# Placeholder macro written by tools/chip_assembly/macros.py
# kind: collective; the die assembly's one-shot collective engine block (0.9 x 0.4424 mm) at 1/4; records of 32 x CL_LANES + 3 + CL_TAGW = 547 bits (ot_chip_v41x_die CL_PW), 512-bit link flits
VERSION 5.7 ;
BUSBITCHARS "[]" ;
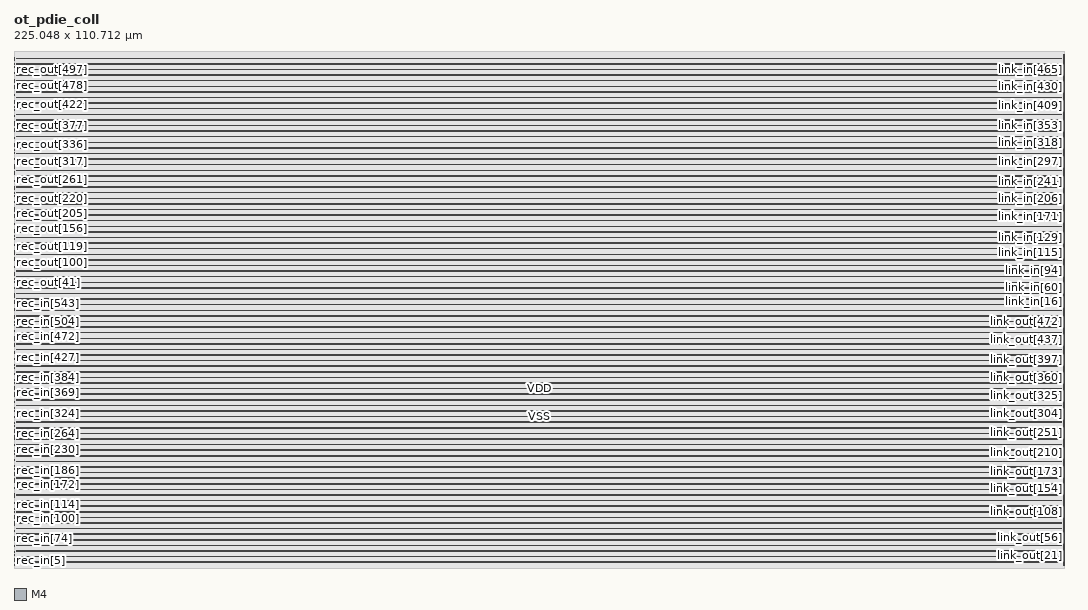
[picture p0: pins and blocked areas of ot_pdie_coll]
MACRO ot_pdie_coll
  FOREIGN ot_pdie_coll 0 0 ;
  SYMMETRY X Y ;
  SIZE 225.048 BY 110.712 ;
  CLASS BLOCK ;
  PIN clk
    DIRECTION INPUT ;
    USE SIGNAL ;
    SHAPE ABUTMENT ;
    PORT
      LAYER M4 ;
      RECT 0.000 0.528 0.192 0.552 ;
    END
  END clk
  PIN rec_in[0]
    DIRECTION INPUT ;
    USE SIGNAL ;
    SHAPE ABUTMENT ;
    PORT
      LAYER M4 ;
      RECT 0.000 0.624 0.192 0.648 ;
    END
  END rec_in[0]
  PIN rec_in[1]
    DIRECTION INPUT ;
    USE SIGNAL ;
    SHAPE ABUTMENT ;
    PORT
      LAYER M4 ;
      RECT 0.000 0.720 0.192 0.744 ;
    END
  END rec_in[1]
  PIN rec_in[2]
    DIRECTION INPUT ;
    USE SIGNAL ;
    SHAPE ABUTMENT ;
    PORT
      LAYER M4 ;
      RECT 0.000 0.816 0.192 0.840 ;
    END
  END rec_in[2]
  PIN rec_in[3]
    DIRECTION INPUT ;
    USE SIGNAL ;
    SHAPE ABUTMENT ;
    PORT
      LAYER M4 ;
      RECT 0.000 0.912 0.192 0.936 ;
    END
  END rec_in[3]
  PIN rec_in[4]
    DIRECTION INPUT ;
    USE SIGNAL ;
    SHAPE ABUTMENT ;
    PORT
      LAYER M4 ;
      RECT 0.000 1.008 0.192 1.032 ;
    END
  END rec_in[4]
  PIN rec_in[5]
    DIRECTION INPUT ;
    USE SIGNAL ;
    SHAPE ABUTMENT ;
    PORT
      LAYER M4 ;
      RECT 0.000 1.104 0.192 1.128 ;
    END
  END rec_in[5]
  PIN rec_in[6]
    DIRECTION INPUT ;
    USE SIGNAL ;
    SHAPE ABUTMENT ;
    PORT
      LAYER M4 ;
      RECT 0.000 1.200 0.192 1.224 ;
    END
  END rec_in[6]
  PIN rec_in[7]
    DIRECTION INPUT ;
    USE SIGNAL ;
    SHAPE ABUTMENT ;
    PORT
      LAYER M4 ;
      RECT 0.000 1.296 0.192 1.320 ;
    END
  END rec_in[7]
  PIN rec_in[8]
    DIRECTION INPUT ;
    USE SIGNAL ;
    SHAPE ABUTMENT ;
    PORT
      LAYER M4 ;
      RECT 0.000 1.392 0.192 1.416 ;
    END
  END rec_in[8]
  PIN rec_in[9]
    DIRECTION INPUT ;
    USE SIGNAL ;
    SHAPE ABUTMENT ;
    PORT
      LAYER M4 ;
      RECT 0.000 1.488 0.192 1.512 ;
    END
  END rec_in[9]
  PIN rec_in[10]
    DIRECTION INPUT ;
    USE SIGNAL ;
    SHAPE ABUTMENT ;
    PORT
      LAYER M4 ;
      RECT 0.000 1.584 0.192 1.608 ;
    END
  END rec_in[10]
  PIN rec_in[11]
    DIRECTION INPUT ;
    USE SIGNAL ;
    SHAPE ABUTMENT ;
    PORT
      LAYER M4 ;
      RECT 0.000 1.728 0.192 1.752 ;
    END
  END rec_in[11]
  PIN rec_in[12]
    DIRECTION INPUT ;
    USE SIGNAL ;
    SHAPE ABUTMENT ;
    PORT
      LAYER M4 ;
      RECT 0.000 1.824 0.192 1.848 ;
    END
  END rec_in[12]
  PIN rec_in[13]
    DIRECTION INPUT ;
    USE SIGNAL ;
    SHAPE ABUTMENT ;
    PORT
      LAYER M4 ;
      RECT 0.000 1.920 0.192 1.944 ;
    END
  END rec_in[13]
  PIN rec_in[14]
    DIRECTION INPUT ;
    USE SIGNAL ;
    SHAPE ABUTMENT ;
    PORT
      LAYER M4 ;
      RECT 0.000 2.016 0.192 2.040 ;
    END
  END rec_in[14]
  PIN rec_in[15]
    DIRECTION INPUT ;
    USE SIGNAL ;
    SHAPE ABUTMENT ;
    PORT
      LAYER M4 ;
      RECT 0.000 2.112 0.192 2.136 ;
    END
  END rec_in[15]
  PIN rec_in[16]
    DIRECTION INPUT ;
    USE SIGNAL ;
    SHAPE ABUTMENT ;
    PORT
      LAYER M4 ;
      RECT 0.000 2.208 0.192 2.232 ;
    END
  END rec_in[16]
  PIN rec_in[17]
    DIRECTION INPUT ;
    USE SIGNAL ;
    SHAPE ABUTMENT ;
    PORT
      LAYER M4 ;
      RECT 0.000 2.304 0.192 2.328 ;
    END
  END rec_in[17]
  PIN rec_in[18]
    DIRECTION INPUT ;
    USE SIGNAL ;
    SHAPE ABUTMENT ;
    PORT
      LAYER M4 ;
      RECT 0.000 2.400 0.192 2.424 ;
    END
  END rec_in[18]
  PIN rec_in[19]
    DIRECTION INPUT ;
    USE SIGNAL ;
    SHAPE ABUTMENT ;
    PORT
      LAYER M4 ;
      RECT 0.000 2.496 0.192 2.520 ;
    END
  END rec_in[19]
  PIN rec_in[20]
    DIRECTION INPUT ;
    USE SIGNAL ;
    SHAPE ABUTMENT ;
    PORT
      LAYER M4 ;
      RECT 0.000 2.592 0.192 2.616 ;
    END
  END rec_in[20]
  PIN rec_in[21]
    DIRECTION INPUT ;
    USE SIGNAL ;
    SHAPE ABUTMENT ;
    PORT
      LAYER M4 ;
      RECT 0.000 2.688 0.192 2.712 ;
    END
  END rec_in[21]
  PIN rec_in[22]
    DIRECTION INPUT ;
    USE SIGNAL ;
    SHAPE ABUTMENT ;
    PORT
      LAYER M4 ;
      RECT 0.000 2.784 0.192 2.808 ;
    END
  END rec_in[22]
  PIN rec_in[23]
    DIRECTION INPUT ;
    USE SIGNAL ;
    SHAPE ABUTMENT ;
    PORT
      LAYER M4 ;
      RECT 0.000 2.928 0.192 2.952 ;
    END
  END rec_in[23]
  PIN rec_in[24]
    DIRECTION INPUT ;
    USE SIGNAL ;
    SHAPE ABUTMENT ;
    PORT
      LAYER M4 ;
      RECT 0.000 3.024 0.192 3.048 ;
    END
  END rec_in[24]
  PIN rec_in[25]
    DIRECTION INPUT ;
    USE SIGNAL ;
    SHAPE ABUTMENT ;
    PORT
      LAYER M4 ;
      RECT 0.000 3.120 0.192 3.144 ;
    END
  END rec_in[25]
  PIN rec_in[26]
    DIRECTION INPUT ;
    USE SIGNAL ;
    SHAPE ABUTMENT ;
    PORT
      LAYER M4 ;
      RECT 0.000 3.216 0.192 3.240 ;
    END
  END rec_in[26]
  PIN rec_in[27]
    DIRECTION INPUT ;
    USE SIGNAL ;
    SHAPE ABUTMENT ;
    PORT
      LAYER M4 ;
      RECT 0.000 3.312 0.192 3.336 ;
    END
  END rec_in[27]
  PIN rec_in[28]
    DIRECTION INPUT ;
    USE SIGNAL ;
    SHAPE ABUTMENT ;
    PORT
      LAYER M4 ;
      RECT 0.000 3.408 0.192 3.432 ;
    END
  END rec_in[28]
  PIN rec_in[29]
    DIRECTION INPUT ;
    USE SIGNAL ;
    SHAPE ABUTMENT ;
    PORT
      LAYER M4 ;
      RECT 0.000 3.504 0.192 3.528 ;
    END
  END rec_in[29]
  PIN rec_in[30]
    DIRECTION INPUT ;
    USE SIGNAL ;
    SHAPE ABUTMENT ;
    PORT
      LAYER M4 ;
      RECT 0.000 3.600 0.192 3.624 ;
    END
  END rec_in[30]
  PIN rec_in[31]
    DIRECTION INPUT ;
    USE SIGNAL ;
    SHAPE ABUTMENT ;
    PORT
      LAYER M4 ;
      RECT 0.000 3.696 0.192 3.720 ;
    END
  END rec_in[31]
  PIN rec_in[32]
    DIRECTION INPUT ;
    USE SIGNAL ;
    SHAPE ABUTMENT ;
    PORT
      LAYER M4 ;
      RECT 0.000 3.792 0.192 3.816 ;
    END
  END rec_in[32]
  PIN rec_in[33]
    DIRECTION INPUT ;
    USE SIGNAL ;
    SHAPE ABUTMENT ;
    PORT
      LAYER M4 ;
      RECT 0.000 3.888 0.192 3.912 ;
    END
  END rec_in[33]
  PIN rec_in[34]
    DIRECTION INPUT ;
    USE SIGNAL ;
    SHAPE ABUTMENT ;
    PORT
      LAYER M4 ;
      RECT 0.000 4.032 0.192 4.056 ;
    END
  END rec_in[34]
  PIN rec_in[35]
    DIRECTION INPUT ;
    USE SIGNAL ;
    SHAPE ABUTMENT ;
    PORT
      LAYER M4 ;
      RECT 0.000 4.128 0.192 4.152 ;
    END
  END rec_in[35]
  PIN rec_in[36]
    DIRECTION INPUT ;
    USE SIGNAL ;
    SHAPE ABUTMENT ;
    PORT
      LAYER M4 ;
      RECT 0.000 4.224 0.192 4.248 ;
    END
  END rec_in[36]
  PIN rec_in[37]
    DIRECTION INPUT ;
    USE SIGNAL ;
    SHAPE ABUTMENT ;
    PORT
      LAYER M4 ;
      RECT 0.000 4.320 0.192 4.344 ;
    END
  END rec_in[37]
  PIN rec_in[38]
    DIRECTION INPUT ;
    USE SIGNAL ;
    SHAPE ABUTMENT ;
    PORT
      LAYER M4 ;
      RECT 0.000 4.416 0.192 4.440 ;
    END
  END rec_in[38]
  PIN rec_in[39]
    DIRECTION INPUT ;
    USE SIGNAL ;
    SHAPE ABUTMENT ;
    PORT
      LAYER M4 ;
      RECT 0.000 4.512 0.192 4.536 ;
    END
  END rec_in[39]
  PIN rec_in[40]
    DIRECTION INPUT ;
    USE SIGNAL ;
    SHAPE ABUTMENT ;
    PORT
      LAYER M4 ;
      RECT 0.000 4.608 0.192 4.632 ;
    END
  END rec_in[40]
  PIN rec_in[41]
    DIRECTION INPUT ;
    USE SIGNAL ;
    SHAPE ABUTMENT ;
    PORT
      LAYER M4 ;
      RECT 0.000 4.704 0.192 4.728 ;
    END
  END rec_in[41]
  PIN rec_in[42]
    DIRECTION INPUT ;
    USE SIGNAL ;
    SHAPE ABUTMENT ;
    PORT
      LAYER M4 ;
      RECT 0.000 4.800 0.192 4.824 ;
    END
  END rec_in[42]
  PIN rec_in[43]
    DIRECTION INPUT ;
    USE SIGNAL ;
    SHAPE ABUTMENT ;
    PORT
      LAYER M4 ;
      RECT 0.000 4.896 0.192 4.920 ;
    END
  END rec_in[43]
  PIN rec_in[44]
    DIRECTION INPUT ;
    USE SIGNAL ;
    SHAPE ABUTMENT ;
    PORT
      LAYER M4 ;
      RECT 0.000 4.992 0.192 5.016 ;
    END
  END rec_in[44]
  PIN rec_in[45]
    DIRECTION INPUT ;
    USE SIGNAL ;
    SHAPE ABUTMENT ;
    PORT
      LAYER M4 ;
      RECT 0.000 5.088 0.192 5.112 ;
    END
  END rec_in[45]
  PIN rec_in[46]
    DIRECTION INPUT ;
    USE SIGNAL ;
    SHAPE ABUTMENT ;
    PORT
      LAYER M4 ;
      RECT 0.000 5.232 0.192 5.256 ;
    END
  END rec_in[46]
  PIN rec_in[47]
    DIRECTION INPUT ;
    USE SIGNAL ;
    SHAPE ABUTMENT ;
    PORT
      LAYER M4 ;
      RECT 0.000 5.328 0.192 5.352 ;
    END
  END rec_in[47]
  PIN rec_in[48]
    DIRECTION INPUT ;
    USE SIGNAL ;
    SHAPE ABUTMENT ;
    PORT
      LAYER M4 ;
      RECT 0.000 5.424 0.192 5.448 ;
    END
  END rec_in[48]
  PIN rec_in[49]
    DIRECTION INPUT ;
    USE SIGNAL ;
    SHAPE ABUTMENT ;
    PORT
      LAYER M4 ;
      RECT 0.000 5.520 0.192 5.544 ;
    END
  END rec_in[49]
  PIN rec_in[50]
    DIRECTION INPUT ;
    USE SIGNAL ;
    SHAPE ABUTMENT ;
    PORT
      LAYER M4 ;
      RECT 0.000 5.616 0.192 5.640 ;
    END
  END rec_in[50]
  PIN rec_in[51]
    DIRECTION INPUT ;
    USE SIGNAL ;
    SHAPE ABUTMENT ;
    PORT
      LAYER M4 ;
      RECT 0.000 5.712 0.192 5.736 ;
    END
  END rec_in[51]
  PIN rec_in[52]
    DIRECTION INPUT ;
    USE SIGNAL ;
    SHAPE ABUTMENT ;
    PORT
      LAYER M4 ;
      RECT 0.000 5.808 0.192 5.832 ;
    END
  END rec_in[52]
  PIN rec_in[53]
    DIRECTION INPUT ;
    USE SIGNAL ;
    SHAPE ABUTMENT ;
    PORT
      LAYER M4 ;
      RECT 0.000 5.904 0.192 5.928 ;
    END
  END rec_in[53]
  PIN rec_in[54]
    DIRECTION INPUT ;
    USE SIGNAL ;
    SHAPE ABUTMENT ;
    PORT
      LAYER M4 ;
      RECT 0.000 6.000 0.192 6.024 ;
    END
  END rec_in[54]
  PIN rec_in[55]
    DIRECTION INPUT ;
    USE SIGNAL ;
    SHAPE ABUTMENT ;
    PORT
      LAYER M4 ;
      RECT 0.000 6.096 0.192 6.120 ;
    END
  END rec_in[55]
  PIN rec_in[56]
    DIRECTION INPUT ;
    USE SIGNAL ;
    SHAPE ABUTMENT ;
    PORT
      LAYER M4 ;
      RECT 0.000 6.192 0.192 6.216 ;
    END
  END rec_in[56]
  PIN rec_in[57]
    DIRECTION INPUT ;
    USE SIGNAL ;
    SHAPE ABUTMENT ;
    PORT
      LAYER M4 ;
      RECT 0.000 6.336 0.192 6.360 ;
    END
  END rec_in[57]
  PIN rec_in[58]
    DIRECTION INPUT ;
    USE SIGNAL ;
    SHAPE ABUTMENT ;
    PORT
      LAYER M4 ;
      RECT 0.000 6.432 0.192 6.456 ;
    END
  END rec_in[58]
  PIN rec_in[59]
    DIRECTION INPUT ;
    USE SIGNAL ;
    SHAPE ABUTMENT ;
    PORT
      LAYER M4 ;
      RECT 0.000 6.528 0.192 6.552 ;
    END
  END rec_in[59]
  PIN rec_in[60]
    DIRECTION INPUT ;
    USE SIGNAL ;
    SHAPE ABUTMENT ;
    PORT
      LAYER M4 ;
      RECT 0.000 6.624 0.192 6.648 ;
    END
  END rec_in[60]
  PIN rec_in[61]
    DIRECTION INPUT ;
    USE SIGNAL ;
    SHAPE ABUTMENT ;
    PORT
      LAYER M4 ;
      RECT 0.000 6.720 0.192 6.744 ;
    END
  END rec_in[61]
  PIN rec_in[62]
    DIRECTION INPUT ;
    USE SIGNAL ;
    SHAPE ABUTMENT ;
    PORT
      LAYER M4 ;
      RECT 0.000 6.816 0.192 6.840 ;
    END
  END rec_in[62]
  PIN rec_in[63]
    DIRECTION INPUT ;
    USE SIGNAL ;
    SHAPE ABUTMENT ;
    PORT
      LAYER M4 ;
      RECT 0.000 6.912 0.192 6.936 ;
    END
  END rec_in[63]
  PIN rec_in[64]
    DIRECTION INPUT ;
    USE SIGNAL ;
    SHAPE ABUTMENT ;
    PORT
      LAYER M4 ;
      RECT 0.000 7.008 0.192 7.032 ;
    END
  END rec_in[64]
  PIN rec_in[65]
    DIRECTION INPUT ;
    USE SIGNAL ;
    SHAPE ABUTMENT ;
    PORT
      LAYER M4 ;
      RECT 0.000 7.104 0.192 7.128 ;
    END
  END rec_in[65]
  PIN rec_in[66]
    DIRECTION INPUT ;
    USE SIGNAL ;
    SHAPE ABUTMENT ;
    PORT
      LAYER M4 ;
      RECT 0.000 7.200 0.192 7.224 ;
    END
  END rec_in[66]
  PIN rec_in[67]
    DIRECTION INPUT ;
    USE SIGNAL ;
    SHAPE ABUTMENT ;
    PORT
      LAYER M4 ;
      RECT 0.000 7.296 0.192 7.320 ;
    END
  END rec_in[67]
  PIN rec_in[68]
    DIRECTION INPUT ;
    USE SIGNAL ;
    SHAPE ABUTMENT ;
    PORT
      LAYER M4 ;
      RECT 0.000 7.392 0.192 7.416 ;
    END
  END rec_in[68]
  PIN rec_in[69]
    DIRECTION INPUT ;
    USE SIGNAL ;
    SHAPE ABUTMENT ;
    PORT
      LAYER M4 ;
      RECT 0.000 7.536 0.192 7.560 ;
    END
  END rec_in[69]
  PIN rec_in[70]
    DIRECTION INPUT ;
    USE SIGNAL ;
    SHAPE ABUTMENT ;
    PORT
      LAYER M4 ;
      RECT 0.000 7.632 0.192 7.656 ;
    END
  END rec_in[70]
  PIN rec_in[71]
    DIRECTION INPUT ;
    USE SIGNAL ;
    SHAPE ABUTMENT ;
    PORT
      LAYER M4 ;
      RECT 0.000 7.728 0.192 7.752 ;
    END
  END rec_in[71]
  PIN rec_in[72]
    DIRECTION INPUT ;
    USE SIGNAL ;
    SHAPE ABUTMENT ;
    PORT
      LAYER M4 ;
      RECT 0.000 7.824 0.192 7.848 ;
    END
  END rec_in[72]
  PIN rec_in[73]
    DIRECTION INPUT ;
    USE SIGNAL ;
    SHAPE ABUTMENT ;
    PORT
      LAYER M4 ;
      RECT 0.000 7.920 0.192 7.944 ;
    END
  END rec_in[73]
  PIN rec_in[74]
    DIRECTION INPUT ;
    USE SIGNAL ;
    SHAPE ABUTMENT ;
    PORT
      LAYER M4 ;
      RECT 0.000 8.016 0.192 8.040 ;
    END
  END rec_in[74]
  PIN rec_in[75]
    DIRECTION INPUT ;
    USE SIGNAL ;
    SHAPE ABUTMENT ;
    PORT
      LAYER M4 ;
      RECT 0.000 8.112 0.192 8.136 ;
    END
  END rec_in[75]
  PIN rec_in[76]
    DIRECTION INPUT ;
    USE SIGNAL ;
    SHAPE ABUTMENT ;
    PORT
      LAYER M4 ;
      RECT 0.000 8.208 0.192 8.232 ;
    END
  END rec_in[76]
  PIN rec_in[77]
    DIRECTION INPUT ;
    USE SIGNAL ;
    SHAPE ABUTMENT ;
    PORT
      LAYER M4 ;
      RECT 0.000 8.304 0.192 8.328 ;
    END
  END rec_in[77]
  PIN rec_in[78]
    DIRECTION INPUT ;
    USE SIGNAL ;
    SHAPE ABUTMENT ;
    PORT
      LAYER M4 ;
      RECT 0.000 8.400 0.192 8.424 ;
    END
  END rec_in[78]
  PIN rec_in[79]
    DIRECTION INPUT ;
    USE SIGNAL ;
    SHAPE ABUTMENT ;
    PORT
      LAYER M4 ;
      RECT 0.000 8.496 0.192 8.520 ;
    END
  END rec_in[79]
  PIN rec_in[80]
    DIRECTION INPUT ;
    USE SIGNAL ;
    SHAPE ABUTMENT ;
    PORT
      LAYER M4 ;
      RECT 0.000 8.640 0.192 8.664 ;
    END
  END rec_in[80]
  PIN rec_in[81]
    DIRECTION INPUT ;
    USE SIGNAL ;
    SHAPE ABUTMENT ;
    PORT
      LAYER M4 ;
      RECT 0.000 8.736 0.192 8.760 ;
    END
  END rec_in[81]
  PIN rec_in[82]
    DIRECTION INPUT ;
    USE SIGNAL ;
    SHAPE ABUTMENT ;
    PORT
      LAYER M4 ;
      RECT 0.000 8.832 0.192 8.856 ;
    END
  END rec_in[82]
  PIN rec_in[83]
    DIRECTION INPUT ;
    USE SIGNAL ;
    SHAPE ABUTMENT ;
    PORT
      LAYER M4 ;
      RECT 0.000 8.928 0.192 8.952 ;
    END
  END rec_in[83]
  PIN rec_in[84]
    DIRECTION INPUT ;
    USE SIGNAL ;
    SHAPE ABUTMENT ;
    PORT
      LAYER M4 ;
      RECT 0.000 9.024 0.192 9.048 ;
    END
  END rec_in[84]
  PIN rec_in[85]
    DIRECTION INPUT ;
    USE SIGNAL ;
    SHAPE ABUTMENT ;
    PORT
      LAYER M4 ;
      RECT 0.000 9.120 0.192 9.144 ;
    END
  END rec_in[85]
  PIN rec_in[86]
    DIRECTION INPUT ;
    USE SIGNAL ;
    SHAPE ABUTMENT ;
    PORT
      LAYER M4 ;
      RECT 0.000 9.216 0.192 9.240 ;
    END
  END rec_in[86]
  PIN rec_in[87]
    DIRECTION INPUT ;
    USE SIGNAL ;
    SHAPE ABUTMENT ;
    PORT
      LAYER M4 ;
      RECT 0.000 9.312 0.192 9.336 ;
    END
  END rec_in[87]
  PIN rec_in[88]
    DIRECTION INPUT ;
    USE SIGNAL ;
    SHAPE ABUTMENT ;
    PORT
      LAYER M4 ;
      RECT 0.000 9.408 0.192 9.432 ;
    END
  END rec_in[88]
  PIN rec_in[89]
    DIRECTION INPUT ;
    USE SIGNAL ;
    SHAPE ABUTMENT ;
    PORT
      LAYER M4 ;
      RECT 0.000 9.504 0.192 9.528 ;
    END
  END rec_in[89]
  PIN rec_in[90]
    DIRECTION INPUT ;
    USE SIGNAL ;
    SHAPE ABUTMENT ;
    PORT
      LAYER M4 ;
      RECT 0.000 9.600 0.192 9.624 ;
    END
  END rec_in[90]
  PIN rec_in[91]
    DIRECTION INPUT ;
    USE SIGNAL ;
    SHAPE ABUTMENT ;
    PORT
      LAYER M4 ;
      RECT 0.000 9.696 0.192 9.720 ;
    END
  END rec_in[91]
  PIN rec_in[92]
    DIRECTION INPUT ;
    USE SIGNAL ;
    SHAPE ABUTMENT ;
    PORT
      LAYER M4 ;
      RECT 0.000 9.840 0.192 9.864 ;
    END
  END rec_in[92]
  PIN rec_in[93]
    DIRECTION INPUT ;
    USE SIGNAL ;
    SHAPE ABUTMENT ;
    PORT
      LAYER M4 ;
      RECT 0.000 9.936 0.192 9.960 ;
    END
  END rec_in[93]
  PIN rec_in[94]
    DIRECTION INPUT ;
    USE SIGNAL ;
    SHAPE ABUTMENT ;
    PORT
      LAYER M4 ;
      RECT 0.000 10.032 0.192 10.056 ;
    END
  END rec_in[94]
  PIN rec_in[95]
    DIRECTION INPUT ;
    USE SIGNAL ;
    SHAPE ABUTMENT ;
    PORT
      LAYER M4 ;
      RECT 0.000 10.128 0.192 10.152 ;
    END
  END rec_in[95]
  PIN rec_in[96]
    DIRECTION INPUT ;
    USE SIGNAL ;
    SHAPE ABUTMENT ;
    PORT
      LAYER M4 ;
      RECT 0.000 10.224 0.192 10.248 ;
    END
  END rec_in[96]
  PIN rec_in[97]
    DIRECTION INPUT ;
    USE SIGNAL ;
    SHAPE ABUTMENT ;
    PORT
      LAYER M4 ;
      RECT 0.000 10.320 0.192 10.344 ;
    END
  END rec_in[97]
  PIN rec_in[98]
    DIRECTION INPUT ;
    USE SIGNAL ;
    SHAPE ABUTMENT ;
    PORT
      LAYER M4 ;
      RECT 0.000 10.416 0.192 10.440 ;
    END
  END rec_in[98]
  PIN rec_in[99]
    DIRECTION INPUT ;
    USE SIGNAL ;
    SHAPE ABUTMENT ;
    PORT
      LAYER M4 ;
      RECT 0.000 10.512 0.192 10.536 ;
    END
  END rec_in[99]
  PIN rec_in[100]
    DIRECTION INPUT ;
    USE SIGNAL ;
    SHAPE ABUTMENT ;
    PORT
      LAYER M4 ;
      RECT 0.000 10.608 0.192 10.632 ;
    END
  END rec_in[100]
  PIN rec_in[101]
    DIRECTION INPUT ;
    USE SIGNAL ;
    SHAPE ABUTMENT ;
    PORT
      LAYER M4 ;
      RECT 0.000 10.704 0.192 10.728 ;
    END
  END rec_in[101]
  PIN rec_in[102]
    DIRECTION INPUT ;
    USE SIGNAL ;
    SHAPE ABUTMENT ;
    PORT
      LAYER M4 ;
      RECT 0.000 10.800 0.192 10.824 ;
    END
  END rec_in[102]
  PIN rec_in[103]
    DIRECTION INPUT ;
    USE SIGNAL ;
    SHAPE ABUTMENT ;
    PORT
      LAYER M4 ;
      RECT 0.000 10.944 0.192 10.968 ;
    END
  END rec_in[103]
  PIN rec_in[104]
    DIRECTION INPUT ;
    USE SIGNAL ;
    SHAPE ABUTMENT ;
    PORT
      LAYER M4 ;
      RECT 0.000 11.040 0.192 11.064 ;
    END
  END rec_in[104]
  PIN rec_in[105]
    DIRECTION INPUT ;
    USE SIGNAL ;
    SHAPE ABUTMENT ;
    PORT
      LAYER M4 ;
      RECT 0.000 11.136 0.192 11.160 ;
    END
  END rec_in[105]
  PIN rec_in[106]
    DIRECTION INPUT ;
    USE SIGNAL ;
    SHAPE ABUTMENT ;
    PORT
      LAYER M4 ;
      RECT 0.000 11.232 0.192 11.256 ;
    END
  END rec_in[106]
  PIN rec_in[107]
    DIRECTION INPUT ;
    USE SIGNAL ;
    SHAPE ABUTMENT ;
    PORT
      LAYER M4 ;
      RECT 0.000 11.328 0.192 11.352 ;
    END
  END rec_in[107]
  PIN rec_in[108]
    DIRECTION INPUT ;
    USE SIGNAL ;
    SHAPE ABUTMENT ;
    PORT
      LAYER M4 ;
      RECT 0.000 11.424 0.192 11.448 ;
    END
  END rec_in[108]
  PIN rec_in[109]
    DIRECTION INPUT ;
    USE SIGNAL ;
    SHAPE ABUTMENT ;
    PORT
      LAYER M4 ;
      RECT 0.000 11.520 0.192 11.544 ;
    END
  END rec_in[109]
  PIN rec_in[110]
    DIRECTION INPUT ;
    USE SIGNAL ;
    SHAPE ABUTMENT ;
    PORT
      LAYER M4 ;
      RECT 0.000 11.616 0.192 11.640 ;
    END
  END rec_in[110]
  PIN rec_in[111]
    DIRECTION INPUT ;
    USE SIGNAL ;
    SHAPE ABUTMENT ;
    PORT
      LAYER M4 ;
      RECT 0.000 11.712 0.192 11.736 ;
    END
  END rec_in[111]
  PIN rec_in[112]
    DIRECTION INPUT ;
    USE SIGNAL ;
    SHAPE ABUTMENT ;
    PORT
      LAYER M4 ;
      RECT 0.000 11.808 0.192 11.832 ;
    END
  END rec_in[112]
  PIN rec_in[113]
    DIRECTION INPUT ;
    USE SIGNAL ;
    SHAPE ABUTMENT ;
    PORT
      LAYER M4 ;
      RECT 0.000 11.904 0.192 11.928 ;
    END
  END rec_in[113]
  PIN rec_in[114]
    DIRECTION INPUT ;
    USE SIGNAL ;
    SHAPE ABUTMENT ;
    PORT
      LAYER M4 ;
      RECT 0.000 12.000 0.192 12.024 ;
    END
  END rec_in[114]
  PIN rec_in[115]
    DIRECTION INPUT ;
    USE SIGNAL ;
    SHAPE ABUTMENT ;
    PORT
      LAYER M4 ;
      RECT 0.000 12.144 0.192 12.168 ;
    END
  END rec_in[115]
  PIN rec_in[116]
    DIRECTION INPUT ;
    USE SIGNAL ;
    SHAPE ABUTMENT ;
    PORT
      LAYER M4 ;
      RECT 0.000 12.240 0.192 12.264 ;
    END
  END rec_in[116]
  PIN rec_in[117]
    DIRECTION INPUT ;
    USE SIGNAL ;
    SHAPE ABUTMENT ;
    PORT
      LAYER M4 ;
      RECT 0.000 12.336 0.192 12.360 ;
    END
  END rec_in[117]
  PIN rec_in[118]
    DIRECTION INPUT ;
    USE SIGNAL ;
    SHAPE ABUTMENT ;
    PORT
      LAYER M4 ;
      RECT 0.000 12.432 0.192 12.456 ;
    END
  END rec_in[118]
  PIN rec_in[119]
    DIRECTION INPUT ;
    USE SIGNAL ;
    SHAPE ABUTMENT ;
    PORT
      LAYER M4 ;
      RECT 0.000 12.528 0.192 12.552 ;
    END
  END rec_in[119]
  PIN rec_in[120]
    DIRECTION INPUT ;
    USE SIGNAL ;
    SHAPE ABUTMENT ;
    PORT
      LAYER M4 ;
      RECT 0.000 12.624 0.192 12.648 ;
    END
  END rec_in[120]
  PIN rec_in[121]
    DIRECTION INPUT ;
    USE SIGNAL ;
    SHAPE ABUTMENT ;
    PORT
      LAYER M4 ;
      RECT 0.000 12.720 0.192 12.744 ;
    END
  END rec_in[121]
  PIN rec_in[122]
    DIRECTION INPUT ;
    USE SIGNAL ;
    SHAPE ABUTMENT ;
    PORT
      LAYER M4 ;
      RECT 0.000 12.816 0.192 12.840 ;
    END
  END rec_in[122]
  PIN rec_in[123]
    DIRECTION INPUT ;
    USE SIGNAL ;
    SHAPE ABUTMENT ;
    PORT
      LAYER M4 ;
      RECT 0.000 12.912 0.192 12.936 ;
    END
  END rec_in[123]
  PIN rec_in[124]
    DIRECTION INPUT ;
    USE SIGNAL ;
    SHAPE ABUTMENT ;
    PORT
      LAYER M4 ;
      RECT 0.000 13.008 0.192 13.032 ;
    END
  END rec_in[124]
  PIN rec_in[125]
    DIRECTION INPUT ;
    USE SIGNAL ;
    SHAPE ABUTMENT ;
    PORT
      LAYER M4 ;
      RECT 0.000 13.104 0.192 13.128 ;
    END
  END rec_in[125]
  PIN rec_in[126]
    DIRECTION INPUT ;
    USE SIGNAL ;
    SHAPE ABUTMENT ;
    PORT
      LAYER M4 ;
      RECT 0.000 13.248 0.192 13.272 ;
    END
  END rec_in[126]
  PIN rec_in[127]
    DIRECTION INPUT ;
    USE SIGNAL ;
    SHAPE ABUTMENT ;
    PORT
      LAYER M4 ;
      RECT 0.000 13.344 0.192 13.368 ;
    END
  END rec_in[127]
  PIN rec_in[128]
    DIRECTION INPUT ;
    USE SIGNAL ;
    SHAPE ABUTMENT ;
    PORT
      LAYER M4 ;
      RECT 0.000 13.440 0.192 13.464 ;
    END
  END rec_in[128]
  PIN rec_in[129]
    DIRECTION INPUT ;
    USE SIGNAL ;
    SHAPE ABUTMENT ;
    PORT
      LAYER M4 ;
      RECT 0.000 13.536 0.192 13.560 ;
    END
  END rec_in[129]
  PIN rec_in[130]
    DIRECTION INPUT ;
    USE SIGNAL ;
    SHAPE ABUTMENT ;
    PORT
      LAYER M4 ;
      RECT 0.000 13.632 0.192 13.656 ;
    END
  END rec_in[130]
  PIN rec_in[131]
    DIRECTION INPUT ;
    USE SIGNAL ;
    SHAPE ABUTMENT ;
    PORT
      LAYER M4 ;
      RECT 0.000 13.728 0.192 13.752 ;
    END
  END rec_in[131]
  PIN rec_in[132]
    DIRECTION INPUT ;
    USE SIGNAL ;
    SHAPE ABUTMENT ;
    PORT
      LAYER M4 ;
      RECT 0.000 13.824 0.192 13.848 ;
    END
  END rec_in[132]
  PIN rec_in[133]
    DIRECTION INPUT ;
    USE SIGNAL ;
    SHAPE ABUTMENT ;
    PORT
      LAYER M4 ;
      RECT 0.000 13.920 0.192 13.944 ;
    END
  END rec_in[133]
  PIN rec_in[134]
    DIRECTION INPUT ;
    USE SIGNAL ;
    SHAPE ABUTMENT ;
    PORT
      LAYER M4 ;
      RECT 0.000 14.016 0.192 14.040 ;
    END
  END rec_in[134]
  PIN rec_in[135]
    DIRECTION INPUT ;
    USE SIGNAL ;
    SHAPE ABUTMENT ;
    PORT
      LAYER M4 ;
      RECT 0.000 14.112 0.192 14.136 ;
    END
  END rec_in[135]
  PIN rec_in[136]
    DIRECTION INPUT ;
    USE SIGNAL ;
    SHAPE ABUTMENT ;
    PORT
      LAYER M4 ;
      RECT 0.000 14.208 0.192 14.232 ;
    END
  END rec_in[136]
  PIN rec_in[137]
    DIRECTION INPUT ;
    USE SIGNAL ;
    SHAPE ABUTMENT ;
    PORT
      LAYER M4 ;
      RECT 0.000 14.304 0.192 14.328 ;
    END
  END rec_in[137]
  PIN rec_in[138]
    DIRECTION INPUT ;
    USE SIGNAL ;
    SHAPE ABUTMENT ;
    PORT
      LAYER M4 ;
      RECT 0.000 14.448 0.192 14.472 ;
    END
  END rec_in[138]
  PIN rec_in[139]
    DIRECTION INPUT ;
    USE SIGNAL ;
    SHAPE ABUTMENT ;
    PORT
      LAYER M4 ;
      RECT 0.000 14.544 0.192 14.568 ;
    END
  END rec_in[139]
  PIN rec_in[140]
    DIRECTION INPUT ;
    USE SIGNAL ;
    SHAPE ABUTMENT ;
    PORT
      LAYER M4 ;
      RECT 0.000 14.640 0.192 14.664 ;
    END
  END rec_in[140]
  PIN rec_in[141]
    DIRECTION INPUT ;
    USE SIGNAL ;
    SHAPE ABUTMENT ;
    PORT
      LAYER M4 ;
      RECT 0.000 14.736 0.192 14.760 ;
    END
  END rec_in[141]
  PIN rec_in[142]
    DIRECTION INPUT ;
    USE SIGNAL ;
    SHAPE ABUTMENT ;
    PORT
      LAYER M4 ;
      RECT 0.000 14.832 0.192 14.856 ;
    END
  END rec_in[142]
  PIN rec_in[143]
    DIRECTION INPUT ;
    USE SIGNAL ;
    SHAPE ABUTMENT ;
    PORT
      LAYER M4 ;
      RECT 0.000 14.928 0.192 14.952 ;
    END
  END rec_in[143]
  PIN rec_in[144]
    DIRECTION INPUT ;
    USE SIGNAL ;
    SHAPE ABUTMENT ;
    PORT
      LAYER M4 ;
      RECT 0.000 15.024 0.192 15.048 ;
    END
  END rec_in[144]
  PIN rec_in[145]
    DIRECTION INPUT ;
    USE SIGNAL ;
    SHAPE ABUTMENT ;
    PORT
      LAYER M4 ;
      RECT 0.000 15.120 0.192 15.144 ;
    END
  END rec_in[145]
  PIN rec_in[146]
    DIRECTION INPUT ;
    USE SIGNAL ;
    SHAPE ABUTMENT ;
    PORT
      LAYER M4 ;
      RECT 0.000 15.216 0.192 15.240 ;
    END
  END rec_in[146]
  PIN rec_in[147]
    DIRECTION INPUT ;
    USE SIGNAL ;
    SHAPE ABUTMENT ;
    PORT
      LAYER M4 ;
      RECT 0.000 15.312 0.192 15.336 ;
    END
  END rec_in[147]
  PIN rec_in[148]
    DIRECTION INPUT ;
    USE SIGNAL ;
    SHAPE ABUTMENT ;
    PORT
      LAYER M4 ;
      RECT 0.000 15.408 0.192 15.432 ;
    END
  END rec_in[148]
  PIN rec_in[149]
    DIRECTION INPUT ;
    USE SIGNAL ;
    SHAPE ABUTMENT ;
    PORT
      LAYER M4 ;
      RECT 0.000 15.552 0.192 15.576 ;
    END
  END rec_in[149]
  PIN rec_in[150]
    DIRECTION INPUT ;
    USE SIGNAL ;
    SHAPE ABUTMENT ;
    PORT
      LAYER M4 ;
      RECT 0.000 15.648 0.192 15.672 ;
    END
  END rec_in[150]
  PIN rec_in[151]
    DIRECTION INPUT ;
    USE SIGNAL ;
    SHAPE ABUTMENT ;
    PORT
      LAYER M4 ;
      RECT 0.000 15.744 0.192 15.768 ;
    END
  END rec_in[151]
  PIN rec_in[152]
    DIRECTION INPUT ;
    USE SIGNAL ;
    SHAPE ABUTMENT ;
    PORT
      LAYER M4 ;
      RECT 0.000 15.840 0.192 15.864 ;
    END
  END rec_in[152]
  PIN rec_in[153]
    DIRECTION INPUT ;
    USE SIGNAL ;
    SHAPE ABUTMENT ;
    PORT
      LAYER M4 ;
      RECT 0.000 15.936 0.192 15.960 ;
    END
  END rec_in[153]
  PIN rec_in[154]
    DIRECTION INPUT ;
    USE SIGNAL ;
    SHAPE ABUTMENT ;
    PORT
      LAYER M4 ;
      RECT 0.000 16.032 0.192 16.056 ;
    END
  END rec_in[154]
  PIN rec_in[155]
    DIRECTION INPUT ;
    USE SIGNAL ;
    SHAPE ABUTMENT ;
    PORT
      LAYER M4 ;
      RECT 0.000 16.128 0.192 16.152 ;
    END
  END rec_in[155]
  PIN rec_in[156]
    DIRECTION INPUT ;
    USE SIGNAL ;
    SHAPE ABUTMENT ;
    PORT
      LAYER M4 ;
      RECT 0.000 16.224 0.192 16.248 ;
    END
  END rec_in[156]
  PIN rec_in[157]
    DIRECTION INPUT ;
    USE SIGNAL ;
    SHAPE ABUTMENT ;
    PORT
      LAYER M4 ;
      RECT 0.000 16.320 0.192 16.344 ;
    END
  END rec_in[157]
  PIN rec_in[158]
    DIRECTION INPUT ;
    USE SIGNAL ;
    SHAPE ABUTMENT ;
    PORT
      LAYER M4 ;
      RECT 0.000 16.416 0.192 16.440 ;
    END
  END rec_in[158]
  PIN rec_in[159]
    DIRECTION INPUT ;
    USE SIGNAL ;
    SHAPE ABUTMENT ;
    PORT
      LAYER M4 ;
      RECT 0.000 16.512 0.192 16.536 ;
    END
  END rec_in[159]
  PIN rec_in[160]
    DIRECTION INPUT ;
    USE SIGNAL ;
    SHAPE ABUTMENT ;
    PORT
      LAYER M4 ;
      RECT 0.000 16.608 0.192 16.632 ;
    END
  END rec_in[160]
  PIN rec_in[161]
    DIRECTION INPUT ;
    USE SIGNAL ;
    SHAPE ABUTMENT ;
    PORT
      LAYER M4 ;
      RECT 0.000 16.752 0.192 16.776 ;
    END
  END rec_in[161]
  PIN rec_in[162]
    DIRECTION INPUT ;
    USE SIGNAL ;
    SHAPE ABUTMENT ;
    PORT
      LAYER M4 ;
      RECT 0.000 16.848 0.192 16.872 ;
    END
  END rec_in[162]
  PIN rec_in[163]
    DIRECTION INPUT ;
    USE SIGNAL ;
    SHAPE ABUTMENT ;
    PORT
      LAYER M4 ;
      RECT 0.000 16.944 0.192 16.968 ;
    END
  END rec_in[163]
  PIN rec_in[164]
    DIRECTION INPUT ;
    USE SIGNAL ;
    SHAPE ABUTMENT ;
    PORT
      LAYER M4 ;
      RECT 0.000 17.040 0.192 17.064 ;
    END
  END rec_in[164]
  PIN rec_in[165]
    DIRECTION INPUT ;
    USE SIGNAL ;
    SHAPE ABUTMENT ;
    PORT
      LAYER M4 ;
      RECT 0.000 17.136 0.192 17.160 ;
    END
  END rec_in[165]
  PIN rec_in[166]
    DIRECTION INPUT ;
    USE SIGNAL ;
    SHAPE ABUTMENT ;
    PORT
      LAYER M4 ;
      RECT 0.000 17.232 0.192 17.256 ;
    END
  END rec_in[166]
  PIN rec_in[167]
    DIRECTION INPUT ;
    USE SIGNAL ;
    SHAPE ABUTMENT ;
    PORT
      LAYER M4 ;
      RECT 0.000 17.328 0.192 17.352 ;
    END
  END rec_in[167]
  PIN rec_in[168]
    DIRECTION INPUT ;
    USE SIGNAL ;
    SHAPE ABUTMENT ;
    PORT
      LAYER M4 ;
      RECT 0.000 17.424 0.192 17.448 ;
    END
  END rec_in[168]
  PIN rec_in[169]
    DIRECTION INPUT ;
    USE SIGNAL ;
    SHAPE ABUTMENT ;
    PORT
      LAYER M4 ;
      RECT 0.000 17.520 0.192 17.544 ;
    END
  END rec_in[169]
  PIN rec_in[170]
    DIRECTION INPUT ;
    USE SIGNAL ;
    SHAPE ABUTMENT ;
    PORT
      LAYER M4 ;
      RECT 0.000 17.616 0.192 17.640 ;
    END
  END rec_in[170]
  PIN rec_in[171]
    DIRECTION INPUT ;
    USE SIGNAL ;
    SHAPE ABUTMENT ;
    PORT
      LAYER M4 ;
      RECT 0.000 17.712 0.192 17.736 ;
    END
  END rec_in[171]
  PIN rec_in[172]
    DIRECTION INPUT ;
    USE SIGNAL ;
    SHAPE ABUTMENT ;
    PORT
      LAYER M4 ;
      RECT 0.000 17.856 0.192 17.880 ;
    END
  END rec_in[172]
  PIN rec_in[173]
    DIRECTION INPUT ;
    USE SIGNAL ;
    SHAPE ABUTMENT ;
    PORT
      LAYER M4 ;
      RECT 0.000 17.952 0.192 17.976 ;
    END
  END rec_in[173]
  PIN rec_in[174]
    DIRECTION INPUT ;
    USE SIGNAL ;
    SHAPE ABUTMENT ;
    PORT
      LAYER M4 ;
      RECT 0.000 18.048 0.192 18.072 ;
    END
  END rec_in[174]
  PIN rec_in[175]
    DIRECTION INPUT ;
    USE SIGNAL ;
    SHAPE ABUTMENT ;
    PORT
      LAYER M4 ;
      RECT 0.000 18.144 0.192 18.168 ;
    END
  END rec_in[175]
  PIN rec_in[176]
    DIRECTION INPUT ;
    USE SIGNAL ;
    SHAPE ABUTMENT ;
    PORT
      LAYER M4 ;
      RECT 0.000 18.240 0.192 18.264 ;
    END
  END rec_in[176]
  PIN rec_in[177]
    DIRECTION INPUT ;
    USE SIGNAL ;
    SHAPE ABUTMENT ;
    PORT
      LAYER M4 ;
      RECT 0.000 18.336 0.192 18.360 ;
    END
  END rec_in[177]
  PIN rec_in[178]
    DIRECTION INPUT ;
    USE SIGNAL ;
    SHAPE ABUTMENT ;
    PORT
      LAYER M4 ;
      RECT 0.000 18.432 0.192 18.456 ;
    END
  END rec_in[178]
  PIN rec_in[179]
    DIRECTION INPUT ;
    USE SIGNAL ;
    SHAPE ABUTMENT ;
    PORT
      LAYER M4 ;
      RECT 0.000 18.528 0.192 18.552 ;
    END
  END rec_in[179]
  PIN rec_in[180]
    DIRECTION INPUT ;
    USE SIGNAL ;
    SHAPE ABUTMENT ;
    PORT
      LAYER M4 ;
      RECT 0.000 18.624 0.192 18.648 ;
    END
  END rec_in[180]
  PIN rec_in[181]
    DIRECTION INPUT ;
    USE SIGNAL ;
    SHAPE ABUTMENT ;
    PORT
      LAYER M4 ;
      RECT 0.000 18.720 0.192 18.744 ;
    END
  END rec_in[181]
  PIN rec_in[182]
    DIRECTION INPUT ;
    USE SIGNAL ;
    SHAPE ABUTMENT ;
    PORT
      LAYER M4 ;
      RECT 0.000 18.816 0.192 18.840 ;
    END
  END rec_in[182]
  PIN rec_in[183]
    DIRECTION INPUT ;
    USE SIGNAL ;
    SHAPE ABUTMENT ;
    PORT
      LAYER M4 ;
      RECT 0.000 18.912 0.192 18.936 ;
    END
  END rec_in[183]
  PIN rec_in[184]
    DIRECTION INPUT ;
    USE SIGNAL ;
    SHAPE ABUTMENT ;
    PORT
      LAYER M4 ;
      RECT 0.000 19.056 0.192 19.080 ;
    END
  END rec_in[184]
  PIN rec_in[185]
    DIRECTION INPUT ;
    USE SIGNAL ;
    SHAPE ABUTMENT ;
    PORT
      LAYER M4 ;
      RECT 0.000 19.152 0.192 19.176 ;
    END
  END rec_in[185]
  PIN rec_in[186]
    DIRECTION INPUT ;
    USE SIGNAL ;
    SHAPE ABUTMENT ;
    PORT
      LAYER M4 ;
      RECT 0.000 19.248 0.192 19.272 ;
    END
  END rec_in[186]
  PIN rec_in[187]
    DIRECTION INPUT ;
    USE SIGNAL ;
    SHAPE ABUTMENT ;
    PORT
      LAYER M4 ;
      RECT 0.000 19.344 0.192 19.368 ;
    END
  END rec_in[187]
  PIN rec_in[188]
    DIRECTION INPUT ;
    USE SIGNAL ;
    SHAPE ABUTMENT ;
    PORT
      LAYER M4 ;
      RECT 0.000 19.440 0.192 19.464 ;
    END
  END rec_in[188]
  PIN rec_in[189]
    DIRECTION INPUT ;
    USE SIGNAL ;
    SHAPE ABUTMENT ;
    PORT
      LAYER M4 ;
      RECT 0.000 19.536 0.192 19.560 ;
    END
  END rec_in[189]
  PIN rec_in[190]
    DIRECTION INPUT ;
    USE SIGNAL ;
    SHAPE ABUTMENT ;
    PORT
      LAYER M4 ;
      RECT 0.000 19.632 0.192 19.656 ;
    END
  END rec_in[190]
  PIN rec_in[191]
    DIRECTION INPUT ;
    USE SIGNAL ;
    SHAPE ABUTMENT ;
    PORT
      LAYER M4 ;
      RECT 0.000 19.728 0.192 19.752 ;
    END
  END rec_in[191]
  PIN rec_in[192]
    DIRECTION INPUT ;
    USE SIGNAL ;
    SHAPE ABUTMENT ;
    PORT
      LAYER M4 ;
      RECT 0.000 19.824 0.192 19.848 ;
    END
  END rec_in[192]
  PIN rec_in[193]
    DIRECTION INPUT ;
    USE SIGNAL ;
    SHAPE ABUTMENT ;
    PORT
      LAYER M4 ;
      RECT 0.000 19.920 0.192 19.944 ;
    END
  END rec_in[193]
  PIN rec_in[194]
    DIRECTION INPUT ;
    USE SIGNAL ;
    SHAPE ABUTMENT ;
    PORT
      LAYER M4 ;
      RECT 0.000 20.016 0.192 20.040 ;
    END
  END rec_in[194]
  PIN rec_in[195]
    DIRECTION INPUT ;
    USE SIGNAL ;
    SHAPE ABUTMENT ;
    PORT
      LAYER M4 ;
      RECT 0.000 20.160 0.192 20.184 ;
    END
  END rec_in[195]
  PIN rec_in[196]
    DIRECTION INPUT ;
    USE SIGNAL ;
    SHAPE ABUTMENT ;
    PORT
      LAYER M4 ;
      RECT 0.000 20.256 0.192 20.280 ;
    END
  END rec_in[196]
  PIN rec_in[197]
    DIRECTION INPUT ;
    USE SIGNAL ;
    SHAPE ABUTMENT ;
    PORT
      LAYER M4 ;
      RECT 0.000 20.352 0.192 20.376 ;
    END
  END rec_in[197]
  PIN rec_in[198]
    DIRECTION INPUT ;
    USE SIGNAL ;
    SHAPE ABUTMENT ;
    PORT
      LAYER M4 ;
      RECT 0.000 20.448 0.192 20.472 ;
    END
  END rec_in[198]
  PIN rec_in[199]
    DIRECTION INPUT ;
    USE SIGNAL ;
    SHAPE ABUTMENT ;
    PORT
      LAYER M4 ;
      RECT 0.000 20.544 0.192 20.568 ;
    END
  END rec_in[199]
  PIN rec_in[200]
    DIRECTION INPUT ;
    USE SIGNAL ;
    SHAPE ABUTMENT ;
    PORT
      LAYER M4 ;
      RECT 0.000 20.640 0.192 20.664 ;
    END
  END rec_in[200]
  PIN rec_in[201]
    DIRECTION INPUT ;
    USE SIGNAL ;
    SHAPE ABUTMENT ;
    PORT
      LAYER M4 ;
      RECT 0.000 20.736 0.192 20.760 ;
    END
  END rec_in[201]
  PIN rec_in[202]
    DIRECTION INPUT ;
    USE SIGNAL ;
    SHAPE ABUTMENT ;
    PORT
      LAYER M4 ;
      RECT 0.000 20.832 0.192 20.856 ;
    END
  END rec_in[202]
  PIN rec_in[203]
    DIRECTION INPUT ;
    USE SIGNAL ;
    SHAPE ABUTMENT ;
    PORT
      LAYER M4 ;
      RECT 0.000 20.928 0.192 20.952 ;
    END
  END rec_in[203]
  PIN rec_in[204]
    DIRECTION INPUT ;
    USE SIGNAL ;
    SHAPE ABUTMENT ;
    PORT
      LAYER M4 ;
      RECT 0.000 21.024 0.192 21.048 ;
    END
  END rec_in[204]
  PIN rec_in[205]
    DIRECTION INPUT ;
    USE SIGNAL ;
    SHAPE ABUTMENT ;
    PORT
      LAYER M4 ;
      RECT 0.000 21.120 0.192 21.144 ;
    END
  END rec_in[205]
  PIN rec_in[206]
    DIRECTION INPUT ;
    USE SIGNAL ;
    SHAPE ABUTMENT ;
    PORT
      LAYER M4 ;
      RECT 0.000 21.216 0.192 21.240 ;
    END
  END rec_in[206]
  PIN rec_in[207]
    DIRECTION INPUT ;
    USE SIGNAL ;
    SHAPE ABUTMENT ;
    PORT
      LAYER M4 ;
      RECT 0.000 21.360 0.192 21.384 ;
    END
  END rec_in[207]
  PIN rec_in[208]
    DIRECTION INPUT ;
    USE SIGNAL ;
    SHAPE ABUTMENT ;
    PORT
      LAYER M4 ;
      RECT 0.000 21.456 0.192 21.480 ;
    END
  END rec_in[208]
  PIN rec_in[209]
    DIRECTION INPUT ;
    USE SIGNAL ;
    SHAPE ABUTMENT ;
    PORT
      LAYER M4 ;
      RECT 0.000 21.552 0.192 21.576 ;
    END
  END rec_in[209]
  PIN rec_in[210]
    DIRECTION INPUT ;
    USE SIGNAL ;
    SHAPE ABUTMENT ;
    PORT
      LAYER M4 ;
      RECT 0.000 21.648 0.192 21.672 ;
    END
  END rec_in[210]
  PIN rec_in[211]
    DIRECTION INPUT ;
    USE SIGNAL ;
    SHAPE ABUTMENT ;
    PORT
      LAYER M4 ;
      RECT 0.000 21.744 0.192 21.768 ;
    END
  END rec_in[211]
  PIN rec_in[212]
    DIRECTION INPUT ;
    USE SIGNAL ;
    SHAPE ABUTMENT ;
    PORT
      LAYER M4 ;
      RECT 0.000 21.840 0.192 21.864 ;
    END
  END rec_in[212]
  PIN rec_in[213]
    DIRECTION INPUT ;
    USE SIGNAL ;
    SHAPE ABUTMENT ;
    PORT
      LAYER M4 ;
      RECT 0.000 21.936 0.192 21.960 ;
    END
  END rec_in[213]
  PIN rec_in[214]
    DIRECTION INPUT ;
    USE SIGNAL ;
    SHAPE ABUTMENT ;
    PORT
      LAYER M4 ;
      RECT 0.000 22.032 0.192 22.056 ;
    END
  END rec_in[214]
  PIN rec_in[215]
    DIRECTION INPUT ;
    USE SIGNAL ;
    SHAPE ABUTMENT ;
    PORT
      LAYER M4 ;
      RECT 0.000 22.128 0.192 22.152 ;
    END
  END rec_in[215]
  PIN rec_in[216]
    DIRECTION INPUT ;
    USE SIGNAL ;
    SHAPE ABUTMENT ;
    PORT
      LAYER M4 ;
      RECT 0.000 22.224 0.192 22.248 ;
    END
  END rec_in[216]
  PIN rec_in[217]
    DIRECTION INPUT ;
    USE SIGNAL ;
    SHAPE ABUTMENT ;
    PORT
      LAYER M4 ;
      RECT 0.000 22.320 0.192 22.344 ;
    END
  END rec_in[217]
  PIN rec_in[218]
    DIRECTION INPUT ;
    USE SIGNAL ;
    SHAPE ABUTMENT ;
    PORT
      LAYER M4 ;
      RECT 0.000 22.464 0.192 22.488 ;
    END
  END rec_in[218]
  PIN rec_in[219]
    DIRECTION INPUT ;
    USE SIGNAL ;
    SHAPE ABUTMENT ;
    PORT
      LAYER M4 ;
      RECT 0.000 22.560 0.192 22.584 ;
    END
  END rec_in[219]
  PIN rec_in[220]
    DIRECTION INPUT ;
    USE SIGNAL ;
    SHAPE ABUTMENT ;
    PORT
      LAYER M4 ;
      RECT 0.000 22.656 0.192 22.680 ;
    END
  END rec_in[220]
  PIN rec_in[221]
    DIRECTION INPUT ;
    USE SIGNAL ;
    SHAPE ABUTMENT ;
    PORT
      LAYER M4 ;
      RECT 0.000 22.752 0.192 22.776 ;
    END
  END rec_in[221]
  PIN rec_in[222]
    DIRECTION INPUT ;
    USE SIGNAL ;
    SHAPE ABUTMENT ;
    PORT
      LAYER M4 ;
      RECT 0.000 22.848 0.192 22.872 ;
    END
  END rec_in[222]
  PIN rec_in[223]
    DIRECTION INPUT ;
    USE SIGNAL ;
    SHAPE ABUTMENT ;
    PORT
      LAYER M4 ;
      RECT 0.000 22.944 0.192 22.968 ;
    END
  END rec_in[223]
  PIN rec_in[224]
    DIRECTION INPUT ;
    USE SIGNAL ;
    SHAPE ABUTMENT ;
    PORT
      LAYER M4 ;
      RECT 0.000 23.040 0.192 23.064 ;
    END
  END rec_in[224]
  PIN rec_in[225]
    DIRECTION INPUT ;
    USE SIGNAL ;
    SHAPE ABUTMENT ;
    PORT
      LAYER M4 ;
      RECT 0.000 23.136 0.192 23.160 ;
    END
  END rec_in[225]
  PIN rec_in[226]
    DIRECTION INPUT ;
    USE SIGNAL ;
    SHAPE ABUTMENT ;
    PORT
      LAYER M4 ;
      RECT 0.000 23.232 0.192 23.256 ;
    END
  END rec_in[226]
  PIN rec_in[227]
    DIRECTION INPUT ;
    USE SIGNAL ;
    SHAPE ABUTMENT ;
    PORT
      LAYER M4 ;
      RECT 0.000 23.328 0.192 23.352 ;
    END
  END rec_in[227]
  PIN rec_in[228]
    DIRECTION INPUT ;
    USE SIGNAL ;
    SHAPE ABUTMENT ;
    PORT
      LAYER M4 ;
      RECT 0.000 23.424 0.192 23.448 ;
    END
  END rec_in[228]
  PIN rec_in[229]
    DIRECTION INPUT ;
    USE SIGNAL ;
    SHAPE ABUTMENT ;
    PORT
      LAYER M4 ;
      RECT 0.000 23.520 0.192 23.544 ;
    END
  END rec_in[229]
  PIN rec_in[230]
    DIRECTION INPUT ;
    USE SIGNAL ;
    SHAPE ABUTMENT ;
    PORT
      LAYER M4 ;
      RECT 0.000 23.664 0.192 23.688 ;
    END
  END rec_in[230]
  PIN rec_in[231]
    DIRECTION INPUT ;
    USE SIGNAL ;
    SHAPE ABUTMENT ;
    PORT
      LAYER M4 ;
      RECT 0.000 23.760 0.192 23.784 ;
    END
  END rec_in[231]
  PIN rec_in[232]
    DIRECTION INPUT ;
    USE SIGNAL ;
    SHAPE ABUTMENT ;
    PORT
      LAYER M4 ;
      RECT 0.000 23.856 0.192 23.880 ;
    END
  END rec_in[232]
  PIN rec_in[233]
    DIRECTION INPUT ;
    USE SIGNAL ;
    SHAPE ABUTMENT ;
    PORT
      LAYER M4 ;
      RECT 0.000 23.952 0.192 23.976 ;
    END
  END rec_in[233]
  PIN rec_in[234]
    DIRECTION INPUT ;
    USE SIGNAL ;
    SHAPE ABUTMENT ;
    PORT
      LAYER M4 ;
      RECT 0.000 24.048 0.192 24.072 ;
    END
  END rec_in[234]
  PIN rec_in[235]
    DIRECTION INPUT ;
    USE SIGNAL ;
    SHAPE ABUTMENT ;
    PORT
      LAYER M4 ;
      RECT 0.000 24.144 0.192 24.168 ;
    END
  END rec_in[235]
  PIN rec_in[236]
    DIRECTION INPUT ;
    USE SIGNAL ;
    SHAPE ABUTMENT ;
    PORT
      LAYER M4 ;
      RECT 0.000 24.240 0.192 24.264 ;
    END
  END rec_in[236]
  PIN rec_in[237]
    DIRECTION INPUT ;
    USE SIGNAL ;
    SHAPE ABUTMENT ;
    PORT
      LAYER M4 ;
      RECT 0.000 24.336 0.192 24.360 ;
    END
  END rec_in[237]
  PIN rec_in[238]
    DIRECTION INPUT ;
    USE SIGNAL ;
    SHAPE ABUTMENT ;
    PORT
      LAYER M4 ;
      RECT 0.000 24.432 0.192 24.456 ;
    END
  END rec_in[238]
  PIN rec_in[239]
    DIRECTION INPUT ;
    USE SIGNAL ;
    SHAPE ABUTMENT ;
    PORT
      LAYER M4 ;
      RECT 0.000 24.528 0.192 24.552 ;
    END
  END rec_in[239]
  PIN rec_in[240]
    DIRECTION INPUT ;
    USE SIGNAL ;
    SHAPE ABUTMENT ;
    PORT
      LAYER M4 ;
      RECT 0.000 24.624 0.192 24.648 ;
    END
  END rec_in[240]
  PIN rec_in[241]
    DIRECTION INPUT ;
    USE SIGNAL ;
    SHAPE ABUTMENT ;
    PORT
      LAYER M4 ;
      RECT 0.000 24.720 0.192 24.744 ;
    END
  END rec_in[241]
  PIN rec_in[242]
    DIRECTION INPUT ;
    USE SIGNAL ;
    SHAPE ABUTMENT ;
    PORT
      LAYER M4 ;
      RECT 0.000 24.864 0.192 24.888 ;
    END
  END rec_in[242]
  PIN rec_in[243]
    DIRECTION INPUT ;
    USE SIGNAL ;
    SHAPE ABUTMENT ;
    PORT
      LAYER M4 ;
      RECT 0.000 24.960 0.192 24.984 ;
    END
  END rec_in[243]
  PIN rec_in[244]
    DIRECTION INPUT ;
    USE SIGNAL ;
    SHAPE ABUTMENT ;
    PORT
      LAYER M4 ;
      RECT 0.000 25.056 0.192 25.080 ;
    END
  END rec_in[244]
  PIN rec_in[245]
    DIRECTION INPUT ;
    USE SIGNAL ;
    SHAPE ABUTMENT ;
    PORT
      LAYER M4 ;
      RECT 0.000 25.152 0.192 25.176 ;
    END
  END rec_in[245]
  PIN rec_in[246]
    DIRECTION INPUT ;
    USE SIGNAL ;
    SHAPE ABUTMENT ;
    PORT
      LAYER M4 ;
      RECT 0.000 25.248 0.192 25.272 ;
    END
  END rec_in[246]
  PIN rec_in[247]
    DIRECTION INPUT ;
    USE SIGNAL ;
    SHAPE ABUTMENT ;
    PORT
      LAYER M4 ;
      RECT 0.000 25.344 0.192 25.368 ;
    END
  END rec_in[247]
  PIN rec_in[248]
    DIRECTION INPUT ;
    USE SIGNAL ;
    SHAPE ABUTMENT ;
    PORT
      LAYER M4 ;
      RECT 0.000 25.440 0.192 25.464 ;
    END
  END rec_in[248]
  PIN rec_in[249]
    DIRECTION INPUT ;
    USE SIGNAL ;
    SHAPE ABUTMENT ;
    PORT
      LAYER M4 ;
      RECT 0.000 25.536 0.192 25.560 ;
    END
  END rec_in[249]
  PIN rec_in[250]
    DIRECTION INPUT ;
    USE SIGNAL ;
    SHAPE ABUTMENT ;
    PORT
      LAYER M4 ;
      RECT 0.000 25.632 0.192 25.656 ;
    END
  END rec_in[250]
  PIN rec_in[251]
    DIRECTION INPUT ;
    USE SIGNAL ;
    SHAPE ABUTMENT ;
    PORT
      LAYER M4 ;
      RECT 0.000 25.728 0.192 25.752 ;
    END
  END rec_in[251]
  PIN rec_in[252]
    DIRECTION INPUT ;
    USE SIGNAL ;
    SHAPE ABUTMENT ;
    PORT
      LAYER M4 ;
      RECT 0.000 25.824 0.192 25.848 ;
    END
  END rec_in[252]
  PIN rec_in[253]
    DIRECTION INPUT ;
    USE SIGNAL ;
    SHAPE ABUTMENT ;
    PORT
      LAYER M4 ;
      RECT 0.000 25.968 0.192 25.992 ;
    END
  END rec_in[253]
  PIN rec_in[254]
    DIRECTION INPUT ;
    USE SIGNAL ;
    SHAPE ABUTMENT ;
    PORT
      LAYER M4 ;
      RECT 0.000 26.064 0.192 26.088 ;
    END
  END rec_in[254]
  PIN rec_in[255]
    DIRECTION INPUT ;
    USE SIGNAL ;
    SHAPE ABUTMENT ;
    PORT
      LAYER M4 ;
      RECT 0.000 26.160 0.192 26.184 ;
    END
  END rec_in[255]
  PIN rec_in[256]
    DIRECTION INPUT ;
    USE SIGNAL ;
    SHAPE ABUTMENT ;
    PORT
      LAYER M4 ;
      RECT 0.000 26.256 0.192 26.280 ;
    END
  END rec_in[256]
  PIN rec_in[257]
    DIRECTION INPUT ;
    USE SIGNAL ;
    SHAPE ABUTMENT ;
    PORT
      LAYER M4 ;
      RECT 0.000 26.352 0.192 26.376 ;
    END
  END rec_in[257]
  PIN rec_in[258]
    DIRECTION INPUT ;
    USE SIGNAL ;
    SHAPE ABUTMENT ;
    PORT
      LAYER M4 ;
      RECT 0.000 26.448 0.192 26.472 ;
    END
  END rec_in[258]
  PIN rec_in[259]
    DIRECTION INPUT ;
    USE SIGNAL ;
    SHAPE ABUTMENT ;
    PORT
      LAYER M4 ;
      RECT 0.000 26.544 0.192 26.568 ;
    END
  END rec_in[259]
  PIN rec_in[260]
    DIRECTION INPUT ;
    USE SIGNAL ;
    SHAPE ABUTMENT ;
    PORT
      LAYER M4 ;
      RECT 0.000 26.640 0.192 26.664 ;
    END
  END rec_in[260]
  PIN rec_in[261]
    DIRECTION INPUT ;
    USE SIGNAL ;
    SHAPE ABUTMENT ;
    PORT
      LAYER M4 ;
      RECT 0.000 26.736 0.192 26.760 ;
    END
  END rec_in[261]
  PIN rec_in[262]
    DIRECTION INPUT ;
    USE SIGNAL ;
    SHAPE ABUTMENT ;
    PORT
      LAYER M4 ;
      RECT 0.000 26.832 0.192 26.856 ;
    END
  END rec_in[262]
  PIN rec_in[263]
    DIRECTION INPUT ;
    USE SIGNAL ;
    SHAPE ABUTMENT ;
    PORT
      LAYER M4 ;
      RECT 0.000 26.928 0.192 26.952 ;
    END
  END rec_in[263]
  PIN rec_in[264]
    DIRECTION INPUT ;
    USE SIGNAL ;
    SHAPE ABUTMENT ;
    PORT
      LAYER M4 ;
      RECT 0.000 27.024 0.192 27.048 ;
    END
  END rec_in[264]
  PIN rec_in[265]
    DIRECTION INPUT ;
    USE SIGNAL ;
    SHAPE ABUTMENT ;
    PORT
      LAYER M4 ;
      RECT 0.000 27.168 0.192 27.192 ;
    END
  END rec_in[265]
  PIN rec_in[266]
    DIRECTION INPUT ;
    USE SIGNAL ;
    SHAPE ABUTMENT ;
    PORT
      LAYER M4 ;
      RECT 0.000 27.264 0.192 27.288 ;
    END
  END rec_in[266]
  PIN rec_in[267]
    DIRECTION INPUT ;
    USE SIGNAL ;
    SHAPE ABUTMENT ;
    PORT
      LAYER M4 ;
      RECT 0.000 27.360 0.192 27.384 ;
    END
  END rec_in[267]
  PIN rec_in[268]
    DIRECTION INPUT ;
    USE SIGNAL ;
    SHAPE ABUTMENT ;
    PORT
      LAYER M4 ;
      RECT 0.000 27.456 0.192 27.480 ;
    END
  END rec_in[268]
  PIN rec_in[269]
    DIRECTION INPUT ;
    USE SIGNAL ;
    SHAPE ABUTMENT ;
    PORT
      LAYER M4 ;
      RECT 0.000 27.552 0.192 27.576 ;
    END
  END rec_in[269]
  PIN rec_in[270]
    DIRECTION INPUT ;
    USE SIGNAL ;
    SHAPE ABUTMENT ;
    PORT
      LAYER M4 ;
      RECT 0.000 27.648 0.192 27.672 ;
    END
  END rec_in[270]
  PIN rec_in[271]
    DIRECTION INPUT ;
    USE SIGNAL ;
    SHAPE ABUTMENT ;
    PORT
      LAYER M4 ;
      RECT 0.000 27.744 0.192 27.768 ;
    END
  END rec_in[271]
  PIN rec_in[272]
    DIRECTION INPUT ;
    USE SIGNAL ;
    SHAPE ABUTMENT ;
    PORT
      LAYER M4 ;
      RECT 0.000 27.840 0.192 27.864 ;
    END
  END rec_in[272]
  PIN rec_in[273]
    DIRECTION INPUT ;
    USE SIGNAL ;
    SHAPE ABUTMENT ;
    PORT
      LAYER M4 ;
      RECT 0.000 27.936 0.192 27.960 ;
    END
  END rec_in[273]
  PIN rec_in[274]
    DIRECTION INPUT ;
    USE SIGNAL ;
    SHAPE ABUTMENT ;
    PORT
      LAYER M4 ;
      RECT 0.000 28.032 0.192 28.056 ;
    END
  END rec_in[274]
  PIN rec_in[275]
    DIRECTION INPUT ;
    USE SIGNAL ;
    SHAPE ABUTMENT ;
    PORT
      LAYER M4 ;
      RECT 0.000 28.128 0.192 28.152 ;
    END
  END rec_in[275]
  PIN rec_in[276]
    DIRECTION INPUT ;
    USE SIGNAL ;
    SHAPE ABUTMENT ;
    PORT
      LAYER M4 ;
      RECT 0.000 28.272 0.192 28.296 ;
    END
  END rec_in[276]
  PIN rec_in[277]
    DIRECTION INPUT ;
    USE SIGNAL ;
    SHAPE ABUTMENT ;
    PORT
      LAYER M4 ;
      RECT 0.000 28.368 0.192 28.392 ;
    END
  END rec_in[277]
  PIN rec_in[278]
    DIRECTION INPUT ;
    USE SIGNAL ;
    SHAPE ABUTMENT ;
    PORT
      LAYER M4 ;
      RECT 0.000 28.464 0.192 28.488 ;
    END
  END rec_in[278]
  PIN rec_in[279]
    DIRECTION INPUT ;
    USE SIGNAL ;
    SHAPE ABUTMENT ;
    PORT
      LAYER M4 ;
      RECT 0.000 28.560 0.192 28.584 ;
    END
  END rec_in[279]
  PIN rec_in[280]
    DIRECTION INPUT ;
    USE SIGNAL ;
    SHAPE ABUTMENT ;
    PORT
      LAYER M4 ;
      RECT 0.000 28.656 0.192 28.680 ;
    END
  END rec_in[280]
  PIN rec_in[281]
    DIRECTION INPUT ;
    USE SIGNAL ;
    SHAPE ABUTMENT ;
    PORT
      LAYER M4 ;
      RECT 0.000 28.752 0.192 28.776 ;
    END
  END rec_in[281]
  PIN rec_in[282]
    DIRECTION INPUT ;
    USE SIGNAL ;
    SHAPE ABUTMENT ;
    PORT
      LAYER M4 ;
      RECT 0.000 28.848 0.192 28.872 ;
    END
  END rec_in[282]
  PIN rec_in[283]
    DIRECTION INPUT ;
    USE SIGNAL ;
    SHAPE ABUTMENT ;
    PORT
      LAYER M4 ;
      RECT 0.000 28.944 0.192 28.968 ;
    END
  END rec_in[283]
  PIN rec_in[284]
    DIRECTION INPUT ;
    USE SIGNAL ;
    SHAPE ABUTMENT ;
    PORT
      LAYER M4 ;
      RECT 0.000 29.040 0.192 29.064 ;
    END
  END rec_in[284]
  PIN rec_in[285]
    DIRECTION INPUT ;
    USE SIGNAL ;
    SHAPE ABUTMENT ;
    PORT
      LAYER M4 ;
      RECT 0.000 29.136 0.192 29.160 ;
    END
  END rec_in[285]
  PIN rec_in[286]
    DIRECTION INPUT ;
    USE SIGNAL ;
    SHAPE ABUTMENT ;
    PORT
      LAYER M4 ;
      RECT 0.000 29.232 0.192 29.256 ;
    END
  END rec_in[286]
  PIN rec_in[287]
    DIRECTION INPUT ;
    USE SIGNAL ;
    SHAPE ABUTMENT ;
    PORT
      LAYER M4 ;
      RECT 0.000 29.328 0.192 29.352 ;
    END
  END rec_in[287]
  PIN rec_in[288]
    DIRECTION INPUT ;
    USE SIGNAL ;
    SHAPE ABUTMENT ;
    PORT
      LAYER M4 ;
      RECT 0.000 29.472 0.192 29.496 ;
    END
  END rec_in[288]
  PIN rec_in[289]
    DIRECTION INPUT ;
    USE SIGNAL ;
    SHAPE ABUTMENT ;
    PORT
      LAYER M4 ;
      RECT 0.000 29.568 0.192 29.592 ;
    END
  END rec_in[289]
  PIN rec_in[290]
    DIRECTION INPUT ;
    USE SIGNAL ;
    SHAPE ABUTMENT ;
    PORT
      LAYER M4 ;
      RECT 0.000 29.664 0.192 29.688 ;
    END
  END rec_in[290]
  PIN rec_in[291]
    DIRECTION INPUT ;
    USE SIGNAL ;
    SHAPE ABUTMENT ;
    PORT
      LAYER M4 ;
      RECT 0.000 29.760 0.192 29.784 ;
    END
  END rec_in[291]
  PIN rec_in[292]
    DIRECTION INPUT ;
    USE SIGNAL ;
    SHAPE ABUTMENT ;
    PORT
      LAYER M4 ;
      RECT 0.000 29.856 0.192 29.880 ;
    END
  END rec_in[292]
  PIN rec_in[293]
    DIRECTION INPUT ;
    USE SIGNAL ;
    SHAPE ABUTMENT ;
    PORT
      LAYER M4 ;
      RECT 0.000 29.952 0.192 29.976 ;
    END
  END rec_in[293]
  PIN rec_in[294]
    DIRECTION INPUT ;
    USE SIGNAL ;
    SHAPE ABUTMENT ;
    PORT
      LAYER M4 ;
      RECT 0.000 30.048 0.192 30.072 ;
    END
  END rec_in[294]
  PIN rec_in[295]
    DIRECTION INPUT ;
    USE SIGNAL ;
    SHAPE ABUTMENT ;
    PORT
      LAYER M4 ;
      RECT 0.000 30.144 0.192 30.168 ;
    END
  END rec_in[295]
  PIN rec_in[296]
    DIRECTION INPUT ;
    USE SIGNAL ;
    SHAPE ABUTMENT ;
    PORT
      LAYER M4 ;
      RECT 0.000 30.240 0.192 30.264 ;
    END
  END rec_in[296]
  PIN rec_in[297]
    DIRECTION INPUT ;
    USE SIGNAL ;
    SHAPE ABUTMENT ;
    PORT
      LAYER M4 ;
      RECT 0.000 30.336 0.192 30.360 ;
    END
  END rec_in[297]
  PIN rec_in[298]
    DIRECTION INPUT ;
    USE SIGNAL ;
    SHAPE ABUTMENT ;
    PORT
      LAYER M4 ;
      RECT 0.000 30.432 0.192 30.456 ;
    END
  END rec_in[298]
  PIN rec_in[299]
    DIRECTION INPUT ;
    USE SIGNAL ;
    SHAPE ABUTMENT ;
    PORT
      LAYER M4 ;
      RECT 0.000 30.576 0.192 30.600 ;
    END
  END rec_in[299]
  PIN rec_in[300]
    DIRECTION INPUT ;
    USE SIGNAL ;
    SHAPE ABUTMENT ;
    PORT
      LAYER M4 ;
      RECT 0.000 30.672 0.192 30.696 ;
    END
  END rec_in[300]
  PIN rec_in[301]
    DIRECTION INPUT ;
    USE SIGNAL ;
    SHAPE ABUTMENT ;
    PORT
      LAYER M4 ;
      RECT 0.000 30.768 0.192 30.792 ;
    END
  END rec_in[301]
  PIN rec_in[302]
    DIRECTION INPUT ;
    USE SIGNAL ;
    SHAPE ABUTMENT ;
    PORT
      LAYER M4 ;
      RECT 0.000 30.864 0.192 30.888 ;
    END
  END rec_in[302]
  PIN rec_in[303]
    DIRECTION INPUT ;
    USE SIGNAL ;
    SHAPE ABUTMENT ;
    PORT
      LAYER M4 ;
      RECT 0.000 30.960 0.192 30.984 ;
    END
  END rec_in[303]
  PIN rec_in[304]
    DIRECTION INPUT ;
    USE SIGNAL ;
    SHAPE ABUTMENT ;
    PORT
      LAYER M4 ;
      RECT 0.000 31.056 0.192 31.080 ;
    END
  END rec_in[304]
  PIN rec_in[305]
    DIRECTION INPUT ;
    USE SIGNAL ;
    SHAPE ABUTMENT ;
    PORT
      LAYER M4 ;
      RECT 0.000 31.152 0.192 31.176 ;
    END
  END rec_in[305]
  PIN rec_in[306]
    DIRECTION INPUT ;
    USE SIGNAL ;
    SHAPE ABUTMENT ;
    PORT
      LAYER M4 ;
      RECT 0.000 31.248 0.192 31.272 ;
    END
  END rec_in[306]
  PIN rec_in[307]
    DIRECTION INPUT ;
    USE SIGNAL ;
    SHAPE ABUTMENT ;
    PORT
      LAYER M4 ;
      RECT 0.000 31.344 0.192 31.368 ;
    END
  END rec_in[307]
  PIN rec_in[308]
    DIRECTION INPUT ;
    USE SIGNAL ;
    SHAPE ABUTMENT ;
    PORT
      LAYER M4 ;
      RECT 0.000 31.440 0.192 31.464 ;
    END
  END rec_in[308]
  PIN rec_in[309]
    DIRECTION INPUT ;
    USE SIGNAL ;
    SHAPE ABUTMENT ;
    PORT
      LAYER M4 ;
      RECT 0.000 31.536 0.192 31.560 ;
    END
  END rec_in[309]
  PIN rec_in[310]
    DIRECTION INPUT ;
    USE SIGNAL ;
    SHAPE ABUTMENT ;
    PORT
      LAYER M4 ;
      RECT 0.000 31.632 0.192 31.656 ;
    END
  END rec_in[310]
  PIN rec_in[311]
    DIRECTION INPUT ;
    USE SIGNAL ;
    SHAPE ABUTMENT ;
    PORT
      LAYER M4 ;
      RECT 0.000 31.776 0.192 31.800 ;
    END
  END rec_in[311]
  PIN rec_in[312]
    DIRECTION INPUT ;
    USE SIGNAL ;
    SHAPE ABUTMENT ;
    PORT
      LAYER M4 ;
      RECT 0.000 31.872 0.192 31.896 ;
    END
  END rec_in[312]
  PIN rec_in[313]
    DIRECTION INPUT ;
    USE SIGNAL ;
    SHAPE ABUTMENT ;
    PORT
      LAYER M4 ;
      RECT 0.000 31.968 0.192 31.992 ;
    END
  END rec_in[313]
  PIN rec_in[314]
    DIRECTION INPUT ;
    USE SIGNAL ;
    SHAPE ABUTMENT ;
    PORT
      LAYER M4 ;
      RECT 0.000 32.064 0.192 32.088 ;
    END
  END rec_in[314]
  PIN rec_in[315]
    DIRECTION INPUT ;
    USE SIGNAL ;
    SHAPE ABUTMENT ;
    PORT
      LAYER M4 ;
      RECT 0.000 32.160 0.192 32.184 ;
    END
  END rec_in[315]
  PIN rec_in[316]
    DIRECTION INPUT ;
    USE SIGNAL ;
    SHAPE ABUTMENT ;
    PORT
      LAYER M4 ;
      RECT 0.000 32.256 0.192 32.280 ;
    END
  END rec_in[316]
  PIN rec_in[317]
    DIRECTION INPUT ;
    USE SIGNAL ;
    SHAPE ABUTMENT ;
    PORT
      LAYER M4 ;
      RECT 0.000 32.352 0.192 32.376 ;
    END
  END rec_in[317]
  PIN rec_in[318]
    DIRECTION INPUT ;
    USE SIGNAL ;
    SHAPE ABUTMENT ;
    PORT
      LAYER M4 ;
      RECT 0.000 32.448 0.192 32.472 ;
    END
  END rec_in[318]
  PIN rec_in[319]
    DIRECTION INPUT ;
    USE SIGNAL ;
    SHAPE ABUTMENT ;
    PORT
      LAYER M4 ;
      RECT 0.000 32.544 0.192 32.568 ;
    END
  END rec_in[319]
  PIN rec_in[320]
    DIRECTION INPUT ;
    USE SIGNAL ;
    SHAPE ABUTMENT ;
    PORT
      LAYER M4 ;
      RECT 0.000 32.640 0.192 32.664 ;
    END
  END rec_in[320]
  PIN rec_in[321]
    DIRECTION INPUT ;
    USE SIGNAL ;
    SHAPE ABUTMENT ;
    PORT
      LAYER M4 ;
      RECT 0.000 32.736 0.192 32.760 ;
    END
  END rec_in[321]
  PIN rec_in[322]
    DIRECTION INPUT ;
    USE SIGNAL ;
    SHAPE ABUTMENT ;
    PORT
      LAYER M4 ;
      RECT 0.000 32.880 0.192 32.904 ;
    END
  END rec_in[322]
  PIN rec_in[323]
    DIRECTION INPUT ;
    USE SIGNAL ;
    SHAPE ABUTMENT ;
    PORT
      LAYER M4 ;
      RECT 0.000 32.976 0.192 33.000 ;
    END
  END rec_in[323]
  PIN rec_in[324]
    DIRECTION INPUT ;
    USE SIGNAL ;
    SHAPE ABUTMENT ;
    PORT
      LAYER M4 ;
      RECT 0.000 33.072 0.192 33.096 ;
    END
  END rec_in[324]
  PIN rec_in[325]
    DIRECTION INPUT ;
    USE SIGNAL ;
    SHAPE ABUTMENT ;
    PORT
      LAYER M4 ;
      RECT 0.000 33.168 0.192 33.192 ;
    END
  END rec_in[325]
  PIN rec_in[326]
    DIRECTION INPUT ;
    USE SIGNAL ;
    SHAPE ABUTMENT ;
    PORT
      LAYER M4 ;
      RECT 0.000 33.264 0.192 33.288 ;
    END
  END rec_in[326]
  PIN rec_in[327]
    DIRECTION INPUT ;
    USE SIGNAL ;
    SHAPE ABUTMENT ;
    PORT
      LAYER M4 ;
      RECT 0.000 33.360 0.192 33.384 ;
    END
  END rec_in[327]
  PIN rec_in[328]
    DIRECTION INPUT ;
    USE SIGNAL ;
    SHAPE ABUTMENT ;
    PORT
      LAYER M4 ;
      RECT 0.000 33.456 0.192 33.480 ;
    END
  END rec_in[328]
  PIN rec_in[329]
    DIRECTION INPUT ;
    USE SIGNAL ;
    SHAPE ABUTMENT ;
    PORT
      LAYER M4 ;
      RECT 0.000 33.552 0.192 33.576 ;
    END
  END rec_in[329]
  PIN rec_in[330]
    DIRECTION INPUT ;
    USE SIGNAL ;
    SHAPE ABUTMENT ;
    PORT
      LAYER M4 ;
      RECT 0.000 33.648 0.192 33.672 ;
    END
  END rec_in[330]
  PIN rec_in[331]
    DIRECTION INPUT ;
    USE SIGNAL ;
    SHAPE ABUTMENT ;
    PORT
      LAYER M4 ;
      RECT 0.000 33.744 0.192 33.768 ;
    END
  END rec_in[331]
  PIN rec_in[332]
    DIRECTION INPUT ;
    USE SIGNAL ;
    SHAPE ABUTMENT ;
    PORT
      LAYER M4 ;
      RECT 0.000 33.840 0.192 33.864 ;
    END
  END rec_in[332]
  PIN rec_in[333]
    DIRECTION INPUT ;
    USE SIGNAL ;
    SHAPE ABUTMENT ;
    PORT
      LAYER M4 ;
      RECT 0.000 33.936 0.192 33.960 ;
    END
  END rec_in[333]
  PIN rec_in[334]
    DIRECTION INPUT ;
    USE SIGNAL ;
    SHAPE ABUTMENT ;
    PORT
      LAYER M4 ;
      RECT 0.000 34.080 0.192 34.104 ;
    END
  END rec_in[334]
  PIN rec_in[335]
    DIRECTION INPUT ;
    USE SIGNAL ;
    SHAPE ABUTMENT ;
    PORT
      LAYER M4 ;
      RECT 0.000 34.176 0.192 34.200 ;
    END
  END rec_in[335]
  PIN rec_in[336]
    DIRECTION INPUT ;
    USE SIGNAL ;
    SHAPE ABUTMENT ;
    PORT
      LAYER M4 ;
      RECT 0.000 34.272 0.192 34.296 ;
    END
  END rec_in[336]
  PIN rec_in[337]
    DIRECTION INPUT ;
    USE SIGNAL ;
    SHAPE ABUTMENT ;
    PORT
      LAYER M4 ;
      RECT 0.000 34.368 0.192 34.392 ;
    END
  END rec_in[337]
  PIN rec_in[338]
    DIRECTION INPUT ;
    USE SIGNAL ;
    SHAPE ABUTMENT ;
    PORT
      LAYER M4 ;
      RECT 0.000 34.464 0.192 34.488 ;
    END
  END rec_in[338]
  PIN rec_in[339]
    DIRECTION INPUT ;
    USE SIGNAL ;
    SHAPE ABUTMENT ;
    PORT
      LAYER M4 ;
      RECT 0.000 34.560 0.192 34.584 ;
    END
  END rec_in[339]
  PIN rec_in[340]
    DIRECTION INPUT ;
    USE SIGNAL ;
    SHAPE ABUTMENT ;
    PORT
      LAYER M4 ;
      RECT 0.000 34.656 0.192 34.680 ;
    END
  END rec_in[340]
  PIN rec_in[341]
    DIRECTION INPUT ;
    USE SIGNAL ;
    SHAPE ABUTMENT ;
    PORT
      LAYER M4 ;
      RECT 0.000 34.752 0.192 34.776 ;
    END
  END rec_in[341]
  PIN rec_in[342]
    DIRECTION INPUT ;
    USE SIGNAL ;
    SHAPE ABUTMENT ;
    PORT
      LAYER M4 ;
      RECT 0.000 34.848 0.192 34.872 ;
    END
  END rec_in[342]
  PIN rec_in[343]
    DIRECTION INPUT ;
    USE SIGNAL ;
    SHAPE ABUTMENT ;
    PORT
      LAYER M4 ;
      RECT 0.000 34.944 0.192 34.968 ;
    END
  END rec_in[343]
  PIN rec_in[344]
    DIRECTION INPUT ;
    USE SIGNAL ;
    SHAPE ABUTMENT ;
    PORT
      LAYER M4 ;
      RECT 0.000 35.040 0.192 35.064 ;
    END
  END rec_in[344]
  PIN rec_in[345]
    DIRECTION INPUT ;
    USE SIGNAL ;
    SHAPE ABUTMENT ;
    PORT
      LAYER M4 ;
      RECT 0.000 35.184 0.192 35.208 ;
    END
  END rec_in[345]
  PIN rec_in[346]
    DIRECTION INPUT ;
    USE SIGNAL ;
    SHAPE ABUTMENT ;
    PORT
      LAYER M4 ;
      RECT 0.000 35.280 0.192 35.304 ;
    END
  END rec_in[346]
  PIN rec_in[347]
    DIRECTION INPUT ;
    USE SIGNAL ;
    SHAPE ABUTMENT ;
    PORT
      LAYER M4 ;
      RECT 0.000 35.376 0.192 35.400 ;
    END
  END rec_in[347]
  PIN rec_in[348]
    DIRECTION INPUT ;
    USE SIGNAL ;
    SHAPE ABUTMENT ;
    PORT
      LAYER M4 ;
      RECT 0.000 35.472 0.192 35.496 ;
    END
  END rec_in[348]
  PIN rec_in[349]
    DIRECTION INPUT ;
    USE SIGNAL ;
    SHAPE ABUTMENT ;
    PORT
      LAYER M4 ;
      RECT 0.000 35.568 0.192 35.592 ;
    END
  END rec_in[349]
  PIN rec_in[350]
    DIRECTION INPUT ;
    USE SIGNAL ;
    SHAPE ABUTMENT ;
    PORT
      LAYER M4 ;
      RECT 0.000 35.664 0.192 35.688 ;
    END
  END rec_in[350]
  PIN rec_in[351]
    DIRECTION INPUT ;
    USE SIGNAL ;
    SHAPE ABUTMENT ;
    PORT
      LAYER M4 ;
      RECT 0.000 35.760 0.192 35.784 ;
    END
  END rec_in[351]
  PIN rec_in[352]
    DIRECTION INPUT ;
    USE SIGNAL ;
    SHAPE ABUTMENT ;
    PORT
      LAYER M4 ;
      RECT 0.000 35.856 0.192 35.880 ;
    END
  END rec_in[352]
  PIN rec_in[353]
    DIRECTION INPUT ;
    USE SIGNAL ;
    SHAPE ABUTMENT ;
    PORT
      LAYER M4 ;
      RECT 0.000 35.952 0.192 35.976 ;
    END
  END rec_in[353]
  PIN rec_in[354]
    DIRECTION INPUT ;
    USE SIGNAL ;
    SHAPE ABUTMENT ;
    PORT
      LAYER M4 ;
      RECT 0.000 36.048 0.192 36.072 ;
    END
  END rec_in[354]
  PIN rec_in[355]
    DIRECTION INPUT ;
    USE SIGNAL ;
    SHAPE ABUTMENT ;
    PORT
      LAYER M4 ;
      RECT 0.000 36.144 0.192 36.168 ;
    END
  END rec_in[355]
  PIN rec_in[356]
    DIRECTION INPUT ;
    USE SIGNAL ;
    SHAPE ABUTMENT ;
    PORT
      LAYER M4 ;
      RECT 0.000 36.240 0.192 36.264 ;
    END
  END rec_in[356]
  PIN rec_in[357]
    DIRECTION INPUT ;
    USE SIGNAL ;
    SHAPE ABUTMENT ;
    PORT
      LAYER M4 ;
      RECT 0.000 36.384 0.192 36.408 ;
    END
  END rec_in[357]
  PIN rec_in[358]
    DIRECTION INPUT ;
    USE SIGNAL ;
    SHAPE ABUTMENT ;
    PORT
      LAYER M4 ;
      RECT 0.000 36.480 0.192 36.504 ;
    END
  END rec_in[358]
  PIN rec_in[359]
    DIRECTION INPUT ;
    USE SIGNAL ;
    SHAPE ABUTMENT ;
    PORT
      LAYER M4 ;
      RECT 0.000 36.576 0.192 36.600 ;
    END
  END rec_in[359]
  PIN rec_in[360]
    DIRECTION INPUT ;
    USE SIGNAL ;
    SHAPE ABUTMENT ;
    PORT
      LAYER M4 ;
      RECT 0.000 36.672 0.192 36.696 ;
    END
  END rec_in[360]
  PIN rec_in[361]
    DIRECTION INPUT ;
    USE SIGNAL ;
    SHAPE ABUTMENT ;
    PORT
      LAYER M4 ;
      RECT 0.000 36.768 0.192 36.792 ;
    END
  END rec_in[361]
  PIN rec_in[362]
    DIRECTION INPUT ;
    USE SIGNAL ;
    SHAPE ABUTMENT ;
    PORT
      LAYER M4 ;
      RECT 0.000 36.864 0.192 36.888 ;
    END
  END rec_in[362]
  PIN rec_in[363]
    DIRECTION INPUT ;
    USE SIGNAL ;
    SHAPE ABUTMENT ;
    PORT
      LAYER M4 ;
      RECT 0.000 36.960 0.192 36.984 ;
    END
  END rec_in[363]
  PIN rec_in[364]
    DIRECTION INPUT ;
    USE SIGNAL ;
    SHAPE ABUTMENT ;
    PORT
      LAYER M4 ;
      RECT 0.000 37.056 0.192 37.080 ;
    END
  END rec_in[364]
  PIN rec_in[365]
    DIRECTION INPUT ;
    USE SIGNAL ;
    SHAPE ABUTMENT ;
    PORT
      LAYER M4 ;
      RECT 0.000 37.152 0.192 37.176 ;
    END
  END rec_in[365]
  PIN rec_in[366]
    DIRECTION INPUT ;
    USE SIGNAL ;
    SHAPE ABUTMENT ;
    PORT
      LAYER M4 ;
      RECT 0.000 37.248 0.192 37.272 ;
    END
  END rec_in[366]
  PIN rec_in[367]
    DIRECTION INPUT ;
    USE SIGNAL ;
    SHAPE ABUTMENT ;
    PORT
      LAYER M4 ;
      RECT 0.000 37.344 0.192 37.368 ;
    END
  END rec_in[367]
  PIN rec_in[368]
    DIRECTION INPUT ;
    USE SIGNAL ;
    SHAPE ABUTMENT ;
    PORT
      LAYER M4 ;
      RECT 0.000 37.488 0.192 37.512 ;
    END
  END rec_in[368]
  PIN rec_in[369]
    DIRECTION INPUT ;
    USE SIGNAL ;
    SHAPE ABUTMENT ;
    PORT
      LAYER M4 ;
      RECT 0.000 37.584 0.192 37.608 ;
    END
  END rec_in[369]
  PIN rec_in[370]
    DIRECTION INPUT ;
    USE SIGNAL ;
    SHAPE ABUTMENT ;
    PORT
      LAYER M4 ;
      RECT 0.000 37.680 0.192 37.704 ;
    END
  END rec_in[370]
  PIN rec_in[371]
    DIRECTION INPUT ;
    USE SIGNAL ;
    SHAPE ABUTMENT ;
    PORT
      LAYER M4 ;
      RECT 0.000 37.776 0.192 37.800 ;
    END
  END rec_in[371]
  PIN rec_in[372]
    DIRECTION INPUT ;
    USE SIGNAL ;
    SHAPE ABUTMENT ;
    PORT
      LAYER M4 ;
      RECT 0.000 37.872 0.192 37.896 ;
    END
  END rec_in[372]
  PIN rec_in[373]
    DIRECTION INPUT ;
    USE SIGNAL ;
    SHAPE ABUTMENT ;
    PORT
      LAYER M4 ;
      RECT 0.000 37.968 0.192 37.992 ;
    END
  END rec_in[373]
  PIN rec_in[374]
    DIRECTION INPUT ;
    USE SIGNAL ;
    SHAPE ABUTMENT ;
    PORT
      LAYER M4 ;
      RECT 0.000 38.064 0.192 38.088 ;
    END
  END rec_in[374]
  PIN rec_in[375]
    DIRECTION INPUT ;
    USE SIGNAL ;
    SHAPE ABUTMENT ;
    PORT
      LAYER M4 ;
      RECT 0.000 38.160 0.192 38.184 ;
    END
  END rec_in[375]
  PIN rec_in[376]
    DIRECTION INPUT ;
    USE SIGNAL ;
    SHAPE ABUTMENT ;
    PORT
      LAYER M4 ;
      RECT 0.000 38.256 0.192 38.280 ;
    END
  END rec_in[376]
  PIN rec_in[377]
    DIRECTION INPUT ;
    USE SIGNAL ;
    SHAPE ABUTMENT ;
    PORT
      LAYER M4 ;
      RECT 0.000 38.352 0.192 38.376 ;
    END
  END rec_in[377]
  PIN rec_in[378]
    DIRECTION INPUT ;
    USE SIGNAL ;
    SHAPE ABUTMENT ;
    PORT
      LAYER M4 ;
      RECT 0.000 38.448 0.192 38.472 ;
    END
  END rec_in[378]
  PIN rec_in[379]
    DIRECTION INPUT ;
    USE SIGNAL ;
    SHAPE ABUTMENT ;
    PORT
      LAYER M4 ;
      RECT 0.000 38.544 0.192 38.568 ;
    END
  END rec_in[379]
  PIN rec_in[380]
    DIRECTION INPUT ;
    USE SIGNAL ;
    SHAPE ABUTMENT ;
    PORT
      LAYER M4 ;
      RECT 0.000 38.688 0.192 38.712 ;
    END
  END rec_in[380]
  PIN rec_in[381]
    DIRECTION INPUT ;
    USE SIGNAL ;
    SHAPE ABUTMENT ;
    PORT
      LAYER M4 ;
      RECT 0.000 38.784 0.192 38.808 ;
    END
  END rec_in[381]
  PIN rec_in[382]
    DIRECTION INPUT ;
    USE SIGNAL ;
    SHAPE ABUTMENT ;
    PORT
      LAYER M4 ;
      RECT 0.000 38.880 0.192 38.904 ;
    END
  END rec_in[382]
  PIN rec_in[383]
    DIRECTION INPUT ;
    USE SIGNAL ;
    SHAPE ABUTMENT ;
    PORT
      LAYER M4 ;
      RECT 0.000 38.976 0.192 39.000 ;
    END
  END rec_in[383]
  PIN rec_in[384]
    DIRECTION INPUT ;
    USE SIGNAL ;
    SHAPE ABUTMENT ;
    PORT
      LAYER M4 ;
      RECT 0.000 39.072 0.192 39.096 ;
    END
  END rec_in[384]
  PIN rec_in[385]
    DIRECTION INPUT ;
    USE SIGNAL ;
    SHAPE ABUTMENT ;
    PORT
      LAYER M4 ;
      RECT 0.000 39.168 0.192 39.192 ;
    END
  END rec_in[385]
  PIN rec_in[386]
    DIRECTION INPUT ;
    USE SIGNAL ;
    SHAPE ABUTMENT ;
    PORT
      LAYER M4 ;
      RECT 0.000 39.264 0.192 39.288 ;
    END
  END rec_in[386]
  PIN rec_in[387]
    DIRECTION INPUT ;
    USE SIGNAL ;
    SHAPE ABUTMENT ;
    PORT
      LAYER M4 ;
      RECT 0.000 39.360 0.192 39.384 ;
    END
  END rec_in[387]
  PIN rec_in[388]
    DIRECTION INPUT ;
    USE SIGNAL ;
    SHAPE ABUTMENT ;
    PORT
      LAYER M4 ;
      RECT 0.000 39.456 0.192 39.480 ;
    END
  END rec_in[388]
  PIN rec_in[389]
    DIRECTION INPUT ;
    USE SIGNAL ;
    SHAPE ABUTMENT ;
    PORT
      LAYER M4 ;
      RECT 0.000 39.552 0.192 39.576 ;
    END
  END rec_in[389]
  PIN rec_in[390]
    DIRECTION INPUT ;
    USE SIGNAL ;
    SHAPE ABUTMENT ;
    PORT
      LAYER M4 ;
      RECT 0.000 39.648 0.192 39.672 ;
    END
  END rec_in[390]
  PIN rec_in[391]
    DIRECTION INPUT ;
    USE SIGNAL ;
    SHAPE ABUTMENT ;
    PORT
      LAYER M4 ;
      RECT 0.000 39.792 0.192 39.816 ;
    END
  END rec_in[391]
  PIN rec_in[392]
    DIRECTION INPUT ;
    USE SIGNAL ;
    SHAPE ABUTMENT ;
    PORT
      LAYER M4 ;
      RECT 0.000 39.888 0.192 39.912 ;
    END
  END rec_in[392]
  PIN rec_in[393]
    DIRECTION INPUT ;
    USE SIGNAL ;
    SHAPE ABUTMENT ;
    PORT
      LAYER M4 ;
      RECT 0.000 39.984 0.192 40.008 ;
    END
  END rec_in[393]
  PIN rec_in[394]
    DIRECTION INPUT ;
    USE SIGNAL ;
    SHAPE ABUTMENT ;
    PORT
      LAYER M4 ;
      RECT 0.000 40.080 0.192 40.104 ;
    END
  END rec_in[394]
  PIN rec_in[395]
    DIRECTION INPUT ;
    USE SIGNAL ;
    SHAPE ABUTMENT ;
    PORT
      LAYER M4 ;
      RECT 0.000 40.176 0.192 40.200 ;
    END
  END rec_in[395]
  PIN rec_in[396]
    DIRECTION INPUT ;
    USE SIGNAL ;
    SHAPE ABUTMENT ;
    PORT
      LAYER M4 ;
      RECT 0.000 40.272 0.192 40.296 ;
    END
  END rec_in[396]
  PIN rec_in[397]
    DIRECTION INPUT ;
    USE SIGNAL ;
    SHAPE ABUTMENT ;
    PORT
      LAYER M4 ;
      RECT 0.000 40.368 0.192 40.392 ;
    END
  END rec_in[397]
  PIN rec_in[398]
    DIRECTION INPUT ;
    USE SIGNAL ;
    SHAPE ABUTMENT ;
    PORT
      LAYER M4 ;
      RECT 0.000 40.464 0.192 40.488 ;
    END
  END rec_in[398]
  PIN rec_in[399]
    DIRECTION INPUT ;
    USE SIGNAL ;
    SHAPE ABUTMENT ;
    PORT
      LAYER M4 ;
      RECT 0.000 40.560 0.192 40.584 ;
    END
  END rec_in[399]
  PIN rec_in[400]
    DIRECTION INPUT ;
    USE SIGNAL ;
    SHAPE ABUTMENT ;
    PORT
      LAYER M4 ;
      RECT 0.000 40.656 0.192 40.680 ;
    END
  END rec_in[400]
  PIN rec_in[401]
    DIRECTION INPUT ;
    USE SIGNAL ;
    SHAPE ABUTMENT ;
    PORT
      LAYER M4 ;
      RECT 0.000 40.752 0.192 40.776 ;
    END
  END rec_in[401]
  PIN rec_in[402]
    DIRECTION INPUT ;
    USE SIGNAL ;
    SHAPE ABUTMENT ;
    PORT
      LAYER M4 ;
      RECT 0.000 40.848 0.192 40.872 ;
    END
  END rec_in[402]
  PIN rec_in[403]
    DIRECTION INPUT ;
    USE SIGNAL ;
    SHAPE ABUTMENT ;
    PORT
      LAYER M4 ;
      RECT 0.000 40.992 0.192 41.016 ;
    END
  END rec_in[403]
  PIN rec_in[404]
    DIRECTION INPUT ;
    USE SIGNAL ;
    SHAPE ABUTMENT ;
    PORT
      LAYER M4 ;
      RECT 0.000 41.088 0.192 41.112 ;
    END
  END rec_in[404]
  PIN rec_in[405]
    DIRECTION INPUT ;
    USE SIGNAL ;
    SHAPE ABUTMENT ;
    PORT
      LAYER M4 ;
      RECT 0.000 41.184 0.192 41.208 ;
    END
  END rec_in[405]
  PIN rec_in[406]
    DIRECTION INPUT ;
    USE SIGNAL ;
    SHAPE ABUTMENT ;
    PORT
      LAYER M4 ;
      RECT 0.000 41.280 0.192 41.304 ;
    END
  END rec_in[406]
  PIN rec_in[407]
    DIRECTION INPUT ;
    USE SIGNAL ;
    SHAPE ABUTMENT ;
    PORT
      LAYER M4 ;
      RECT 0.000 41.376 0.192 41.400 ;
    END
  END rec_in[407]
  PIN rec_in[408]
    DIRECTION INPUT ;
    USE SIGNAL ;
    SHAPE ABUTMENT ;
    PORT
      LAYER M4 ;
      RECT 0.000 41.472 0.192 41.496 ;
    END
  END rec_in[408]
  PIN rec_in[409]
    DIRECTION INPUT ;
    USE SIGNAL ;
    SHAPE ABUTMENT ;
    PORT
      LAYER M4 ;
      RECT 0.000 41.568 0.192 41.592 ;
    END
  END rec_in[409]
  PIN rec_in[410]
    DIRECTION INPUT ;
    USE SIGNAL ;
    SHAPE ABUTMENT ;
    PORT
      LAYER M4 ;
      RECT 0.000 41.664 0.192 41.688 ;
    END
  END rec_in[410]
  PIN rec_in[411]
    DIRECTION INPUT ;
    USE SIGNAL ;
    SHAPE ABUTMENT ;
    PORT
      LAYER M4 ;
      RECT 0.000 41.760 0.192 41.784 ;
    END
  END rec_in[411]
  PIN rec_in[412]
    DIRECTION INPUT ;
    USE SIGNAL ;
    SHAPE ABUTMENT ;
    PORT
      LAYER M4 ;
      RECT 0.000 41.856 0.192 41.880 ;
    END
  END rec_in[412]
  PIN rec_in[413]
    DIRECTION INPUT ;
    USE SIGNAL ;
    SHAPE ABUTMENT ;
    PORT
      LAYER M4 ;
      RECT 0.000 41.952 0.192 41.976 ;
    END
  END rec_in[413]
  PIN rec_in[414]
    DIRECTION INPUT ;
    USE SIGNAL ;
    SHAPE ABUTMENT ;
    PORT
      LAYER M4 ;
      RECT 0.000 42.096 0.192 42.120 ;
    END
  END rec_in[414]
  PIN rec_in[415]
    DIRECTION INPUT ;
    USE SIGNAL ;
    SHAPE ABUTMENT ;
    PORT
      LAYER M4 ;
      RECT 0.000 42.192 0.192 42.216 ;
    END
  END rec_in[415]
  PIN rec_in[416]
    DIRECTION INPUT ;
    USE SIGNAL ;
    SHAPE ABUTMENT ;
    PORT
      LAYER M4 ;
      RECT 0.000 42.288 0.192 42.312 ;
    END
  END rec_in[416]
  PIN rec_in[417]
    DIRECTION INPUT ;
    USE SIGNAL ;
    SHAPE ABUTMENT ;
    PORT
      LAYER M4 ;
      RECT 0.000 42.384 0.192 42.408 ;
    END
  END rec_in[417]
  PIN rec_in[418]
    DIRECTION INPUT ;
    USE SIGNAL ;
    SHAPE ABUTMENT ;
    PORT
      LAYER M4 ;
      RECT 0.000 42.480 0.192 42.504 ;
    END
  END rec_in[418]
  PIN rec_in[419]
    DIRECTION INPUT ;
    USE SIGNAL ;
    SHAPE ABUTMENT ;
    PORT
      LAYER M4 ;
      RECT 0.000 42.576 0.192 42.600 ;
    END
  END rec_in[419]
  PIN rec_in[420]
    DIRECTION INPUT ;
    USE SIGNAL ;
    SHAPE ABUTMENT ;
    PORT
      LAYER M4 ;
      RECT 0.000 42.672 0.192 42.696 ;
    END
  END rec_in[420]
  PIN rec_in[421]
    DIRECTION INPUT ;
    USE SIGNAL ;
    SHAPE ABUTMENT ;
    PORT
      LAYER M4 ;
      RECT 0.000 42.768 0.192 42.792 ;
    END
  END rec_in[421]
  PIN rec_in[422]
    DIRECTION INPUT ;
    USE SIGNAL ;
    SHAPE ABUTMENT ;
    PORT
      LAYER M4 ;
      RECT 0.000 42.864 0.192 42.888 ;
    END
  END rec_in[422]
  PIN rec_in[423]
    DIRECTION INPUT ;
    USE SIGNAL ;
    SHAPE ABUTMENT ;
    PORT
      LAYER M4 ;
      RECT 0.000 42.960 0.192 42.984 ;
    END
  END rec_in[423]
  PIN rec_in[424]
    DIRECTION INPUT ;
    USE SIGNAL ;
    SHAPE ABUTMENT ;
    PORT
      LAYER M4 ;
      RECT 0.000 43.056 0.192 43.080 ;
    END
  END rec_in[424]
  PIN rec_in[425]
    DIRECTION INPUT ;
    USE SIGNAL ;
    SHAPE ABUTMENT ;
    PORT
      LAYER M4 ;
      RECT 0.000 43.152 0.192 43.176 ;
    END
  END rec_in[425]
  PIN rec_in[426]
    DIRECTION INPUT ;
    USE SIGNAL ;
    SHAPE ABUTMENT ;
    PORT
      LAYER M4 ;
      RECT 0.000 43.296 0.192 43.320 ;
    END
  END rec_in[426]
  PIN rec_in[427]
    DIRECTION INPUT ;
    USE SIGNAL ;
    SHAPE ABUTMENT ;
    PORT
      LAYER M4 ;
      RECT 0.000 43.392 0.192 43.416 ;
    END
  END rec_in[427]
  PIN rec_in[428]
    DIRECTION INPUT ;
    USE SIGNAL ;
    SHAPE ABUTMENT ;
    PORT
      LAYER M4 ;
      RECT 0.000 43.488 0.192 43.512 ;
    END
  END rec_in[428]
  PIN rec_in[429]
    DIRECTION INPUT ;
    USE SIGNAL ;
    SHAPE ABUTMENT ;
    PORT
      LAYER M4 ;
      RECT 0.000 43.584 0.192 43.608 ;
    END
  END rec_in[429]
  PIN rec_in[430]
    DIRECTION INPUT ;
    USE SIGNAL ;
    SHAPE ABUTMENT ;
    PORT
      LAYER M4 ;
      RECT 0.000 43.680 0.192 43.704 ;
    END
  END rec_in[430]
  PIN rec_in[431]
    DIRECTION INPUT ;
    USE SIGNAL ;
    SHAPE ABUTMENT ;
    PORT
      LAYER M4 ;
      RECT 0.000 43.776 0.192 43.800 ;
    END
  END rec_in[431]
  PIN rec_in[432]
    DIRECTION INPUT ;
    USE SIGNAL ;
    SHAPE ABUTMENT ;
    PORT
      LAYER M4 ;
      RECT 0.000 43.872 0.192 43.896 ;
    END
  END rec_in[432]
  PIN rec_in[433]
    DIRECTION INPUT ;
    USE SIGNAL ;
    SHAPE ABUTMENT ;
    PORT
      LAYER M4 ;
      RECT 0.000 43.968 0.192 43.992 ;
    END
  END rec_in[433]
  PIN rec_in[434]
    DIRECTION INPUT ;
    USE SIGNAL ;
    SHAPE ABUTMENT ;
    PORT
      LAYER M4 ;
      RECT 0.000 44.064 0.192 44.088 ;
    END
  END rec_in[434]
  PIN rec_in[435]
    DIRECTION INPUT ;
    USE SIGNAL ;
    SHAPE ABUTMENT ;
    PORT
      LAYER M4 ;
      RECT 0.000 44.160 0.192 44.184 ;
    END
  END rec_in[435]
  PIN rec_in[436]
    DIRECTION INPUT ;
    USE SIGNAL ;
    SHAPE ABUTMENT ;
    PORT
      LAYER M4 ;
      RECT 0.000 44.256 0.192 44.280 ;
    END
  END rec_in[436]
  PIN rec_in[437]
    DIRECTION INPUT ;
    USE SIGNAL ;
    SHAPE ABUTMENT ;
    PORT
      LAYER M4 ;
      RECT 0.000 44.400 0.192 44.424 ;
    END
  END rec_in[437]
  PIN rec_in[438]
    DIRECTION INPUT ;
    USE SIGNAL ;
    SHAPE ABUTMENT ;
    PORT
      LAYER M4 ;
      RECT 0.000 44.496 0.192 44.520 ;
    END
  END rec_in[438]
  PIN rec_in[439]
    DIRECTION INPUT ;
    USE SIGNAL ;
    SHAPE ABUTMENT ;
    PORT
      LAYER M4 ;
      RECT 0.000 44.592 0.192 44.616 ;
    END
  END rec_in[439]
  PIN rec_in[440]
    DIRECTION INPUT ;
    USE SIGNAL ;
    SHAPE ABUTMENT ;
    PORT
      LAYER M4 ;
      RECT 0.000 44.688 0.192 44.712 ;
    END
  END rec_in[440]
  PIN rec_in[441]
    DIRECTION INPUT ;
    USE SIGNAL ;
    SHAPE ABUTMENT ;
    PORT
      LAYER M4 ;
      RECT 0.000 44.784 0.192 44.808 ;
    END
  END rec_in[441]
  PIN rec_in[442]
    DIRECTION INPUT ;
    USE SIGNAL ;
    SHAPE ABUTMENT ;
    PORT
      LAYER M4 ;
      RECT 0.000 44.880 0.192 44.904 ;
    END
  END rec_in[442]
  PIN rec_in[443]
    DIRECTION INPUT ;
    USE SIGNAL ;
    SHAPE ABUTMENT ;
    PORT
      LAYER M4 ;
      RECT 0.000 44.976 0.192 45.000 ;
    END
  END rec_in[443]
  PIN rec_in[444]
    DIRECTION INPUT ;
    USE SIGNAL ;
    SHAPE ABUTMENT ;
    PORT
      LAYER M4 ;
      RECT 0.000 45.072 0.192 45.096 ;
    END
  END rec_in[444]
  PIN rec_in[445]
    DIRECTION INPUT ;
    USE SIGNAL ;
    SHAPE ABUTMENT ;
    PORT
      LAYER M4 ;
      RECT 0.000 45.168 0.192 45.192 ;
    END
  END rec_in[445]
  PIN rec_in[446]
    DIRECTION INPUT ;
    USE SIGNAL ;
    SHAPE ABUTMENT ;
    PORT
      LAYER M4 ;
      RECT 0.000 45.264 0.192 45.288 ;
    END
  END rec_in[446]
  PIN rec_in[447]
    DIRECTION INPUT ;
    USE SIGNAL ;
    SHAPE ABUTMENT ;
    PORT
      LAYER M4 ;
      RECT 0.000 45.360 0.192 45.384 ;
    END
  END rec_in[447]
  PIN rec_in[448]
    DIRECTION INPUT ;
    USE SIGNAL ;
    SHAPE ABUTMENT ;
    PORT
      LAYER M4 ;
      RECT 0.000 45.456 0.192 45.480 ;
    END
  END rec_in[448]
  PIN rec_in[449]
    DIRECTION INPUT ;
    USE SIGNAL ;
    SHAPE ABUTMENT ;
    PORT
      LAYER M4 ;
      RECT 0.000 45.600 0.192 45.624 ;
    END
  END rec_in[449]
  PIN rec_in[450]
    DIRECTION INPUT ;
    USE SIGNAL ;
    SHAPE ABUTMENT ;
    PORT
      LAYER M4 ;
      RECT 0.000 45.696 0.192 45.720 ;
    END
  END rec_in[450]
  PIN rec_in[451]
    DIRECTION INPUT ;
    USE SIGNAL ;
    SHAPE ABUTMENT ;
    PORT
      LAYER M4 ;
      RECT 0.000 45.792 0.192 45.816 ;
    END
  END rec_in[451]
  PIN rec_in[452]
    DIRECTION INPUT ;
    USE SIGNAL ;
    SHAPE ABUTMENT ;
    PORT
      LAYER M4 ;
      RECT 0.000 45.888 0.192 45.912 ;
    END
  END rec_in[452]
  PIN rec_in[453]
    DIRECTION INPUT ;
    USE SIGNAL ;
    SHAPE ABUTMENT ;
    PORT
      LAYER M4 ;
      RECT 0.000 45.984 0.192 46.008 ;
    END
  END rec_in[453]
  PIN rec_in[454]
    DIRECTION INPUT ;
    USE SIGNAL ;
    SHAPE ABUTMENT ;
    PORT
      LAYER M4 ;
      RECT 0.000 46.080 0.192 46.104 ;
    END
  END rec_in[454]
  PIN rec_in[455]
    DIRECTION INPUT ;
    USE SIGNAL ;
    SHAPE ABUTMENT ;
    PORT
      LAYER M4 ;
      RECT 0.000 46.176 0.192 46.200 ;
    END
  END rec_in[455]
  PIN rec_in[456]
    DIRECTION INPUT ;
    USE SIGNAL ;
    SHAPE ABUTMENT ;
    PORT
      LAYER M4 ;
      RECT 0.000 46.272 0.192 46.296 ;
    END
  END rec_in[456]
  PIN rec_in[457]
    DIRECTION INPUT ;
    USE SIGNAL ;
    SHAPE ABUTMENT ;
    PORT
      LAYER M4 ;
      RECT 0.000 46.368 0.192 46.392 ;
    END
  END rec_in[457]
  PIN rec_in[458]
    DIRECTION INPUT ;
    USE SIGNAL ;
    SHAPE ABUTMENT ;
    PORT
      LAYER M4 ;
      RECT 0.000 46.464 0.192 46.488 ;
    END
  END rec_in[458]
  PIN rec_in[459]
    DIRECTION INPUT ;
    USE SIGNAL ;
    SHAPE ABUTMENT ;
    PORT
      LAYER M4 ;
      RECT 0.000 46.560 0.192 46.584 ;
    END
  END rec_in[459]
  PIN rec_in[460]
    DIRECTION INPUT ;
    USE SIGNAL ;
    SHAPE ABUTMENT ;
    PORT
      LAYER M4 ;
      RECT 0.000 46.656 0.192 46.680 ;
    END
  END rec_in[460]
  PIN rec_in[461]
    DIRECTION INPUT ;
    USE SIGNAL ;
    SHAPE ABUTMENT ;
    PORT
      LAYER M4 ;
      RECT 0.000 46.800 0.192 46.824 ;
    END
  END rec_in[461]
  PIN rec_in[462]
    DIRECTION INPUT ;
    USE SIGNAL ;
    SHAPE ABUTMENT ;
    PORT
      LAYER M4 ;
      RECT 0.000 46.896 0.192 46.920 ;
    END
  END rec_in[462]
  PIN rec_in[463]
    DIRECTION INPUT ;
    USE SIGNAL ;
    SHAPE ABUTMENT ;
    PORT
      LAYER M4 ;
      RECT 0.000 46.992 0.192 47.016 ;
    END
  END rec_in[463]
  PIN rec_in[464]
    DIRECTION INPUT ;
    USE SIGNAL ;
    SHAPE ABUTMENT ;
    PORT
      LAYER M4 ;
      RECT 0.000 47.088 0.192 47.112 ;
    END
  END rec_in[464]
  PIN rec_in[465]
    DIRECTION INPUT ;
    USE SIGNAL ;
    SHAPE ABUTMENT ;
    PORT
      LAYER M4 ;
      RECT 0.000 47.184 0.192 47.208 ;
    END
  END rec_in[465]
  PIN rec_in[466]
    DIRECTION INPUT ;
    USE SIGNAL ;
    SHAPE ABUTMENT ;
    PORT
      LAYER M4 ;
      RECT 0.000 47.280 0.192 47.304 ;
    END
  END rec_in[466]
  PIN rec_in[467]
    DIRECTION INPUT ;
    USE SIGNAL ;
    SHAPE ABUTMENT ;
    PORT
      LAYER M4 ;
      RECT 0.000 47.376 0.192 47.400 ;
    END
  END rec_in[467]
  PIN rec_in[468]
    DIRECTION INPUT ;
    USE SIGNAL ;
    SHAPE ABUTMENT ;
    PORT
      LAYER M4 ;
      RECT 0.000 47.472 0.192 47.496 ;
    END
  END rec_in[468]
  PIN rec_in[469]
    DIRECTION INPUT ;
    USE SIGNAL ;
    SHAPE ABUTMENT ;
    PORT
      LAYER M4 ;
      RECT 0.000 47.568 0.192 47.592 ;
    END
  END rec_in[469]
  PIN rec_in[470]
    DIRECTION INPUT ;
    USE SIGNAL ;
    SHAPE ABUTMENT ;
    PORT
      LAYER M4 ;
      RECT 0.000 47.664 0.192 47.688 ;
    END
  END rec_in[470]
  PIN rec_in[471]
    DIRECTION INPUT ;
    USE SIGNAL ;
    SHAPE ABUTMENT ;
    PORT
      LAYER M4 ;
      RECT 0.000 47.760 0.192 47.784 ;
    END
  END rec_in[471]
  PIN rec_in[472]
    DIRECTION INPUT ;
    USE SIGNAL ;
    SHAPE ABUTMENT ;
    PORT
      LAYER M4 ;
      RECT 0.000 47.904 0.192 47.928 ;
    END
  END rec_in[472]
  PIN rec_in[473]
    DIRECTION INPUT ;
    USE SIGNAL ;
    SHAPE ABUTMENT ;
    PORT
      LAYER M4 ;
      RECT 0.000 48.000 0.192 48.024 ;
    END
  END rec_in[473]
  PIN rec_in[474]
    DIRECTION INPUT ;
    USE SIGNAL ;
    SHAPE ABUTMENT ;
    PORT
      LAYER M4 ;
      RECT 0.000 48.096 0.192 48.120 ;
    END
  END rec_in[474]
  PIN rec_in[475]
    DIRECTION INPUT ;
    USE SIGNAL ;
    SHAPE ABUTMENT ;
    PORT
      LAYER M4 ;
      RECT 0.000 48.192 0.192 48.216 ;
    END
  END rec_in[475]
  PIN rec_in[476]
    DIRECTION INPUT ;
    USE SIGNAL ;
    SHAPE ABUTMENT ;
    PORT
      LAYER M4 ;
      RECT 0.000 48.288 0.192 48.312 ;
    END
  END rec_in[476]
  PIN rec_in[477]
    DIRECTION INPUT ;
    USE SIGNAL ;
    SHAPE ABUTMENT ;
    PORT
      LAYER M4 ;
      RECT 0.000 48.384 0.192 48.408 ;
    END
  END rec_in[477]
  PIN rec_in[478]
    DIRECTION INPUT ;
    USE SIGNAL ;
    SHAPE ABUTMENT ;
    PORT
      LAYER M4 ;
      RECT 0.000 48.480 0.192 48.504 ;
    END
  END rec_in[478]
  PIN rec_in[479]
    DIRECTION INPUT ;
    USE SIGNAL ;
    SHAPE ABUTMENT ;
    PORT
      LAYER M4 ;
      RECT 0.000 48.576 0.192 48.600 ;
    END
  END rec_in[479]
  PIN rec_in[480]
    DIRECTION INPUT ;
    USE SIGNAL ;
    SHAPE ABUTMENT ;
    PORT
      LAYER M4 ;
      RECT 0.000 48.672 0.192 48.696 ;
    END
  END rec_in[480]
  PIN rec_in[481]
    DIRECTION INPUT ;
    USE SIGNAL ;
    SHAPE ABUTMENT ;
    PORT
      LAYER M4 ;
      RECT 0.000 48.768 0.192 48.792 ;
    END
  END rec_in[481]
  PIN rec_in[482]
    DIRECTION INPUT ;
    USE SIGNAL ;
    SHAPE ABUTMENT ;
    PORT
      LAYER M4 ;
      RECT 0.000 48.864 0.192 48.888 ;
    END
  END rec_in[482]
  PIN rec_in[483]
    DIRECTION INPUT ;
    USE SIGNAL ;
    SHAPE ABUTMENT ;
    PORT
      LAYER M4 ;
      RECT 0.000 48.960 0.192 48.984 ;
    END
  END rec_in[483]
  PIN rec_in[484]
    DIRECTION INPUT ;
    USE SIGNAL ;
    SHAPE ABUTMENT ;
    PORT
      LAYER M4 ;
      RECT 0.000 49.104 0.192 49.128 ;
    END
  END rec_in[484]
  PIN rec_in[485]
    DIRECTION INPUT ;
    USE SIGNAL ;
    SHAPE ABUTMENT ;
    PORT
      LAYER M4 ;
      RECT 0.000 49.200 0.192 49.224 ;
    END
  END rec_in[485]
  PIN rec_in[486]
    DIRECTION INPUT ;
    USE SIGNAL ;
    SHAPE ABUTMENT ;
    PORT
      LAYER M4 ;
      RECT 0.000 49.296 0.192 49.320 ;
    END
  END rec_in[486]
  PIN rec_in[487]
    DIRECTION INPUT ;
    USE SIGNAL ;
    SHAPE ABUTMENT ;
    PORT
      LAYER M4 ;
      RECT 0.000 49.392 0.192 49.416 ;
    END
  END rec_in[487]
  PIN rec_in[488]
    DIRECTION INPUT ;
    USE SIGNAL ;
    SHAPE ABUTMENT ;
    PORT
      LAYER M4 ;
      RECT 0.000 49.488 0.192 49.512 ;
    END
  END rec_in[488]
  PIN rec_in[489]
    DIRECTION INPUT ;
    USE SIGNAL ;
    SHAPE ABUTMENT ;
    PORT
      LAYER M4 ;
      RECT 0.000 49.584 0.192 49.608 ;
    END
  END rec_in[489]
  PIN rec_in[490]
    DIRECTION INPUT ;
    USE SIGNAL ;
    SHAPE ABUTMENT ;
    PORT
      LAYER M4 ;
      RECT 0.000 49.680 0.192 49.704 ;
    END
  END rec_in[490]
  PIN rec_in[491]
    DIRECTION INPUT ;
    USE SIGNAL ;
    SHAPE ABUTMENT ;
    PORT
      LAYER M4 ;
      RECT 0.000 49.776 0.192 49.800 ;
    END
  END rec_in[491]
  PIN rec_in[492]
    DIRECTION INPUT ;
    USE SIGNAL ;
    SHAPE ABUTMENT ;
    PORT
      LAYER M4 ;
      RECT 0.000 49.872 0.192 49.896 ;
    END
  END rec_in[492]
  PIN rec_in[493]
    DIRECTION INPUT ;
    USE SIGNAL ;
    SHAPE ABUTMENT ;
    PORT
      LAYER M4 ;
      RECT 0.000 49.968 0.192 49.992 ;
    END
  END rec_in[493]
  PIN rec_in[494]
    DIRECTION INPUT ;
    USE SIGNAL ;
    SHAPE ABUTMENT ;
    PORT
      LAYER M4 ;
      RECT 0.000 50.064 0.192 50.088 ;
    END
  END rec_in[494]
  PIN rec_in[495]
    DIRECTION INPUT ;
    USE SIGNAL ;
    SHAPE ABUTMENT ;
    PORT
      LAYER M4 ;
      RECT 0.000 50.208 0.192 50.232 ;
    END
  END rec_in[495]
  PIN rec_in[496]
    DIRECTION INPUT ;
    USE SIGNAL ;
    SHAPE ABUTMENT ;
    PORT
      LAYER M4 ;
      RECT 0.000 50.304 0.192 50.328 ;
    END
  END rec_in[496]
  PIN rec_in[497]
    DIRECTION INPUT ;
    USE SIGNAL ;
    SHAPE ABUTMENT ;
    PORT
      LAYER M4 ;
      RECT 0.000 50.400 0.192 50.424 ;
    END
  END rec_in[497]
  PIN rec_in[498]
    DIRECTION INPUT ;
    USE SIGNAL ;
    SHAPE ABUTMENT ;
    PORT
      LAYER M4 ;
      RECT 0.000 50.496 0.192 50.520 ;
    END
  END rec_in[498]
  PIN rec_in[499]
    DIRECTION INPUT ;
    USE SIGNAL ;
    SHAPE ABUTMENT ;
    PORT
      LAYER M4 ;
      RECT 0.000 50.592 0.192 50.616 ;
    END
  END rec_in[499]
  PIN rec_in[500]
    DIRECTION INPUT ;
    USE SIGNAL ;
    SHAPE ABUTMENT ;
    PORT
      LAYER M4 ;
      RECT 0.000 50.688 0.192 50.712 ;
    END
  END rec_in[500]
  PIN rec_in[501]
    DIRECTION INPUT ;
    USE SIGNAL ;
    SHAPE ABUTMENT ;
    PORT
      LAYER M4 ;
      RECT 0.000 50.784 0.192 50.808 ;
    END
  END rec_in[501]
  PIN rec_in[502]
    DIRECTION INPUT ;
    USE SIGNAL ;
    SHAPE ABUTMENT ;
    PORT
      LAYER M4 ;
      RECT 0.000 50.880 0.192 50.904 ;
    END
  END rec_in[502]
  PIN rec_in[503]
    DIRECTION INPUT ;
    USE SIGNAL ;
    SHAPE ABUTMENT ;
    PORT
      LAYER M4 ;
      RECT 0.000 50.976 0.192 51.000 ;
    END
  END rec_in[503]
  PIN rec_in[504]
    DIRECTION INPUT ;
    USE SIGNAL ;
    SHAPE ABUTMENT ;
    PORT
      LAYER M4 ;
      RECT 0.000 51.072 0.192 51.096 ;
    END
  END rec_in[504]
  PIN rec_in[505]
    DIRECTION INPUT ;
    USE SIGNAL ;
    SHAPE ABUTMENT ;
    PORT
      LAYER M4 ;
      RECT 0.000 51.168 0.192 51.192 ;
    END
  END rec_in[505]
  PIN rec_in[506]
    DIRECTION INPUT ;
    USE SIGNAL ;
    SHAPE ABUTMENT ;
    PORT
      LAYER M4 ;
      RECT 0.000 51.264 0.192 51.288 ;
    END
  END rec_in[506]
  PIN rec_in[507]
    DIRECTION INPUT ;
    USE SIGNAL ;
    SHAPE ABUTMENT ;
    PORT
      LAYER M4 ;
      RECT 0.000 51.408 0.192 51.432 ;
    END
  END rec_in[507]
  PIN rec_in[508]
    DIRECTION INPUT ;
    USE SIGNAL ;
    SHAPE ABUTMENT ;
    PORT
      LAYER M4 ;
      RECT 0.000 51.504 0.192 51.528 ;
    END
  END rec_in[508]
  PIN rec_in[509]
    DIRECTION INPUT ;
    USE SIGNAL ;
    SHAPE ABUTMENT ;
    PORT
      LAYER M4 ;
      RECT 0.000 51.600 0.192 51.624 ;
    END
  END rec_in[509]
  PIN rec_in[510]
    DIRECTION INPUT ;
    USE SIGNAL ;
    SHAPE ABUTMENT ;
    PORT
      LAYER M4 ;
      RECT 0.000 51.696 0.192 51.720 ;
    END
  END rec_in[510]
  PIN rec_in[511]
    DIRECTION INPUT ;
    USE SIGNAL ;
    SHAPE ABUTMENT ;
    PORT
      LAYER M4 ;
      RECT 0.000 51.792 0.192 51.816 ;
    END
  END rec_in[511]
  PIN rec_in[512]
    DIRECTION INPUT ;
    USE SIGNAL ;
    SHAPE ABUTMENT ;
    PORT
      LAYER M4 ;
      RECT 0.000 51.888 0.192 51.912 ;
    END
  END rec_in[512]
  PIN rec_in[513]
    DIRECTION INPUT ;
    USE SIGNAL ;
    SHAPE ABUTMENT ;
    PORT
      LAYER M4 ;
      RECT 0.000 51.984 0.192 52.008 ;
    END
  END rec_in[513]
  PIN rec_in[514]
    DIRECTION INPUT ;
    USE SIGNAL ;
    SHAPE ABUTMENT ;
    PORT
      LAYER M4 ;
      RECT 0.000 52.080 0.192 52.104 ;
    END
  END rec_in[514]
  PIN rec_in[515]
    DIRECTION INPUT ;
    USE SIGNAL ;
    SHAPE ABUTMENT ;
    PORT
      LAYER M4 ;
      RECT 0.000 52.176 0.192 52.200 ;
    END
  END rec_in[515]
  PIN rec_in[516]
    DIRECTION INPUT ;
    USE SIGNAL ;
    SHAPE ABUTMENT ;
    PORT
      LAYER M4 ;
      RECT 0.000 52.272 0.192 52.296 ;
    END
  END rec_in[516]
  PIN rec_in[517]
    DIRECTION INPUT ;
    USE SIGNAL ;
    SHAPE ABUTMENT ;
    PORT
      LAYER M4 ;
      RECT 0.000 52.368 0.192 52.392 ;
    END
  END rec_in[517]
  PIN rec_in[518]
    DIRECTION INPUT ;
    USE SIGNAL ;
    SHAPE ABUTMENT ;
    PORT
      LAYER M4 ;
      RECT 0.000 52.512 0.192 52.536 ;
    END
  END rec_in[518]
  PIN rec_in[519]
    DIRECTION INPUT ;
    USE SIGNAL ;
    SHAPE ABUTMENT ;
    PORT
      LAYER M4 ;
      RECT 0.000 52.608 0.192 52.632 ;
    END
  END rec_in[519]
  PIN rec_in[520]
    DIRECTION INPUT ;
    USE SIGNAL ;
    SHAPE ABUTMENT ;
    PORT
      LAYER M4 ;
      RECT 0.000 52.704 0.192 52.728 ;
    END
  END rec_in[520]
  PIN rec_in[521]
    DIRECTION INPUT ;
    USE SIGNAL ;
    SHAPE ABUTMENT ;
    PORT
      LAYER M4 ;
      RECT 0.000 52.800 0.192 52.824 ;
    END
  END rec_in[521]
  PIN rec_in[522]
    DIRECTION INPUT ;
    USE SIGNAL ;
    SHAPE ABUTMENT ;
    PORT
      LAYER M4 ;
      RECT 0.000 52.896 0.192 52.920 ;
    END
  END rec_in[522]
  PIN rec_in[523]
    DIRECTION INPUT ;
    USE SIGNAL ;
    SHAPE ABUTMENT ;
    PORT
      LAYER M4 ;
      RECT 0.000 52.992 0.192 53.016 ;
    END
  END rec_in[523]
  PIN rec_in[524]
    DIRECTION INPUT ;
    USE SIGNAL ;
    SHAPE ABUTMENT ;
    PORT
      LAYER M4 ;
      RECT 0.000 53.088 0.192 53.112 ;
    END
  END rec_in[524]
  PIN rec_in[525]
    DIRECTION INPUT ;
    USE SIGNAL ;
    SHAPE ABUTMENT ;
    PORT
      LAYER M4 ;
      RECT 0.000 53.184 0.192 53.208 ;
    END
  END rec_in[525]
  PIN rec_in[526]
    DIRECTION INPUT ;
    USE SIGNAL ;
    SHAPE ABUTMENT ;
    PORT
      LAYER M4 ;
      RECT 0.000 53.280 0.192 53.304 ;
    END
  END rec_in[526]
  PIN rec_in[527]
    DIRECTION INPUT ;
    USE SIGNAL ;
    SHAPE ABUTMENT ;
    PORT
      LAYER M4 ;
      RECT 0.000 53.376 0.192 53.400 ;
    END
  END rec_in[527]
  PIN rec_in[528]
    DIRECTION INPUT ;
    USE SIGNAL ;
    SHAPE ABUTMENT ;
    PORT
      LAYER M4 ;
      RECT 0.000 53.472 0.192 53.496 ;
    END
  END rec_in[528]
  PIN rec_in[529]
    DIRECTION INPUT ;
    USE SIGNAL ;
    SHAPE ABUTMENT ;
    PORT
      LAYER M4 ;
      RECT 0.000 53.568 0.192 53.592 ;
    END
  END rec_in[529]
  PIN rec_in[530]
    DIRECTION INPUT ;
    USE SIGNAL ;
    SHAPE ABUTMENT ;
    PORT
      LAYER M4 ;
      RECT 0.000 53.712 0.192 53.736 ;
    END
  END rec_in[530]
  PIN rec_in[531]
    DIRECTION INPUT ;
    USE SIGNAL ;
    SHAPE ABUTMENT ;
    PORT
      LAYER M4 ;
      RECT 0.000 53.808 0.192 53.832 ;
    END
  END rec_in[531]
  PIN rec_in[532]
    DIRECTION INPUT ;
    USE SIGNAL ;
    SHAPE ABUTMENT ;
    PORT
      LAYER M4 ;
      RECT 0.000 53.904 0.192 53.928 ;
    END
  END rec_in[532]
  PIN rec_in[533]
    DIRECTION INPUT ;
    USE SIGNAL ;
    SHAPE ABUTMENT ;
    PORT
      LAYER M4 ;
      RECT 0.000 54.000 0.192 54.024 ;
    END
  END rec_in[533]
  PIN rec_in[534]
    DIRECTION INPUT ;
    USE SIGNAL ;
    SHAPE ABUTMENT ;
    PORT
      LAYER M4 ;
      RECT 0.000 54.096 0.192 54.120 ;
    END
  END rec_in[534]
  PIN rec_in[535]
    DIRECTION INPUT ;
    USE SIGNAL ;
    SHAPE ABUTMENT ;
    PORT
      LAYER M4 ;
      RECT 0.000 54.192 0.192 54.216 ;
    END
  END rec_in[535]
  PIN rec_in[536]
    DIRECTION INPUT ;
    USE SIGNAL ;
    SHAPE ABUTMENT ;
    PORT
      LAYER M4 ;
      RECT 0.000 54.288 0.192 54.312 ;
    END
  END rec_in[536]
  PIN rec_in[537]
    DIRECTION INPUT ;
    USE SIGNAL ;
    SHAPE ABUTMENT ;
    PORT
      LAYER M4 ;
      RECT 0.000 54.384 0.192 54.408 ;
    END
  END rec_in[537]
  PIN rec_in[538]
    DIRECTION INPUT ;
    USE SIGNAL ;
    SHAPE ABUTMENT ;
    PORT
      LAYER M4 ;
      RECT 0.000 54.480 0.192 54.504 ;
    END
  END rec_in[538]
  PIN rec_in[539]
    DIRECTION INPUT ;
    USE SIGNAL ;
    SHAPE ABUTMENT ;
    PORT
      LAYER M4 ;
      RECT 0.000 54.576 0.192 54.600 ;
    END
  END rec_in[539]
  PIN rec_in[540]
    DIRECTION INPUT ;
    USE SIGNAL ;
    SHAPE ABUTMENT ;
    PORT
      LAYER M4 ;
      RECT 0.000 54.672 0.192 54.696 ;
    END
  END rec_in[540]
  PIN rec_in[541]
    DIRECTION INPUT ;
    USE SIGNAL ;
    SHAPE ABUTMENT ;
    PORT
      LAYER M4 ;
      RECT 0.000 54.816 0.192 54.840 ;
    END
  END rec_in[541]
  PIN rec_in[542]
    DIRECTION INPUT ;
    USE SIGNAL ;
    SHAPE ABUTMENT ;
    PORT
      LAYER M4 ;
      RECT 0.000 54.912 0.192 54.936 ;
    END
  END rec_in[542]
  PIN rec_in[543]
    DIRECTION INPUT ;
    USE SIGNAL ;
    SHAPE ABUTMENT ;
    PORT
      LAYER M4 ;
      RECT 0.000 55.008 0.192 55.032 ;
    END
  END rec_in[543]
  PIN rec_in[544]
    DIRECTION INPUT ;
    USE SIGNAL ;
    SHAPE ABUTMENT ;
    PORT
      LAYER M4 ;
      RECT 0.000 55.104 0.192 55.128 ;
    END
  END rec_in[544]
  PIN rec_in[545]
    DIRECTION INPUT ;
    USE SIGNAL ;
    SHAPE ABUTMENT ;
    PORT
      LAYER M4 ;
      RECT 0.000 55.200 0.192 55.224 ;
    END
  END rec_in[545]
  PIN rec_in[546]
    DIRECTION INPUT ;
    USE SIGNAL ;
    SHAPE ABUTMENT ;
    PORT
      LAYER M4 ;
      RECT 0.000 55.296 0.192 55.320 ;
    END
  END rec_in[546]
  PIN rec_out[0]
    DIRECTION OUTPUT ;
    USE SIGNAL ;
    SHAPE ABUTMENT ;
    PORT
      LAYER M4 ;
      RECT 0.000 55.392 0.192 55.416 ;
    END
  END rec_out[0]
  PIN rec_out[1]
    DIRECTION OUTPUT ;
    USE SIGNAL ;
    SHAPE ABUTMENT ;
    PORT
      LAYER M4 ;
      RECT 0.000 55.488 0.192 55.512 ;
    END
  END rec_out[1]
  PIN rec_out[2]
    DIRECTION OUTPUT ;
    USE SIGNAL ;
    SHAPE ABUTMENT ;
    PORT
      LAYER M4 ;
      RECT 0.000 55.584 0.192 55.608 ;
    END
  END rec_out[2]
  PIN rec_out[3]
    DIRECTION OUTPUT ;
    USE SIGNAL ;
    SHAPE ABUTMENT ;
    PORT
      LAYER M4 ;
      RECT 0.000 55.680 0.192 55.704 ;
    END
  END rec_out[3]
  PIN rec_out[4]
    DIRECTION OUTPUT ;
    USE SIGNAL ;
    SHAPE ABUTMENT ;
    PORT
      LAYER M4 ;
      RECT 0.000 55.776 0.192 55.800 ;
    END
  END rec_out[4]
  PIN rec_out[5]
    DIRECTION OUTPUT ;
    USE SIGNAL ;
    SHAPE ABUTMENT ;
    PORT
      LAYER M4 ;
      RECT 0.000 55.872 0.192 55.896 ;
    END
  END rec_out[5]
  PIN rec_out[6]
    DIRECTION OUTPUT ;
    USE SIGNAL ;
    SHAPE ABUTMENT ;
    PORT
      LAYER M4 ;
      RECT 0.000 56.016 0.192 56.040 ;
    END
  END rec_out[6]
  PIN rec_out[7]
    DIRECTION OUTPUT ;
    USE SIGNAL ;
    SHAPE ABUTMENT ;
    PORT
      LAYER M4 ;
      RECT 0.000 56.112 0.192 56.136 ;
    END
  END rec_out[7]
  PIN rec_out[8]
    DIRECTION OUTPUT ;
    USE SIGNAL ;
    SHAPE ABUTMENT ;
    PORT
      LAYER M4 ;
      RECT 0.000 56.208 0.192 56.232 ;
    END
  END rec_out[8]
  PIN rec_out[9]
    DIRECTION OUTPUT ;
    USE SIGNAL ;
    SHAPE ABUTMENT ;
    PORT
      LAYER M4 ;
      RECT 0.000 56.304 0.192 56.328 ;
    END
  END rec_out[9]
  PIN rec_out[10]
    DIRECTION OUTPUT ;
    USE SIGNAL ;
    SHAPE ABUTMENT ;
    PORT
      LAYER M4 ;
      RECT 0.000 56.400 0.192 56.424 ;
    END
  END rec_out[10]
  PIN rec_out[11]
    DIRECTION OUTPUT ;
    USE SIGNAL ;
    SHAPE ABUTMENT ;
    PORT
      LAYER M4 ;
      RECT 0.000 56.496 0.192 56.520 ;
    END
  END rec_out[11]
  PIN rec_out[12]
    DIRECTION OUTPUT ;
    USE SIGNAL ;
    SHAPE ABUTMENT ;
    PORT
      LAYER M4 ;
      RECT 0.000 56.592 0.192 56.616 ;
    END
  END rec_out[12]
  PIN rec_out[13]
    DIRECTION OUTPUT ;
    USE SIGNAL ;
    SHAPE ABUTMENT ;
    PORT
      LAYER M4 ;
      RECT 0.000 56.688 0.192 56.712 ;
    END
  END rec_out[13]
  PIN rec_out[14]
    DIRECTION OUTPUT ;
    USE SIGNAL ;
    SHAPE ABUTMENT ;
    PORT
      LAYER M4 ;
      RECT 0.000 56.784 0.192 56.808 ;
    END
  END rec_out[14]
  PIN rec_out[15]
    DIRECTION OUTPUT ;
    USE SIGNAL ;
    SHAPE ABUTMENT ;
    PORT
      LAYER M4 ;
      RECT 0.000 56.880 0.192 56.904 ;
    END
  END rec_out[15]
  PIN rec_out[16]
    DIRECTION OUTPUT ;
    USE SIGNAL ;
    SHAPE ABUTMENT ;
    PORT
      LAYER M4 ;
      RECT 0.000 56.976 0.192 57.000 ;
    END
  END rec_out[16]
  PIN rec_out[17]
    DIRECTION OUTPUT ;
    USE SIGNAL ;
    SHAPE ABUTMENT ;
    PORT
      LAYER M4 ;
      RECT 0.000 57.120 0.192 57.144 ;
    END
  END rec_out[17]
  PIN rec_out[18]
    DIRECTION OUTPUT ;
    USE SIGNAL ;
    SHAPE ABUTMENT ;
    PORT
      LAYER M4 ;
      RECT 0.000 57.216 0.192 57.240 ;
    END
  END rec_out[18]
  PIN rec_out[19]
    DIRECTION OUTPUT ;
    USE SIGNAL ;
    SHAPE ABUTMENT ;
    PORT
      LAYER M4 ;
      RECT 0.000 57.312 0.192 57.336 ;
    END
  END rec_out[19]
  PIN rec_out[20]
    DIRECTION OUTPUT ;
    USE SIGNAL ;
    SHAPE ABUTMENT ;
    PORT
      LAYER M4 ;
      RECT 0.000 57.408 0.192 57.432 ;
    END
  END rec_out[20]
  PIN rec_out[21]
    DIRECTION OUTPUT ;
    USE SIGNAL ;
    SHAPE ABUTMENT ;
    PORT
      LAYER M4 ;
      RECT 0.000 57.504 0.192 57.528 ;
    END
  END rec_out[21]
  PIN rec_out[22]
    DIRECTION OUTPUT ;
    USE SIGNAL ;
    SHAPE ABUTMENT ;
    PORT
      LAYER M4 ;
      RECT 0.000 57.600 0.192 57.624 ;
    END
  END rec_out[22]
  PIN rec_out[23]
    DIRECTION OUTPUT ;
    USE SIGNAL ;
    SHAPE ABUTMENT ;
    PORT
      LAYER M4 ;
      RECT 0.000 57.696 0.192 57.720 ;
    END
  END rec_out[23]
  PIN rec_out[24]
    DIRECTION OUTPUT ;
    USE SIGNAL ;
    SHAPE ABUTMENT ;
    PORT
      LAYER M4 ;
      RECT 0.000 57.792 0.192 57.816 ;
    END
  END rec_out[24]
  PIN rec_out[25]
    DIRECTION OUTPUT ;
    USE SIGNAL ;
    SHAPE ABUTMENT ;
    PORT
      LAYER M4 ;
      RECT 0.000 57.888 0.192 57.912 ;
    END
  END rec_out[25]
  PIN rec_out[26]
    DIRECTION OUTPUT ;
    USE SIGNAL ;
    SHAPE ABUTMENT ;
    PORT
      LAYER M4 ;
      RECT 0.000 57.984 0.192 58.008 ;
    END
  END rec_out[26]
  PIN rec_out[27]
    DIRECTION OUTPUT ;
    USE SIGNAL ;
    SHAPE ABUTMENT ;
    PORT
      LAYER M4 ;
      RECT 0.000 58.080 0.192 58.104 ;
    END
  END rec_out[27]
  PIN rec_out[28]
    DIRECTION OUTPUT ;
    USE SIGNAL ;
    SHAPE ABUTMENT ;
    PORT
      LAYER M4 ;
      RECT 0.000 58.176 0.192 58.200 ;
    END
  END rec_out[28]
  PIN rec_out[29]
    DIRECTION OUTPUT ;
    USE SIGNAL ;
    SHAPE ABUTMENT ;
    PORT
      LAYER M4 ;
      RECT 0.000 58.320 0.192 58.344 ;
    END
  END rec_out[29]
  PIN rec_out[30]
    DIRECTION OUTPUT ;
    USE SIGNAL ;
    SHAPE ABUTMENT ;
    PORT
      LAYER M4 ;
      RECT 0.000 58.416 0.192 58.440 ;
    END
  END rec_out[30]
  PIN rec_out[31]
    DIRECTION OUTPUT ;
    USE SIGNAL ;
    SHAPE ABUTMENT ;
    PORT
      LAYER M4 ;
      RECT 0.000 58.512 0.192 58.536 ;
    END
  END rec_out[31]
  PIN rec_out[32]
    DIRECTION OUTPUT ;
    USE SIGNAL ;
    SHAPE ABUTMENT ;
    PORT
      LAYER M4 ;
      RECT 0.000 58.608 0.192 58.632 ;
    END
  END rec_out[32]
  PIN rec_out[33]
    DIRECTION OUTPUT ;
    USE SIGNAL ;
    SHAPE ABUTMENT ;
    PORT
      LAYER M4 ;
      RECT 0.000 58.704 0.192 58.728 ;
    END
  END rec_out[33]
  PIN rec_out[34]
    DIRECTION OUTPUT ;
    USE SIGNAL ;
    SHAPE ABUTMENT ;
    PORT
      LAYER M4 ;
      RECT 0.000 58.800 0.192 58.824 ;
    END
  END rec_out[34]
  PIN rec_out[35]
    DIRECTION OUTPUT ;
    USE SIGNAL ;
    SHAPE ABUTMENT ;
    PORT
      LAYER M4 ;
      RECT 0.000 58.896 0.192 58.920 ;
    END
  END rec_out[35]
  PIN rec_out[36]
    DIRECTION OUTPUT ;
    USE SIGNAL ;
    SHAPE ABUTMENT ;
    PORT
      LAYER M4 ;
      RECT 0.000 58.992 0.192 59.016 ;
    END
  END rec_out[36]
  PIN rec_out[37]
    DIRECTION OUTPUT ;
    USE SIGNAL ;
    SHAPE ABUTMENT ;
    PORT
      LAYER M4 ;
      RECT 0.000 59.088 0.192 59.112 ;
    END
  END rec_out[37]
  PIN rec_out[38]
    DIRECTION OUTPUT ;
    USE SIGNAL ;
    SHAPE ABUTMENT ;
    PORT
      LAYER M4 ;
      RECT 0.000 59.184 0.192 59.208 ;
    END
  END rec_out[38]
  PIN rec_out[39]
    DIRECTION OUTPUT ;
    USE SIGNAL ;
    SHAPE ABUTMENT ;
    PORT
      LAYER M4 ;
      RECT 0.000 59.280 0.192 59.304 ;
    END
  END rec_out[39]
  PIN rec_out[40]
    DIRECTION OUTPUT ;
    USE SIGNAL ;
    SHAPE ABUTMENT ;
    PORT
      LAYER M4 ;
      RECT 0.000 59.424 0.192 59.448 ;
    END
  END rec_out[40]
  PIN rec_out[41]
    DIRECTION OUTPUT ;
    USE SIGNAL ;
    SHAPE ABUTMENT ;
    PORT
      LAYER M4 ;
      RECT 0.000 59.520 0.192 59.544 ;
    END
  END rec_out[41]
  PIN rec_out[42]
    DIRECTION OUTPUT ;
    USE SIGNAL ;
    SHAPE ABUTMENT ;
    PORT
      LAYER M4 ;
      RECT 0.000 59.616 0.192 59.640 ;
    END
  END rec_out[42]
  PIN rec_out[43]
    DIRECTION OUTPUT ;
    USE SIGNAL ;
    SHAPE ABUTMENT ;
    PORT
      LAYER M4 ;
      RECT 0.000 59.712 0.192 59.736 ;
    END
  END rec_out[43]
  PIN rec_out[44]
    DIRECTION OUTPUT ;
    USE SIGNAL ;
    SHAPE ABUTMENT ;
    PORT
      LAYER M4 ;
      RECT 0.000 59.808 0.192 59.832 ;
    END
  END rec_out[44]
  PIN rec_out[45]
    DIRECTION OUTPUT ;
    USE SIGNAL ;
    SHAPE ABUTMENT ;
    PORT
      LAYER M4 ;
      RECT 0.000 59.904 0.192 59.928 ;
    END
  END rec_out[45]
  PIN rec_out[46]
    DIRECTION OUTPUT ;
    USE SIGNAL ;
    SHAPE ABUTMENT ;
    PORT
      LAYER M4 ;
      RECT 0.000 60.000 0.192 60.024 ;
    END
  END rec_out[46]
  PIN rec_out[47]
    DIRECTION OUTPUT ;
    USE SIGNAL ;
    SHAPE ABUTMENT ;
    PORT
      LAYER M4 ;
      RECT 0.000 60.096 0.192 60.120 ;
    END
  END rec_out[47]
  PIN rec_out[48]
    DIRECTION OUTPUT ;
    USE SIGNAL ;
    SHAPE ABUTMENT ;
    PORT
      LAYER M4 ;
      RECT 0.000 60.192 0.192 60.216 ;
    END
  END rec_out[48]
  PIN rec_out[49]
    DIRECTION OUTPUT ;
    USE SIGNAL ;
    SHAPE ABUTMENT ;
    PORT
      LAYER M4 ;
      RECT 0.000 60.288 0.192 60.312 ;
    END
  END rec_out[49]
  PIN rec_out[50]
    DIRECTION OUTPUT ;
    USE SIGNAL ;
    SHAPE ABUTMENT ;
    PORT
      LAYER M4 ;
      RECT 0.000 60.384 0.192 60.408 ;
    END
  END rec_out[50]
  PIN rec_out[51]
    DIRECTION OUTPUT ;
    USE SIGNAL ;
    SHAPE ABUTMENT ;
    PORT
      LAYER M4 ;
      RECT 0.000 60.480 0.192 60.504 ;
    END
  END rec_out[51]
  PIN rec_out[52]
    DIRECTION OUTPUT ;
    USE SIGNAL ;
    SHAPE ABUTMENT ;
    PORT
      LAYER M4 ;
      RECT 0.000 60.624 0.192 60.648 ;
    END
  END rec_out[52]
  PIN rec_out[53]
    DIRECTION OUTPUT ;
    USE SIGNAL ;
    SHAPE ABUTMENT ;
    PORT
      LAYER M4 ;
      RECT 0.000 60.720 0.192 60.744 ;
    END
  END rec_out[53]
  PIN rec_out[54]
    DIRECTION OUTPUT ;
    USE SIGNAL ;
    SHAPE ABUTMENT ;
    PORT
      LAYER M4 ;
      RECT 0.000 60.816 0.192 60.840 ;
    END
  END rec_out[54]
  PIN rec_out[55]
    DIRECTION OUTPUT ;
    USE SIGNAL ;
    SHAPE ABUTMENT ;
    PORT
      LAYER M4 ;
      RECT 0.000 60.912 0.192 60.936 ;
    END
  END rec_out[55]
  PIN rec_out[56]
    DIRECTION OUTPUT ;
    USE SIGNAL ;
    SHAPE ABUTMENT ;
    PORT
      LAYER M4 ;
      RECT 0.000 61.008 0.192 61.032 ;
    END
  END rec_out[56]
  PIN rec_out[57]
    DIRECTION OUTPUT ;
    USE SIGNAL ;
    SHAPE ABUTMENT ;
    PORT
      LAYER M4 ;
      RECT 0.000 61.104 0.192 61.128 ;
    END
  END rec_out[57]
  PIN rec_out[58]
    DIRECTION OUTPUT ;
    USE SIGNAL ;
    SHAPE ABUTMENT ;
    PORT
      LAYER M4 ;
      RECT 0.000 61.200 0.192 61.224 ;
    END
  END rec_out[58]
  PIN rec_out[59]
    DIRECTION OUTPUT ;
    USE SIGNAL ;
    SHAPE ABUTMENT ;
    PORT
      LAYER M4 ;
      RECT 0.000 61.296 0.192 61.320 ;
    END
  END rec_out[59]
  PIN rec_out[60]
    DIRECTION OUTPUT ;
    USE SIGNAL ;
    SHAPE ABUTMENT ;
    PORT
      LAYER M4 ;
      RECT 0.000 61.392 0.192 61.416 ;
    END
  END rec_out[60]
  PIN rec_out[61]
    DIRECTION OUTPUT ;
    USE SIGNAL ;
    SHAPE ABUTMENT ;
    PORT
      LAYER M4 ;
      RECT 0.000 61.488 0.192 61.512 ;
    END
  END rec_out[61]
  PIN rec_out[62]
    DIRECTION OUTPUT ;
    USE SIGNAL ;
    SHAPE ABUTMENT ;
    PORT
      LAYER M4 ;
      RECT 0.000 61.584 0.192 61.608 ;
    END
  END rec_out[62]
  PIN rec_out[63]
    DIRECTION OUTPUT ;
    USE SIGNAL ;
    SHAPE ABUTMENT ;
    PORT
      LAYER M4 ;
      RECT 0.000 61.728 0.192 61.752 ;
    END
  END rec_out[63]
  PIN rec_out[64]
    DIRECTION OUTPUT ;
    USE SIGNAL ;
    SHAPE ABUTMENT ;
    PORT
      LAYER M4 ;
      RECT 0.000 61.824 0.192 61.848 ;
    END
  END rec_out[64]
  PIN rec_out[65]
    DIRECTION OUTPUT ;
    USE SIGNAL ;
    SHAPE ABUTMENT ;
    PORT
      LAYER M4 ;
      RECT 0.000 61.920 0.192 61.944 ;
    END
  END rec_out[65]
  PIN rec_out[66]
    DIRECTION OUTPUT ;
    USE SIGNAL ;
    SHAPE ABUTMENT ;
    PORT
      LAYER M4 ;
      RECT 0.000 62.016 0.192 62.040 ;
    END
  END rec_out[66]
  PIN rec_out[67]
    DIRECTION OUTPUT ;
    USE SIGNAL ;
    SHAPE ABUTMENT ;
    PORT
      LAYER M4 ;
      RECT 0.000 62.112 0.192 62.136 ;
    END
  END rec_out[67]
  PIN rec_out[68]
    DIRECTION OUTPUT ;
    USE SIGNAL ;
    SHAPE ABUTMENT ;
    PORT
      LAYER M4 ;
      RECT 0.000 62.208 0.192 62.232 ;
    END
  END rec_out[68]
  PIN rec_out[69]
    DIRECTION OUTPUT ;
    USE SIGNAL ;
    SHAPE ABUTMENT ;
    PORT
      LAYER M4 ;
      RECT 0.000 62.304 0.192 62.328 ;
    END
  END rec_out[69]
  PIN rec_out[70]
    DIRECTION OUTPUT ;
    USE SIGNAL ;
    SHAPE ABUTMENT ;
    PORT
      LAYER M4 ;
      RECT 0.000 62.400 0.192 62.424 ;
    END
  END rec_out[70]
  PIN rec_out[71]
    DIRECTION OUTPUT ;
    USE SIGNAL ;
    SHAPE ABUTMENT ;
    PORT
      LAYER M4 ;
      RECT 0.000 62.496 0.192 62.520 ;
    END
  END rec_out[71]
  PIN rec_out[72]
    DIRECTION OUTPUT ;
    USE SIGNAL ;
    SHAPE ABUTMENT ;
    PORT
      LAYER M4 ;
      RECT 0.000 62.592 0.192 62.616 ;
    END
  END rec_out[72]
  PIN rec_out[73]
    DIRECTION OUTPUT ;
    USE SIGNAL ;
    SHAPE ABUTMENT ;
    PORT
      LAYER M4 ;
      RECT 0.000 62.688 0.192 62.712 ;
    END
  END rec_out[73]
  PIN rec_out[74]
    DIRECTION OUTPUT ;
    USE SIGNAL ;
    SHAPE ABUTMENT ;
    PORT
      LAYER M4 ;
      RECT 0.000 62.784 0.192 62.808 ;
    END
  END rec_out[74]
  PIN rec_out[75]
    DIRECTION OUTPUT ;
    USE SIGNAL ;
    SHAPE ABUTMENT ;
    PORT
      LAYER M4 ;
      RECT 0.000 62.928 0.192 62.952 ;
    END
  END rec_out[75]
  PIN rec_out[76]
    DIRECTION OUTPUT ;
    USE SIGNAL ;
    SHAPE ABUTMENT ;
    PORT
      LAYER M4 ;
      RECT 0.000 63.024 0.192 63.048 ;
    END
  END rec_out[76]
  PIN rec_out[77]
    DIRECTION OUTPUT ;
    USE SIGNAL ;
    SHAPE ABUTMENT ;
    PORT
      LAYER M4 ;
      RECT 0.000 63.120 0.192 63.144 ;
    END
  END rec_out[77]
  PIN rec_out[78]
    DIRECTION OUTPUT ;
    USE SIGNAL ;
    SHAPE ABUTMENT ;
    PORT
      LAYER M4 ;
      RECT 0.000 63.216 0.192 63.240 ;
    END
  END rec_out[78]
  PIN rec_out[79]
    DIRECTION OUTPUT ;
    USE SIGNAL ;
    SHAPE ABUTMENT ;
    PORT
      LAYER M4 ;
      RECT 0.000 63.312 0.192 63.336 ;
    END
  END rec_out[79]
  PIN rec_out[80]
    DIRECTION OUTPUT ;
    USE SIGNAL ;
    SHAPE ABUTMENT ;
    PORT
      LAYER M4 ;
      RECT 0.000 63.408 0.192 63.432 ;
    END
  END rec_out[80]
  PIN rec_out[81]
    DIRECTION OUTPUT ;
    USE SIGNAL ;
    SHAPE ABUTMENT ;
    PORT
      LAYER M4 ;
      RECT 0.000 63.504 0.192 63.528 ;
    END
  END rec_out[81]
  PIN rec_out[82]
    DIRECTION OUTPUT ;
    USE SIGNAL ;
    SHAPE ABUTMENT ;
    PORT
      LAYER M4 ;
      RECT 0.000 63.600 0.192 63.624 ;
    END
  END rec_out[82]
  PIN rec_out[83]
    DIRECTION OUTPUT ;
    USE SIGNAL ;
    SHAPE ABUTMENT ;
    PORT
      LAYER M4 ;
      RECT 0.000 63.696 0.192 63.720 ;
    END
  END rec_out[83]
  PIN rec_out[84]
    DIRECTION OUTPUT ;
    USE SIGNAL ;
    SHAPE ABUTMENT ;
    PORT
      LAYER M4 ;
      RECT 0.000 63.792 0.192 63.816 ;
    END
  END rec_out[84]
  PIN rec_out[85]
    DIRECTION OUTPUT ;
    USE SIGNAL ;
    SHAPE ABUTMENT ;
    PORT
      LAYER M4 ;
      RECT 0.000 63.888 0.192 63.912 ;
    END
  END rec_out[85]
  PIN rec_out[86]
    DIRECTION OUTPUT ;
    USE SIGNAL ;
    SHAPE ABUTMENT ;
    PORT
      LAYER M4 ;
      RECT 0.000 64.032 0.192 64.056 ;
    END
  END rec_out[86]
  PIN rec_out[87]
    DIRECTION OUTPUT ;
    USE SIGNAL ;
    SHAPE ABUTMENT ;
    PORT
      LAYER M4 ;
      RECT 0.000 64.128 0.192 64.152 ;
    END
  END rec_out[87]
  PIN rec_out[88]
    DIRECTION OUTPUT ;
    USE SIGNAL ;
    SHAPE ABUTMENT ;
    PORT
      LAYER M4 ;
      RECT 0.000 64.224 0.192 64.248 ;
    END
  END rec_out[88]
  PIN rec_out[89]
    DIRECTION OUTPUT ;
    USE SIGNAL ;
    SHAPE ABUTMENT ;
    PORT
      LAYER M4 ;
      RECT 0.000 64.320 0.192 64.344 ;
    END
  END rec_out[89]
  PIN rec_out[90]
    DIRECTION OUTPUT ;
    USE SIGNAL ;
    SHAPE ABUTMENT ;
    PORT
      LAYER M4 ;
      RECT 0.000 64.416 0.192 64.440 ;
    END
  END rec_out[90]
  PIN rec_out[91]
    DIRECTION OUTPUT ;
    USE SIGNAL ;
    SHAPE ABUTMENT ;
    PORT
      LAYER M4 ;
      RECT 0.000 64.512 0.192 64.536 ;
    END
  END rec_out[91]
  PIN rec_out[92]
    DIRECTION OUTPUT ;
    USE SIGNAL ;
    SHAPE ABUTMENT ;
    PORT
      LAYER M4 ;
      RECT 0.000 64.608 0.192 64.632 ;
    END
  END rec_out[92]
  PIN rec_out[93]
    DIRECTION OUTPUT ;
    USE SIGNAL ;
    SHAPE ABUTMENT ;
    PORT
      LAYER M4 ;
      RECT 0.000 64.704 0.192 64.728 ;
    END
  END rec_out[93]
  PIN rec_out[94]
    DIRECTION OUTPUT ;
    USE SIGNAL ;
    SHAPE ABUTMENT ;
    PORT
      LAYER M4 ;
      RECT 0.000 64.800 0.192 64.824 ;
    END
  END rec_out[94]
  PIN rec_out[95]
    DIRECTION OUTPUT ;
    USE SIGNAL ;
    SHAPE ABUTMENT ;
    PORT
      LAYER M4 ;
      RECT 0.000 64.896 0.192 64.920 ;
    END
  END rec_out[95]
  PIN rec_out[96]
    DIRECTION OUTPUT ;
    USE SIGNAL ;
    SHAPE ABUTMENT ;
    PORT
      LAYER M4 ;
      RECT 0.000 64.992 0.192 65.016 ;
    END
  END rec_out[96]
  PIN rec_out[97]
    DIRECTION OUTPUT ;
    USE SIGNAL ;
    SHAPE ABUTMENT ;
    PORT
      LAYER M4 ;
      RECT 0.000 65.088 0.192 65.112 ;
    END
  END rec_out[97]
  PIN rec_out[98]
    DIRECTION OUTPUT ;
    USE SIGNAL ;
    SHAPE ABUTMENT ;
    PORT
      LAYER M4 ;
      RECT 0.000 65.232 0.192 65.256 ;
    END
  END rec_out[98]
  PIN rec_out[99]
    DIRECTION OUTPUT ;
    USE SIGNAL ;
    SHAPE ABUTMENT ;
    PORT
      LAYER M4 ;
      RECT 0.000 65.328 0.192 65.352 ;
    END
  END rec_out[99]
  PIN rec_out[100]
    DIRECTION OUTPUT ;
    USE SIGNAL ;
    SHAPE ABUTMENT ;
    PORT
      LAYER M4 ;
      RECT 0.000 65.424 0.192 65.448 ;
    END
  END rec_out[100]
  PIN rec_out[101]
    DIRECTION OUTPUT ;
    USE SIGNAL ;
    SHAPE ABUTMENT ;
    PORT
      LAYER M4 ;
      RECT 0.000 65.520 0.192 65.544 ;
    END
  END rec_out[101]
  PIN rec_out[102]
    DIRECTION OUTPUT ;
    USE SIGNAL ;
    SHAPE ABUTMENT ;
    PORT
      LAYER M4 ;
      RECT 0.000 65.616 0.192 65.640 ;
    END
  END rec_out[102]
  PIN rec_out[103]
    DIRECTION OUTPUT ;
    USE SIGNAL ;
    SHAPE ABUTMENT ;
    PORT
      LAYER M4 ;
      RECT 0.000 65.712 0.192 65.736 ;
    END
  END rec_out[103]
  PIN rec_out[104]
    DIRECTION OUTPUT ;
    USE SIGNAL ;
    SHAPE ABUTMENT ;
    PORT
      LAYER M4 ;
      RECT 0.000 65.808 0.192 65.832 ;
    END
  END rec_out[104]
  PIN rec_out[105]
    DIRECTION OUTPUT ;
    USE SIGNAL ;
    SHAPE ABUTMENT ;
    PORT
      LAYER M4 ;
      RECT 0.000 65.904 0.192 65.928 ;
    END
  END rec_out[105]
  PIN rec_out[106]
    DIRECTION OUTPUT ;
    USE SIGNAL ;
    SHAPE ABUTMENT ;
    PORT
      LAYER M4 ;
      RECT 0.000 66.000 0.192 66.024 ;
    END
  END rec_out[106]
  PIN rec_out[107]
    DIRECTION OUTPUT ;
    USE SIGNAL ;
    SHAPE ABUTMENT ;
    PORT
      LAYER M4 ;
      RECT 0.000 66.096 0.192 66.120 ;
    END
  END rec_out[107]
  PIN rec_out[108]
    DIRECTION OUTPUT ;
    USE SIGNAL ;
    SHAPE ABUTMENT ;
    PORT
      LAYER M4 ;
      RECT 0.000 66.192 0.192 66.216 ;
    END
  END rec_out[108]
  PIN rec_out[109]
    DIRECTION OUTPUT ;
    USE SIGNAL ;
    SHAPE ABUTMENT ;
    PORT
      LAYER M4 ;
      RECT 0.000 66.336 0.192 66.360 ;
    END
  END rec_out[109]
  PIN rec_out[110]
    DIRECTION OUTPUT ;
    USE SIGNAL ;
    SHAPE ABUTMENT ;
    PORT
      LAYER M4 ;
      RECT 0.000 66.432 0.192 66.456 ;
    END
  END rec_out[110]
  PIN rec_out[111]
    DIRECTION OUTPUT ;
    USE SIGNAL ;
    SHAPE ABUTMENT ;
    PORT
      LAYER M4 ;
      RECT 0.000 66.528 0.192 66.552 ;
    END
  END rec_out[111]
  PIN rec_out[112]
    DIRECTION OUTPUT ;
    USE SIGNAL ;
    SHAPE ABUTMENT ;
    PORT
      LAYER M4 ;
      RECT 0.000 66.624 0.192 66.648 ;
    END
  END rec_out[112]
  PIN rec_out[113]
    DIRECTION OUTPUT ;
    USE SIGNAL ;
    SHAPE ABUTMENT ;
    PORT
      LAYER M4 ;
      RECT 0.000 66.720 0.192 66.744 ;
    END
  END rec_out[113]
  PIN rec_out[114]
    DIRECTION OUTPUT ;
    USE SIGNAL ;
    SHAPE ABUTMENT ;
    PORT
      LAYER M4 ;
      RECT 0.000 66.816 0.192 66.840 ;
    END
  END rec_out[114]
  PIN rec_out[115]
    DIRECTION OUTPUT ;
    USE SIGNAL ;
    SHAPE ABUTMENT ;
    PORT
      LAYER M4 ;
      RECT 0.000 66.912 0.192 66.936 ;
    END
  END rec_out[115]
  PIN rec_out[116]
    DIRECTION OUTPUT ;
    USE SIGNAL ;
    SHAPE ABUTMENT ;
    PORT
      LAYER M4 ;
      RECT 0.000 67.008 0.192 67.032 ;
    END
  END rec_out[116]
  PIN rec_out[117]
    DIRECTION OUTPUT ;
    USE SIGNAL ;
    SHAPE ABUTMENT ;
    PORT
      LAYER M4 ;
      RECT 0.000 67.104 0.192 67.128 ;
    END
  END rec_out[117]
  PIN rec_out[118]
    DIRECTION OUTPUT ;
    USE SIGNAL ;
    SHAPE ABUTMENT ;
    PORT
      LAYER M4 ;
      RECT 0.000 67.200 0.192 67.224 ;
    END
  END rec_out[118]
  PIN rec_out[119]
    DIRECTION OUTPUT ;
    USE SIGNAL ;
    SHAPE ABUTMENT ;
    PORT
      LAYER M4 ;
      RECT 0.000 67.296 0.192 67.320 ;
    END
  END rec_out[119]
  PIN rec_out[120]
    DIRECTION OUTPUT ;
    USE SIGNAL ;
    SHAPE ABUTMENT ;
    PORT
      LAYER M4 ;
      RECT 0.000 67.392 0.192 67.416 ;
    END
  END rec_out[120]
  PIN rec_out[121]
    DIRECTION OUTPUT ;
    USE SIGNAL ;
    SHAPE ABUTMENT ;
    PORT
      LAYER M4 ;
      RECT 0.000 67.536 0.192 67.560 ;
    END
  END rec_out[121]
  PIN rec_out[122]
    DIRECTION OUTPUT ;
    USE SIGNAL ;
    SHAPE ABUTMENT ;
    PORT
      LAYER M4 ;
      RECT 0.000 67.632 0.192 67.656 ;
    END
  END rec_out[122]
  PIN rec_out[123]
    DIRECTION OUTPUT ;
    USE SIGNAL ;
    SHAPE ABUTMENT ;
    PORT
      LAYER M4 ;
      RECT 0.000 67.728 0.192 67.752 ;
    END
  END rec_out[123]
  PIN rec_out[124]
    DIRECTION OUTPUT ;
    USE SIGNAL ;
    SHAPE ABUTMENT ;
    PORT
      LAYER M4 ;
      RECT 0.000 67.824 0.192 67.848 ;
    END
  END rec_out[124]
  PIN rec_out[125]
    DIRECTION OUTPUT ;
    USE SIGNAL ;
    SHAPE ABUTMENT ;
    PORT
      LAYER M4 ;
      RECT 0.000 67.920 0.192 67.944 ;
    END
  END rec_out[125]
  PIN rec_out[126]
    DIRECTION OUTPUT ;
    USE SIGNAL ;
    SHAPE ABUTMENT ;
    PORT
      LAYER M4 ;
      RECT 0.000 68.016 0.192 68.040 ;
    END
  END rec_out[126]
  PIN rec_out[127]
    DIRECTION OUTPUT ;
    USE SIGNAL ;
    SHAPE ABUTMENT ;
    PORT
      LAYER M4 ;
      RECT 0.000 68.112 0.192 68.136 ;
    END
  END rec_out[127]
  PIN rec_out[128]
    DIRECTION OUTPUT ;
    USE SIGNAL ;
    SHAPE ABUTMENT ;
    PORT
      LAYER M4 ;
      RECT 0.000 68.208 0.192 68.232 ;
    END
  END rec_out[128]
  PIN rec_out[129]
    DIRECTION OUTPUT ;
    USE SIGNAL ;
    SHAPE ABUTMENT ;
    PORT
      LAYER M4 ;
      RECT 0.000 68.304 0.192 68.328 ;
    END
  END rec_out[129]
  PIN rec_out[130]
    DIRECTION OUTPUT ;
    USE SIGNAL ;
    SHAPE ABUTMENT ;
    PORT
      LAYER M4 ;
      RECT 0.000 68.400 0.192 68.424 ;
    END
  END rec_out[130]
  PIN rec_out[131]
    DIRECTION OUTPUT ;
    USE SIGNAL ;
    SHAPE ABUTMENT ;
    PORT
      LAYER M4 ;
      RECT 0.000 68.496 0.192 68.520 ;
    END
  END rec_out[131]
  PIN rec_out[132]
    DIRECTION OUTPUT ;
    USE SIGNAL ;
    SHAPE ABUTMENT ;
    PORT
      LAYER M4 ;
      RECT 0.000 68.592 0.192 68.616 ;
    END
  END rec_out[132]
  PIN rec_out[133]
    DIRECTION OUTPUT ;
    USE SIGNAL ;
    SHAPE ABUTMENT ;
    PORT
      LAYER M4 ;
      RECT 0.000 68.736 0.192 68.760 ;
    END
  END rec_out[133]
  PIN rec_out[134]
    DIRECTION OUTPUT ;
    USE SIGNAL ;
    SHAPE ABUTMENT ;
    PORT
      LAYER M4 ;
      RECT 0.000 68.832 0.192 68.856 ;
    END
  END rec_out[134]
  PIN rec_out[135]
    DIRECTION OUTPUT ;
    USE SIGNAL ;
    SHAPE ABUTMENT ;
    PORT
      LAYER M4 ;
      RECT 0.000 68.928 0.192 68.952 ;
    END
  END rec_out[135]
  PIN rec_out[136]
    DIRECTION OUTPUT ;
    USE SIGNAL ;
    SHAPE ABUTMENT ;
    PORT
      LAYER M4 ;
      RECT 0.000 69.024 0.192 69.048 ;
    END
  END rec_out[136]
  PIN rec_out[137]
    DIRECTION OUTPUT ;
    USE SIGNAL ;
    SHAPE ABUTMENT ;
    PORT
      LAYER M4 ;
      RECT 0.000 69.120 0.192 69.144 ;
    END
  END rec_out[137]
  PIN rec_out[138]
    DIRECTION OUTPUT ;
    USE SIGNAL ;
    SHAPE ABUTMENT ;
    PORT
      LAYER M4 ;
      RECT 0.000 69.216 0.192 69.240 ;
    END
  END rec_out[138]
  PIN rec_out[139]
    DIRECTION OUTPUT ;
    USE SIGNAL ;
    SHAPE ABUTMENT ;
    PORT
      LAYER M4 ;
      RECT 0.000 69.312 0.192 69.336 ;
    END
  END rec_out[139]
  PIN rec_out[140]
    DIRECTION OUTPUT ;
    USE SIGNAL ;
    SHAPE ABUTMENT ;
    PORT
      LAYER M4 ;
      RECT 0.000 69.408 0.192 69.432 ;
    END
  END rec_out[140]
  PIN rec_out[141]
    DIRECTION OUTPUT ;
    USE SIGNAL ;
    SHAPE ABUTMENT ;
    PORT
      LAYER M4 ;
      RECT 0.000 69.504 0.192 69.528 ;
    END
  END rec_out[141]
  PIN rec_out[142]
    DIRECTION OUTPUT ;
    USE SIGNAL ;
    SHAPE ABUTMENT ;
    PORT
      LAYER M4 ;
      RECT 0.000 69.600 0.192 69.624 ;
    END
  END rec_out[142]
  PIN rec_out[143]
    DIRECTION OUTPUT ;
    USE SIGNAL ;
    SHAPE ABUTMENT ;
    PORT
      LAYER M4 ;
      RECT 0.000 69.696 0.192 69.720 ;
    END
  END rec_out[143]
  PIN rec_out[144]
    DIRECTION OUTPUT ;
    USE SIGNAL ;
    SHAPE ABUTMENT ;
    PORT
      LAYER M4 ;
      RECT 0.000 69.840 0.192 69.864 ;
    END
  END rec_out[144]
  PIN rec_out[145]
    DIRECTION OUTPUT ;
    USE SIGNAL ;
    SHAPE ABUTMENT ;
    PORT
      LAYER M4 ;
      RECT 0.000 69.936 0.192 69.960 ;
    END
  END rec_out[145]
  PIN rec_out[146]
    DIRECTION OUTPUT ;
    USE SIGNAL ;
    SHAPE ABUTMENT ;
    PORT
      LAYER M4 ;
      RECT 0.000 70.032 0.192 70.056 ;
    END
  END rec_out[146]
  PIN rec_out[147]
    DIRECTION OUTPUT ;
    USE SIGNAL ;
    SHAPE ABUTMENT ;
    PORT
      LAYER M4 ;
      RECT 0.000 70.128 0.192 70.152 ;
    END
  END rec_out[147]
  PIN rec_out[148]
    DIRECTION OUTPUT ;
    USE SIGNAL ;
    SHAPE ABUTMENT ;
    PORT
      LAYER M4 ;
      RECT 0.000 70.224 0.192 70.248 ;
    END
  END rec_out[148]
  PIN rec_out[149]
    DIRECTION OUTPUT ;
    USE SIGNAL ;
    SHAPE ABUTMENT ;
    PORT
      LAYER M4 ;
      RECT 0.000 70.320 0.192 70.344 ;
    END
  END rec_out[149]
  PIN rec_out[150]
    DIRECTION OUTPUT ;
    USE SIGNAL ;
    SHAPE ABUTMENT ;
    PORT
      LAYER M4 ;
      RECT 0.000 70.416 0.192 70.440 ;
    END
  END rec_out[150]
  PIN rec_out[151]
    DIRECTION OUTPUT ;
    USE SIGNAL ;
    SHAPE ABUTMENT ;
    PORT
      LAYER M4 ;
      RECT 0.000 70.512 0.192 70.536 ;
    END
  END rec_out[151]
  PIN rec_out[152]
    DIRECTION OUTPUT ;
    USE SIGNAL ;
    SHAPE ABUTMENT ;
    PORT
      LAYER M4 ;
      RECT 0.000 70.608 0.192 70.632 ;
    END
  END rec_out[152]
  PIN rec_out[153]
    DIRECTION OUTPUT ;
    USE SIGNAL ;
    SHAPE ABUTMENT ;
    PORT
      LAYER M4 ;
      RECT 0.000 70.704 0.192 70.728 ;
    END
  END rec_out[153]
  PIN rec_out[154]
    DIRECTION OUTPUT ;
    USE SIGNAL ;
    SHAPE ABUTMENT ;
    PORT
      LAYER M4 ;
      RECT 0.000 70.800 0.192 70.824 ;
    END
  END rec_out[154]
  PIN rec_out[155]
    DIRECTION OUTPUT ;
    USE SIGNAL ;
    SHAPE ABUTMENT ;
    PORT
      LAYER M4 ;
      RECT 0.000 70.896 0.192 70.920 ;
    END
  END rec_out[155]
  PIN rec_out[156]
    DIRECTION OUTPUT ;
    USE SIGNAL ;
    SHAPE ABUTMENT ;
    PORT
      LAYER M4 ;
      RECT 0.000 71.040 0.192 71.064 ;
    END
  END rec_out[156]
  PIN rec_out[157]
    DIRECTION OUTPUT ;
    USE SIGNAL ;
    SHAPE ABUTMENT ;
    PORT
      LAYER M4 ;
      RECT 0.000 71.136 0.192 71.160 ;
    END
  END rec_out[157]
  PIN rec_out[158]
    DIRECTION OUTPUT ;
    USE SIGNAL ;
    SHAPE ABUTMENT ;
    PORT
      LAYER M4 ;
      RECT 0.000 71.232 0.192 71.256 ;
    END
  END rec_out[158]
  PIN rec_out[159]
    DIRECTION OUTPUT ;
    USE SIGNAL ;
    SHAPE ABUTMENT ;
    PORT
      LAYER M4 ;
      RECT 0.000 71.328 0.192 71.352 ;
    END
  END rec_out[159]
  PIN rec_out[160]
    DIRECTION OUTPUT ;
    USE SIGNAL ;
    SHAPE ABUTMENT ;
    PORT
      LAYER M4 ;
      RECT 0.000 71.424 0.192 71.448 ;
    END
  END rec_out[160]
  PIN rec_out[161]
    DIRECTION OUTPUT ;
    USE SIGNAL ;
    SHAPE ABUTMENT ;
    PORT
      LAYER M4 ;
      RECT 0.000 71.520 0.192 71.544 ;
    END
  END rec_out[161]
  PIN rec_out[162]
    DIRECTION OUTPUT ;
    USE SIGNAL ;
    SHAPE ABUTMENT ;
    PORT
      LAYER M4 ;
      RECT 0.000 71.616 0.192 71.640 ;
    END
  END rec_out[162]
  PIN rec_out[163]
    DIRECTION OUTPUT ;
    USE SIGNAL ;
    SHAPE ABUTMENT ;
    PORT
      LAYER M4 ;
      RECT 0.000 71.712 0.192 71.736 ;
    END
  END rec_out[163]
  PIN rec_out[164]
    DIRECTION OUTPUT ;
    USE SIGNAL ;
    SHAPE ABUTMENT ;
    PORT
      LAYER M4 ;
      RECT 0.000 71.808 0.192 71.832 ;
    END
  END rec_out[164]
  PIN rec_out[165]
    DIRECTION OUTPUT ;
    USE SIGNAL ;
    SHAPE ABUTMENT ;
    PORT
      LAYER M4 ;
      RECT 0.000 71.904 0.192 71.928 ;
    END
  END rec_out[165]
  PIN rec_out[166]
    DIRECTION OUTPUT ;
    USE SIGNAL ;
    SHAPE ABUTMENT ;
    PORT
      LAYER M4 ;
      RECT 0.000 72.000 0.192 72.024 ;
    END
  END rec_out[166]
  PIN rec_out[167]
    DIRECTION OUTPUT ;
    USE SIGNAL ;
    SHAPE ABUTMENT ;
    PORT
      LAYER M4 ;
      RECT 0.000 72.144 0.192 72.168 ;
    END
  END rec_out[167]
  PIN rec_out[168]
    DIRECTION OUTPUT ;
    USE SIGNAL ;
    SHAPE ABUTMENT ;
    PORT
      LAYER M4 ;
      RECT 0.000 72.240 0.192 72.264 ;
    END
  END rec_out[168]
  PIN rec_out[169]
    DIRECTION OUTPUT ;
    USE SIGNAL ;
    SHAPE ABUTMENT ;
    PORT
      LAYER M4 ;
      RECT 0.000 72.336 0.192 72.360 ;
    END
  END rec_out[169]
  PIN rec_out[170]
    DIRECTION OUTPUT ;
    USE SIGNAL ;
    SHAPE ABUTMENT ;
    PORT
      LAYER M4 ;
      RECT 0.000 72.432 0.192 72.456 ;
    END
  END rec_out[170]
  PIN rec_out[171]
    DIRECTION OUTPUT ;
    USE SIGNAL ;
    SHAPE ABUTMENT ;
    PORT
      LAYER M4 ;
      RECT 0.000 72.528 0.192 72.552 ;
    END
  END rec_out[171]
  PIN rec_out[172]
    DIRECTION OUTPUT ;
    USE SIGNAL ;
    SHAPE ABUTMENT ;
    PORT
      LAYER M4 ;
      RECT 0.000 72.624 0.192 72.648 ;
    END
  END rec_out[172]
  PIN rec_out[173]
    DIRECTION OUTPUT ;
    USE SIGNAL ;
    SHAPE ABUTMENT ;
    PORT
      LAYER M4 ;
      RECT 0.000 72.720 0.192 72.744 ;
    END
  END rec_out[173]
  PIN rec_out[174]
    DIRECTION OUTPUT ;
    USE SIGNAL ;
    SHAPE ABUTMENT ;
    PORT
      LAYER M4 ;
      RECT 0.000 72.816 0.192 72.840 ;
    END
  END rec_out[174]
  PIN rec_out[175]
    DIRECTION OUTPUT ;
    USE SIGNAL ;
    SHAPE ABUTMENT ;
    PORT
      LAYER M4 ;
      RECT 0.000 72.912 0.192 72.936 ;
    END
  END rec_out[175]
  PIN rec_out[176]
    DIRECTION OUTPUT ;
    USE SIGNAL ;
    SHAPE ABUTMENT ;
    PORT
      LAYER M4 ;
      RECT 0.000 73.008 0.192 73.032 ;
    END
  END rec_out[176]
  PIN rec_out[177]
    DIRECTION OUTPUT ;
    USE SIGNAL ;
    SHAPE ABUTMENT ;
    PORT
      LAYER M4 ;
      RECT 0.000 73.104 0.192 73.128 ;
    END
  END rec_out[177]
  PIN rec_out[178]
    DIRECTION OUTPUT ;
    USE SIGNAL ;
    SHAPE ABUTMENT ;
    PORT
      LAYER M4 ;
      RECT 0.000 73.200 0.192 73.224 ;
    END
  END rec_out[178]
  PIN rec_out[179]
    DIRECTION OUTPUT ;
    USE SIGNAL ;
    SHAPE ABUTMENT ;
    PORT
      LAYER M4 ;
      RECT 0.000 73.344 0.192 73.368 ;
    END
  END rec_out[179]
  PIN rec_out[180]
    DIRECTION OUTPUT ;
    USE SIGNAL ;
    SHAPE ABUTMENT ;
    PORT
      LAYER M4 ;
      RECT 0.000 73.440 0.192 73.464 ;
    END
  END rec_out[180]
  PIN rec_out[181]
    DIRECTION OUTPUT ;
    USE SIGNAL ;
    SHAPE ABUTMENT ;
    PORT
      LAYER M4 ;
      RECT 0.000 73.536 0.192 73.560 ;
    END
  END rec_out[181]
  PIN rec_out[182]
    DIRECTION OUTPUT ;
    USE SIGNAL ;
    SHAPE ABUTMENT ;
    PORT
      LAYER M4 ;
      RECT 0.000 73.632 0.192 73.656 ;
    END
  END rec_out[182]
  PIN rec_out[183]
    DIRECTION OUTPUT ;
    USE SIGNAL ;
    SHAPE ABUTMENT ;
    PORT
      LAYER M4 ;
      RECT 0.000 73.728 0.192 73.752 ;
    END
  END rec_out[183]
  PIN rec_out[184]
    DIRECTION OUTPUT ;
    USE SIGNAL ;
    SHAPE ABUTMENT ;
    PORT
      LAYER M4 ;
      RECT 0.000 73.824 0.192 73.848 ;
    END
  END rec_out[184]
  PIN rec_out[185]
    DIRECTION OUTPUT ;
    USE SIGNAL ;
    SHAPE ABUTMENT ;
    PORT
      LAYER M4 ;
      RECT 0.000 73.920 0.192 73.944 ;
    END
  END rec_out[185]
  PIN rec_out[186]
    DIRECTION OUTPUT ;
    USE SIGNAL ;
    SHAPE ABUTMENT ;
    PORT
      LAYER M4 ;
      RECT 0.000 74.016 0.192 74.040 ;
    END
  END rec_out[186]
  PIN rec_out[187]
    DIRECTION OUTPUT ;
    USE SIGNAL ;
    SHAPE ABUTMENT ;
    PORT
      LAYER M4 ;
      RECT 0.000 74.112 0.192 74.136 ;
    END
  END rec_out[187]
  PIN rec_out[188]
    DIRECTION OUTPUT ;
    USE SIGNAL ;
    SHAPE ABUTMENT ;
    PORT
      LAYER M4 ;
      RECT 0.000 74.208 0.192 74.232 ;
    END
  END rec_out[188]
  PIN rec_out[189]
    DIRECTION OUTPUT ;
    USE SIGNAL ;
    SHAPE ABUTMENT ;
    PORT
      LAYER M4 ;
      RECT 0.000 74.304 0.192 74.328 ;
    END
  END rec_out[189]
  PIN rec_out[190]
    DIRECTION OUTPUT ;
    USE SIGNAL ;
    SHAPE ABUTMENT ;
    PORT
      LAYER M4 ;
      RECT 0.000 74.448 0.192 74.472 ;
    END
  END rec_out[190]
  PIN rec_out[191]
    DIRECTION OUTPUT ;
    USE SIGNAL ;
    SHAPE ABUTMENT ;
    PORT
      LAYER M4 ;
      RECT 0.000 74.544 0.192 74.568 ;
    END
  END rec_out[191]
  PIN rec_out[192]
    DIRECTION OUTPUT ;
    USE SIGNAL ;
    SHAPE ABUTMENT ;
    PORT
      LAYER M4 ;
      RECT 0.000 74.640 0.192 74.664 ;
    END
  END rec_out[192]
  PIN rec_out[193]
    DIRECTION OUTPUT ;
    USE SIGNAL ;
    SHAPE ABUTMENT ;
    PORT
      LAYER M4 ;
      RECT 0.000 74.736 0.192 74.760 ;
    END
  END rec_out[193]
  PIN rec_out[194]
    DIRECTION OUTPUT ;
    USE SIGNAL ;
    SHAPE ABUTMENT ;
    PORT
      LAYER M4 ;
      RECT 0.000 74.832 0.192 74.856 ;
    END
  END rec_out[194]
  PIN rec_out[195]
    DIRECTION OUTPUT ;
    USE SIGNAL ;
    SHAPE ABUTMENT ;
    PORT
      LAYER M4 ;
      RECT 0.000 74.928 0.192 74.952 ;
    END
  END rec_out[195]
  PIN rec_out[196]
    DIRECTION OUTPUT ;
    USE SIGNAL ;
    SHAPE ABUTMENT ;
    PORT
      LAYER M4 ;
      RECT 0.000 75.024 0.192 75.048 ;
    END
  END rec_out[196]
  PIN rec_out[197]
    DIRECTION OUTPUT ;
    USE SIGNAL ;
    SHAPE ABUTMENT ;
    PORT
      LAYER M4 ;
      RECT 0.000 75.120 0.192 75.144 ;
    END
  END rec_out[197]
  PIN rec_out[198]
    DIRECTION OUTPUT ;
    USE SIGNAL ;
    SHAPE ABUTMENT ;
    PORT
      LAYER M4 ;
      RECT 0.000 75.216 0.192 75.240 ;
    END
  END rec_out[198]
  PIN rec_out[199]
    DIRECTION OUTPUT ;
    USE SIGNAL ;
    SHAPE ABUTMENT ;
    PORT
      LAYER M4 ;
      RECT 0.000 75.312 0.192 75.336 ;
    END
  END rec_out[199]
  PIN rec_out[200]
    DIRECTION OUTPUT ;
    USE SIGNAL ;
    SHAPE ABUTMENT ;
    PORT
      LAYER M4 ;
      RECT 0.000 75.408 0.192 75.432 ;
    END
  END rec_out[200]
  PIN rec_out[201]
    DIRECTION OUTPUT ;
    USE SIGNAL ;
    SHAPE ABUTMENT ;
    PORT
      LAYER M4 ;
      RECT 0.000 75.504 0.192 75.528 ;
    END
  END rec_out[201]
  PIN rec_out[202]
    DIRECTION OUTPUT ;
    USE SIGNAL ;
    SHAPE ABUTMENT ;
    PORT
      LAYER M4 ;
      RECT 0.000 75.648 0.192 75.672 ;
    END
  END rec_out[202]
  PIN rec_out[203]
    DIRECTION OUTPUT ;
    USE SIGNAL ;
    SHAPE ABUTMENT ;
    PORT
      LAYER M4 ;
      RECT 0.000 75.744 0.192 75.768 ;
    END
  END rec_out[203]
  PIN rec_out[204]
    DIRECTION OUTPUT ;
    USE SIGNAL ;
    SHAPE ABUTMENT ;
    PORT
      LAYER M4 ;
      RECT 0.000 75.840 0.192 75.864 ;
    END
  END rec_out[204]
  PIN rec_out[205]
    DIRECTION OUTPUT ;
    USE SIGNAL ;
    SHAPE ABUTMENT ;
    PORT
      LAYER M4 ;
      RECT 0.000 75.936 0.192 75.960 ;
    END
  END rec_out[205]
  PIN rec_out[206]
    DIRECTION OUTPUT ;
    USE SIGNAL ;
    SHAPE ABUTMENT ;
    PORT
      LAYER M4 ;
      RECT 0.000 76.032 0.192 76.056 ;
    END
  END rec_out[206]
  PIN rec_out[207]
    DIRECTION OUTPUT ;
    USE SIGNAL ;
    SHAPE ABUTMENT ;
    PORT
      LAYER M4 ;
      RECT 0.000 76.128 0.192 76.152 ;
    END
  END rec_out[207]
  PIN rec_out[208]
    DIRECTION OUTPUT ;
    USE SIGNAL ;
    SHAPE ABUTMENT ;
    PORT
      LAYER M4 ;
      RECT 0.000 76.224 0.192 76.248 ;
    END
  END rec_out[208]
  PIN rec_out[209]
    DIRECTION OUTPUT ;
    USE SIGNAL ;
    SHAPE ABUTMENT ;
    PORT
      LAYER M4 ;
      RECT 0.000 76.320 0.192 76.344 ;
    END
  END rec_out[209]
  PIN rec_out[210]
    DIRECTION OUTPUT ;
    USE SIGNAL ;
    SHAPE ABUTMENT ;
    PORT
      LAYER M4 ;
      RECT 0.000 76.416 0.192 76.440 ;
    END
  END rec_out[210]
  PIN rec_out[211]
    DIRECTION OUTPUT ;
    USE SIGNAL ;
    SHAPE ABUTMENT ;
    PORT
      LAYER M4 ;
      RECT 0.000 76.512 0.192 76.536 ;
    END
  END rec_out[211]
  PIN rec_out[212]
    DIRECTION OUTPUT ;
    USE SIGNAL ;
    SHAPE ABUTMENT ;
    PORT
      LAYER M4 ;
      RECT 0.000 76.608 0.192 76.632 ;
    END
  END rec_out[212]
  PIN rec_out[213]
    DIRECTION OUTPUT ;
    USE SIGNAL ;
    SHAPE ABUTMENT ;
    PORT
      LAYER M4 ;
      RECT 0.000 76.752 0.192 76.776 ;
    END
  END rec_out[213]
  PIN rec_out[214]
    DIRECTION OUTPUT ;
    USE SIGNAL ;
    SHAPE ABUTMENT ;
    PORT
      LAYER M4 ;
      RECT 0.000 76.848 0.192 76.872 ;
    END
  END rec_out[214]
  PIN rec_out[215]
    DIRECTION OUTPUT ;
    USE SIGNAL ;
    SHAPE ABUTMENT ;
    PORT
      LAYER M4 ;
      RECT 0.000 76.944 0.192 76.968 ;
    END
  END rec_out[215]
  PIN rec_out[216]
    DIRECTION OUTPUT ;
    USE SIGNAL ;
    SHAPE ABUTMENT ;
    PORT
      LAYER M4 ;
      RECT 0.000 77.040 0.192 77.064 ;
    END
  END rec_out[216]
  PIN rec_out[217]
    DIRECTION OUTPUT ;
    USE SIGNAL ;
    SHAPE ABUTMENT ;
    PORT
      LAYER M4 ;
      RECT 0.000 77.136 0.192 77.160 ;
    END
  END rec_out[217]
  PIN rec_out[218]
    DIRECTION OUTPUT ;
    USE SIGNAL ;
    SHAPE ABUTMENT ;
    PORT
      LAYER M4 ;
      RECT 0.000 77.232 0.192 77.256 ;
    END
  END rec_out[218]
  PIN rec_out[219]
    DIRECTION OUTPUT ;
    USE SIGNAL ;
    SHAPE ABUTMENT ;
    PORT
      LAYER M4 ;
      RECT 0.000 77.328 0.192 77.352 ;
    END
  END rec_out[219]
  PIN rec_out[220]
    DIRECTION OUTPUT ;
    USE SIGNAL ;
    SHAPE ABUTMENT ;
    PORT
      LAYER M4 ;
      RECT 0.000 77.424 0.192 77.448 ;
    END
  END rec_out[220]
  PIN rec_out[221]
    DIRECTION OUTPUT ;
    USE SIGNAL ;
    SHAPE ABUTMENT ;
    PORT
      LAYER M4 ;
      RECT 0.000 77.520 0.192 77.544 ;
    END
  END rec_out[221]
  PIN rec_out[222]
    DIRECTION OUTPUT ;
    USE SIGNAL ;
    SHAPE ABUTMENT ;
    PORT
      LAYER M4 ;
      RECT 0.000 77.616 0.192 77.640 ;
    END
  END rec_out[222]
  PIN rec_out[223]
    DIRECTION OUTPUT ;
    USE SIGNAL ;
    SHAPE ABUTMENT ;
    PORT
      LAYER M4 ;
      RECT 0.000 77.712 0.192 77.736 ;
    END
  END rec_out[223]
  PIN rec_out[224]
    DIRECTION OUTPUT ;
    USE SIGNAL ;
    SHAPE ABUTMENT ;
    PORT
      LAYER M4 ;
      RECT 0.000 77.808 0.192 77.832 ;
    END
  END rec_out[224]
  PIN rec_out[225]
    DIRECTION OUTPUT ;
    USE SIGNAL ;
    SHAPE ABUTMENT ;
    PORT
      LAYER M4 ;
      RECT 0.000 77.952 0.192 77.976 ;
    END
  END rec_out[225]
  PIN rec_out[226]
    DIRECTION OUTPUT ;
    USE SIGNAL ;
    SHAPE ABUTMENT ;
    PORT
      LAYER M4 ;
      RECT 0.000 78.048 0.192 78.072 ;
    END
  END rec_out[226]
  PIN rec_out[227]
    DIRECTION OUTPUT ;
    USE SIGNAL ;
    SHAPE ABUTMENT ;
    PORT
      LAYER M4 ;
      RECT 0.000 78.144 0.192 78.168 ;
    END
  END rec_out[227]
  PIN rec_out[228]
    DIRECTION OUTPUT ;
    USE SIGNAL ;
    SHAPE ABUTMENT ;
    PORT
      LAYER M4 ;
      RECT 0.000 78.240 0.192 78.264 ;
    END
  END rec_out[228]
  PIN rec_out[229]
    DIRECTION OUTPUT ;
    USE SIGNAL ;
    SHAPE ABUTMENT ;
    PORT
      LAYER M4 ;
      RECT 0.000 78.336 0.192 78.360 ;
    END
  END rec_out[229]
  PIN rec_out[230]
    DIRECTION OUTPUT ;
    USE SIGNAL ;
    SHAPE ABUTMENT ;
    PORT
      LAYER M4 ;
      RECT 0.000 78.432 0.192 78.456 ;
    END
  END rec_out[230]
  PIN rec_out[231]
    DIRECTION OUTPUT ;
    USE SIGNAL ;
    SHAPE ABUTMENT ;
    PORT
      LAYER M4 ;
      RECT 0.000 78.528 0.192 78.552 ;
    END
  END rec_out[231]
  PIN rec_out[232]
    DIRECTION OUTPUT ;
    USE SIGNAL ;
    SHAPE ABUTMENT ;
    PORT
      LAYER M4 ;
      RECT 0.000 78.624 0.192 78.648 ;
    END
  END rec_out[232]
  PIN rec_out[233]
    DIRECTION OUTPUT ;
    USE SIGNAL ;
    SHAPE ABUTMENT ;
    PORT
      LAYER M4 ;
      RECT 0.000 78.720 0.192 78.744 ;
    END
  END rec_out[233]
  PIN rec_out[234]
    DIRECTION OUTPUT ;
    USE SIGNAL ;
    SHAPE ABUTMENT ;
    PORT
      LAYER M4 ;
      RECT 0.000 78.816 0.192 78.840 ;
    END
  END rec_out[234]
  PIN rec_out[235]
    DIRECTION OUTPUT ;
    USE SIGNAL ;
    SHAPE ABUTMENT ;
    PORT
      LAYER M4 ;
      RECT 0.000 78.912 0.192 78.936 ;
    END
  END rec_out[235]
  PIN rec_out[236]
    DIRECTION OUTPUT ;
    USE SIGNAL ;
    SHAPE ABUTMENT ;
    PORT
      LAYER M4 ;
      RECT 0.000 79.056 0.192 79.080 ;
    END
  END rec_out[236]
  PIN rec_out[237]
    DIRECTION OUTPUT ;
    USE SIGNAL ;
    SHAPE ABUTMENT ;
    PORT
      LAYER M4 ;
      RECT 0.000 79.152 0.192 79.176 ;
    END
  END rec_out[237]
  PIN rec_out[238]
    DIRECTION OUTPUT ;
    USE SIGNAL ;
    SHAPE ABUTMENT ;
    PORT
      LAYER M4 ;
      RECT 0.000 79.248 0.192 79.272 ;
    END
  END rec_out[238]
  PIN rec_out[239]
    DIRECTION OUTPUT ;
    USE SIGNAL ;
    SHAPE ABUTMENT ;
    PORT
      LAYER M4 ;
      RECT 0.000 79.344 0.192 79.368 ;
    END
  END rec_out[239]
  PIN rec_out[240]
    DIRECTION OUTPUT ;
    USE SIGNAL ;
    SHAPE ABUTMENT ;
    PORT
      LAYER M4 ;
      RECT 0.000 79.440 0.192 79.464 ;
    END
  END rec_out[240]
  PIN rec_out[241]
    DIRECTION OUTPUT ;
    USE SIGNAL ;
    SHAPE ABUTMENT ;
    PORT
      LAYER M4 ;
      RECT 0.000 79.536 0.192 79.560 ;
    END
  END rec_out[241]
  PIN rec_out[242]
    DIRECTION OUTPUT ;
    USE SIGNAL ;
    SHAPE ABUTMENT ;
    PORT
      LAYER M4 ;
      RECT 0.000 79.632 0.192 79.656 ;
    END
  END rec_out[242]
  PIN rec_out[243]
    DIRECTION OUTPUT ;
    USE SIGNAL ;
    SHAPE ABUTMENT ;
    PORT
      LAYER M4 ;
      RECT 0.000 79.728 0.192 79.752 ;
    END
  END rec_out[243]
  PIN rec_out[244]
    DIRECTION OUTPUT ;
    USE SIGNAL ;
    SHAPE ABUTMENT ;
    PORT
      LAYER M4 ;
      RECT 0.000 79.824 0.192 79.848 ;
    END
  END rec_out[244]
  PIN rec_out[245]
    DIRECTION OUTPUT ;
    USE SIGNAL ;
    SHAPE ABUTMENT ;
    PORT
      LAYER M4 ;
      RECT 0.000 79.920 0.192 79.944 ;
    END
  END rec_out[245]
  PIN rec_out[246]
    DIRECTION OUTPUT ;
    USE SIGNAL ;
    SHAPE ABUTMENT ;
    PORT
      LAYER M4 ;
      RECT 0.000 80.016 0.192 80.040 ;
    END
  END rec_out[246]
  PIN rec_out[247]
    DIRECTION OUTPUT ;
    USE SIGNAL ;
    SHAPE ABUTMENT ;
    PORT
      LAYER M4 ;
      RECT 0.000 80.112 0.192 80.136 ;
    END
  END rec_out[247]
  PIN rec_out[248]
    DIRECTION OUTPUT ;
    USE SIGNAL ;
    SHAPE ABUTMENT ;
    PORT
      LAYER M4 ;
      RECT 0.000 80.256 0.192 80.280 ;
    END
  END rec_out[248]
  PIN rec_out[249]
    DIRECTION OUTPUT ;
    USE SIGNAL ;
    SHAPE ABUTMENT ;
    PORT
      LAYER M4 ;
      RECT 0.000 80.352 0.192 80.376 ;
    END
  END rec_out[249]
  PIN rec_out[250]
    DIRECTION OUTPUT ;
    USE SIGNAL ;
    SHAPE ABUTMENT ;
    PORT
      LAYER M4 ;
      RECT 0.000 80.448 0.192 80.472 ;
    END
  END rec_out[250]
  PIN rec_out[251]
    DIRECTION OUTPUT ;
    USE SIGNAL ;
    SHAPE ABUTMENT ;
    PORT
      LAYER M4 ;
      RECT 0.000 80.544 0.192 80.568 ;
    END
  END rec_out[251]
  PIN rec_out[252]
    DIRECTION OUTPUT ;
    USE SIGNAL ;
    SHAPE ABUTMENT ;
    PORT
      LAYER M4 ;
      RECT 0.000 80.640 0.192 80.664 ;
    END
  END rec_out[252]
  PIN rec_out[253]
    DIRECTION OUTPUT ;
    USE SIGNAL ;
    SHAPE ABUTMENT ;
    PORT
      LAYER M4 ;
      RECT 0.000 80.736 0.192 80.760 ;
    END
  END rec_out[253]
  PIN rec_out[254]
    DIRECTION OUTPUT ;
    USE SIGNAL ;
    SHAPE ABUTMENT ;
    PORT
      LAYER M4 ;
      RECT 0.000 80.832 0.192 80.856 ;
    END
  END rec_out[254]
  PIN rec_out[255]
    DIRECTION OUTPUT ;
    USE SIGNAL ;
    SHAPE ABUTMENT ;
    PORT
      LAYER M4 ;
      RECT 0.000 80.928 0.192 80.952 ;
    END
  END rec_out[255]
  PIN rec_out[256]
    DIRECTION OUTPUT ;
    USE SIGNAL ;
    SHAPE ABUTMENT ;
    PORT
      LAYER M4 ;
      RECT 0.000 81.024 0.192 81.048 ;
    END
  END rec_out[256]
  PIN rec_out[257]
    DIRECTION OUTPUT ;
    USE SIGNAL ;
    SHAPE ABUTMENT ;
    PORT
      LAYER M4 ;
      RECT 0.000 81.120 0.192 81.144 ;
    END
  END rec_out[257]
  PIN rec_out[258]
    DIRECTION OUTPUT ;
    USE SIGNAL ;
    SHAPE ABUTMENT ;
    PORT
      LAYER M4 ;
      RECT 0.000 81.216 0.192 81.240 ;
    END
  END rec_out[258]
  PIN rec_out[259]
    DIRECTION OUTPUT ;
    USE SIGNAL ;
    SHAPE ABUTMENT ;
    PORT
      LAYER M4 ;
      RECT 0.000 81.360 0.192 81.384 ;
    END
  END rec_out[259]
  PIN rec_out[260]
    DIRECTION OUTPUT ;
    USE SIGNAL ;
    SHAPE ABUTMENT ;
    PORT
      LAYER M4 ;
      RECT 0.000 81.456 0.192 81.480 ;
    END
  END rec_out[260]
  PIN rec_out[261]
    DIRECTION OUTPUT ;
    USE SIGNAL ;
    SHAPE ABUTMENT ;
    PORT
      LAYER M4 ;
      RECT 0.000 81.552 0.192 81.576 ;
    END
  END rec_out[261]
  PIN rec_out[262]
    DIRECTION OUTPUT ;
    USE SIGNAL ;
    SHAPE ABUTMENT ;
    PORT
      LAYER M4 ;
      RECT 0.000 81.648 0.192 81.672 ;
    END
  END rec_out[262]
  PIN rec_out[263]
    DIRECTION OUTPUT ;
    USE SIGNAL ;
    SHAPE ABUTMENT ;
    PORT
      LAYER M4 ;
      RECT 0.000 81.744 0.192 81.768 ;
    END
  END rec_out[263]
  PIN rec_out[264]
    DIRECTION OUTPUT ;
    USE SIGNAL ;
    SHAPE ABUTMENT ;
    PORT
      LAYER M4 ;
      RECT 0.000 81.840 0.192 81.864 ;
    END
  END rec_out[264]
  PIN rec_out[265]
    DIRECTION OUTPUT ;
    USE SIGNAL ;
    SHAPE ABUTMENT ;
    PORT
      LAYER M4 ;
      RECT 0.000 81.936 0.192 81.960 ;
    END
  END rec_out[265]
  PIN rec_out[266]
    DIRECTION OUTPUT ;
    USE SIGNAL ;
    SHAPE ABUTMENT ;
    PORT
      LAYER M4 ;
      RECT 0.000 82.032 0.192 82.056 ;
    END
  END rec_out[266]
  PIN rec_out[267]
    DIRECTION OUTPUT ;
    USE SIGNAL ;
    SHAPE ABUTMENT ;
    PORT
      LAYER M4 ;
      RECT 0.000 82.128 0.192 82.152 ;
    END
  END rec_out[267]
  PIN rec_out[268]
    DIRECTION OUTPUT ;
    USE SIGNAL ;
    SHAPE ABUTMENT ;
    PORT
      LAYER M4 ;
      RECT 0.000 82.224 0.192 82.248 ;
    END
  END rec_out[268]
  PIN rec_out[269]
    DIRECTION OUTPUT ;
    USE SIGNAL ;
    SHAPE ABUTMENT ;
    PORT
      LAYER M4 ;
      RECT 0.000 82.320 0.192 82.344 ;
    END
  END rec_out[269]
  PIN rec_out[270]
    DIRECTION OUTPUT ;
    USE SIGNAL ;
    SHAPE ABUTMENT ;
    PORT
      LAYER M4 ;
      RECT 0.000 82.416 0.192 82.440 ;
    END
  END rec_out[270]
  PIN rec_out[271]
    DIRECTION OUTPUT ;
    USE SIGNAL ;
    SHAPE ABUTMENT ;
    PORT
      LAYER M4 ;
      RECT 0.000 82.560 0.192 82.584 ;
    END
  END rec_out[271]
  PIN rec_out[272]
    DIRECTION OUTPUT ;
    USE SIGNAL ;
    SHAPE ABUTMENT ;
    PORT
      LAYER M4 ;
      RECT 0.000 82.656 0.192 82.680 ;
    END
  END rec_out[272]
  PIN rec_out[273]
    DIRECTION OUTPUT ;
    USE SIGNAL ;
    SHAPE ABUTMENT ;
    PORT
      LAYER M4 ;
      RECT 0.000 82.752 0.192 82.776 ;
    END
  END rec_out[273]
  PIN rec_out[274]
    DIRECTION OUTPUT ;
    USE SIGNAL ;
    SHAPE ABUTMENT ;
    PORT
      LAYER M4 ;
      RECT 0.000 82.848 0.192 82.872 ;
    END
  END rec_out[274]
  PIN rec_out[275]
    DIRECTION OUTPUT ;
    USE SIGNAL ;
    SHAPE ABUTMENT ;
    PORT
      LAYER M4 ;
      RECT 0.000 82.944 0.192 82.968 ;
    END
  END rec_out[275]
  PIN rec_out[276]
    DIRECTION OUTPUT ;
    USE SIGNAL ;
    SHAPE ABUTMENT ;
    PORT
      LAYER M4 ;
      RECT 0.000 83.040 0.192 83.064 ;
    END
  END rec_out[276]
  PIN rec_out[277]
    DIRECTION OUTPUT ;
    USE SIGNAL ;
    SHAPE ABUTMENT ;
    PORT
      LAYER M4 ;
      RECT 0.000 83.136 0.192 83.160 ;
    END
  END rec_out[277]
  PIN rec_out[278]
    DIRECTION OUTPUT ;
    USE SIGNAL ;
    SHAPE ABUTMENT ;
    PORT
      LAYER M4 ;
      RECT 0.000 83.232 0.192 83.256 ;
    END
  END rec_out[278]
  PIN rec_out[279]
    DIRECTION OUTPUT ;
    USE SIGNAL ;
    SHAPE ABUTMENT ;
    PORT
      LAYER M4 ;
      RECT 0.000 83.328 0.192 83.352 ;
    END
  END rec_out[279]
  PIN rec_out[280]
    DIRECTION OUTPUT ;
    USE SIGNAL ;
    SHAPE ABUTMENT ;
    PORT
      LAYER M4 ;
      RECT 0.000 83.424 0.192 83.448 ;
    END
  END rec_out[280]
  PIN rec_out[281]
    DIRECTION OUTPUT ;
    USE SIGNAL ;
    SHAPE ABUTMENT ;
    PORT
      LAYER M4 ;
      RECT 0.000 83.520 0.192 83.544 ;
    END
  END rec_out[281]
  PIN rec_out[282]
    DIRECTION OUTPUT ;
    USE SIGNAL ;
    SHAPE ABUTMENT ;
    PORT
      LAYER M4 ;
      RECT 0.000 83.664 0.192 83.688 ;
    END
  END rec_out[282]
  PIN rec_out[283]
    DIRECTION OUTPUT ;
    USE SIGNAL ;
    SHAPE ABUTMENT ;
    PORT
      LAYER M4 ;
      RECT 0.000 83.760 0.192 83.784 ;
    END
  END rec_out[283]
  PIN rec_out[284]
    DIRECTION OUTPUT ;
    USE SIGNAL ;
    SHAPE ABUTMENT ;
    PORT
      LAYER M4 ;
      RECT 0.000 83.856 0.192 83.880 ;
    END
  END rec_out[284]
  PIN rec_out[285]
    DIRECTION OUTPUT ;
    USE SIGNAL ;
    SHAPE ABUTMENT ;
    PORT
      LAYER M4 ;
      RECT 0.000 83.952 0.192 83.976 ;
    END
  END rec_out[285]
  PIN rec_out[286]
    DIRECTION OUTPUT ;
    USE SIGNAL ;
    SHAPE ABUTMENT ;
    PORT
      LAYER M4 ;
      RECT 0.000 84.048 0.192 84.072 ;
    END
  END rec_out[286]
  PIN rec_out[287]
    DIRECTION OUTPUT ;
    USE SIGNAL ;
    SHAPE ABUTMENT ;
    PORT
      LAYER M4 ;
      RECT 0.000 84.144 0.192 84.168 ;
    END
  END rec_out[287]
  PIN rec_out[288]
    DIRECTION OUTPUT ;
    USE SIGNAL ;
    SHAPE ABUTMENT ;
    PORT
      LAYER M4 ;
      RECT 0.000 84.240 0.192 84.264 ;
    END
  END rec_out[288]
  PIN rec_out[289]
    DIRECTION OUTPUT ;
    USE SIGNAL ;
    SHAPE ABUTMENT ;
    PORT
      LAYER M4 ;
      RECT 0.000 84.336 0.192 84.360 ;
    END
  END rec_out[289]
  PIN rec_out[290]
    DIRECTION OUTPUT ;
    USE SIGNAL ;
    SHAPE ABUTMENT ;
    PORT
      LAYER M4 ;
      RECT 0.000 84.432 0.192 84.456 ;
    END
  END rec_out[290]
  PIN rec_out[291]
    DIRECTION OUTPUT ;
    USE SIGNAL ;
    SHAPE ABUTMENT ;
    PORT
      LAYER M4 ;
      RECT 0.000 84.528 0.192 84.552 ;
    END
  END rec_out[291]
  PIN rec_out[292]
    DIRECTION OUTPUT ;
    USE SIGNAL ;
    SHAPE ABUTMENT ;
    PORT
      LAYER M4 ;
      RECT 0.000 84.624 0.192 84.648 ;
    END
  END rec_out[292]
  PIN rec_out[293]
    DIRECTION OUTPUT ;
    USE SIGNAL ;
    SHAPE ABUTMENT ;
    PORT
      LAYER M4 ;
      RECT 0.000 84.720 0.192 84.744 ;
    END
  END rec_out[293]
  PIN rec_out[294]
    DIRECTION OUTPUT ;
    USE SIGNAL ;
    SHAPE ABUTMENT ;
    PORT
      LAYER M4 ;
      RECT 0.000 84.864 0.192 84.888 ;
    END
  END rec_out[294]
  PIN rec_out[295]
    DIRECTION OUTPUT ;
    USE SIGNAL ;
    SHAPE ABUTMENT ;
    PORT
      LAYER M4 ;
      RECT 0.000 84.960 0.192 84.984 ;
    END
  END rec_out[295]
  PIN rec_out[296]
    DIRECTION OUTPUT ;
    USE SIGNAL ;
    SHAPE ABUTMENT ;
    PORT
      LAYER M4 ;
      RECT 0.000 85.056 0.192 85.080 ;
    END
  END rec_out[296]
  PIN rec_out[297]
    DIRECTION OUTPUT ;
    USE SIGNAL ;
    SHAPE ABUTMENT ;
    PORT
      LAYER M4 ;
      RECT 0.000 85.152 0.192 85.176 ;
    END
  END rec_out[297]
  PIN rec_out[298]
    DIRECTION OUTPUT ;
    USE SIGNAL ;
    SHAPE ABUTMENT ;
    PORT
      LAYER M4 ;
      RECT 0.000 85.248 0.192 85.272 ;
    END
  END rec_out[298]
  PIN rec_out[299]
    DIRECTION OUTPUT ;
    USE SIGNAL ;
    SHAPE ABUTMENT ;
    PORT
      LAYER M4 ;
      RECT 0.000 85.344 0.192 85.368 ;
    END
  END rec_out[299]
  PIN rec_out[300]
    DIRECTION OUTPUT ;
    USE SIGNAL ;
    SHAPE ABUTMENT ;
    PORT
      LAYER M4 ;
      RECT 0.000 85.440 0.192 85.464 ;
    END
  END rec_out[300]
  PIN rec_out[301]
    DIRECTION OUTPUT ;
    USE SIGNAL ;
    SHAPE ABUTMENT ;
    PORT
      LAYER M4 ;
      RECT 0.000 85.536 0.192 85.560 ;
    END
  END rec_out[301]
  PIN rec_out[302]
    DIRECTION OUTPUT ;
    USE SIGNAL ;
    SHAPE ABUTMENT ;
    PORT
      LAYER M4 ;
      RECT 0.000 85.632 0.192 85.656 ;
    END
  END rec_out[302]
  PIN rec_out[303]
    DIRECTION OUTPUT ;
    USE SIGNAL ;
    SHAPE ABUTMENT ;
    PORT
      LAYER M4 ;
      RECT 0.000 85.728 0.192 85.752 ;
    END
  END rec_out[303]
  PIN rec_out[304]
    DIRECTION OUTPUT ;
    USE SIGNAL ;
    SHAPE ABUTMENT ;
    PORT
      LAYER M4 ;
      RECT 0.000 85.824 0.192 85.848 ;
    END
  END rec_out[304]
  PIN rec_out[305]
    DIRECTION OUTPUT ;
    USE SIGNAL ;
    SHAPE ABUTMENT ;
    PORT
      LAYER M4 ;
      RECT 0.000 85.968 0.192 85.992 ;
    END
  END rec_out[305]
  PIN rec_out[306]
    DIRECTION OUTPUT ;
    USE SIGNAL ;
    SHAPE ABUTMENT ;
    PORT
      LAYER M4 ;
      RECT 0.000 86.064 0.192 86.088 ;
    END
  END rec_out[306]
  PIN rec_out[307]
    DIRECTION OUTPUT ;
    USE SIGNAL ;
    SHAPE ABUTMENT ;
    PORT
      LAYER M4 ;
      RECT 0.000 86.160 0.192 86.184 ;
    END
  END rec_out[307]
  PIN rec_out[308]
    DIRECTION OUTPUT ;
    USE SIGNAL ;
    SHAPE ABUTMENT ;
    PORT
      LAYER M4 ;
      RECT 0.000 86.256 0.192 86.280 ;
    END
  END rec_out[308]
  PIN rec_out[309]
    DIRECTION OUTPUT ;
    USE SIGNAL ;
    SHAPE ABUTMENT ;
    PORT
      LAYER M4 ;
      RECT 0.000 86.352 0.192 86.376 ;
    END
  END rec_out[309]
  PIN rec_out[310]
    DIRECTION OUTPUT ;
    USE SIGNAL ;
    SHAPE ABUTMENT ;
    PORT
      LAYER M4 ;
      RECT 0.000 86.448 0.192 86.472 ;
    END
  END rec_out[310]
  PIN rec_out[311]
    DIRECTION OUTPUT ;
    USE SIGNAL ;
    SHAPE ABUTMENT ;
    PORT
      LAYER M4 ;
      RECT 0.000 86.544 0.192 86.568 ;
    END
  END rec_out[311]
  PIN rec_out[312]
    DIRECTION OUTPUT ;
    USE SIGNAL ;
    SHAPE ABUTMENT ;
    PORT
      LAYER M4 ;
      RECT 0.000 86.640 0.192 86.664 ;
    END
  END rec_out[312]
  PIN rec_out[313]
    DIRECTION OUTPUT ;
    USE SIGNAL ;
    SHAPE ABUTMENT ;
    PORT
      LAYER M4 ;
      RECT 0.000 86.736 0.192 86.760 ;
    END
  END rec_out[313]
  PIN rec_out[314]
    DIRECTION OUTPUT ;
    USE SIGNAL ;
    SHAPE ABUTMENT ;
    PORT
      LAYER M4 ;
      RECT 0.000 86.832 0.192 86.856 ;
    END
  END rec_out[314]
  PIN rec_out[315]
    DIRECTION OUTPUT ;
    USE SIGNAL ;
    SHAPE ABUTMENT ;
    PORT
      LAYER M4 ;
      RECT 0.000 86.928 0.192 86.952 ;
    END
  END rec_out[315]
  PIN rec_out[316]
    DIRECTION OUTPUT ;
    USE SIGNAL ;
    SHAPE ABUTMENT ;
    PORT
      LAYER M4 ;
      RECT 0.000 87.024 0.192 87.048 ;
    END
  END rec_out[316]
  PIN rec_out[317]
    DIRECTION OUTPUT ;
    USE SIGNAL ;
    SHAPE ABUTMENT ;
    PORT
      LAYER M4 ;
      RECT 0.000 87.168 0.192 87.192 ;
    END
  END rec_out[317]
  PIN rec_out[318]
    DIRECTION OUTPUT ;
    USE SIGNAL ;
    SHAPE ABUTMENT ;
    PORT
      LAYER M4 ;
      RECT 0.000 87.264 0.192 87.288 ;
    END
  END rec_out[318]
  PIN rec_out[319]
    DIRECTION OUTPUT ;
    USE SIGNAL ;
    SHAPE ABUTMENT ;
    PORT
      LAYER M4 ;
      RECT 0.000 87.360 0.192 87.384 ;
    END
  END rec_out[319]
  PIN rec_out[320]
    DIRECTION OUTPUT ;
    USE SIGNAL ;
    SHAPE ABUTMENT ;
    PORT
      LAYER M4 ;
      RECT 0.000 87.456 0.192 87.480 ;
    END
  END rec_out[320]
  PIN rec_out[321]
    DIRECTION OUTPUT ;
    USE SIGNAL ;
    SHAPE ABUTMENT ;
    PORT
      LAYER M4 ;
      RECT 0.000 87.552 0.192 87.576 ;
    END
  END rec_out[321]
  PIN rec_out[322]
    DIRECTION OUTPUT ;
    USE SIGNAL ;
    SHAPE ABUTMENT ;
    PORT
      LAYER M4 ;
      RECT 0.000 87.648 0.192 87.672 ;
    END
  END rec_out[322]
  PIN rec_out[323]
    DIRECTION OUTPUT ;
    USE SIGNAL ;
    SHAPE ABUTMENT ;
    PORT
      LAYER M4 ;
      RECT 0.000 87.744 0.192 87.768 ;
    END
  END rec_out[323]
  PIN rec_out[324]
    DIRECTION OUTPUT ;
    USE SIGNAL ;
    SHAPE ABUTMENT ;
    PORT
      LAYER M4 ;
      RECT 0.000 87.840 0.192 87.864 ;
    END
  END rec_out[324]
  PIN rec_out[325]
    DIRECTION OUTPUT ;
    USE SIGNAL ;
    SHAPE ABUTMENT ;
    PORT
      LAYER M4 ;
      RECT 0.000 87.936 0.192 87.960 ;
    END
  END rec_out[325]
  PIN rec_out[326]
    DIRECTION OUTPUT ;
    USE SIGNAL ;
    SHAPE ABUTMENT ;
    PORT
      LAYER M4 ;
      RECT 0.000 88.032 0.192 88.056 ;
    END
  END rec_out[326]
  PIN rec_out[327]
    DIRECTION OUTPUT ;
    USE SIGNAL ;
    SHAPE ABUTMENT ;
    PORT
      LAYER M4 ;
      RECT 0.000 88.128 0.192 88.152 ;
    END
  END rec_out[327]
  PIN rec_out[328]
    DIRECTION OUTPUT ;
    USE SIGNAL ;
    SHAPE ABUTMENT ;
    PORT
      LAYER M4 ;
      RECT 0.000 88.272 0.192 88.296 ;
    END
  END rec_out[328]
  PIN rec_out[329]
    DIRECTION OUTPUT ;
    USE SIGNAL ;
    SHAPE ABUTMENT ;
    PORT
      LAYER M4 ;
      RECT 0.000 88.368 0.192 88.392 ;
    END
  END rec_out[329]
  PIN rec_out[330]
    DIRECTION OUTPUT ;
    USE SIGNAL ;
    SHAPE ABUTMENT ;
    PORT
      LAYER M4 ;
      RECT 0.000 88.464 0.192 88.488 ;
    END
  END rec_out[330]
  PIN rec_out[331]
    DIRECTION OUTPUT ;
    USE SIGNAL ;
    SHAPE ABUTMENT ;
    PORT
      LAYER M4 ;
      RECT 0.000 88.560 0.192 88.584 ;
    END
  END rec_out[331]
  PIN rec_out[332]
    DIRECTION OUTPUT ;
    USE SIGNAL ;
    SHAPE ABUTMENT ;
    PORT
      LAYER M4 ;
      RECT 0.000 88.656 0.192 88.680 ;
    END
  END rec_out[332]
  PIN rec_out[333]
    DIRECTION OUTPUT ;
    USE SIGNAL ;
    SHAPE ABUTMENT ;
    PORT
      LAYER M4 ;
      RECT 0.000 88.752 0.192 88.776 ;
    END
  END rec_out[333]
  PIN rec_out[334]
    DIRECTION OUTPUT ;
    USE SIGNAL ;
    SHAPE ABUTMENT ;
    PORT
      LAYER M4 ;
      RECT 0.000 88.848 0.192 88.872 ;
    END
  END rec_out[334]
  PIN rec_out[335]
    DIRECTION OUTPUT ;
    USE SIGNAL ;
    SHAPE ABUTMENT ;
    PORT
      LAYER M4 ;
      RECT 0.000 88.944 0.192 88.968 ;
    END
  END rec_out[335]
  PIN rec_out[336]
    DIRECTION OUTPUT ;
    USE SIGNAL ;
    SHAPE ABUTMENT ;
    PORT
      LAYER M4 ;
      RECT 0.000 89.040 0.192 89.064 ;
    END
  END rec_out[336]
  PIN rec_out[337]
    DIRECTION OUTPUT ;
    USE SIGNAL ;
    SHAPE ABUTMENT ;
    PORT
      LAYER M4 ;
      RECT 0.000 89.136 0.192 89.160 ;
    END
  END rec_out[337]
  PIN rec_out[338]
    DIRECTION OUTPUT ;
    USE SIGNAL ;
    SHAPE ABUTMENT ;
    PORT
      LAYER M4 ;
      RECT 0.000 89.232 0.192 89.256 ;
    END
  END rec_out[338]
  PIN rec_out[339]
    DIRECTION OUTPUT ;
    USE SIGNAL ;
    SHAPE ABUTMENT ;
    PORT
      LAYER M4 ;
      RECT 0.000 89.328 0.192 89.352 ;
    END
  END rec_out[339]
  PIN rec_out[340]
    DIRECTION OUTPUT ;
    USE SIGNAL ;
    SHAPE ABUTMENT ;
    PORT
      LAYER M4 ;
      RECT 0.000 89.472 0.192 89.496 ;
    END
  END rec_out[340]
  PIN rec_out[341]
    DIRECTION OUTPUT ;
    USE SIGNAL ;
    SHAPE ABUTMENT ;
    PORT
      LAYER M4 ;
      RECT 0.000 89.568 0.192 89.592 ;
    END
  END rec_out[341]
  PIN rec_out[342]
    DIRECTION OUTPUT ;
    USE SIGNAL ;
    SHAPE ABUTMENT ;
    PORT
      LAYER M4 ;
      RECT 0.000 89.664 0.192 89.688 ;
    END
  END rec_out[342]
  PIN rec_out[343]
    DIRECTION OUTPUT ;
    USE SIGNAL ;
    SHAPE ABUTMENT ;
    PORT
      LAYER M4 ;
      RECT 0.000 89.760 0.192 89.784 ;
    END
  END rec_out[343]
  PIN rec_out[344]
    DIRECTION OUTPUT ;
    USE SIGNAL ;
    SHAPE ABUTMENT ;
    PORT
      LAYER M4 ;
      RECT 0.000 89.856 0.192 89.880 ;
    END
  END rec_out[344]
  PIN rec_out[345]
    DIRECTION OUTPUT ;
    USE SIGNAL ;
    SHAPE ABUTMENT ;
    PORT
      LAYER M4 ;
      RECT 0.000 89.952 0.192 89.976 ;
    END
  END rec_out[345]
  PIN rec_out[346]
    DIRECTION OUTPUT ;
    USE SIGNAL ;
    SHAPE ABUTMENT ;
    PORT
      LAYER M4 ;
      RECT 0.000 90.048 0.192 90.072 ;
    END
  END rec_out[346]
  PIN rec_out[347]
    DIRECTION OUTPUT ;
    USE SIGNAL ;
    SHAPE ABUTMENT ;
    PORT
      LAYER M4 ;
      RECT 0.000 90.144 0.192 90.168 ;
    END
  END rec_out[347]
  PIN rec_out[348]
    DIRECTION OUTPUT ;
    USE SIGNAL ;
    SHAPE ABUTMENT ;
    PORT
      LAYER M4 ;
      RECT 0.000 90.240 0.192 90.264 ;
    END
  END rec_out[348]
  PIN rec_out[349]
    DIRECTION OUTPUT ;
    USE SIGNAL ;
    SHAPE ABUTMENT ;
    PORT
      LAYER M4 ;
      RECT 0.000 90.336 0.192 90.360 ;
    END
  END rec_out[349]
  PIN rec_out[350]
    DIRECTION OUTPUT ;
    USE SIGNAL ;
    SHAPE ABUTMENT ;
    PORT
      LAYER M4 ;
      RECT 0.000 90.432 0.192 90.456 ;
    END
  END rec_out[350]
  PIN rec_out[351]
    DIRECTION OUTPUT ;
    USE SIGNAL ;
    SHAPE ABUTMENT ;
    PORT
      LAYER M4 ;
      RECT 0.000 90.528 0.192 90.552 ;
    END
  END rec_out[351]
  PIN rec_out[352]
    DIRECTION OUTPUT ;
    USE SIGNAL ;
    SHAPE ABUTMENT ;
    PORT
      LAYER M4 ;
      RECT 0.000 90.672 0.192 90.696 ;
    END
  END rec_out[352]
  PIN rec_out[353]
    DIRECTION OUTPUT ;
    USE SIGNAL ;
    SHAPE ABUTMENT ;
    PORT
      LAYER M4 ;
      RECT 0.000 90.768 0.192 90.792 ;
    END
  END rec_out[353]
  PIN rec_out[354]
    DIRECTION OUTPUT ;
    USE SIGNAL ;
    SHAPE ABUTMENT ;
    PORT
      LAYER M4 ;
      RECT 0.000 90.864 0.192 90.888 ;
    END
  END rec_out[354]
  PIN rec_out[355]
    DIRECTION OUTPUT ;
    USE SIGNAL ;
    SHAPE ABUTMENT ;
    PORT
      LAYER M4 ;
      RECT 0.000 90.960 0.192 90.984 ;
    END
  END rec_out[355]
  PIN rec_out[356]
    DIRECTION OUTPUT ;
    USE SIGNAL ;
    SHAPE ABUTMENT ;
    PORT
      LAYER M4 ;
      RECT 0.000 91.056 0.192 91.080 ;
    END
  END rec_out[356]
  PIN rec_out[357]
    DIRECTION OUTPUT ;
    USE SIGNAL ;
    SHAPE ABUTMENT ;
    PORT
      LAYER M4 ;
      RECT 0.000 91.152 0.192 91.176 ;
    END
  END rec_out[357]
  PIN rec_out[358]
    DIRECTION OUTPUT ;
    USE SIGNAL ;
    SHAPE ABUTMENT ;
    PORT
      LAYER M4 ;
      RECT 0.000 91.248 0.192 91.272 ;
    END
  END rec_out[358]
  PIN rec_out[359]
    DIRECTION OUTPUT ;
    USE SIGNAL ;
    SHAPE ABUTMENT ;
    PORT
      LAYER M4 ;
      RECT 0.000 91.344 0.192 91.368 ;
    END
  END rec_out[359]
  PIN rec_out[360]
    DIRECTION OUTPUT ;
    USE SIGNAL ;
    SHAPE ABUTMENT ;
    PORT
      LAYER M4 ;
      RECT 0.000 91.440 0.192 91.464 ;
    END
  END rec_out[360]
  PIN rec_out[361]
    DIRECTION OUTPUT ;
    USE SIGNAL ;
    SHAPE ABUTMENT ;
    PORT
      LAYER M4 ;
      RECT 0.000 91.536 0.192 91.560 ;
    END
  END rec_out[361]
  PIN rec_out[362]
    DIRECTION OUTPUT ;
    USE SIGNAL ;
    SHAPE ABUTMENT ;
    PORT
      LAYER M4 ;
      RECT 0.000 91.632 0.192 91.656 ;
    END
  END rec_out[362]
  PIN rec_out[363]
    DIRECTION OUTPUT ;
    USE SIGNAL ;
    SHAPE ABUTMENT ;
    PORT
      LAYER M4 ;
      RECT 0.000 91.776 0.192 91.800 ;
    END
  END rec_out[363]
  PIN rec_out[364]
    DIRECTION OUTPUT ;
    USE SIGNAL ;
    SHAPE ABUTMENT ;
    PORT
      LAYER M4 ;
      RECT 0.000 91.872 0.192 91.896 ;
    END
  END rec_out[364]
  PIN rec_out[365]
    DIRECTION OUTPUT ;
    USE SIGNAL ;
    SHAPE ABUTMENT ;
    PORT
      LAYER M4 ;
      RECT 0.000 91.968 0.192 91.992 ;
    END
  END rec_out[365]
  PIN rec_out[366]
    DIRECTION OUTPUT ;
    USE SIGNAL ;
    SHAPE ABUTMENT ;
    PORT
      LAYER M4 ;
      RECT 0.000 92.064 0.192 92.088 ;
    END
  END rec_out[366]
  PIN rec_out[367]
    DIRECTION OUTPUT ;
    USE SIGNAL ;
    SHAPE ABUTMENT ;
    PORT
      LAYER M4 ;
      RECT 0.000 92.160 0.192 92.184 ;
    END
  END rec_out[367]
  PIN rec_out[368]
    DIRECTION OUTPUT ;
    USE SIGNAL ;
    SHAPE ABUTMENT ;
    PORT
      LAYER M4 ;
      RECT 0.000 92.256 0.192 92.280 ;
    END
  END rec_out[368]
  PIN rec_out[369]
    DIRECTION OUTPUT ;
    USE SIGNAL ;
    SHAPE ABUTMENT ;
    PORT
      LAYER M4 ;
      RECT 0.000 92.352 0.192 92.376 ;
    END
  END rec_out[369]
  PIN rec_out[370]
    DIRECTION OUTPUT ;
    USE SIGNAL ;
    SHAPE ABUTMENT ;
    PORT
      LAYER M4 ;
      RECT 0.000 92.448 0.192 92.472 ;
    END
  END rec_out[370]
  PIN rec_out[371]
    DIRECTION OUTPUT ;
    USE SIGNAL ;
    SHAPE ABUTMENT ;
    PORT
      LAYER M4 ;
      RECT 0.000 92.544 0.192 92.568 ;
    END
  END rec_out[371]
  PIN rec_out[372]
    DIRECTION OUTPUT ;
    USE SIGNAL ;
    SHAPE ABUTMENT ;
    PORT
      LAYER M4 ;
      RECT 0.000 92.640 0.192 92.664 ;
    END
  END rec_out[372]
  PIN rec_out[373]
    DIRECTION OUTPUT ;
    USE SIGNAL ;
    SHAPE ABUTMENT ;
    PORT
      LAYER M4 ;
      RECT 0.000 92.736 0.192 92.760 ;
    END
  END rec_out[373]
  PIN rec_out[374]
    DIRECTION OUTPUT ;
    USE SIGNAL ;
    SHAPE ABUTMENT ;
    PORT
      LAYER M4 ;
      RECT 0.000 92.832 0.192 92.856 ;
    END
  END rec_out[374]
  PIN rec_out[375]
    DIRECTION OUTPUT ;
    USE SIGNAL ;
    SHAPE ABUTMENT ;
    PORT
      LAYER M4 ;
      RECT 0.000 92.976 0.192 93.000 ;
    END
  END rec_out[375]
  PIN rec_out[376]
    DIRECTION OUTPUT ;
    USE SIGNAL ;
    SHAPE ABUTMENT ;
    PORT
      LAYER M4 ;
      RECT 0.000 93.072 0.192 93.096 ;
    END
  END rec_out[376]
  PIN rec_out[377]
    DIRECTION OUTPUT ;
    USE SIGNAL ;
    SHAPE ABUTMENT ;
    PORT
      LAYER M4 ;
      RECT 0.000 93.168 0.192 93.192 ;
    END
  END rec_out[377]
  PIN rec_out[378]
    DIRECTION OUTPUT ;
    USE SIGNAL ;
    SHAPE ABUTMENT ;
    PORT
      LAYER M4 ;
      RECT 0.000 93.264 0.192 93.288 ;
    END
  END rec_out[378]
  PIN rec_out[379]
    DIRECTION OUTPUT ;
    USE SIGNAL ;
    SHAPE ABUTMENT ;
    PORT
      LAYER M4 ;
      RECT 0.000 93.360 0.192 93.384 ;
    END
  END rec_out[379]
  PIN rec_out[380]
    DIRECTION OUTPUT ;
    USE SIGNAL ;
    SHAPE ABUTMENT ;
    PORT
      LAYER M4 ;
      RECT 0.000 93.456 0.192 93.480 ;
    END
  END rec_out[380]
  PIN rec_out[381]
    DIRECTION OUTPUT ;
    USE SIGNAL ;
    SHAPE ABUTMENT ;
    PORT
      LAYER M4 ;
      RECT 0.000 93.552 0.192 93.576 ;
    END
  END rec_out[381]
  PIN rec_out[382]
    DIRECTION OUTPUT ;
    USE SIGNAL ;
    SHAPE ABUTMENT ;
    PORT
      LAYER M4 ;
      RECT 0.000 93.648 0.192 93.672 ;
    END
  END rec_out[382]
  PIN rec_out[383]
    DIRECTION OUTPUT ;
    USE SIGNAL ;
    SHAPE ABUTMENT ;
    PORT
      LAYER M4 ;
      RECT 0.000 93.744 0.192 93.768 ;
    END
  END rec_out[383]
  PIN rec_out[384]
    DIRECTION OUTPUT ;
    USE SIGNAL ;
    SHAPE ABUTMENT ;
    PORT
      LAYER M4 ;
      RECT 0.000 93.840 0.192 93.864 ;
    END
  END rec_out[384]
  PIN rec_out[385]
    DIRECTION OUTPUT ;
    USE SIGNAL ;
    SHAPE ABUTMENT ;
    PORT
      LAYER M4 ;
      RECT 0.000 93.936 0.192 93.960 ;
    END
  END rec_out[385]
  PIN rec_out[386]
    DIRECTION OUTPUT ;
    USE SIGNAL ;
    SHAPE ABUTMENT ;
    PORT
      LAYER M4 ;
      RECT 0.000 94.080 0.192 94.104 ;
    END
  END rec_out[386]
  PIN rec_out[387]
    DIRECTION OUTPUT ;
    USE SIGNAL ;
    SHAPE ABUTMENT ;
    PORT
      LAYER M4 ;
      RECT 0.000 94.176 0.192 94.200 ;
    END
  END rec_out[387]
  PIN rec_out[388]
    DIRECTION OUTPUT ;
    USE SIGNAL ;
    SHAPE ABUTMENT ;
    PORT
      LAYER M4 ;
      RECT 0.000 94.272 0.192 94.296 ;
    END
  END rec_out[388]
  PIN rec_out[389]
    DIRECTION OUTPUT ;
    USE SIGNAL ;
    SHAPE ABUTMENT ;
    PORT
      LAYER M4 ;
      RECT 0.000 94.368 0.192 94.392 ;
    END
  END rec_out[389]
  PIN rec_out[390]
    DIRECTION OUTPUT ;
    USE SIGNAL ;
    SHAPE ABUTMENT ;
    PORT
      LAYER M4 ;
      RECT 0.000 94.464 0.192 94.488 ;
    END
  END rec_out[390]
  PIN rec_out[391]
    DIRECTION OUTPUT ;
    USE SIGNAL ;
    SHAPE ABUTMENT ;
    PORT
      LAYER M4 ;
      RECT 0.000 94.560 0.192 94.584 ;
    END
  END rec_out[391]
  PIN rec_out[392]
    DIRECTION OUTPUT ;
    USE SIGNAL ;
    SHAPE ABUTMENT ;
    PORT
      LAYER M4 ;
      RECT 0.000 94.656 0.192 94.680 ;
    END
  END rec_out[392]
  PIN rec_out[393]
    DIRECTION OUTPUT ;
    USE SIGNAL ;
    SHAPE ABUTMENT ;
    PORT
      LAYER M4 ;
      RECT 0.000 94.752 0.192 94.776 ;
    END
  END rec_out[393]
  PIN rec_out[394]
    DIRECTION OUTPUT ;
    USE SIGNAL ;
    SHAPE ABUTMENT ;
    PORT
      LAYER M4 ;
      RECT 0.000 94.848 0.192 94.872 ;
    END
  END rec_out[394]
  PIN rec_out[395]
    DIRECTION OUTPUT ;
    USE SIGNAL ;
    SHAPE ABUTMENT ;
    PORT
      LAYER M4 ;
      RECT 0.000 94.944 0.192 94.968 ;
    END
  END rec_out[395]
  PIN rec_out[396]
    DIRECTION OUTPUT ;
    USE SIGNAL ;
    SHAPE ABUTMENT ;
    PORT
      LAYER M4 ;
      RECT 0.000 95.040 0.192 95.064 ;
    END
  END rec_out[396]
  PIN rec_out[397]
    DIRECTION OUTPUT ;
    USE SIGNAL ;
    SHAPE ABUTMENT ;
    PORT
      LAYER M4 ;
      RECT 0.000 95.136 0.192 95.160 ;
    END
  END rec_out[397]
  PIN rec_out[398]
    DIRECTION OUTPUT ;
    USE SIGNAL ;
    SHAPE ABUTMENT ;
    PORT
      LAYER M4 ;
      RECT 0.000 95.280 0.192 95.304 ;
    END
  END rec_out[398]
  PIN rec_out[399]
    DIRECTION OUTPUT ;
    USE SIGNAL ;
    SHAPE ABUTMENT ;
    PORT
      LAYER M4 ;
      RECT 0.000 95.376 0.192 95.400 ;
    END
  END rec_out[399]
  PIN rec_out[400]
    DIRECTION OUTPUT ;
    USE SIGNAL ;
    SHAPE ABUTMENT ;
    PORT
      LAYER M4 ;
      RECT 0.000 95.472 0.192 95.496 ;
    END
  END rec_out[400]
  PIN rec_out[401]
    DIRECTION OUTPUT ;
    USE SIGNAL ;
    SHAPE ABUTMENT ;
    PORT
      LAYER M4 ;
      RECT 0.000 95.568 0.192 95.592 ;
    END
  END rec_out[401]
  PIN rec_out[402]
    DIRECTION OUTPUT ;
    USE SIGNAL ;
    SHAPE ABUTMENT ;
    PORT
      LAYER M4 ;
      RECT 0.000 95.664 0.192 95.688 ;
    END
  END rec_out[402]
  PIN rec_out[403]
    DIRECTION OUTPUT ;
    USE SIGNAL ;
    SHAPE ABUTMENT ;
    PORT
      LAYER M4 ;
      RECT 0.000 95.760 0.192 95.784 ;
    END
  END rec_out[403]
  PIN rec_out[404]
    DIRECTION OUTPUT ;
    USE SIGNAL ;
    SHAPE ABUTMENT ;
    PORT
      LAYER M4 ;
      RECT 0.000 95.856 0.192 95.880 ;
    END
  END rec_out[404]
  PIN rec_out[405]
    DIRECTION OUTPUT ;
    USE SIGNAL ;
    SHAPE ABUTMENT ;
    PORT
      LAYER M4 ;
      RECT 0.000 95.952 0.192 95.976 ;
    END
  END rec_out[405]
  PIN rec_out[406]
    DIRECTION OUTPUT ;
    USE SIGNAL ;
    SHAPE ABUTMENT ;
    PORT
      LAYER M4 ;
      RECT 0.000 96.048 0.192 96.072 ;
    END
  END rec_out[406]
  PIN rec_out[407]
    DIRECTION OUTPUT ;
    USE SIGNAL ;
    SHAPE ABUTMENT ;
    PORT
      LAYER M4 ;
      RECT 0.000 96.144 0.192 96.168 ;
    END
  END rec_out[407]
  PIN rec_out[408]
    DIRECTION OUTPUT ;
    USE SIGNAL ;
    SHAPE ABUTMENT ;
    PORT
      LAYER M4 ;
      RECT 0.000 96.240 0.192 96.264 ;
    END
  END rec_out[408]
  PIN rec_out[409]
    DIRECTION OUTPUT ;
    USE SIGNAL ;
    SHAPE ABUTMENT ;
    PORT
      LAYER M4 ;
      RECT 0.000 96.384 0.192 96.408 ;
    END
  END rec_out[409]
  PIN rec_out[410]
    DIRECTION OUTPUT ;
    USE SIGNAL ;
    SHAPE ABUTMENT ;
    PORT
      LAYER M4 ;
      RECT 0.000 96.480 0.192 96.504 ;
    END
  END rec_out[410]
  PIN rec_out[411]
    DIRECTION OUTPUT ;
    USE SIGNAL ;
    SHAPE ABUTMENT ;
    PORT
      LAYER M4 ;
      RECT 0.000 96.576 0.192 96.600 ;
    END
  END rec_out[411]
  PIN rec_out[412]
    DIRECTION OUTPUT ;
    USE SIGNAL ;
    SHAPE ABUTMENT ;
    PORT
      LAYER M4 ;
      RECT 0.000 96.672 0.192 96.696 ;
    END
  END rec_out[412]
  PIN rec_out[413]
    DIRECTION OUTPUT ;
    USE SIGNAL ;
    SHAPE ABUTMENT ;
    PORT
      LAYER M4 ;
      RECT 0.000 96.768 0.192 96.792 ;
    END
  END rec_out[413]
  PIN rec_out[414]
    DIRECTION OUTPUT ;
    USE SIGNAL ;
    SHAPE ABUTMENT ;
    PORT
      LAYER M4 ;
      RECT 0.000 96.864 0.192 96.888 ;
    END
  END rec_out[414]
  PIN rec_out[415]
    DIRECTION OUTPUT ;
    USE SIGNAL ;
    SHAPE ABUTMENT ;
    PORT
      LAYER M4 ;
      RECT 0.000 96.960 0.192 96.984 ;
    END
  END rec_out[415]
  PIN rec_out[416]
    DIRECTION OUTPUT ;
    USE SIGNAL ;
    SHAPE ABUTMENT ;
    PORT
      LAYER M4 ;
      RECT 0.000 97.056 0.192 97.080 ;
    END
  END rec_out[416]
  PIN rec_out[417]
    DIRECTION OUTPUT ;
    USE SIGNAL ;
    SHAPE ABUTMENT ;
    PORT
      LAYER M4 ;
      RECT 0.000 97.152 0.192 97.176 ;
    END
  END rec_out[417]
  PIN rec_out[418]
    DIRECTION OUTPUT ;
    USE SIGNAL ;
    SHAPE ABUTMENT ;
    PORT
      LAYER M4 ;
      RECT 0.000 97.248 0.192 97.272 ;
    END
  END rec_out[418]
  PIN rec_out[419]
    DIRECTION OUTPUT ;
    USE SIGNAL ;
    SHAPE ABUTMENT ;
    PORT
      LAYER M4 ;
      RECT 0.000 97.344 0.192 97.368 ;
    END
  END rec_out[419]
  PIN rec_out[420]
    DIRECTION OUTPUT ;
    USE SIGNAL ;
    SHAPE ABUTMENT ;
    PORT
      LAYER M4 ;
      RECT 0.000 97.440 0.192 97.464 ;
    END
  END rec_out[420]
  PIN rec_out[421]
    DIRECTION OUTPUT ;
    USE SIGNAL ;
    SHAPE ABUTMENT ;
    PORT
      LAYER M4 ;
      RECT 0.000 97.584 0.192 97.608 ;
    END
  END rec_out[421]
  PIN rec_out[422]
    DIRECTION OUTPUT ;
    USE SIGNAL ;
    SHAPE ABUTMENT ;
    PORT
      LAYER M4 ;
      RECT 0.000 97.680 0.192 97.704 ;
    END
  END rec_out[422]
  PIN rec_out[423]
    DIRECTION OUTPUT ;
    USE SIGNAL ;
    SHAPE ABUTMENT ;
    PORT
      LAYER M4 ;
      RECT 0.000 97.776 0.192 97.800 ;
    END
  END rec_out[423]
  PIN rec_out[424]
    DIRECTION OUTPUT ;
    USE SIGNAL ;
    SHAPE ABUTMENT ;
    PORT
      LAYER M4 ;
      RECT 0.000 97.872 0.192 97.896 ;
    END
  END rec_out[424]
  PIN rec_out[425]
    DIRECTION OUTPUT ;
    USE SIGNAL ;
    SHAPE ABUTMENT ;
    PORT
      LAYER M4 ;
      RECT 0.000 97.968 0.192 97.992 ;
    END
  END rec_out[425]
  PIN rec_out[426]
    DIRECTION OUTPUT ;
    USE SIGNAL ;
    SHAPE ABUTMENT ;
    PORT
      LAYER M4 ;
      RECT 0.000 98.064 0.192 98.088 ;
    END
  END rec_out[426]
  PIN rec_out[427]
    DIRECTION OUTPUT ;
    USE SIGNAL ;
    SHAPE ABUTMENT ;
    PORT
      LAYER M4 ;
      RECT 0.000 98.160 0.192 98.184 ;
    END
  END rec_out[427]
  PIN rec_out[428]
    DIRECTION OUTPUT ;
    USE SIGNAL ;
    SHAPE ABUTMENT ;
    PORT
      LAYER M4 ;
      RECT 0.000 98.256 0.192 98.280 ;
    END
  END rec_out[428]
  PIN rec_out[429]
    DIRECTION OUTPUT ;
    USE SIGNAL ;
    SHAPE ABUTMENT ;
    PORT
      LAYER M4 ;
      RECT 0.000 98.352 0.192 98.376 ;
    END
  END rec_out[429]
  PIN rec_out[430]
    DIRECTION OUTPUT ;
    USE SIGNAL ;
    SHAPE ABUTMENT ;
    PORT
      LAYER M4 ;
      RECT 0.000 98.448 0.192 98.472 ;
    END
  END rec_out[430]
  PIN rec_out[431]
    DIRECTION OUTPUT ;
    USE SIGNAL ;
    SHAPE ABUTMENT ;
    PORT
      LAYER M4 ;
      RECT 0.000 98.544 0.192 98.568 ;
    END
  END rec_out[431]
  PIN rec_out[432]
    DIRECTION OUTPUT ;
    USE SIGNAL ;
    SHAPE ABUTMENT ;
    PORT
      LAYER M4 ;
      RECT 0.000 98.688 0.192 98.712 ;
    END
  END rec_out[432]
  PIN rec_out[433]
    DIRECTION OUTPUT ;
    USE SIGNAL ;
    SHAPE ABUTMENT ;
    PORT
      LAYER M4 ;
      RECT 0.000 98.784 0.192 98.808 ;
    END
  END rec_out[433]
  PIN rec_out[434]
    DIRECTION OUTPUT ;
    USE SIGNAL ;
    SHAPE ABUTMENT ;
    PORT
      LAYER M4 ;
      RECT 0.000 98.880 0.192 98.904 ;
    END
  END rec_out[434]
  PIN rec_out[435]
    DIRECTION OUTPUT ;
    USE SIGNAL ;
    SHAPE ABUTMENT ;
    PORT
      LAYER M4 ;
      RECT 0.000 98.976 0.192 99.000 ;
    END
  END rec_out[435]
  PIN rec_out[436]
    DIRECTION OUTPUT ;
    USE SIGNAL ;
    SHAPE ABUTMENT ;
    PORT
      LAYER M4 ;
      RECT 0.000 99.072 0.192 99.096 ;
    END
  END rec_out[436]
  PIN rec_out[437]
    DIRECTION OUTPUT ;
    USE SIGNAL ;
    SHAPE ABUTMENT ;
    PORT
      LAYER M4 ;
      RECT 0.000 99.168 0.192 99.192 ;
    END
  END rec_out[437]
  PIN rec_out[438]
    DIRECTION OUTPUT ;
    USE SIGNAL ;
    SHAPE ABUTMENT ;
    PORT
      LAYER M4 ;
      RECT 0.000 99.264 0.192 99.288 ;
    END
  END rec_out[438]
  PIN rec_out[439]
    DIRECTION OUTPUT ;
    USE SIGNAL ;
    SHAPE ABUTMENT ;
    PORT
      LAYER M4 ;
      RECT 0.000 99.360 0.192 99.384 ;
    END
  END rec_out[439]
  PIN rec_out[440]
    DIRECTION OUTPUT ;
    USE SIGNAL ;
    SHAPE ABUTMENT ;
    PORT
      LAYER M4 ;
      RECT 0.000 99.456 0.192 99.480 ;
    END
  END rec_out[440]
  PIN rec_out[441]
    DIRECTION OUTPUT ;
    USE SIGNAL ;
    SHAPE ABUTMENT ;
    PORT
      LAYER M4 ;
      RECT 0.000 99.552 0.192 99.576 ;
    END
  END rec_out[441]
  PIN rec_out[442]
    DIRECTION OUTPUT ;
    USE SIGNAL ;
    SHAPE ABUTMENT ;
    PORT
      LAYER M4 ;
      RECT 0.000 99.648 0.192 99.672 ;
    END
  END rec_out[442]
  PIN rec_out[443]
    DIRECTION OUTPUT ;
    USE SIGNAL ;
    SHAPE ABUTMENT ;
    PORT
      LAYER M4 ;
      RECT 0.000 99.744 0.192 99.768 ;
    END
  END rec_out[443]
  PIN rec_out[444]
    DIRECTION OUTPUT ;
    USE SIGNAL ;
    SHAPE ABUTMENT ;
    PORT
      LAYER M4 ;
      RECT 0.000 99.888 0.192 99.912 ;
    END
  END rec_out[444]
  PIN rec_out[445]
    DIRECTION OUTPUT ;
    USE SIGNAL ;
    SHAPE ABUTMENT ;
    PORT
      LAYER M4 ;
      RECT 0.000 99.984 0.192 100.008 ;
    END
  END rec_out[445]
  PIN rec_out[446]
    DIRECTION OUTPUT ;
    USE SIGNAL ;
    SHAPE ABUTMENT ;
    PORT
      LAYER M4 ;
      RECT 0.000 100.080 0.192 100.104 ;
    END
  END rec_out[446]
  PIN rec_out[447]
    DIRECTION OUTPUT ;
    USE SIGNAL ;
    SHAPE ABUTMENT ;
    PORT
      LAYER M4 ;
      RECT 0.000 100.176 0.192 100.200 ;
    END
  END rec_out[447]
  PIN rec_out[448]
    DIRECTION OUTPUT ;
    USE SIGNAL ;
    SHAPE ABUTMENT ;
    PORT
      LAYER M4 ;
      RECT 0.000 100.272 0.192 100.296 ;
    END
  END rec_out[448]
  PIN rec_out[449]
    DIRECTION OUTPUT ;
    USE SIGNAL ;
    SHAPE ABUTMENT ;
    PORT
      LAYER M4 ;
      RECT 0.000 100.368 0.192 100.392 ;
    END
  END rec_out[449]
  PIN rec_out[450]
    DIRECTION OUTPUT ;
    USE SIGNAL ;
    SHAPE ABUTMENT ;
    PORT
      LAYER M4 ;
      RECT 0.000 100.464 0.192 100.488 ;
    END
  END rec_out[450]
  PIN rec_out[451]
    DIRECTION OUTPUT ;
    USE SIGNAL ;
    SHAPE ABUTMENT ;
    PORT
      LAYER M4 ;
      RECT 0.000 100.560 0.192 100.584 ;
    END
  END rec_out[451]
  PIN rec_out[452]
    DIRECTION OUTPUT ;
    USE SIGNAL ;
    SHAPE ABUTMENT ;
    PORT
      LAYER M4 ;
      RECT 0.000 100.656 0.192 100.680 ;
    END
  END rec_out[452]
  PIN rec_out[453]
    DIRECTION OUTPUT ;
    USE SIGNAL ;
    SHAPE ABUTMENT ;
    PORT
      LAYER M4 ;
      RECT 0.000 100.752 0.192 100.776 ;
    END
  END rec_out[453]
  PIN rec_out[454]
    DIRECTION OUTPUT ;
    USE SIGNAL ;
    SHAPE ABUTMENT ;
    PORT
      LAYER M4 ;
      RECT 0.000 100.848 0.192 100.872 ;
    END
  END rec_out[454]
  PIN rec_out[455]
    DIRECTION OUTPUT ;
    USE SIGNAL ;
    SHAPE ABUTMENT ;
    PORT
      LAYER M4 ;
      RECT 0.000 100.992 0.192 101.016 ;
    END
  END rec_out[455]
  PIN rec_out[456]
    DIRECTION OUTPUT ;
    USE SIGNAL ;
    SHAPE ABUTMENT ;
    PORT
      LAYER M4 ;
      RECT 0.000 101.088 0.192 101.112 ;
    END
  END rec_out[456]
  PIN rec_out[457]
    DIRECTION OUTPUT ;
    USE SIGNAL ;
    SHAPE ABUTMENT ;
    PORT
      LAYER M4 ;
      RECT 0.000 101.184 0.192 101.208 ;
    END
  END rec_out[457]
  PIN rec_out[458]
    DIRECTION OUTPUT ;
    USE SIGNAL ;
    SHAPE ABUTMENT ;
    PORT
      LAYER M4 ;
      RECT 0.000 101.280 0.192 101.304 ;
    END
  END rec_out[458]
  PIN rec_out[459]
    DIRECTION OUTPUT ;
    USE SIGNAL ;
    SHAPE ABUTMENT ;
    PORT
      LAYER M4 ;
      RECT 0.000 101.376 0.192 101.400 ;
    END
  END rec_out[459]
  PIN rec_out[460]
    DIRECTION OUTPUT ;
    USE SIGNAL ;
    SHAPE ABUTMENT ;
    PORT
      LAYER M4 ;
      RECT 0.000 101.472 0.192 101.496 ;
    END
  END rec_out[460]
  PIN rec_out[461]
    DIRECTION OUTPUT ;
    USE SIGNAL ;
    SHAPE ABUTMENT ;
    PORT
      LAYER M4 ;
      RECT 0.000 101.568 0.192 101.592 ;
    END
  END rec_out[461]
  PIN rec_out[462]
    DIRECTION OUTPUT ;
    USE SIGNAL ;
    SHAPE ABUTMENT ;
    PORT
      LAYER M4 ;
      RECT 0.000 101.664 0.192 101.688 ;
    END
  END rec_out[462]
  PIN rec_out[463]
    DIRECTION OUTPUT ;
    USE SIGNAL ;
    SHAPE ABUTMENT ;
    PORT
      LAYER M4 ;
      RECT 0.000 101.760 0.192 101.784 ;
    END
  END rec_out[463]
  PIN rec_out[464]
    DIRECTION OUTPUT ;
    USE SIGNAL ;
    SHAPE ABUTMENT ;
    PORT
      LAYER M4 ;
      RECT 0.000 101.856 0.192 101.880 ;
    END
  END rec_out[464]
  PIN rec_out[465]
    DIRECTION OUTPUT ;
    USE SIGNAL ;
    SHAPE ABUTMENT ;
    PORT
      LAYER M4 ;
      RECT 0.000 101.952 0.192 101.976 ;
    END
  END rec_out[465]
  PIN rec_out[466]
    DIRECTION OUTPUT ;
    USE SIGNAL ;
    SHAPE ABUTMENT ;
    PORT
      LAYER M4 ;
      RECT 0.000 102.048 0.192 102.072 ;
    END
  END rec_out[466]
  PIN rec_out[467]
    DIRECTION OUTPUT ;
    USE SIGNAL ;
    SHAPE ABUTMENT ;
    PORT
      LAYER M4 ;
      RECT 0.000 102.192 0.192 102.216 ;
    END
  END rec_out[467]
  PIN rec_out[468]
    DIRECTION OUTPUT ;
    USE SIGNAL ;
    SHAPE ABUTMENT ;
    PORT
      LAYER M4 ;
      RECT 0.000 102.288 0.192 102.312 ;
    END
  END rec_out[468]
  PIN rec_out[469]
    DIRECTION OUTPUT ;
    USE SIGNAL ;
    SHAPE ABUTMENT ;
    PORT
      LAYER M4 ;
      RECT 0.000 102.384 0.192 102.408 ;
    END
  END rec_out[469]
  PIN rec_out[470]
    DIRECTION OUTPUT ;
    USE SIGNAL ;
    SHAPE ABUTMENT ;
    PORT
      LAYER M4 ;
      RECT 0.000 102.480 0.192 102.504 ;
    END
  END rec_out[470]
  PIN rec_out[471]
    DIRECTION OUTPUT ;
    USE SIGNAL ;
    SHAPE ABUTMENT ;
    PORT
      LAYER M4 ;
      RECT 0.000 102.576 0.192 102.600 ;
    END
  END rec_out[471]
  PIN rec_out[472]
    DIRECTION OUTPUT ;
    USE SIGNAL ;
    SHAPE ABUTMENT ;
    PORT
      LAYER M4 ;
      RECT 0.000 102.672 0.192 102.696 ;
    END
  END rec_out[472]
  PIN rec_out[473]
    DIRECTION OUTPUT ;
    USE SIGNAL ;
    SHAPE ABUTMENT ;
    PORT
      LAYER M4 ;
      RECT 0.000 102.768 0.192 102.792 ;
    END
  END rec_out[473]
  PIN rec_out[474]
    DIRECTION OUTPUT ;
    USE SIGNAL ;
    SHAPE ABUTMENT ;
    PORT
      LAYER M4 ;
      RECT 0.000 102.864 0.192 102.888 ;
    END
  END rec_out[474]
  PIN rec_out[475]
    DIRECTION OUTPUT ;
    USE SIGNAL ;
    SHAPE ABUTMENT ;
    PORT
      LAYER M4 ;
      RECT 0.000 102.960 0.192 102.984 ;
    END
  END rec_out[475]
  PIN rec_out[476]
    DIRECTION OUTPUT ;
    USE SIGNAL ;
    SHAPE ABUTMENT ;
    PORT
      LAYER M4 ;
      RECT 0.000 103.056 0.192 103.080 ;
    END
  END rec_out[476]
  PIN rec_out[477]
    DIRECTION OUTPUT ;
    USE SIGNAL ;
    SHAPE ABUTMENT ;
    PORT
      LAYER M4 ;
      RECT 0.000 103.152 0.192 103.176 ;
    END
  END rec_out[477]
  PIN rec_out[478]
    DIRECTION OUTPUT ;
    USE SIGNAL ;
    SHAPE ABUTMENT ;
    PORT
      LAYER M4 ;
      RECT 0.000 103.296 0.192 103.320 ;
    END
  END rec_out[478]
  PIN rec_out[479]
    DIRECTION OUTPUT ;
    USE SIGNAL ;
    SHAPE ABUTMENT ;
    PORT
      LAYER M4 ;
      RECT 0.000 103.392 0.192 103.416 ;
    END
  END rec_out[479]
  PIN rec_out[480]
    DIRECTION OUTPUT ;
    USE SIGNAL ;
    SHAPE ABUTMENT ;
    PORT
      LAYER M4 ;
      RECT 0.000 103.488 0.192 103.512 ;
    END
  END rec_out[480]
  PIN rec_out[481]
    DIRECTION OUTPUT ;
    USE SIGNAL ;
    SHAPE ABUTMENT ;
    PORT
      LAYER M4 ;
      RECT 0.000 103.584 0.192 103.608 ;
    END
  END rec_out[481]
  PIN rec_out[482]
    DIRECTION OUTPUT ;
    USE SIGNAL ;
    SHAPE ABUTMENT ;
    PORT
      LAYER M4 ;
      RECT 0.000 103.680 0.192 103.704 ;
    END
  END rec_out[482]
  PIN rec_out[483]
    DIRECTION OUTPUT ;
    USE SIGNAL ;
    SHAPE ABUTMENT ;
    PORT
      LAYER M4 ;
      RECT 0.000 103.776 0.192 103.800 ;
    END
  END rec_out[483]
  PIN rec_out[484]
    DIRECTION OUTPUT ;
    USE SIGNAL ;
    SHAPE ABUTMENT ;
    PORT
      LAYER M4 ;
      RECT 0.000 103.872 0.192 103.896 ;
    END
  END rec_out[484]
  PIN rec_out[485]
    DIRECTION OUTPUT ;
    USE SIGNAL ;
    SHAPE ABUTMENT ;
    PORT
      LAYER M4 ;
      RECT 0.000 103.968 0.192 103.992 ;
    END
  END rec_out[485]
  PIN rec_out[486]
    DIRECTION OUTPUT ;
    USE SIGNAL ;
    SHAPE ABUTMENT ;
    PORT
      LAYER M4 ;
      RECT 0.000 104.064 0.192 104.088 ;
    END
  END rec_out[486]
  PIN rec_out[487]
    DIRECTION OUTPUT ;
    USE SIGNAL ;
    SHAPE ABUTMENT ;
    PORT
      LAYER M4 ;
      RECT 0.000 104.160 0.192 104.184 ;
    END
  END rec_out[487]
  PIN rec_out[488]
    DIRECTION OUTPUT ;
    USE SIGNAL ;
    SHAPE ABUTMENT ;
    PORT
      LAYER M4 ;
      RECT 0.000 104.256 0.192 104.280 ;
    END
  END rec_out[488]
  PIN rec_out[489]
    DIRECTION OUTPUT ;
    USE SIGNAL ;
    SHAPE ABUTMENT ;
    PORT
      LAYER M4 ;
      RECT 0.000 104.352 0.192 104.376 ;
    END
  END rec_out[489]
  PIN rec_out[490]
    DIRECTION OUTPUT ;
    USE SIGNAL ;
    SHAPE ABUTMENT ;
    PORT
      LAYER M4 ;
      RECT 0.000 104.496 0.192 104.520 ;
    END
  END rec_out[490]
  PIN rec_out[491]
    DIRECTION OUTPUT ;
    USE SIGNAL ;
    SHAPE ABUTMENT ;
    PORT
      LAYER M4 ;
      RECT 0.000 104.592 0.192 104.616 ;
    END
  END rec_out[491]
  PIN rec_out[492]
    DIRECTION OUTPUT ;
    USE SIGNAL ;
    SHAPE ABUTMENT ;
    PORT
      LAYER M4 ;
      RECT 0.000 104.688 0.192 104.712 ;
    END
  END rec_out[492]
  PIN rec_out[493]
    DIRECTION OUTPUT ;
    USE SIGNAL ;
    SHAPE ABUTMENT ;
    PORT
      LAYER M4 ;
      RECT 0.000 104.784 0.192 104.808 ;
    END
  END rec_out[493]
  PIN rec_out[494]
    DIRECTION OUTPUT ;
    USE SIGNAL ;
    SHAPE ABUTMENT ;
    PORT
      LAYER M4 ;
      RECT 0.000 104.880 0.192 104.904 ;
    END
  END rec_out[494]
  PIN rec_out[495]
    DIRECTION OUTPUT ;
    USE SIGNAL ;
    SHAPE ABUTMENT ;
    PORT
      LAYER M4 ;
      RECT 0.000 104.976 0.192 105.000 ;
    END
  END rec_out[495]
  PIN rec_out[496]
    DIRECTION OUTPUT ;
    USE SIGNAL ;
    SHAPE ABUTMENT ;
    PORT
      LAYER M4 ;
      RECT 0.000 105.072 0.192 105.096 ;
    END
  END rec_out[496]
  PIN rec_out[497]
    DIRECTION OUTPUT ;
    USE SIGNAL ;
    SHAPE ABUTMENT ;
    PORT
      LAYER M4 ;
      RECT 0.000 105.168 0.192 105.192 ;
    END
  END rec_out[497]
  PIN rec_out[498]
    DIRECTION OUTPUT ;
    USE SIGNAL ;
    SHAPE ABUTMENT ;
    PORT
      LAYER M4 ;
      RECT 0.000 105.264 0.192 105.288 ;
    END
  END rec_out[498]
  PIN rec_out[499]
    DIRECTION OUTPUT ;
    USE SIGNAL ;
    SHAPE ABUTMENT ;
    PORT
      LAYER M4 ;
      RECT 0.000 105.360 0.192 105.384 ;
    END
  END rec_out[499]
  PIN rec_out[500]
    DIRECTION OUTPUT ;
    USE SIGNAL ;
    SHAPE ABUTMENT ;
    PORT
      LAYER M4 ;
      RECT 0.000 105.456 0.192 105.480 ;
    END
  END rec_out[500]
  PIN rec_out[501]
    DIRECTION OUTPUT ;
    USE SIGNAL ;
    SHAPE ABUTMENT ;
    PORT
      LAYER M4 ;
      RECT 0.000 105.600 0.192 105.624 ;
    END
  END rec_out[501]
  PIN rec_out[502]
    DIRECTION OUTPUT ;
    USE SIGNAL ;
    SHAPE ABUTMENT ;
    PORT
      LAYER M4 ;
      RECT 0.000 105.696 0.192 105.720 ;
    END
  END rec_out[502]
  PIN rec_out[503]
    DIRECTION OUTPUT ;
    USE SIGNAL ;
    SHAPE ABUTMENT ;
    PORT
      LAYER M4 ;
      RECT 0.000 105.792 0.192 105.816 ;
    END
  END rec_out[503]
  PIN rec_out[504]
    DIRECTION OUTPUT ;
    USE SIGNAL ;
    SHAPE ABUTMENT ;
    PORT
      LAYER M4 ;
      RECT 0.000 105.888 0.192 105.912 ;
    END
  END rec_out[504]
  PIN rec_out[505]
    DIRECTION OUTPUT ;
    USE SIGNAL ;
    SHAPE ABUTMENT ;
    PORT
      LAYER M4 ;
      RECT 0.000 105.984 0.192 106.008 ;
    END
  END rec_out[505]
  PIN rec_out[506]
    DIRECTION OUTPUT ;
    USE SIGNAL ;
    SHAPE ABUTMENT ;
    PORT
      LAYER M4 ;
      RECT 0.000 106.080 0.192 106.104 ;
    END
  END rec_out[506]
  PIN rec_out[507]
    DIRECTION OUTPUT ;
    USE SIGNAL ;
    SHAPE ABUTMENT ;
    PORT
      LAYER M4 ;
      RECT 0.000 106.176 0.192 106.200 ;
    END
  END rec_out[507]
  PIN rec_out[508]
    DIRECTION OUTPUT ;
    USE SIGNAL ;
    SHAPE ABUTMENT ;
    PORT
      LAYER M4 ;
      RECT 0.000 106.272 0.192 106.296 ;
    END
  END rec_out[508]
  PIN rec_out[509]
    DIRECTION OUTPUT ;
    USE SIGNAL ;
    SHAPE ABUTMENT ;
    PORT
      LAYER M4 ;
      RECT 0.000 106.368 0.192 106.392 ;
    END
  END rec_out[509]
  PIN rec_out[510]
    DIRECTION OUTPUT ;
    USE SIGNAL ;
    SHAPE ABUTMENT ;
    PORT
      LAYER M4 ;
      RECT 0.000 106.464 0.192 106.488 ;
    END
  END rec_out[510]
  PIN rec_out[511]
    DIRECTION OUTPUT ;
    USE SIGNAL ;
    SHAPE ABUTMENT ;
    PORT
      LAYER M4 ;
      RECT 0.000 106.560 0.192 106.584 ;
    END
  END rec_out[511]
  PIN rec_out[512]
    DIRECTION OUTPUT ;
    USE SIGNAL ;
    SHAPE ABUTMENT ;
    PORT
      LAYER M4 ;
      RECT 0.000 106.656 0.192 106.680 ;
    END
  END rec_out[512]
  PIN rec_out[513]
    DIRECTION OUTPUT ;
    USE SIGNAL ;
    SHAPE ABUTMENT ;
    PORT
      LAYER M4 ;
      RECT 0.000 106.800 0.192 106.824 ;
    END
  END rec_out[513]
  PIN rec_out[514]
    DIRECTION OUTPUT ;
    USE SIGNAL ;
    SHAPE ABUTMENT ;
    PORT
      LAYER M4 ;
      RECT 0.000 106.896 0.192 106.920 ;
    END
  END rec_out[514]
  PIN rec_out[515]
    DIRECTION OUTPUT ;
    USE SIGNAL ;
    SHAPE ABUTMENT ;
    PORT
      LAYER M4 ;
      RECT 0.000 106.992 0.192 107.016 ;
    END
  END rec_out[515]
  PIN rec_out[516]
    DIRECTION OUTPUT ;
    USE SIGNAL ;
    SHAPE ABUTMENT ;
    PORT
      LAYER M4 ;
      RECT 0.000 107.088 0.192 107.112 ;
    END
  END rec_out[516]
  PIN rec_out[517]
    DIRECTION OUTPUT ;
    USE SIGNAL ;
    SHAPE ABUTMENT ;
    PORT
      LAYER M4 ;
      RECT 0.000 107.184 0.192 107.208 ;
    END
  END rec_out[517]
  PIN rec_out[518]
    DIRECTION OUTPUT ;
    USE SIGNAL ;
    SHAPE ABUTMENT ;
    PORT
      LAYER M4 ;
      RECT 0.000 107.280 0.192 107.304 ;
    END
  END rec_out[518]
  PIN rec_out[519]
    DIRECTION OUTPUT ;
    USE SIGNAL ;
    SHAPE ABUTMENT ;
    PORT
      LAYER M4 ;
      RECT 0.000 107.376 0.192 107.400 ;
    END
  END rec_out[519]
  PIN rec_out[520]
    DIRECTION OUTPUT ;
    USE SIGNAL ;
    SHAPE ABUTMENT ;
    PORT
      LAYER M4 ;
      RECT 0.000 107.472 0.192 107.496 ;
    END
  END rec_out[520]
  PIN rec_out[521]
    DIRECTION OUTPUT ;
    USE SIGNAL ;
    SHAPE ABUTMENT ;
    PORT
      LAYER M4 ;
      RECT 0.000 107.568 0.192 107.592 ;
    END
  END rec_out[521]
  PIN rec_out[522]
    DIRECTION OUTPUT ;
    USE SIGNAL ;
    SHAPE ABUTMENT ;
    PORT
      LAYER M4 ;
      RECT 0.000 107.664 0.192 107.688 ;
    END
  END rec_out[522]
  PIN rec_out[523]
    DIRECTION OUTPUT ;
    USE SIGNAL ;
    SHAPE ABUTMENT ;
    PORT
      LAYER M4 ;
      RECT 0.000 107.760 0.192 107.784 ;
    END
  END rec_out[523]
  PIN rec_out[524]
    DIRECTION OUTPUT ;
    USE SIGNAL ;
    SHAPE ABUTMENT ;
    PORT
      LAYER M4 ;
      RECT 0.000 107.904 0.192 107.928 ;
    END
  END rec_out[524]
  PIN rec_out[525]
    DIRECTION OUTPUT ;
    USE SIGNAL ;
    SHAPE ABUTMENT ;
    PORT
      LAYER M4 ;
      RECT 0.000 108.000 0.192 108.024 ;
    END
  END rec_out[525]
  PIN rec_out[526]
    DIRECTION OUTPUT ;
    USE SIGNAL ;
    SHAPE ABUTMENT ;
    PORT
      LAYER M4 ;
      RECT 0.000 108.096 0.192 108.120 ;
    END
  END rec_out[526]
  PIN rec_out[527]
    DIRECTION OUTPUT ;
    USE SIGNAL ;
    SHAPE ABUTMENT ;
    PORT
      LAYER M4 ;
      RECT 0.000 108.192 0.192 108.216 ;
    END
  END rec_out[527]
  PIN rec_out[528]
    DIRECTION OUTPUT ;
    USE SIGNAL ;
    SHAPE ABUTMENT ;
    PORT
      LAYER M4 ;
      RECT 0.000 108.288 0.192 108.312 ;
    END
  END rec_out[528]
  PIN rec_out[529]
    DIRECTION OUTPUT ;
    USE SIGNAL ;
    SHAPE ABUTMENT ;
    PORT
      LAYER M4 ;
      RECT 0.000 108.384 0.192 108.408 ;
    END
  END rec_out[529]
  PIN rec_out[530]
    DIRECTION OUTPUT ;
    USE SIGNAL ;
    SHAPE ABUTMENT ;
    PORT
      LAYER M4 ;
      RECT 0.000 108.480 0.192 108.504 ;
    END
  END rec_out[530]
  PIN rec_out[531]
    DIRECTION OUTPUT ;
    USE SIGNAL ;
    SHAPE ABUTMENT ;
    PORT
      LAYER M4 ;
      RECT 0.000 108.576 0.192 108.600 ;
    END
  END rec_out[531]
  PIN rec_out[532]
    DIRECTION OUTPUT ;
    USE SIGNAL ;
    SHAPE ABUTMENT ;
    PORT
      LAYER M4 ;
      RECT 0.000 108.672 0.192 108.696 ;
    END
  END rec_out[532]
  PIN rec_out[533]
    DIRECTION OUTPUT ;
    USE SIGNAL ;
    SHAPE ABUTMENT ;
    PORT
      LAYER M4 ;
      RECT 0.000 108.768 0.192 108.792 ;
    END
  END rec_out[533]
  PIN rec_out[534]
    DIRECTION OUTPUT ;
    USE SIGNAL ;
    SHAPE ABUTMENT ;
    PORT
      LAYER M4 ;
      RECT 0.000 108.864 0.192 108.888 ;
    END
  END rec_out[534]
  PIN rec_out[535]
    DIRECTION OUTPUT ;
    USE SIGNAL ;
    SHAPE ABUTMENT ;
    PORT
      LAYER M4 ;
      RECT 0.000 108.960 0.192 108.984 ;
    END
  END rec_out[535]
  PIN rec_out[536]
    DIRECTION OUTPUT ;
    USE SIGNAL ;
    SHAPE ABUTMENT ;
    PORT
      LAYER M4 ;
      RECT 0.000 109.104 0.192 109.128 ;
    END
  END rec_out[536]
  PIN rec_out[537]
    DIRECTION OUTPUT ;
    USE SIGNAL ;
    SHAPE ABUTMENT ;
    PORT
      LAYER M4 ;
      RECT 0.000 109.200 0.192 109.224 ;
    END
  END rec_out[537]
  PIN rec_out[538]
    DIRECTION OUTPUT ;
    USE SIGNAL ;
    SHAPE ABUTMENT ;
    PORT
      LAYER M4 ;
      RECT 0.000 109.296 0.192 109.320 ;
    END
  END rec_out[538]
  PIN rec_out[539]
    DIRECTION OUTPUT ;
    USE SIGNAL ;
    SHAPE ABUTMENT ;
    PORT
      LAYER M4 ;
      RECT 0.000 109.392 0.192 109.416 ;
    END
  END rec_out[539]
  PIN rec_out[540]
    DIRECTION OUTPUT ;
    USE SIGNAL ;
    SHAPE ABUTMENT ;
    PORT
      LAYER M4 ;
      RECT 0.000 109.488 0.192 109.512 ;
    END
  END rec_out[540]
  PIN rec_out[541]
    DIRECTION OUTPUT ;
    USE SIGNAL ;
    SHAPE ABUTMENT ;
    PORT
      LAYER M4 ;
      RECT 0.000 109.584 0.192 109.608 ;
    END
  END rec_out[541]
  PIN rec_out[542]
    DIRECTION OUTPUT ;
    USE SIGNAL ;
    SHAPE ABUTMENT ;
    PORT
      LAYER M4 ;
      RECT 0.000 109.680 0.192 109.704 ;
    END
  END rec_out[542]
  PIN rec_out[543]
    DIRECTION OUTPUT ;
    USE SIGNAL ;
    SHAPE ABUTMENT ;
    PORT
      LAYER M4 ;
      RECT 0.000 109.776 0.192 109.800 ;
    END
  END rec_out[543]
  PIN rec_out[544]
    DIRECTION OUTPUT ;
    USE SIGNAL ;
    SHAPE ABUTMENT ;
    PORT
      LAYER M4 ;
      RECT 0.000 109.872 0.192 109.896 ;
    END
  END rec_out[544]
  PIN rec_out[545]
    DIRECTION OUTPUT ;
    USE SIGNAL ;
    SHAPE ABUTMENT ;
    PORT
      LAYER M4 ;
      RECT 0.000 109.968 0.192 109.992 ;
    END
  END rec_out[545]
  PIN rec_out[546]
    DIRECTION OUTPUT ;
    USE SIGNAL ;
    SHAPE ABUTMENT ;
    PORT
      LAYER M4 ;
      RECT 0.000 110.064 0.192 110.088 ;
    END
  END rec_out[546]
  PIN link_out[0]
    DIRECTION OUTPUT ;
    USE SIGNAL ;
    SHAPE ABUTMENT ;
    PORT
      LAYER M4 ;
      RECT 224.856 0.528 225.048 0.552 ;
    END
  END link_out[0]
  PIN link_out[1]
    DIRECTION OUTPUT ;
    USE SIGNAL ;
    SHAPE ABUTMENT ;
    PORT
      LAYER M4 ;
      RECT 224.856 0.624 225.048 0.648 ;
    END
  END link_out[1]
  PIN link_out[2]
    DIRECTION OUTPUT ;
    USE SIGNAL ;
    SHAPE ABUTMENT ;
    PORT
      LAYER M4 ;
      RECT 224.856 0.720 225.048 0.744 ;
    END
  END link_out[2]
  PIN link_out[3]
    DIRECTION OUTPUT ;
    USE SIGNAL ;
    SHAPE ABUTMENT ;
    PORT
      LAYER M4 ;
      RECT 224.856 0.816 225.048 0.840 ;
    END
  END link_out[3]
  PIN link_out[4]
    DIRECTION OUTPUT ;
    USE SIGNAL ;
    SHAPE ABUTMENT ;
    PORT
      LAYER M4 ;
      RECT 224.856 0.912 225.048 0.936 ;
    END
  END link_out[4]
  PIN link_out[5]
    DIRECTION OUTPUT ;
    USE SIGNAL ;
    SHAPE ABUTMENT ;
    PORT
      LAYER M4 ;
      RECT 224.856 1.056 225.048 1.080 ;
    END
  END link_out[5]
  PIN link_out[6]
    DIRECTION OUTPUT ;
    USE SIGNAL ;
    SHAPE ABUTMENT ;
    PORT
      LAYER M4 ;
      RECT 224.856 1.152 225.048 1.176 ;
    END
  END link_out[6]
  PIN link_out[7]
    DIRECTION OUTPUT ;
    USE SIGNAL ;
    SHAPE ABUTMENT ;
    PORT
      LAYER M4 ;
      RECT 224.856 1.248 225.048 1.272 ;
    END
  END link_out[7]
  PIN link_out[8]
    DIRECTION OUTPUT ;
    USE SIGNAL ;
    SHAPE ABUTMENT ;
    PORT
      LAYER M4 ;
      RECT 224.856 1.344 225.048 1.368 ;
    END
  END link_out[8]
  PIN link_out[9]
    DIRECTION OUTPUT ;
    USE SIGNAL ;
    SHAPE ABUTMENT ;
    PORT
      LAYER M4 ;
      RECT 224.856 1.488 225.048 1.512 ;
    END
  END link_out[9]
  PIN link_out[10]
    DIRECTION OUTPUT ;
    USE SIGNAL ;
    SHAPE ABUTMENT ;
    PORT
      LAYER M4 ;
      RECT 224.856 1.584 225.048 1.608 ;
    END
  END link_out[10]
  PIN link_out[11]
    DIRECTION OUTPUT ;
    USE SIGNAL ;
    SHAPE ABUTMENT ;
    PORT
      LAYER M4 ;
      RECT 224.856 1.680 225.048 1.704 ;
    END
  END link_out[11]
  PIN link_out[12]
    DIRECTION OUTPUT ;
    USE SIGNAL ;
    SHAPE ABUTMENT ;
    PORT
      LAYER M4 ;
      RECT 224.856 1.776 225.048 1.800 ;
    END
  END link_out[12]
  PIN link_out[13]
    DIRECTION OUTPUT ;
    USE SIGNAL ;
    SHAPE ABUTMENT ;
    PORT
      LAYER M4 ;
      RECT 224.856 1.920 225.048 1.944 ;
    END
  END link_out[13]
  PIN link_out[14]
    DIRECTION OUTPUT ;
    USE SIGNAL ;
    SHAPE ABUTMENT ;
    PORT
      LAYER M4 ;
      RECT 224.856 2.016 225.048 2.040 ;
    END
  END link_out[14]
  PIN link_out[15]
    DIRECTION OUTPUT ;
    USE SIGNAL ;
    SHAPE ABUTMENT ;
    PORT
      LAYER M4 ;
      RECT 224.856 2.112 225.048 2.136 ;
    END
  END link_out[15]
  PIN link_out[16]
    DIRECTION OUTPUT ;
    USE SIGNAL ;
    SHAPE ABUTMENT ;
    PORT
      LAYER M4 ;
      RECT 224.856 2.208 225.048 2.232 ;
    END
  END link_out[16]
  PIN link_out[17]
    DIRECTION OUTPUT ;
    USE SIGNAL ;
    SHAPE ABUTMENT ;
    PORT
      LAYER M4 ;
      RECT 224.856 2.304 225.048 2.328 ;
    END
  END link_out[17]
  PIN link_out[18]
    DIRECTION OUTPUT ;
    USE SIGNAL ;
    SHAPE ABUTMENT ;
    PORT
      LAYER M4 ;
      RECT 224.856 2.448 225.048 2.472 ;
    END
  END link_out[18]
  PIN link_out[19]
    DIRECTION OUTPUT ;
    USE SIGNAL ;
    SHAPE ABUTMENT ;
    PORT
      LAYER M4 ;
      RECT 224.856 2.544 225.048 2.568 ;
    END
  END link_out[19]
  PIN link_out[20]
    DIRECTION OUTPUT ;
    USE SIGNAL ;
    SHAPE ABUTMENT ;
    PORT
      LAYER M4 ;
      RECT 224.856 2.640 225.048 2.664 ;
    END
  END link_out[20]
  PIN link_out[21]
    DIRECTION OUTPUT ;
    USE SIGNAL ;
    SHAPE ABUTMENT ;
    PORT
      LAYER M4 ;
      RECT 224.856 2.736 225.048 2.760 ;
    END
  END link_out[21]
  PIN link_out[22]
    DIRECTION OUTPUT ;
    USE SIGNAL ;
    SHAPE ABUTMENT ;
    PORT
      LAYER M4 ;
      RECT 224.856 2.880 225.048 2.904 ;
    END
  END link_out[22]
  PIN link_out[23]
    DIRECTION OUTPUT ;
    USE SIGNAL ;
    SHAPE ABUTMENT ;
    PORT
      LAYER M4 ;
      RECT 224.856 2.976 225.048 3.000 ;
    END
  END link_out[23]
  PIN link_out[24]
    DIRECTION OUTPUT ;
    USE SIGNAL ;
    SHAPE ABUTMENT ;
    PORT
      LAYER M4 ;
      RECT 224.856 3.072 225.048 3.096 ;
    END
  END link_out[24]
  PIN link_out[25]
    DIRECTION OUTPUT ;
    USE SIGNAL ;
    SHAPE ABUTMENT ;
    PORT
      LAYER M4 ;
      RECT 224.856 3.168 225.048 3.192 ;
    END
  END link_out[25]
  PIN link_out[26]
    DIRECTION OUTPUT ;
    USE SIGNAL ;
    SHAPE ABUTMENT ;
    PORT
      LAYER M4 ;
      RECT 224.856 3.312 225.048 3.336 ;
    END
  END link_out[26]
  PIN link_out[27]
    DIRECTION OUTPUT ;
    USE SIGNAL ;
    SHAPE ABUTMENT ;
    PORT
      LAYER M4 ;
      RECT 224.856 3.408 225.048 3.432 ;
    END
  END link_out[27]
  PIN link_out[28]
    DIRECTION OUTPUT ;
    USE SIGNAL ;
    SHAPE ABUTMENT ;
    PORT
      LAYER M4 ;
      RECT 224.856 3.504 225.048 3.528 ;
    END
  END link_out[28]
  PIN link_out[29]
    DIRECTION OUTPUT ;
    USE SIGNAL ;
    SHAPE ABUTMENT ;
    PORT
      LAYER M4 ;
      RECT 224.856 3.600 225.048 3.624 ;
    END
  END link_out[29]
  PIN link_out[30]
    DIRECTION OUTPUT ;
    USE SIGNAL ;
    SHAPE ABUTMENT ;
    PORT
      LAYER M4 ;
      RECT 224.856 3.696 225.048 3.720 ;
    END
  END link_out[30]
  PIN link_out[31]
    DIRECTION OUTPUT ;
    USE SIGNAL ;
    SHAPE ABUTMENT ;
    PORT
      LAYER M4 ;
      RECT 224.856 3.840 225.048 3.864 ;
    END
  END link_out[31]
  PIN link_out[32]
    DIRECTION OUTPUT ;
    USE SIGNAL ;
    SHAPE ABUTMENT ;
    PORT
      LAYER M4 ;
      RECT 224.856 3.936 225.048 3.960 ;
    END
  END link_out[32]
  PIN link_out[33]
    DIRECTION OUTPUT ;
    USE SIGNAL ;
    SHAPE ABUTMENT ;
    PORT
      LAYER M4 ;
      RECT 224.856 4.032 225.048 4.056 ;
    END
  END link_out[33]
  PIN link_out[34]
    DIRECTION OUTPUT ;
    USE SIGNAL ;
    SHAPE ABUTMENT ;
    PORT
      LAYER M4 ;
      RECT 224.856 4.128 225.048 4.152 ;
    END
  END link_out[34]
  PIN link_out[35]
    DIRECTION OUTPUT ;
    USE SIGNAL ;
    SHAPE ABUTMENT ;
    PORT
      LAYER M4 ;
      RECT 224.856 4.272 225.048 4.296 ;
    END
  END link_out[35]
  PIN link_out[36]
    DIRECTION OUTPUT ;
    USE SIGNAL ;
    SHAPE ABUTMENT ;
    PORT
      LAYER M4 ;
      RECT 224.856 4.368 225.048 4.392 ;
    END
  END link_out[36]
  PIN link_out[37]
    DIRECTION OUTPUT ;
    USE SIGNAL ;
    SHAPE ABUTMENT ;
    PORT
      LAYER M4 ;
      RECT 224.856 4.464 225.048 4.488 ;
    END
  END link_out[37]
  PIN link_out[38]
    DIRECTION OUTPUT ;
    USE SIGNAL ;
    SHAPE ABUTMENT ;
    PORT
      LAYER M4 ;
      RECT 224.856 4.560 225.048 4.584 ;
    END
  END link_out[38]
  PIN link_out[39]
    DIRECTION OUTPUT ;
    USE SIGNAL ;
    SHAPE ABUTMENT ;
    PORT
      LAYER M4 ;
      RECT 224.856 4.704 225.048 4.728 ;
    END
  END link_out[39]
  PIN link_out[40]
    DIRECTION OUTPUT ;
    USE SIGNAL ;
    SHAPE ABUTMENT ;
    PORT
      LAYER M4 ;
      RECT 224.856 4.800 225.048 4.824 ;
    END
  END link_out[40]
  PIN link_out[41]
    DIRECTION OUTPUT ;
    USE SIGNAL ;
    SHAPE ABUTMENT ;
    PORT
      LAYER M4 ;
      RECT 224.856 4.896 225.048 4.920 ;
    END
  END link_out[41]
  PIN link_out[42]
    DIRECTION OUTPUT ;
    USE SIGNAL ;
    SHAPE ABUTMENT ;
    PORT
      LAYER M4 ;
      RECT 224.856 4.992 225.048 5.016 ;
    END
  END link_out[42]
  PIN link_out[43]
    DIRECTION OUTPUT ;
    USE SIGNAL ;
    SHAPE ABUTMENT ;
    PORT
      LAYER M4 ;
      RECT 224.856 5.088 225.048 5.112 ;
    END
  END link_out[43]
  PIN link_out[44]
    DIRECTION OUTPUT ;
    USE SIGNAL ;
    SHAPE ABUTMENT ;
    PORT
      LAYER M4 ;
      RECT 224.856 5.232 225.048 5.256 ;
    END
  END link_out[44]
  PIN link_out[45]
    DIRECTION OUTPUT ;
    USE SIGNAL ;
    SHAPE ABUTMENT ;
    PORT
      LAYER M4 ;
      RECT 224.856 5.328 225.048 5.352 ;
    END
  END link_out[45]
  PIN link_out[46]
    DIRECTION OUTPUT ;
    USE SIGNAL ;
    SHAPE ABUTMENT ;
    PORT
      LAYER M4 ;
      RECT 224.856 5.424 225.048 5.448 ;
    END
  END link_out[46]
  PIN link_out[47]
    DIRECTION OUTPUT ;
    USE SIGNAL ;
    SHAPE ABUTMENT ;
    PORT
      LAYER M4 ;
      RECT 224.856 5.520 225.048 5.544 ;
    END
  END link_out[47]
  PIN link_out[48]
    DIRECTION OUTPUT ;
    USE SIGNAL ;
    SHAPE ABUTMENT ;
    PORT
      LAYER M4 ;
      RECT 224.856 5.664 225.048 5.688 ;
    END
  END link_out[48]
  PIN link_out[49]
    DIRECTION OUTPUT ;
    USE SIGNAL ;
    SHAPE ABUTMENT ;
    PORT
      LAYER M4 ;
      RECT 224.856 5.760 225.048 5.784 ;
    END
  END link_out[49]
  PIN link_out[50]
    DIRECTION OUTPUT ;
    USE SIGNAL ;
    SHAPE ABUTMENT ;
    PORT
      LAYER M4 ;
      RECT 224.856 5.856 225.048 5.880 ;
    END
  END link_out[50]
  PIN link_out[51]
    DIRECTION OUTPUT ;
    USE SIGNAL ;
    SHAPE ABUTMENT ;
    PORT
      LAYER M4 ;
      RECT 224.856 5.952 225.048 5.976 ;
    END
  END link_out[51]
  PIN link_out[52]
    DIRECTION OUTPUT ;
    USE SIGNAL ;
    SHAPE ABUTMENT ;
    PORT
      LAYER M4 ;
      RECT 224.856 6.096 225.048 6.120 ;
    END
  END link_out[52]
  PIN link_out[53]
    DIRECTION OUTPUT ;
    USE SIGNAL ;
    SHAPE ABUTMENT ;
    PORT
      LAYER M4 ;
      RECT 224.856 6.192 225.048 6.216 ;
    END
  END link_out[53]
  PIN link_out[54]
    DIRECTION OUTPUT ;
    USE SIGNAL ;
    SHAPE ABUTMENT ;
    PORT
      LAYER M4 ;
      RECT 224.856 6.288 225.048 6.312 ;
    END
  END link_out[54]
  PIN link_out[55]
    DIRECTION OUTPUT ;
    USE SIGNAL ;
    SHAPE ABUTMENT ;
    PORT
      LAYER M4 ;
      RECT 224.856 6.384 225.048 6.408 ;
    END
  END link_out[55]
  PIN link_out[56]
    DIRECTION OUTPUT ;
    USE SIGNAL ;
    SHAPE ABUTMENT ;
    PORT
      LAYER M4 ;
      RECT 224.856 6.480 225.048 6.504 ;
    END
  END link_out[56]
  PIN link_out[57]
    DIRECTION OUTPUT ;
    USE SIGNAL ;
    SHAPE ABUTMENT ;
    PORT
      LAYER M4 ;
      RECT 224.856 6.624 225.048 6.648 ;
    END
  END link_out[57]
  PIN link_out[58]
    DIRECTION OUTPUT ;
    USE SIGNAL ;
    SHAPE ABUTMENT ;
    PORT
      LAYER M4 ;
      RECT 224.856 6.720 225.048 6.744 ;
    END
  END link_out[58]
  PIN link_out[59]
    DIRECTION OUTPUT ;
    USE SIGNAL ;
    SHAPE ABUTMENT ;
    PORT
      LAYER M4 ;
      RECT 224.856 6.816 225.048 6.840 ;
    END
  END link_out[59]
  PIN link_out[60]
    DIRECTION OUTPUT ;
    USE SIGNAL ;
    SHAPE ABUTMENT ;
    PORT
      LAYER M4 ;
      RECT 224.856 6.912 225.048 6.936 ;
    END
  END link_out[60]
  PIN link_out[61]
    DIRECTION OUTPUT ;
    USE SIGNAL ;
    SHAPE ABUTMENT ;
    PORT
      LAYER M4 ;
      RECT 224.856 7.056 225.048 7.080 ;
    END
  END link_out[61]
  PIN link_out[62]
    DIRECTION OUTPUT ;
    USE SIGNAL ;
    SHAPE ABUTMENT ;
    PORT
      LAYER M4 ;
      RECT 224.856 7.152 225.048 7.176 ;
    END
  END link_out[62]
  PIN link_out[63]
    DIRECTION OUTPUT ;
    USE SIGNAL ;
    SHAPE ABUTMENT ;
    PORT
      LAYER M4 ;
      RECT 224.856 7.248 225.048 7.272 ;
    END
  END link_out[63]
  PIN link_out[64]
    DIRECTION OUTPUT ;
    USE SIGNAL ;
    SHAPE ABUTMENT ;
    PORT
      LAYER M4 ;
      RECT 224.856 7.344 225.048 7.368 ;
    END
  END link_out[64]
  PIN link_out[65]
    DIRECTION OUTPUT ;
    USE SIGNAL ;
    SHAPE ABUTMENT ;
    PORT
      LAYER M4 ;
      RECT 224.856 7.488 225.048 7.512 ;
    END
  END link_out[65]
  PIN link_out[66]
    DIRECTION OUTPUT ;
    USE SIGNAL ;
    SHAPE ABUTMENT ;
    PORT
      LAYER M4 ;
      RECT 224.856 7.584 225.048 7.608 ;
    END
  END link_out[66]
  PIN link_out[67]
    DIRECTION OUTPUT ;
    USE SIGNAL ;
    SHAPE ABUTMENT ;
    PORT
      LAYER M4 ;
      RECT 224.856 7.680 225.048 7.704 ;
    END
  END link_out[67]
  PIN link_out[68]
    DIRECTION OUTPUT ;
    USE SIGNAL ;
    SHAPE ABUTMENT ;
    PORT
      LAYER M4 ;
      RECT 224.856 7.776 225.048 7.800 ;
    END
  END link_out[68]
  PIN link_out[69]
    DIRECTION OUTPUT ;
    USE SIGNAL ;
    SHAPE ABUTMENT ;
    PORT
      LAYER M4 ;
      RECT 224.856 7.872 225.048 7.896 ;
    END
  END link_out[69]
  PIN link_out[70]
    DIRECTION OUTPUT ;
    USE SIGNAL ;
    SHAPE ABUTMENT ;
    PORT
      LAYER M4 ;
      RECT 224.856 8.016 225.048 8.040 ;
    END
  END link_out[70]
  PIN link_out[71]
    DIRECTION OUTPUT ;
    USE SIGNAL ;
    SHAPE ABUTMENT ;
    PORT
      LAYER M4 ;
      RECT 224.856 8.112 225.048 8.136 ;
    END
  END link_out[71]
  PIN link_out[72]
    DIRECTION OUTPUT ;
    USE SIGNAL ;
    SHAPE ABUTMENT ;
    PORT
      LAYER M4 ;
      RECT 224.856 8.208 225.048 8.232 ;
    END
  END link_out[72]
  PIN link_out[73]
    DIRECTION OUTPUT ;
    USE SIGNAL ;
    SHAPE ABUTMENT ;
    PORT
      LAYER M4 ;
      RECT 224.856 8.304 225.048 8.328 ;
    END
  END link_out[73]
  PIN link_out[74]
    DIRECTION OUTPUT ;
    USE SIGNAL ;
    SHAPE ABUTMENT ;
    PORT
      LAYER M4 ;
      RECT 224.856 8.448 225.048 8.472 ;
    END
  END link_out[74]
  PIN link_out[75]
    DIRECTION OUTPUT ;
    USE SIGNAL ;
    SHAPE ABUTMENT ;
    PORT
      LAYER M4 ;
      RECT 224.856 8.544 225.048 8.568 ;
    END
  END link_out[75]
  PIN link_out[76]
    DIRECTION OUTPUT ;
    USE SIGNAL ;
    SHAPE ABUTMENT ;
    PORT
      LAYER M4 ;
      RECT 224.856 8.640 225.048 8.664 ;
    END
  END link_out[76]
  PIN link_out[77]
    DIRECTION OUTPUT ;
    USE SIGNAL ;
    SHAPE ABUTMENT ;
    PORT
      LAYER M4 ;
      RECT 224.856 8.736 225.048 8.760 ;
    END
  END link_out[77]
  PIN link_out[78]
    DIRECTION OUTPUT ;
    USE SIGNAL ;
    SHAPE ABUTMENT ;
    PORT
      LAYER M4 ;
      RECT 224.856 8.880 225.048 8.904 ;
    END
  END link_out[78]
  PIN link_out[79]
    DIRECTION OUTPUT ;
    USE SIGNAL ;
    SHAPE ABUTMENT ;
    PORT
      LAYER M4 ;
      RECT 224.856 8.976 225.048 9.000 ;
    END
  END link_out[79]
  PIN link_out[80]
    DIRECTION OUTPUT ;
    USE SIGNAL ;
    SHAPE ABUTMENT ;
    PORT
      LAYER M4 ;
      RECT 224.856 9.072 225.048 9.096 ;
    END
  END link_out[80]
  PIN link_out[81]
    DIRECTION OUTPUT ;
    USE SIGNAL ;
    SHAPE ABUTMENT ;
    PORT
      LAYER M4 ;
      RECT 224.856 9.168 225.048 9.192 ;
    END
  END link_out[81]
  PIN link_out[82]
    DIRECTION OUTPUT ;
    USE SIGNAL ;
    SHAPE ABUTMENT ;
    PORT
      LAYER M4 ;
      RECT 224.856 9.264 225.048 9.288 ;
    END
  END link_out[82]
  PIN link_out[83]
    DIRECTION OUTPUT ;
    USE SIGNAL ;
    SHAPE ABUTMENT ;
    PORT
      LAYER M4 ;
      RECT 224.856 9.408 225.048 9.432 ;
    END
  END link_out[83]
  PIN link_out[84]
    DIRECTION OUTPUT ;
    USE SIGNAL ;
    SHAPE ABUTMENT ;
    PORT
      LAYER M4 ;
      RECT 224.856 9.504 225.048 9.528 ;
    END
  END link_out[84]
  PIN link_out[85]
    DIRECTION OUTPUT ;
    USE SIGNAL ;
    SHAPE ABUTMENT ;
    PORT
      LAYER M4 ;
      RECT 224.856 9.600 225.048 9.624 ;
    END
  END link_out[85]
  PIN link_out[86]
    DIRECTION OUTPUT ;
    USE SIGNAL ;
    SHAPE ABUTMENT ;
    PORT
      LAYER M4 ;
      RECT 224.856 9.696 225.048 9.720 ;
    END
  END link_out[86]
  PIN link_out[87]
    DIRECTION OUTPUT ;
    USE SIGNAL ;
    SHAPE ABUTMENT ;
    PORT
      LAYER M4 ;
      RECT 224.856 9.840 225.048 9.864 ;
    END
  END link_out[87]
  PIN link_out[88]
    DIRECTION OUTPUT ;
    USE SIGNAL ;
    SHAPE ABUTMENT ;
    PORT
      LAYER M4 ;
      RECT 224.856 9.936 225.048 9.960 ;
    END
  END link_out[88]
  PIN link_out[89]
    DIRECTION OUTPUT ;
    USE SIGNAL ;
    SHAPE ABUTMENT ;
    PORT
      LAYER M4 ;
      RECT 224.856 10.032 225.048 10.056 ;
    END
  END link_out[89]
  PIN link_out[90]
    DIRECTION OUTPUT ;
    USE SIGNAL ;
    SHAPE ABUTMENT ;
    PORT
      LAYER M4 ;
      RECT 224.856 10.128 225.048 10.152 ;
    END
  END link_out[90]
  PIN link_out[91]
    DIRECTION OUTPUT ;
    USE SIGNAL ;
    SHAPE ABUTMENT ;
    PORT
      LAYER M4 ;
      RECT 224.856 10.272 225.048 10.296 ;
    END
  END link_out[91]
  PIN link_out[92]
    DIRECTION OUTPUT ;
    USE SIGNAL ;
    SHAPE ABUTMENT ;
    PORT
      LAYER M4 ;
      RECT 224.856 10.368 225.048 10.392 ;
    END
  END link_out[92]
  PIN link_out[93]
    DIRECTION OUTPUT ;
    USE SIGNAL ;
    SHAPE ABUTMENT ;
    PORT
      LAYER M4 ;
      RECT 224.856 10.464 225.048 10.488 ;
    END
  END link_out[93]
  PIN link_out[94]
    DIRECTION OUTPUT ;
    USE SIGNAL ;
    SHAPE ABUTMENT ;
    PORT
      LAYER M4 ;
      RECT 224.856 10.560 225.048 10.584 ;
    END
  END link_out[94]
  PIN link_out[95]
    DIRECTION OUTPUT ;
    USE SIGNAL ;
    SHAPE ABUTMENT ;
    PORT
      LAYER M4 ;
      RECT 224.856 10.656 225.048 10.680 ;
    END
  END link_out[95]
  PIN link_out[96]
    DIRECTION OUTPUT ;
    USE SIGNAL ;
    SHAPE ABUTMENT ;
    PORT
      LAYER M4 ;
      RECT 224.856 10.800 225.048 10.824 ;
    END
  END link_out[96]
  PIN link_out[97]
    DIRECTION OUTPUT ;
    USE SIGNAL ;
    SHAPE ABUTMENT ;
    PORT
      LAYER M4 ;
      RECT 224.856 10.896 225.048 10.920 ;
    END
  END link_out[97]
  PIN link_out[98]
    DIRECTION OUTPUT ;
    USE SIGNAL ;
    SHAPE ABUTMENT ;
    PORT
      LAYER M4 ;
      RECT 224.856 10.992 225.048 11.016 ;
    END
  END link_out[98]
  PIN link_out[99]
    DIRECTION OUTPUT ;
    USE SIGNAL ;
    SHAPE ABUTMENT ;
    PORT
      LAYER M4 ;
      RECT 224.856 11.088 225.048 11.112 ;
    END
  END link_out[99]
  PIN link_out[100]
    DIRECTION OUTPUT ;
    USE SIGNAL ;
    SHAPE ABUTMENT ;
    PORT
      LAYER M4 ;
      RECT 224.856 11.232 225.048 11.256 ;
    END
  END link_out[100]
  PIN link_out[101]
    DIRECTION OUTPUT ;
    USE SIGNAL ;
    SHAPE ABUTMENT ;
    PORT
      LAYER M4 ;
      RECT 224.856 11.328 225.048 11.352 ;
    END
  END link_out[101]
  PIN link_out[102]
    DIRECTION OUTPUT ;
    USE SIGNAL ;
    SHAPE ABUTMENT ;
    PORT
      LAYER M4 ;
      RECT 224.856 11.424 225.048 11.448 ;
    END
  END link_out[102]
  PIN link_out[103]
    DIRECTION OUTPUT ;
    USE SIGNAL ;
    SHAPE ABUTMENT ;
    PORT
      LAYER M4 ;
      RECT 224.856 11.520 225.048 11.544 ;
    END
  END link_out[103]
  PIN link_out[104]
    DIRECTION OUTPUT ;
    USE SIGNAL ;
    SHAPE ABUTMENT ;
    PORT
      LAYER M4 ;
      RECT 224.856 11.664 225.048 11.688 ;
    END
  END link_out[104]
  PIN link_out[105]
    DIRECTION OUTPUT ;
    USE SIGNAL ;
    SHAPE ABUTMENT ;
    PORT
      LAYER M4 ;
      RECT 224.856 11.760 225.048 11.784 ;
    END
  END link_out[105]
  PIN link_out[106]
    DIRECTION OUTPUT ;
    USE SIGNAL ;
    SHAPE ABUTMENT ;
    PORT
      LAYER M4 ;
      RECT 224.856 11.856 225.048 11.880 ;
    END
  END link_out[106]
  PIN link_out[107]
    DIRECTION OUTPUT ;
    USE SIGNAL ;
    SHAPE ABUTMENT ;
    PORT
      LAYER M4 ;
      RECT 224.856 11.952 225.048 11.976 ;
    END
  END link_out[107]
  PIN link_out[108]
    DIRECTION OUTPUT ;
    USE SIGNAL ;
    SHAPE ABUTMENT ;
    PORT
      LAYER M4 ;
      RECT 224.856 12.048 225.048 12.072 ;
    END
  END link_out[108]
  PIN link_out[109]
    DIRECTION OUTPUT ;
    USE SIGNAL ;
    SHAPE ABUTMENT ;
    PORT
      LAYER M4 ;
      RECT 224.856 12.192 225.048 12.216 ;
    END
  END link_out[109]
  PIN link_out[110]
    DIRECTION OUTPUT ;
    USE SIGNAL ;
    SHAPE ABUTMENT ;
    PORT
      LAYER M4 ;
      RECT 224.856 12.288 225.048 12.312 ;
    END
  END link_out[110]
  PIN link_out[111]
    DIRECTION OUTPUT ;
    USE SIGNAL ;
    SHAPE ABUTMENT ;
    PORT
      LAYER M4 ;
      RECT 224.856 12.384 225.048 12.408 ;
    END
  END link_out[111]
  PIN link_out[112]
    DIRECTION OUTPUT ;
    USE SIGNAL ;
    SHAPE ABUTMENT ;
    PORT
      LAYER M4 ;
      RECT 224.856 12.480 225.048 12.504 ;
    END
  END link_out[112]
  PIN link_out[113]
    DIRECTION OUTPUT ;
    USE SIGNAL ;
    SHAPE ABUTMENT ;
    PORT
      LAYER M4 ;
      RECT 224.856 12.624 225.048 12.648 ;
    END
  END link_out[113]
  PIN link_out[114]
    DIRECTION OUTPUT ;
    USE SIGNAL ;
    SHAPE ABUTMENT ;
    PORT
      LAYER M4 ;
      RECT 224.856 12.720 225.048 12.744 ;
    END
  END link_out[114]
  PIN link_out[115]
    DIRECTION OUTPUT ;
    USE SIGNAL ;
    SHAPE ABUTMENT ;
    PORT
      LAYER M4 ;
      RECT 224.856 12.816 225.048 12.840 ;
    END
  END link_out[115]
  PIN link_out[116]
    DIRECTION OUTPUT ;
    USE SIGNAL ;
    SHAPE ABUTMENT ;
    PORT
      LAYER M4 ;
      RECT 224.856 12.912 225.048 12.936 ;
    END
  END link_out[116]
  PIN link_out[117]
    DIRECTION OUTPUT ;
    USE SIGNAL ;
    SHAPE ABUTMENT ;
    PORT
      LAYER M4 ;
      RECT 224.856 13.056 225.048 13.080 ;
    END
  END link_out[117]
  PIN link_out[118]
    DIRECTION OUTPUT ;
    USE SIGNAL ;
    SHAPE ABUTMENT ;
    PORT
      LAYER M4 ;
      RECT 224.856 13.152 225.048 13.176 ;
    END
  END link_out[118]
  PIN link_out[119]
    DIRECTION OUTPUT ;
    USE SIGNAL ;
    SHAPE ABUTMENT ;
    PORT
      LAYER M4 ;
      RECT 224.856 13.248 225.048 13.272 ;
    END
  END link_out[119]
  PIN link_out[120]
    DIRECTION OUTPUT ;
    USE SIGNAL ;
    SHAPE ABUTMENT ;
    PORT
      LAYER M4 ;
      RECT 224.856 13.344 225.048 13.368 ;
    END
  END link_out[120]
  PIN link_out[121]
    DIRECTION OUTPUT ;
    USE SIGNAL ;
    SHAPE ABUTMENT ;
    PORT
      LAYER M4 ;
      RECT 224.856 13.488 225.048 13.512 ;
    END
  END link_out[121]
  PIN link_out[122]
    DIRECTION OUTPUT ;
    USE SIGNAL ;
    SHAPE ABUTMENT ;
    PORT
      LAYER M4 ;
      RECT 224.856 13.584 225.048 13.608 ;
    END
  END link_out[122]
  PIN link_out[123]
    DIRECTION OUTPUT ;
    USE SIGNAL ;
    SHAPE ABUTMENT ;
    PORT
      LAYER M4 ;
      RECT 224.856 13.680 225.048 13.704 ;
    END
  END link_out[123]
  PIN link_out[124]
    DIRECTION OUTPUT ;
    USE SIGNAL ;
    SHAPE ABUTMENT ;
    PORT
      LAYER M4 ;
      RECT 224.856 13.776 225.048 13.800 ;
    END
  END link_out[124]
  PIN link_out[125]
    DIRECTION OUTPUT ;
    USE SIGNAL ;
    SHAPE ABUTMENT ;
    PORT
      LAYER M4 ;
      RECT 224.856 13.872 225.048 13.896 ;
    END
  END link_out[125]
  PIN link_out[126]
    DIRECTION OUTPUT ;
    USE SIGNAL ;
    SHAPE ABUTMENT ;
    PORT
      LAYER M4 ;
      RECT 224.856 14.016 225.048 14.040 ;
    END
  END link_out[126]
  PIN link_out[127]
    DIRECTION OUTPUT ;
    USE SIGNAL ;
    SHAPE ABUTMENT ;
    PORT
      LAYER M4 ;
      RECT 224.856 14.112 225.048 14.136 ;
    END
  END link_out[127]
  PIN link_out[128]
    DIRECTION OUTPUT ;
    USE SIGNAL ;
    SHAPE ABUTMENT ;
    PORT
      LAYER M4 ;
      RECT 224.856 14.208 225.048 14.232 ;
    END
  END link_out[128]
  PIN link_out[129]
    DIRECTION OUTPUT ;
    USE SIGNAL ;
    SHAPE ABUTMENT ;
    PORT
      LAYER M4 ;
      RECT 224.856 14.304 225.048 14.328 ;
    END
  END link_out[129]
  PIN link_out[130]
    DIRECTION OUTPUT ;
    USE SIGNAL ;
    SHAPE ABUTMENT ;
    PORT
      LAYER M4 ;
      RECT 224.856 14.448 225.048 14.472 ;
    END
  END link_out[130]
  PIN link_out[131]
    DIRECTION OUTPUT ;
    USE SIGNAL ;
    SHAPE ABUTMENT ;
    PORT
      LAYER M4 ;
      RECT 224.856 14.544 225.048 14.568 ;
    END
  END link_out[131]
  PIN link_out[132]
    DIRECTION OUTPUT ;
    USE SIGNAL ;
    SHAPE ABUTMENT ;
    PORT
      LAYER M4 ;
      RECT 224.856 14.640 225.048 14.664 ;
    END
  END link_out[132]
  PIN link_out[133]
    DIRECTION OUTPUT ;
    USE SIGNAL ;
    SHAPE ABUTMENT ;
    PORT
      LAYER M4 ;
      RECT 224.856 14.736 225.048 14.760 ;
    END
  END link_out[133]
  PIN link_out[134]
    DIRECTION OUTPUT ;
    USE SIGNAL ;
    SHAPE ABUTMENT ;
    PORT
      LAYER M4 ;
      RECT 224.856 14.880 225.048 14.904 ;
    END
  END link_out[134]
  PIN link_out[135]
    DIRECTION OUTPUT ;
    USE SIGNAL ;
    SHAPE ABUTMENT ;
    PORT
      LAYER M4 ;
      RECT 224.856 14.976 225.048 15.000 ;
    END
  END link_out[135]
  PIN link_out[136]
    DIRECTION OUTPUT ;
    USE SIGNAL ;
    SHAPE ABUTMENT ;
    PORT
      LAYER M4 ;
      RECT 224.856 15.072 225.048 15.096 ;
    END
  END link_out[136]
  PIN link_out[137]
    DIRECTION OUTPUT ;
    USE SIGNAL ;
    SHAPE ABUTMENT ;
    PORT
      LAYER M4 ;
      RECT 224.856 15.168 225.048 15.192 ;
    END
  END link_out[137]
  PIN link_out[138]
    DIRECTION OUTPUT ;
    USE SIGNAL ;
    SHAPE ABUTMENT ;
    PORT
      LAYER M4 ;
      RECT 224.856 15.264 225.048 15.288 ;
    END
  END link_out[138]
  PIN link_out[139]
    DIRECTION OUTPUT ;
    USE SIGNAL ;
    SHAPE ABUTMENT ;
    PORT
      LAYER M4 ;
      RECT 224.856 15.408 225.048 15.432 ;
    END
  END link_out[139]
  PIN link_out[140]
    DIRECTION OUTPUT ;
    USE SIGNAL ;
    SHAPE ABUTMENT ;
    PORT
      LAYER M4 ;
      RECT 224.856 15.504 225.048 15.528 ;
    END
  END link_out[140]
  PIN link_out[141]
    DIRECTION OUTPUT ;
    USE SIGNAL ;
    SHAPE ABUTMENT ;
    PORT
      LAYER M4 ;
      RECT 224.856 15.600 225.048 15.624 ;
    END
  END link_out[141]
  PIN link_out[142]
    DIRECTION OUTPUT ;
    USE SIGNAL ;
    SHAPE ABUTMENT ;
    PORT
      LAYER M4 ;
      RECT 224.856 15.696 225.048 15.720 ;
    END
  END link_out[142]
  PIN link_out[143]
    DIRECTION OUTPUT ;
    USE SIGNAL ;
    SHAPE ABUTMENT ;
    PORT
      LAYER M4 ;
      RECT 224.856 15.840 225.048 15.864 ;
    END
  END link_out[143]
  PIN link_out[144]
    DIRECTION OUTPUT ;
    USE SIGNAL ;
    SHAPE ABUTMENT ;
    PORT
      LAYER M4 ;
      RECT 224.856 15.936 225.048 15.960 ;
    END
  END link_out[144]
  PIN link_out[145]
    DIRECTION OUTPUT ;
    USE SIGNAL ;
    SHAPE ABUTMENT ;
    PORT
      LAYER M4 ;
      RECT 224.856 16.032 225.048 16.056 ;
    END
  END link_out[145]
  PIN link_out[146]
    DIRECTION OUTPUT ;
    USE SIGNAL ;
    SHAPE ABUTMENT ;
    PORT
      LAYER M4 ;
      RECT 224.856 16.128 225.048 16.152 ;
    END
  END link_out[146]
  PIN link_out[147]
    DIRECTION OUTPUT ;
    USE SIGNAL ;
    SHAPE ABUTMENT ;
    PORT
      LAYER M4 ;
      RECT 224.856 16.272 225.048 16.296 ;
    END
  END link_out[147]
  PIN link_out[148]
    DIRECTION OUTPUT ;
    USE SIGNAL ;
    SHAPE ABUTMENT ;
    PORT
      LAYER M4 ;
      RECT 224.856 16.368 225.048 16.392 ;
    END
  END link_out[148]
  PIN link_out[149]
    DIRECTION OUTPUT ;
    USE SIGNAL ;
    SHAPE ABUTMENT ;
    PORT
      LAYER M4 ;
      RECT 224.856 16.464 225.048 16.488 ;
    END
  END link_out[149]
  PIN link_out[150]
    DIRECTION OUTPUT ;
    USE SIGNAL ;
    SHAPE ABUTMENT ;
    PORT
      LAYER M4 ;
      RECT 224.856 16.560 225.048 16.584 ;
    END
  END link_out[150]
  PIN link_out[151]
    DIRECTION OUTPUT ;
    USE SIGNAL ;
    SHAPE ABUTMENT ;
    PORT
      LAYER M4 ;
      RECT 224.856 16.656 225.048 16.680 ;
    END
  END link_out[151]
  PIN link_out[152]
    DIRECTION OUTPUT ;
    USE SIGNAL ;
    SHAPE ABUTMENT ;
    PORT
      LAYER M4 ;
      RECT 224.856 16.800 225.048 16.824 ;
    END
  END link_out[152]
  PIN link_out[153]
    DIRECTION OUTPUT ;
    USE SIGNAL ;
    SHAPE ABUTMENT ;
    PORT
      LAYER M4 ;
      RECT 224.856 16.896 225.048 16.920 ;
    END
  END link_out[153]
  PIN link_out[154]
    DIRECTION OUTPUT ;
    USE SIGNAL ;
    SHAPE ABUTMENT ;
    PORT
      LAYER M4 ;
      RECT 224.856 16.992 225.048 17.016 ;
    END
  END link_out[154]
  PIN link_out[155]
    DIRECTION OUTPUT ;
    USE SIGNAL ;
    SHAPE ABUTMENT ;
    PORT
      LAYER M4 ;
      RECT 224.856 17.088 225.048 17.112 ;
    END
  END link_out[155]
  PIN link_out[156]
    DIRECTION OUTPUT ;
    USE SIGNAL ;
    SHAPE ABUTMENT ;
    PORT
      LAYER M4 ;
      RECT 224.856 17.232 225.048 17.256 ;
    END
  END link_out[156]
  PIN link_out[157]
    DIRECTION OUTPUT ;
    USE SIGNAL ;
    SHAPE ABUTMENT ;
    PORT
      LAYER M4 ;
      RECT 224.856 17.328 225.048 17.352 ;
    END
  END link_out[157]
  PIN link_out[158]
    DIRECTION OUTPUT ;
    USE SIGNAL ;
    SHAPE ABUTMENT ;
    PORT
      LAYER M4 ;
      RECT 224.856 17.424 225.048 17.448 ;
    END
  END link_out[158]
  PIN link_out[159]
    DIRECTION OUTPUT ;
    USE SIGNAL ;
    SHAPE ABUTMENT ;
    PORT
      LAYER M4 ;
      RECT 224.856 17.520 225.048 17.544 ;
    END
  END link_out[159]
  PIN link_out[160]
    DIRECTION OUTPUT ;
    USE SIGNAL ;
    SHAPE ABUTMENT ;
    PORT
      LAYER M4 ;
      RECT 224.856 17.664 225.048 17.688 ;
    END
  END link_out[160]
  PIN link_out[161]
    DIRECTION OUTPUT ;
    USE SIGNAL ;
    SHAPE ABUTMENT ;
    PORT
      LAYER M4 ;
      RECT 224.856 17.760 225.048 17.784 ;
    END
  END link_out[161]
  PIN link_out[162]
    DIRECTION OUTPUT ;
    USE SIGNAL ;
    SHAPE ABUTMENT ;
    PORT
      LAYER M4 ;
      RECT 224.856 17.856 225.048 17.880 ;
    END
  END link_out[162]
  PIN link_out[163]
    DIRECTION OUTPUT ;
    USE SIGNAL ;
    SHAPE ABUTMENT ;
    PORT
      LAYER M4 ;
      RECT 224.856 17.952 225.048 17.976 ;
    END
  END link_out[163]
  PIN link_out[164]
    DIRECTION OUTPUT ;
    USE SIGNAL ;
    SHAPE ABUTMENT ;
    PORT
      LAYER M4 ;
      RECT 224.856 18.048 225.048 18.072 ;
    END
  END link_out[164]
  PIN link_out[165]
    DIRECTION OUTPUT ;
    USE SIGNAL ;
    SHAPE ABUTMENT ;
    PORT
      LAYER M4 ;
      RECT 224.856 18.192 225.048 18.216 ;
    END
  END link_out[165]
  PIN link_out[166]
    DIRECTION OUTPUT ;
    USE SIGNAL ;
    SHAPE ABUTMENT ;
    PORT
      LAYER M4 ;
      RECT 224.856 18.288 225.048 18.312 ;
    END
  END link_out[166]
  PIN link_out[167]
    DIRECTION OUTPUT ;
    USE SIGNAL ;
    SHAPE ABUTMENT ;
    PORT
      LAYER M4 ;
      RECT 224.856 18.384 225.048 18.408 ;
    END
  END link_out[167]
  PIN link_out[168]
    DIRECTION OUTPUT ;
    USE SIGNAL ;
    SHAPE ABUTMENT ;
    PORT
      LAYER M4 ;
      RECT 224.856 18.480 225.048 18.504 ;
    END
  END link_out[168]
  PIN link_out[169]
    DIRECTION OUTPUT ;
    USE SIGNAL ;
    SHAPE ABUTMENT ;
    PORT
      LAYER M4 ;
      RECT 224.856 18.624 225.048 18.648 ;
    END
  END link_out[169]
  PIN link_out[170]
    DIRECTION OUTPUT ;
    USE SIGNAL ;
    SHAPE ABUTMENT ;
    PORT
      LAYER M4 ;
      RECT 224.856 18.720 225.048 18.744 ;
    END
  END link_out[170]
  PIN link_out[171]
    DIRECTION OUTPUT ;
    USE SIGNAL ;
    SHAPE ABUTMENT ;
    PORT
      LAYER M4 ;
      RECT 224.856 18.816 225.048 18.840 ;
    END
  END link_out[171]
  PIN link_out[172]
    DIRECTION OUTPUT ;
    USE SIGNAL ;
    SHAPE ABUTMENT ;
    PORT
      LAYER M4 ;
      RECT 224.856 18.912 225.048 18.936 ;
    END
  END link_out[172]
  PIN link_out[173]
    DIRECTION OUTPUT ;
    USE SIGNAL ;
    SHAPE ABUTMENT ;
    PORT
      LAYER M4 ;
      RECT 224.856 19.056 225.048 19.080 ;
    END
  END link_out[173]
  PIN link_out[174]
    DIRECTION OUTPUT ;
    USE SIGNAL ;
    SHAPE ABUTMENT ;
    PORT
      LAYER M4 ;
      RECT 224.856 19.152 225.048 19.176 ;
    END
  END link_out[174]
  PIN link_out[175]
    DIRECTION OUTPUT ;
    USE SIGNAL ;
    SHAPE ABUTMENT ;
    PORT
      LAYER M4 ;
      RECT 224.856 19.248 225.048 19.272 ;
    END
  END link_out[175]
  PIN link_out[176]
    DIRECTION OUTPUT ;
    USE SIGNAL ;
    SHAPE ABUTMENT ;
    PORT
      LAYER M4 ;
      RECT 224.856 19.344 225.048 19.368 ;
    END
  END link_out[176]
  PIN link_out[177]
    DIRECTION OUTPUT ;
    USE SIGNAL ;
    SHAPE ABUTMENT ;
    PORT
      LAYER M4 ;
      RECT 224.856 19.440 225.048 19.464 ;
    END
  END link_out[177]
  PIN link_out[178]
    DIRECTION OUTPUT ;
    USE SIGNAL ;
    SHAPE ABUTMENT ;
    PORT
      LAYER M4 ;
      RECT 224.856 19.584 225.048 19.608 ;
    END
  END link_out[178]
  PIN link_out[179]
    DIRECTION OUTPUT ;
    USE SIGNAL ;
    SHAPE ABUTMENT ;
    PORT
      LAYER M4 ;
      RECT 224.856 19.680 225.048 19.704 ;
    END
  END link_out[179]
  PIN link_out[180]
    DIRECTION OUTPUT ;
    USE SIGNAL ;
    SHAPE ABUTMENT ;
    PORT
      LAYER M4 ;
      RECT 224.856 19.776 225.048 19.800 ;
    END
  END link_out[180]
  PIN link_out[181]
    DIRECTION OUTPUT ;
    USE SIGNAL ;
    SHAPE ABUTMENT ;
    PORT
      LAYER M4 ;
      RECT 224.856 19.872 225.048 19.896 ;
    END
  END link_out[181]
  PIN link_out[182]
    DIRECTION OUTPUT ;
    USE SIGNAL ;
    SHAPE ABUTMENT ;
    PORT
      LAYER M4 ;
      RECT 224.856 20.016 225.048 20.040 ;
    END
  END link_out[182]
  PIN link_out[183]
    DIRECTION OUTPUT ;
    USE SIGNAL ;
    SHAPE ABUTMENT ;
    PORT
      LAYER M4 ;
      RECT 224.856 20.112 225.048 20.136 ;
    END
  END link_out[183]
  PIN link_out[184]
    DIRECTION OUTPUT ;
    USE SIGNAL ;
    SHAPE ABUTMENT ;
    PORT
      LAYER M4 ;
      RECT 224.856 20.208 225.048 20.232 ;
    END
  END link_out[184]
  PIN link_out[185]
    DIRECTION OUTPUT ;
    USE SIGNAL ;
    SHAPE ABUTMENT ;
    PORT
      LAYER M4 ;
      RECT 224.856 20.304 225.048 20.328 ;
    END
  END link_out[185]
  PIN link_out[186]
    DIRECTION OUTPUT ;
    USE SIGNAL ;
    SHAPE ABUTMENT ;
    PORT
      LAYER M4 ;
      RECT 224.856 20.448 225.048 20.472 ;
    END
  END link_out[186]
  PIN link_out[187]
    DIRECTION OUTPUT ;
    USE SIGNAL ;
    SHAPE ABUTMENT ;
    PORT
      LAYER M4 ;
      RECT 224.856 20.544 225.048 20.568 ;
    END
  END link_out[187]
  PIN link_out[188]
    DIRECTION OUTPUT ;
    USE SIGNAL ;
    SHAPE ABUTMENT ;
    PORT
      LAYER M4 ;
      RECT 224.856 20.640 225.048 20.664 ;
    END
  END link_out[188]
  PIN link_out[189]
    DIRECTION OUTPUT ;
    USE SIGNAL ;
    SHAPE ABUTMENT ;
    PORT
      LAYER M4 ;
      RECT 224.856 20.736 225.048 20.760 ;
    END
  END link_out[189]
  PIN link_out[190]
    DIRECTION OUTPUT ;
    USE SIGNAL ;
    SHAPE ABUTMENT ;
    PORT
      LAYER M4 ;
      RECT 224.856 20.832 225.048 20.856 ;
    END
  END link_out[190]
  PIN link_out[191]
    DIRECTION OUTPUT ;
    USE SIGNAL ;
    SHAPE ABUTMENT ;
    PORT
      LAYER M4 ;
      RECT 224.856 20.976 225.048 21.000 ;
    END
  END link_out[191]
  PIN link_out[192]
    DIRECTION OUTPUT ;
    USE SIGNAL ;
    SHAPE ABUTMENT ;
    PORT
      LAYER M4 ;
      RECT 224.856 21.072 225.048 21.096 ;
    END
  END link_out[192]
  PIN link_out[193]
    DIRECTION OUTPUT ;
    USE SIGNAL ;
    SHAPE ABUTMENT ;
    PORT
      LAYER M4 ;
      RECT 224.856 21.168 225.048 21.192 ;
    END
  END link_out[193]
  PIN link_out[194]
    DIRECTION OUTPUT ;
    USE SIGNAL ;
    SHAPE ABUTMENT ;
    PORT
      LAYER M4 ;
      RECT 224.856 21.264 225.048 21.288 ;
    END
  END link_out[194]
  PIN link_out[195]
    DIRECTION OUTPUT ;
    USE SIGNAL ;
    SHAPE ABUTMENT ;
    PORT
      LAYER M4 ;
      RECT 224.856 21.408 225.048 21.432 ;
    END
  END link_out[195]
  PIN link_out[196]
    DIRECTION OUTPUT ;
    USE SIGNAL ;
    SHAPE ABUTMENT ;
    PORT
      LAYER M4 ;
      RECT 224.856 21.504 225.048 21.528 ;
    END
  END link_out[196]
  PIN link_out[197]
    DIRECTION OUTPUT ;
    USE SIGNAL ;
    SHAPE ABUTMENT ;
    PORT
      LAYER M4 ;
      RECT 224.856 21.600 225.048 21.624 ;
    END
  END link_out[197]
  PIN link_out[198]
    DIRECTION OUTPUT ;
    USE SIGNAL ;
    SHAPE ABUTMENT ;
    PORT
      LAYER M4 ;
      RECT 224.856 21.696 225.048 21.720 ;
    END
  END link_out[198]
  PIN link_out[199]
    DIRECTION OUTPUT ;
    USE SIGNAL ;
    SHAPE ABUTMENT ;
    PORT
      LAYER M4 ;
      RECT 224.856 21.840 225.048 21.864 ;
    END
  END link_out[199]
  PIN link_out[200]
    DIRECTION OUTPUT ;
    USE SIGNAL ;
    SHAPE ABUTMENT ;
    PORT
      LAYER M4 ;
      RECT 224.856 21.936 225.048 21.960 ;
    END
  END link_out[200]
  PIN link_out[201]
    DIRECTION OUTPUT ;
    USE SIGNAL ;
    SHAPE ABUTMENT ;
    PORT
      LAYER M4 ;
      RECT 224.856 22.032 225.048 22.056 ;
    END
  END link_out[201]
  PIN link_out[202]
    DIRECTION OUTPUT ;
    USE SIGNAL ;
    SHAPE ABUTMENT ;
    PORT
      LAYER M4 ;
      RECT 224.856 22.128 225.048 22.152 ;
    END
  END link_out[202]
  PIN link_out[203]
    DIRECTION OUTPUT ;
    USE SIGNAL ;
    SHAPE ABUTMENT ;
    PORT
      LAYER M4 ;
      RECT 224.856 22.224 225.048 22.248 ;
    END
  END link_out[203]
  PIN link_out[204]
    DIRECTION OUTPUT ;
    USE SIGNAL ;
    SHAPE ABUTMENT ;
    PORT
      LAYER M4 ;
      RECT 224.856 22.368 225.048 22.392 ;
    END
  END link_out[204]
  PIN link_out[205]
    DIRECTION OUTPUT ;
    USE SIGNAL ;
    SHAPE ABUTMENT ;
    PORT
      LAYER M4 ;
      RECT 224.856 22.464 225.048 22.488 ;
    END
  END link_out[205]
  PIN link_out[206]
    DIRECTION OUTPUT ;
    USE SIGNAL ;
    SHAPE ABUTMENT ;
    PORT
      LAYER M4 ;
      RECT 224.856 22.560 225.048 22.584 ;
    END
  END link_out[206]
  PIN link_out[207]
    DIRECTION OUTPUT ;
    USE SIGNAL ;
    SHAPE ABUTMENT ;
    PORT
      LAYER M4 ;
      RECT 224.856 22.656 225.048 22.680 ;
    END
  END link_out[207]
  PIN link_out[208]
    DIRECTION OUTPUT ;
    USE SIGNAL ;
    SHAPE ABUTMENT ;
    PORT
      LAYER M4 ;
      RECT 224.856 22.800 225.048 22.824 ;
    END
  END link_out[208]
  PIN link_out[209]
    DIRECTION OUTPUT ;
    USE SIGNAL ;
    SHAPE ABUTMENT ;
    PORT
      LAYER M4 ;
      RECT 224.856 22.896 225.048 22.920 ;
    END
  END link_out[209]
  PIN link_out[210]
    DIRECTION OUTPUT ;
    USE SIGNAL ;
    SHAPE ABUTMENT ;
    PORT
      LAYER M4 ;
      RECT 224.856 22.992 225.048 23.016 ;
    END
  END link_out[210]
  PIN link_out[211]
    DIRECTION OUTPUT ;
    USE SIGNAL ;
    SHAPE ABUTMENT ;
    PORT
      LAYER M4 ;
      RECT 224.856 23.088 225.048 23.112 ;
    END
  END link_out[211]
  PIN link_out[212]
    DIRECTION OUTPUT ;
    USE SIGNAL ;
    SHAPE ABUTMENT ;
    PORT
      LAYER M4 ;
      RECT 224.856 23.232 225.048 23.256 ;
    END
  END link_out[212]
  PIN link_out[213]
    DIRECTION OUTPUT ;
    USE SIGNAL ;
    SHAPE ABUTMENT ;
    PORT
      LAYER M4 ;
      RECT 224.856 23.328 225.048 23.352 ;
    END
  END link_out[213]
  PIN link_out[214]
    DIRECTION OUTPUT ;
    USE SIGNAL ;
    SHAPE ABUTMENT ;
    PORT
      LAYER M4 ;
      RECT 224.856 23.424 225.048 23.448 ;
    END
  END link_out[214]
  PIN link_out[215]
    DIRECTION OUTPUT ;
    USE SIGNAL ;
    SHAPE ABUTMENT ;
    PORT
      LAYER M4 ;
      RECT 224.856 23.520 225.048 23.544 ;
    END
  END link_out[215]
  PIN link_out[216]
    DIRECTION OUTPUT ;
    USE SIGNAL ;
    SHAPE ABUTMENT ;
    PORT
      LAYER M4 ;
      RECT 224.856 23.616 225.048 23.640 ;
    END
  END link_out[216]
  PIN link_out[217]
    DIRECTION OUTPUT ;
    USE SIGNAL ;
    SHAPE ABUTMENT ;
    PORT
      LAYER M4 ;
      RECT 224.856 23.760 225.048 23.784 ;
    END
  END link_out[217]
  PIN link_out[218]
    DIRECTION OUTPUT ;
    USE SIGNAL ;
    SHAPE ABUTMENT ;
    PORT
      LAYER M4 ;
      RECT 224.856 23.856 225.048 23.880 ;
    END
  END link_out[218]
  PIN link_out[219]
    DIRECTION OUTPUT ;
    USE SIGNAL ;
    SHAPE ABUTMENT ;
    PORT
      LAYER M4 ;
      RECT 224.856 23.952 225.048 23.976 ;
    END
  END link_out[219]
  PIN link_out[220]
    DIRECTION OUTPUT ;
    USE SIGNAL ;
    SHAPE ABUTMENT ;
    PORT
      LAYER M4 ;
      RECT 224.856 24.048 225.048 24.072 ;
    END
  END link_out[220]
  PIN link_out[221]
    DIRECTION OUTPUT ;
    USE SIGNAL ;
    SHAPE ABUTMENT ;
    PORT
      LAYER M4 ;
      RECT 224.856 24.192 225.048 24.216 ;
    END
  END link_out[221]
  PIN link_out[222]
    DIRECTION OUTPUT ;
    USE SIGNAL ;
    SHAPE ABUTMENT ;
    PORT
      LAYER M4 ;
      RECT 224.856 24.288 225.048 24.312 ;
    END
  END link_out[222]
  PIN link_out[223]
    DIRECTION OUTPUT ;
    USE SIGNAL ;
    SHAPE ABUTMENT ;
    PORT
      LAYER M4 ;
      RECT 224.856 24.384 225.048 24.408 ;
    END
  END link_out[223]
  PIN link_out[224]
    DIRECTION OUTPUT ;
    USE SIGNAL ;
    SHAPE ABUTMENT ;
    PORT
      LAYER M4 ;
      RECT 224.856 24.480 225.048 24.504 ;
    END
  END link_out[224]
  PIN link_out[225]
    DIRECTION OUTPUT ;
    USE SIGNAL ;
    SHAPE ABUTMENT ;
    PORT
      LAYER M4 ;
      RECT 224.856 24.624 225.048 24.648 ;
    END
  END link_out[225]
  PIN link_out[226]
    DIRECTION OUTPUT ;
    USE SIGNAL ;
    SHAPE ABUTMENT ;
    PORT
      LAYER M4 ;
      RECT 224.856 24.720 225.048 24.744 ;
    END
  END link_out[226]
  PIN link_out[227]
    DIRECTION OUTPUT ;
    USE SIGNAL ;
    SHAPE ABUTMENT ;
    PORT
      LAYER M4 ;
      RECT 224.856 24.816 225.048 24.840 ;
    END
  END link_out[227]
  PIN link_out[228]
    DIRECTION OUTPUT ;
    USE SIGNAL ;
    SHAPE ABUTMENT ;
    PORT
      LAYER M4 ;
      RECT 224.856 24.912 225.048 24.936 ;
    END
  END link_out[228]
  PIN link_out[229]
    DIRECTION OUTPUT ;
    USE SIGNAL ;
    SHAPE ABUTMENT ;
    PORT
      LAYER M4 ;
      RECT 224.856 25.056 225.048 25.080 ;
    END
  END link_out[229]
  PIN link_out[230]
    DIRECTION OUTPUT ;
    USE SIGNAL ;
    SHAPE ABUTMENT ;
    PORT
      LAYER M4 ;
      RECT 224.856 25.152 225.048 25.176 ;
    END
  END link_out[230]
  PIN link_out[231]
    DIRECTION OUTPUT ;
    USE SIGNAL ;
    SHAPE ABUTMENT ;
    PORT
      LAYER M4 ;
      RECT 224.856 25.248 225.048 25.272 ;
    END
  END link_out[231]
  PIN link_out[232]
    DIRECTION OUTPUT ;
    USE SIGNAL ;
    SHAPE ABUTMENT ;
    PORT
      LAYER M4 ;
      RECT 224.856 25.344 225.048 25.368 ;
    END
  END link_out[232]
  PIN link_out[233]
    DIRECTION OUTPUT ;
    USE SIGNAL ;
    SHAPE ABUTMENT ;
    PORT
      LAYER M4 ;
      RECT 224.856 25.440 225.048 25.464 ;
    END
  END link_out[233]
  PIN link_out[234]
    DIRECTION OUTPUT ;
    USE SIGNAL ;
    SHAPE ABUTMENT ;
    PORT
      LAYER M4 ;
      RECT 224.856 25.584 225.048 25.608 ;
    END
  END link_out[234]
  PIN link_out[235]
    DIRECTION OUTPUT ;
    USE SIGNAL ;
    SHAPE ABUTMENT ;
    PORT
      LAYER M4 ;
      RECT 224.856 25.680 225.048 25.704 ;
    END
  END link_out[235]
  PIN link_out[236]
    DIRECTION OUTPUT ;
    USE SIGNAL ;
    SHAPE ABUTMENT ;
    PORT
      LAYER M4 ;
      RECT 224.856 25.776 225.048 25.800 ;
    END
  END link_out[236]
  PIN link_out[237]
    DIRECTION OUTPUT ;
    USE SIGNAL ;
    SHAPE ABUTMENT ;
    PORT
      LAYER M4 ;
      RECT 224.856 25.872 225.048 25.896 ;
    END
  END link_out[237]
  PIN link_out[238]
    DIRECTION OUTPUT ;
    USE SIGNAL ;
    SHAPE ABUTMENT ;
    PORT
      LAYER M4 ;
      RECT 224.856 26.016 225.048 26.040 ;
    END
  END link_out[238]
  PIN link_out[239]
    DIRECTION OUTPUT ;
    USE SIGNAL ;
    SHAPE ABUTMENT ;
    PORT
      LAYER M4 ;
      RECT 224.856 26.112 225.048 26.136 ;
    END
  END link_out[239]
  PIN link_out[240]
    DIRECTION OUTPUT ;
    USE SIGNAL ;
    SHAPE ABUTMENT ;
    PORT
      LAYER M4 ;
      RECT 224.856 26.208 225.048 26.232 ;
    END
  END link_out[240]
  PIN link_out[241]
    DIRECTION OUTPUT ;
    USE SIGNAL ;
    SHAPE ABUTMENT ;
    PORT
      LAYER M4 ;
      RECT 224.856 26.304 225.048 26.328 ;
    END
  END link_out[241]
  PIN link_out[242]
    DIRECTION OUTPUT ;
    USE SIGNAL ;
    SHAPE ABUTMENT ;
    PORT
      LAYER M4 ;
      RECT 224.856 26.448 225.048 26.472 ;
    END
  END link_out[242]
  PIN link_out[243]
    DIRECTION OUTPUT ;
    USE SIGNAL ;
    SHAPE ABUTMENT ;
    PORT
      LAYER M4 ;
      RECT 224.856 26.544 225.048 26.568 ;
    END
  END link_out[243]
  PIN link_out[244]
    DIRECTION OUTPUT ;
    USE SIGNAL ;
    SHAPE ABUTMENT ;
    PORT
      LAYER M4 ;
      RECT 224.856 26.640 225.048 26.664 ;
    END
  END link_out[244]
  PIN link_out[245]
    DIRECTION OUTPUT ;
    USE SIGNAL ;
    SHAPE ABUTMENT ;
    PORT
      LAYER M4 ;
      RECT 224.856 26.736 225.048 26.760 ;
    END
  END link_out[245]
  PIN link_out[246]
    DIRECTION OUTPUT ;
    USE SIGNAL ;
    SHAPE ABUTMENT ;
    PORT
      LAYER M4 ;
      RECT 224.856 26.832 225.048 26.856 ;
    END
  END link_out[246]
  PIN link_out[247]
    DIRECTION OUTPUT ;
    USE SIGNAL ;
    SHAPE ABUTMENT ;
    PORT
      LAYER M4 ;
      RECT 224.856 26.976 225.048 27.000 ;
    END
  END link_out[247]
  PIN link_out[248]
    DIRECTION OUTPUT ;
    USE SIGNAL ;
    SHAPE ABUTMENT ;
    PORT
      LAYER M4 ;
      RECT 224.856 27.072 225.048 27.096 ;
    END
  END link_out[248]
  PIN link_out[249]
    DIRECTION OUTPUT ;
    USE SIGNAL ;
    SHAPE ABUTMENT ;
    PORT
      LAYER M4 ;
      RECT 224.856 27.168 225.048 27.192 ;
    END
  END link_out[249]
  PIN link_out[250]
    DIRECTION OUTPUT ;
    USE SIGNAL ;
    SHAPE ABUTMENT ;
    PORT
      LAYER M4 ;
      RECT 224.856 27.264 225.048 27.288 ;
    END
  END link_out[250]
  PIN link_out[251]
    DIRECTION OUTPUT ;
    USE SIGNAL ;
    SHAPE ABUTMENT ;
    PORT
      LAYER M4 ;
      RECT 224.856 27.408 225.048 27.432 ;
    END
  END link_out[251]
  PIN link_out[252]
    DIRECTION OUTPUT ;
    USE SIGNAL ;
    SHAPE ABUTMENT ;
    PORT
      LAYER M4 ;
      RECT 224.856 27.504 225.048 27.528 ;
    END
  END link_out[252]
  PIN link_out[253]
    DIRECTION OUTPUT ;
    USE SIGNAL ;
    SHAPE ABUTMENT ;
    PORT
      LAYER M4 ;
      RECT 224.856 27.600 225.048 27.624 ;
    END
  END link_out[253]
  PIN link_out[254]
    DIRECTION OUTPUT ;
    USE SIGNAL ;
    SHAPE ABUTMENT ;
    PORT
      LAYER M4 ;
      RECT 224.856 27.696 225.048 27.720 ;
    END
  END link_out[254]
  PIN link_out[255]
    DIRECTION OUTPUT ;
    USE SIGNAL ;
    SHAPE ABUTMENT ;
    PORT
      LAYER M4 ;
      RECT 224.856 27.840 225.048 27.864 ;
    END
  END link_out[255]
  PIN link_out[256]
    DIRECTION OUTPUT ;
    USE SIGNAL ;
    SHAPE ABUTMENT ;
    PORT
      LAYER M4 ;
      RECT 224.856 27.936 225.048 27.960 ;
    END
  END link_out[256]
  PIN link_out[257]
    DIRECTION OUTPUT ;
    USE SIGNAL ;
    SHAPE ABUTMENT ;
    PORT
      LAYER M4 ;
      RECT 224.856 28.032 225.048 28.056 ;
    END
  END link_out[257]
  PIN link_out[258]
    DIRECTION OUTPUT ;
    USE SIGNAL ;
    SHAPE ABUTMENT ;
    PORT
      LAYER M4 ;
      RECT 224.856 28.128 225.048 28.152 ;
    END
  END link_out[258]
  PIN link_out[259]
    DIRECTION OUTPUT ;
    USE SIGNAL ;
    SHAPE ABUTMENT ;
    PORT
      LAYER M4 ;
      RECT 224.856 28.224 225.048 28.248 ;
    END
  END link_out[259]
  PIN link_out[260]
    DIRECTION OUTPUT ;
    USE SIGNAL ;
    SHAPE ABUTMENT ;
    PORT
      LAYER M4 ;
      RECT 224.856 28.368 225.048 28.392 ;
    END
  END link_out[260]
  PIN link_out[261]
    DIRECTION OUTPUT ;
    USE SIGNAL ;
    SHAPE ABUTMENT ;
    PORT
      LAYER M4 ;
      RECT 224.856 28.464 225.048 28.488 ;
    END
  END link_out[261]
  PIN link_out[262]
    DIRECTION OUTPUT ;
    USE SIGNAL ;
    SHAPE ABUTMENT ;
    PORT
      LAYER M4 ;
      RECT 224.856 28.560 225.048 28.584 ;
    END
  END link_out[262]
  PIN link_out[263]
    DIRECTION OUTPUT ;
    USE SIGNAL ;
    SHAPE ABUTMENT ;
    PORT
      LAYER M4 ;
      RECT 224.856 28.656 225.048 28.680 ;
    END
  END link_out[263]
  PIN link_out[264]
    DIRECTION OUTPUT ;
    USE SIGNAL ;
    SHAPE ABUTMENT ;
    PORT
      LAYER M4 ;
      RECT 224.856 28.800 225.048 28.824 ;
    END
  END link_out[264]
  PIN link_out[265]
    DIRECTION OUTPUT ;
    USE SIGNAL ;
    SHAPE ABUTMENT ;
    PORT
      LAYER M4 ;
      RECT 224.856 28.896 225.048 28.920 ;
    END
  END link_out[265]
  PIN link_out[266]
    DIRECTION OUTPUT ;
    USE SIGNAL ;
    SHAPE ABUTMENT ;
    PORT
      LAYER M4 ;
      RECT 224.856 28.992 225.048 29.016 ;
    END
  END link_out[266]
  PIN link_out[267]
    DIRECTION OUTPUT ;
    USE SIGNAL ;
    SHAPE ABUTMENT ;
    PORT
      LAYER M4 ;
      RECT 224.856 29.088 225.048 29.112 ;
    END
  END link_out[267]
  PIN link_out[268]
    DIRECTION OUTPUT ;
    USE SIGNAL ;
    SHAPE ABUTMENT ;
    PORT
      LAYER M4 ;
      RECT 224.856 29.232 225.048 29.256 ;
    END
  END link_out[268]
  PIN link_out[269]
    DIRECTION OUTPUT ;
    USE SIGNAL ;
    SHAPE ABUTMENT ;
    PORT
      LAYER M4 ;
      RECT 224.856 29.328 225.048 29.352 ;
    END
  END link_out[269]
  PIN link_out[270]
    DIRECTION OUTPUT ;
    USE SIGNAL ;
    SHAPE ABUTMENT ;
    PORT
      LAYER M4 ;
      RECT 224.856 29.424 225.048 29.448 ;
    END
  END link_out[270]
  PIN link_out[271]
    DIRECTION OUTPUT ;
    USE SIGNAL ;
    SHAPE ABUTMENT ;
    PORT
      LAYER M4 ;
      RECT 224.856 29.520 225.048 29.544 ;
    END
  END link_out[271]
  PIN link_out[272]
    DIRECTION OUTPUT ;
    USE SIGNAL ;
    SHAPE ABUTMENT ;
    PORT
      LAYER M4 ;
      RECT 224.856 29.616 225.048 29.640 ;
    END
  END link_out[272]
  PIN link_out[273]
    DIRECTION OUTPUT ;
    USE SIGNAL ;
    SHAPE ABUTMENT ;
    PORT
      LAYER M4 ;
      RECT 224.856 29.760 225.048 29.784 ;
    END
  END link_out[273]
  PIN link_out[274]
    DIRECTION OUTPUT ;
    USE SIGNAL ;
    SHAPE ABUTMENT ;
    PORT
      LAYER M4 ;
      RECT 224.856 29.856 225.048 29.880 ;
    END
  END link_out[274]
  PIN link_out[275]
    DIRECTION OUTPUT ;
    USE SIGNAL ;
    SHAPE ABUTMENT ;
    PORT
      LAYER M4 ;
      RECT 224.856 29.952 225.048 29.976 ;
    END
  END link_out[275]
  PIN link_out[276]
    DIRECTION OUTPUT ;
    USE SIGNAL ;
    SHAPE ABUTMENT ;
    PORT
      LAYER M4 ;
      RECT 224.856 30.048 225.048 30.072 ;
    END
  END link_out[276]
  PIN link_out[277]
    DIRECTION OUTPUT ;
    USE SIGNAL ;
    SHAPE ABUTMENT ;
    PORT
      LAYER M4 ;
      RECT 224.856 30.192 225.048 30.216 ;
    END
  END link_out[277]
  PIN link_out[278]
    DIRECTION OUTPUT ;
    USE SIGNAL ;
    SHAPE ABUTMENT ;
    PORT
      LAYER M4 ;
      RECT 224.856 30.288 225.048 30.312 ;
    END
  END link_out[278]
  PIN link_out[279]
    DIRECTION OUTPUT ;
    USE SIGNAL ;
    SHAPE ABUTMENT ;
    PORT
      LAYER M4 ;
      RECT 224.856 30.384 225.048 30.408 ;
    END
  END link_out[279]
  PIN link_out[280]
    DIRECTION OUTPUT ;
    USE SIGNAL ;
    SHAPE ABUTMENT ;
    PORT
      LAYER M4 ;
      RECT 224.856 30.480 225.048 30.504 ;
    END
  END link_out[280]
  PIN link_out[281]
    DIRECTION OUTPUT ;
    USE SIGNAL ;
    SHAPE ABUTMENT ;
    PORT
      LAYER M4 ;
      RECT 224.856 30.624 225.048 30.648 ;
    END
  END link_out[281]
  PIN link_out[282]
    DIRECTION OUTPUT ;
    USE SIGNAL ;
    SHAPE ABUTMENT ;
    PORT
      LAYER M4 ;
      RECT 224.856 30.720 225.048 30.744 ;
    END
  END link_out[282]
  PIN link_out[283]
    DIRECTION OUTPUT ;
    USE SIGNAL ;
    SHAPE ABUTMENT ;
    PORT
      LAYER M4 ;
      RECT 224.856 30.816 225.048 30.840 ;
    END
  END link_out[283]
  PIN link_out[284]
    DIRECTION OUTPUT ;
    USE SIGNAL ;
    SHAPE ABUTMENT ;
    PORT
      LAYER M4 ;
      RECT 224.856 30.912 225.048 30.936 ;
    END
  END link_out[284]
  PIN link_out[285]
    DIRECTION OUTPUT ;
    USE SIGNAL ;
    SHAPE ABUTMENT ;
    PORT
      LAYER M4 ;
      RECT 224.856 31.008 225.048 31.032 ;
    END
  END link_out[285]
  PIN link_out[286]
    DIRECTION OUTPUT ;
    USE SIGNAL ;
    SHAPE ABUTMENT ;
    PORT
      LAYER M4 ;
      RECT 224.856 31.152 225.048 31.176 ;
    END
  END link_out[286]
  PIN link_out[287]
    DIRECTION OUTPUT ;
    USE SIGNAL ;
    SHAPE ABUTMENT ;
    PORT
      LAYER M4 ;
      RECT 224.856 31.248 225.048 31.272 ;
    END
  END link_out[287]
  PIN link_out[288]
    DIRECTION OUTPUT ;
    USE SIGNAL ;
    SHAPE ABUTMENT ;
    PORT
      LAYER M4 ;
      RECT 224.856 31.344 225.048 31.368 ;
    END
  END link_out[288]
  PIN link_out[289]
    DIRECTION OUTPUT ;
    USE SIGNAL ;
    SHAPE ABUTMENT ;
    PORT
      LAYER M4 ;
      RECT 224.856 31.440 225.048 31.464 ;
    END
  END link_out[289]
  PIN link_out[290]
    DIRECTION OUTPUT ;
    USE SIGNAL ;
    SHAPE ABUTMENT ;
    PORT
      LAYER M4 ;
      RECT 224.856 31.584 225.048 31.608 ;
    END
  END link_out[290]
  PIN link_out[291]
    DIRECTION OUTPUT ;
    USE SIGNAL ;
    SHAPE ABUTMENT ;
    PORT
      LAYER M4 ;
      RECT 224.856 31.680 225.048 31.704 ;
    END
  END link_out[291]
  PIN link_out[292]
    DIRECTION OUTPUT ;
    USE SIGNAL ;
    SHAPE ABUTMENT ;
    PORT
      LAYER M4 ;
      RECT 224.856 31.776 225.048 31.800 ;
    END
  END link_out[292]
  PIN link_out[293]
    DIRECTION OUTPUT ;
    USE SIGNAL ;
    SHAPE ABUTMENT ;
    PORT
      LAYER M4 ;
      RECT 224.856 31.872 225.048 31.896 ;
    END
  END link_out[293]
  PIN link_out[294]
    DIRECTION OUTPUT ;
    USE SIGNAL ;
    SHAPE ABUTMENT ;
    PORT
      LAYER M4 ;
      RECT 224.856 32.016 225.048 32.040 ;
    END
  END link_out[294]
  PIN link_out[295]
    DIRECTION OUTPUT ;
    USE SIGNAL ;
    SHAPE ABUTMENT ;
    PORT
      LAYER M4 ;
      RECT 224.856 32.112 225.048 32.136 ;
    END
  END link_out[295]
  PIN link_out[296]
    DIRECTION OUTPUT ;
    USE SIGNAL ;
    SHAPE ABUTMENT ;
    PORT
      LAYER M4 ;
      RECT 224.856 32.208 225.048 32.232 ;
    END
  END link_out[296]
  PIN link_out[297]
    DIRECTION OUTPUT ;
    USE SIGNAL ;
    SHAPE ABUTMENT ;
    PORT
      LAYER M4 ;
      RECT 224.856 32.304 225.048 32.328 ;
    END
  END link_out[297]
  PIN link_out[298]
    DIRECTION OUTPUT ;
    USE SIGNAL ;
    SHAPE ABUTMENT ;
    PORT
      LAYER M4 ;
      RECT 224.856 32.400 225.048 32.424 ;
    END
  END link_out[298]
  PIN link_out[299]
    DIRECTION OUTPUT ;
    USE SIGNAL ;
    SHAPE ABUTMENT ;
    PORT
      LAYER M4 ;
      RECT 224.856 32.544 225.048 32.568 ;
    END
  END link_out[299]
  PIN link_out[300]
    DIRECTION OUTPUT ;
    USE SIGNAL ;
    SHAPE ABUTMENT ;
    PORT
      LAYER M4 ;
      RECT 224.856 32.640 225.048 32.664 ;
    END
  END link_out[300]
  PIN link_out[301]
    DIRECTION OUTPUT ;
    USE SIGNAL ;
    SHAPE ABUTMENT ;
    PORT
      LAYER M4 ;
      RECT 224.856 32.736 225.048 32.760 ;
    END
  END link_out[301]
  PIN link_out[302]
    DIRECTION OUTPUT ;
    USE SIGNAL ;
    SHAPE ABUTMENT ;
    PORT
      LAYER M4 ;
      RECT 224.856 32.832 225.048 32.856 ;
    END
  END link_out[302]
  PIN link_out[303]
    DIRECTION OUTPUT ;
    USE SIGNAL ;
    SHAPE ABUTMENT ;
    PORT
      LAYER M4 ;
      RECT 224.856 32.976 225.048 33.000 ;
    END
  END link_out[303]
  PIN link_out[304]
    DIRECTION OUTPUT ;
    USE SIGNAL ;
    SHAPE ABUTMENT ;
    PORT
      LAYER M4 ;
      RECT 224.856 33.072 225.048 33.096 ;
    END
  END link_out[304]
  PIN link_out[305]
    DIRECTION OUTPUT ;
    USE SIGNAL ;
    SHAPE ABUTMENT ;
    PORT
      LAYER M4 ;
      RECT 224.856 33.168 225.048 33.192 ;
    END
  END link_out[305]
  PIN link_out[306]
    DIRECTION OUTPUT ;
    USE SIGNAL ;
    SHAPE ABUTMENT ;
    PORT
      LAYER M4 ;
      RECT 224.856 33.264 225.048 33.288 ;
    END
  END link_out[306]
  PIN link_out[307]
    DIRECTION OUTPUT ;
    USE SIGNAL ;
    SHAPE ABUTMENT ;
    PORT
      LAYER M4 ;
      RECT 224.856 33.408 225.048 33.432 ;
    END
  END link_out[307]
  PIN link_out[308]
    DIRECTION OUTPUT ;
    USE SIGNAL ;
    SHAPE ABUTMENT ;
    PORT
      LAYER M4 ;
      RECT 224.856 33.504 225.048 33.528 ;
    END
  END link_out[308]
  PIN link_out[309]
    DIRECTION OUTPUT ;
    USE SIGNAL ;
    SHAPE ABUTMENT ;
    PORT
      LAYER M4 ;
      RECT 224.856 33.600 225.048 33.624 ;
    END
  END link_out[309]
  PIN link_out[310]
    DIRECTION OUTPUT ;
    USE SIGNAL ;
    SHAPE ABUTMENT ;
    PORT
      LAYER M4 ;
      RECT 224.856 33.696 225.048 33.720 ;
    END
  END link_out[310]
  PIN link_out[311]
    DIRECTION OUTPUT ;
    USE SIGNAL ;
    SHAPE ABUTMENT ;
    PORT
      LAYER M4 ;
      RECT 224.856 33.792 225.048 33.816 ;
    END
  END link_out[311]
  PIN link_out[312]
    DIRECTION OUTPUT ;
    USE SIGNAL ;
    SHAPE ABUTMENT ;
    PORT
      LAYER M4 ;
      RECT 224.856 33.936 225.048 33.960 ;
    END
  END link_out[312]
  PIN link_out[313]
    DIRECTION OUTPUT ;
    USE SIGNAL ;
    SHAPE ABUTMENT ;
    PORT
      LAYER M4 ;
      RECT 224.856 34.032 225.048 34.056 ;
    END
  END link_out[313]
  PIN link_out[314]
    DIRECTION OUTPUT ;
    USE SIGNAL ;
    SHAPE ABUTMENT ;
    PORT
      LAYER M4 ;
      RECT 224.856 34.128 225.048 34.152 ;
    END
  END link_out[314]
  PIN link_out[315]
    DIRECTION OUTPUT ;
    USE SIGNAL ;
    SHAPE ABUTMENT ;
    PORT
      LAYER M4 ;
      RECT 224.856 34.224 225.048 34.248 ;
    END
  END link_out[315]
  PIN link_out[316]
    DIRECTION OUTPUT ;
    USE SIGNAL ;
    SHAPE ABUTMENT ;
    PORT
      LAYER M4 ;
      RECT 224.856 34.368 225.048 34.392 ;
    END
  END link_out[316]
  PIN link_out[317]
    DIRECTION OUTPUT ;
    USE SIGNAL ;
    SHAPE ABUTMENT ;
    PORT
      LAYER M4 ;
      RECT 224.856 34.464 225.048 34.488 ;
    END
  END link_out[317]
  PIN link_out[318]
    DIRECTION OUTPUT ;
    USE SIGNAL ;
    SHAPE ABUTMENT ;
    PORT
      LAYER M4 ;
      RECT 224.856 34.560 225.048 34.584 ;
    END
  END link_out[318]
  PIN link_out[319]
    DIRECTION OUTPUT ;
    USE SIGNAL ;
    SHAPE ABUTMENT ;
    PORT
      LAYER M4 ;
      RECT 224.856 34.656 225.048 34.680 ;
    END
  END link_out[319]
  PIN link_out[320]
    DIRECTION OUTPUT ;
    USE SIGNAL ;
    SHAPE ABUTMENT ;
    PORT
      LAYER M4 ;
      RECT 224.856 34.800 225.048 34.824 ;
    END
  END link_out[320]
  PIN link_out[321]
    DIRECTION OUTPUT ;
    USE SIGNAL ;
    SHAPE ABUTMENT ;
    PORT
      LAYER M4 ;
      RECT 224.856 34.896 225.048 34.920 ;
    END
  END link_out[321]
  PIN link_out[322]
    DIRECTION OUTPUT ;
    USE SIGNAL ;
    SHAPE ABUTMENT ;
    PORT
      LAYER M4 ;
      RECT 224.856 34.992 225.048 35.016 ;
    END
  END link_out[322]
  PIN link_out[323]
    DIRECTION OUTPUT ;
    USE SIGNAL ;
    SHAPE ABUTMENT ;
    PORT
      LAYER M4 ;
      RECT 224.856 35.088 225.048 35.112 ;
    END
  END link_out[323]
  PIN link_out[324]
    DIRECTION OUTPUT ;
    USE SIGNAL ;
    SHAPE ABUTMENT ;
    PORT
      LAYER M4 ;
      RECT 224.856 35.184 225.048 35.208 ;
    END
  END link_out[324]
  PIN link_out[325]
    DIRECTION OUTPUT ;
    USE SIGNAL ;
    SHAPE ABUTMENT ;
    PORT
      LAYER M4 ;
      RECT 224.856 35.328 225.048 35.352 ;
    END
  END link_out[325]
  PIN link_out[326]
    DIRECTION OUTPUT ;
    USE SIGNAL ;
    SHAPE ABUTMENT ;
    PORT
      LAYER M4 ;
      RECT 224.856 35.424 225.048 35.448 ;
    END
  END link_out[326]
  PIN link_out[327]
    DIRECTION OUTPUT ;
    USE SIGNAL ;
    SHAPE ABUTMENT ;
    PORT
      LAYER M4 ;
      RECT 224.856 35.520 225.048 35.544 ;
    END
  END link_out[327]
  PIN link_out[328]
    DIRECTION OUTPUT ;
    USE SIGNAL ;
    SHAPE ABUTMENT ;
    PORT
      LAYER M4 ;
      RECT 224.856 35.616 225.048 35.640 ;
    END
  END link_out[328]
  PIN link_out[329]
    DIRECTION OUTPUT ;
    USE SIGNAL ;
    SHAPE ABUTMENT ;
    PORT
      LAYER M4 ;
      RECT 224.856 35.760 225.048 35.784 ;
    END
  END link_out[329]
  PIN link_out[330]
    DIRECTION OUTPUT ;
    USE SIGNAL ;
    SHAPE ABUTMENT ;
    PORT
      LAYER M4 ;
      RECT 224.856 35.856 225.048 35.880 ;
    END
  END link_out[330]
  PIN link_out[331]
    DIRECTION OUTPUT ;
    USE SIGNAL ;
    SHAPE ABUTMENT ;
    PORT
      LAYER M4 ;
      RECT 224.856 35.952 225.048 35.976 ;
    END
  END link_out[331]
  PIN link_out[332]
    DIRECTION OUTPUT ;
    USE SIGNAL ;
    SHAPE ABUTMENT ;
    PORT
      LAYER M4 ;
      RECT 224.856 36.048 225.048 36.072 ;
    END
  END link_out[332]
  PIN link_out[333]
    DIRECTION OUTPUT ;
    USE SIGNAL ;
    SHAPE ABUTMENT ;
    PORT
      LAYER M4 ;
      RECT 224.856 36.192 225.048 36.216 ;
    END
  END link_out[333]
  PIN link_out[334]
    DIRECTION OUTPUT ;
    USE SIGNAL ;
    SHAPE ABUTMENT ;
    PORT
      LAYER M4 ;
      RECT 224.856 36.288 225.048 36.312 ;
    END
  END link_out[334]
  PIN link_out[335]
    DIRECTION OUTPUT ;
    USE SIGNAL ;
    SHAPE ABUTMENT ;
    PORT
      LAYER M4 ;
      RECT 224.856 36.384 225.048 36.408 ;
    END
  END link_out[335]
  PIN link_out[336]
    DIRECTION OUTPUT ;
    USE SIGNAL ;
    SHAPE ABUTMENT ;
    PORT
      LAYER M4 ;
      RECT 224.856 36.480 225.048 36.504 ;
    END
  END link_out[336]
  PIN link_out[337]
    DIRECTION OUTPUT ;
    USE SIGNAL ;
    SHAPE ABUTMENT ;
    PORT
      LAYER M4 ;
      RECT 224.856 36.576 225.048 36.600 ;
    END
  END link_out[337]
  PIN link_out[338]
    DIRECTION OUTPUT ;
    USE SIGNAL ;
    SHAPE ABUTMENT ;
    PORT
      LAYER M4 ;
      RECT 224.856 36.720 225.048 36.744 ;
    END
  END link_out[338]
  PIN link_out[339]
    DIRECTION OUTPUT ;
    USE SIGNAL ;
    SHAPE ABUTMENT ;
    PORT
      LAYER M4 ;
      RECT 224.856 36.816 225.048 36.840 ;
    END
  END link_out[339]
  PIN link_out[340]
    DIRECTION OUTPUT ;
    USE SIGNAL ;
    SHAPE ABUTMENT ;
    PORT
      LAYER M4 ;
      RECT 224.856 36.912 225.048 36.936 ;
    END
  END link_out[340]
  PIN link_out[341]
    DIRECTION OUTPUT ;
    USE SIGNAL ;
    SHAPE ABUTMENT ;
    PORT
      LAYER M4 ;
      RECT 224.856 37.008 225.048 37.032 ;
    END
  END link_out[341]
  PIN link_out[342]
    DIRECTION OUTPUT ;
    USE SIGNAL ;
    SHAPE ABUTMENT ;
    PORT
      LAYER M4 ;
      RECT 224.856 37.152 225.048 37.176 ;
    END
  END link_out[342]
  PIN link_out[343]
    DIRECTION OUTPUT ;
    USE SIGNAL ;
    SHAPE ABUTMENT ;
    PORT
      LAYER M4 ;
      RECT 224.856 37.248 225.048 37.272 ;
    END
  END link_out[343]
  PIN link_out[344]
    DIRECTION OUTPUT ;
    USE SIGNAL ;
    SHAPE ABUTMENT ;
    PORT
      LAYER M4 ;
      RECT 224.856 37.344 225.048 37.368 ;
    END
  END link_out[344]
  PIN link_out[345]
    DIRECTION OUTPUT ;
    USE SIGNAL ;
    SHAPE ABUTMENT ;
    PORT
      LAYER M4 ;
      RECT 224.856 37.440 225.048 37.464 ;
    END
  END link_out[345]
  PIN link_out[346]
    DIRECTION OUTPUT ;
    USE SIGNAL ;
    SHAPE ABUTMENT ;
    PORT
      LAYER M4 ;
      RECT 224.856 37.584 225.048 37.608 ;
    END
  END link_out[346]
  PIN link_out[347]
    DIRECTION OUTPUT ;
    USE SIGNAL ;
    SHAPE ABUTMENT ;
    PORT
      LAYER M4 ;
      RECT 224.856 37.680 225.048 37.704 ;
    END
  END link_out[347]
  PIN link_out[348]
    DIRECTION OUTPUT ;
    USE SIGNAL ;
    SHAPE ABUTMENT ;
    PORT
      LAYER M4 ;
      RECT 224.856 37.776 225.048 37.800 ;
    END
  END link_out[348]
  PIN link_out[349]
    DIRECTION OUTPUT ;
    USE SIGNAL ;
    SHAPE ABUTMENT ;
    PORT
      LAYER M4 ;
      RECT 224.856 37.872 225.048 37.896 ;
    END
  END link_out[349]
  PIN link_out[350]
    DIRECTION OUTPUT ;
    USE SIGNAL ;
    SHAPE ABUTMENT ;
    PORT
      LAYER M4 ;
      RECT 224.856 38.016 225.048 38.040 ;
    END
  END link_out[350]
  PIN link_out[351]
    DIRECTION OUTPUT ;
    USE SIGNAL ;
    SHAPE ABUTMENT ;
    PORT
      LAYER M4 ;
      RECT 224.856 38.112 225.048 38.136 ;
    END
  END link_out[351]
  PIN link_out[352]
    DIRECTION OUTPUT ;
    USE SIGNAL ;
    SHAPE ABUTMENT ;
    PORT
      LAYER M4 ;
      RECT 224.856 38.208 225.048 38.232 ;
    END
  END link_out[352]
  PIN link_out[353]
    DIRECTION OUTPUT ;
    USE SIGNAL ;
    SHAPE ABUTMENT ;
    PORT
      LAYER M4 ;
      RECT 224.856 38.304 225.048 38.328 ;
    END
  END link_out[353]
  PIN link_out[354]
    DIRECTION OUTPUT ;
    USE SIGNAL ;
    SHAPE ABUTMENT ;
    PORT
      LAYER M4 ;
      RECT 224.856 38.400 225.048 38.424 ;
    END
  END link_out[354]
  PIN link_out[355]
    DIRECTION OUTPUT ;
    USE SIGNAL ;
    SHAPE ABUTMENT ;
    PORT
      LAYER M4 ;
      RECT 224.856 38.544 225.048 38.568 ;
    END
  END link_out[355]
  PIN link_out[356]
    DIRECTION OUTPUT ;
    USE SIGNAL ;
    SHAPE ABUTMENT ;
    PORT
      LAYER M4 ;
      RECT 224.856 38.640 225.048 38.664 ;
    END
  END link_out[356]
  PIN link_out[357]
    DIRECTION OUTPUT ;
    USE SIGNAL ;
    SHAPE ABUTMENT ;
    PORT
      LAYER M4 ;
      RECT 224.856 38.736 225.048 38.760 ;
    END
  END link_out[357]
  PIN link_out[358]
    DIRECTION OUTPUT ;
    USE SIGNAL ;
    SHAPE ABUTMENT ;
    PORT
      LAYER M4 ;
      RECT 224.856 38.832 225.048 38.856 ;
    END
  END link_out[358]
  PIN link_out[359]
    DIRECTION OUTPUT ;
    USE SIGNAL ;
    SHAPE ABUTMENT ;
    PORT
      LAYER M4 ;
      RECT 224.856 38.976 225.048 39.000 ;
    END
  END link_out[359]
  PIN link_out[360]
    DIRECTION OUTPUT ;
    USE SIGNAL ;
    SHAPE ABUTMENT ;
    PORT
      LAYER M4 ;
      RECT 224.856 39.072 225.048 39.096 ;
    END
  END link_out[360]
  PIN link_out[361]
    DIRECTION OUTPUT ;
    USE SIGNAL ;
    SHAPE ABUTMENT ;
    PORT
      LAYER M4 ;
      RECT 224.856 39.168 225.048 39.192 ;
    END
  END link_out[361]
  PIN link_out[362]
    DIRECTION OUTPUT ;
    USE SIGNAL ;
    SHAPE ABUTMENT ;
    PORT
      LAYER M4 ;
      RECT 224.856 39.264 225.048 39.288 ;
    END
  END link_out[362]
  PIN link_out[363]
    DIRECTION OUTPUT ;
    USE SIGNAL ;
    SHAPE ABUTMENT ;
    PORT
      LAYER M4 ;
      RECT 224.856 39.408 225.048 39.432 ;
    END
  END link_out[363]
  PIN link_out[364]
    DIRECTION OUTPUT ;
    USE SIGNAL ;
    SHAPE ABUTMENT ;
    PORT
      LAYER M4 ;
      RECT 224.856 39.504 225.048 39.528 ;
    END
  END link_out[364]
  PIN link_out[365]
    DIRECTION OUTPUT ;
    USE SIGNAL ;
    SHAPE ABUTMENT ;
    PORT
      LAYER M4 ;
      RECT 224.856 39.600 225.048 39.624 ;
    END
  END link_out[365]
  PIN link_out[366]
    DIRECTION OUTPUT ;
    USE SIGNAL ;
    SHAPE ABUTMENT ;
    PORT
      LAYER M4 ;
      RECT 224.856 39.696 225.048 39.720 ;
    END
  END link_out[366]
  PIN link_out[367]
    DIRECTION OUTPUT ;
    USE SIGNAL ;
    SHAPE ABUTMENT ;
    PORT
      LAYER M4 ;
      RECT 224.856 39.792 225.048 39.816 ;
    END
  END link_out[367]
  PIN link_out[368]
    DIRECTION OUTPUT ;
    USE SIGNAL ;
    SHAPE ABUTMENT ;
    PORT
      LAYER M4 ;
      RECT 224.856 39.936 225.048 39.960 ;
    END
  END link_out[368]
  PIN link_out[369]
    DIRECTION OUTPUT ;
    USE SIGNAL ;
    SHAPE ABUTMENT ;
    PORT
      LAYER M4 ;
      RECT 224.856 40.032 225.048 40.056 ;
    END
  END link_out[369]
  PIN link_out[370]
    DIRECTION OUTPUT ;
    USE SIGNAL ;
    SHAPE ABUTMENT ;
    PORT
      LAYER M4 ;
      RECT 224.856 40.128 225.048 40.152 ;
    END
  END link_out[370]
  PIN link_out[371]
    DIRECTION OUTPUT ;
    USE SIGNAL ;
    SHAPE ABUTMENT ;
    PORT
      LAYER M4 ;
      RECT 224.856 40.224 225.048 40.248 ;
    END
  END link_out[371]
  PIN link_out[372]
    DIRECTION OUTPUT ;
    USE SIGNAL ;
    SHAPE ABUTMENT ;
    PORT
      LAYER M4 ;
      RECT 224.856 40.368 225.048 40.392 ;
    END
  END link_out[372]
  PIN link_out[373]
    DIRECTION OUTPUT ;
    USE SIGNAL ;
    SHAPE ABUTMENT ;
    PORT
      LAYER M4 ;
      RECT 224.856 40.464 225.048 40.488 ;
    END
  END link_out[373]
  PIN link_out[374]
    DIRECTION OUTPUT ;
    USE SIGNAL ;
    SHAPE ABUTMENT ;
    PORT
      LAYER M4 ;
      RECT 224.856 40.560 225.048 40.584 ;
    END
  END link_out[374]
  PIN link_out[375]
    DIRECTION OUTPUT ;
    USE SIGNAL ;
    SHAPE ABUTMENT ;
    PORT
      LAYER M4 ;
      RECT 224.856 40.656 225.048 40.680 ;
    END
  END link_out[375]
  PIN link_out[376]
    DIRECTION OUTPUT ;
    USE SIGNAL ;
    SHAPE ABUTMENT ;
    PORT
      LAYER M4 ;
      RECT 224.856 40.800 225.048 40.824 ;
    END
  END link_out[376]
  PIN link_out[377]
    DIRECTION OUTPUT ;
    USE SIGNAL ;
    SHAPE ABUTMENT ;
    PORT
      LAYER M4 ;
      RECT 224.856 40.896 225.048 40.920 ;
    END
  END link_out[377]
  PIN link_out[378]
    DIRECTION OUTPUT ;
    USE SIGNAL ;
    SHAPE ABUTMENT ;
    PORT
      LAYER M4 ;
      RECT 224.856 40.992 225.048 41.016 ;
    END
  END link_out[378]
  PIN link_out[379]
    DIRECTION OUTPUT ;
    USE SIGNAL ;
    SHAPE ABUTMENT ;
    PORT
      LAYER M4 ;
      RECT 224.856 41.088 225.048 41.112 ;
    END
  END link_out[379]
  PIN link_out[380]
    DIRECTION OUTPUT ;
    USE SIGNAL ;
    SHAPE ABUTMENT ;
    PORT
      LAYER M4 ;
      RECT 224.856 41.184 225.048 41.208 ;
    END
  END link_out[380]
  PIN link_out[381]
    DIRECTION OUTPUT ;
    USE SIGNAL ;
    SHAPE ABUTMENT ;
    PORT
      LAYER M4 ;
      RECT 224.856 41.328 225.048 41.352 ;
    END
  END link_out[381]
  PIN link_out[382]
    DIRECTION OUTPUT ;
    USE SIGNAL ;
    SHAPE ABUTMENT ;
    PORT
      LAYER M4 ;
      RECT 224.856 41.424 225.048 41.448 ;
    END
  END link_out[382]
  PIN link_out[383]
    DIRECTION OUTPUT ;
    USE SIGNAL ;
    SHAPE ABUTMENT ;
    PORT
      LAYER M4 ;
      RECT 224.856 41.520 225.048 41.544 ;
    END
  END link_out[383]
  PIN link_out[384]
    DIRECTION OUTPUT ;
    USE SIGNAL ;
    SHAPE ABUTMENT ;
    PORT
      LAYER M4 ;
      RECT 224.856 41.616 225.048 41.640 ;
    END
  END link_out[384]
  PIN link_out[385]
    DIRECTION OUTPUT ;
    USE SIGNAL ;
    SHAPE ABUTMENT ;
    PORT
      LAYER M4 ;
      RECT 224.856 41.760 225.048 41.784 ;
    END
  END link_out[385]
  PIN link_out[386]
    DIRECTION OUTPUT ;
    USE SIGNAL ;
    SHAPE ABUTMENT ;
    PORT
      LAYER M4 ;
      RECT 224.856 41.856 225.048 41.880 ;
    END
  END link_out[386]
  PIN link_out[387]
    DIRECTION OUTPUT ;
    USE SIGNAL ;
    SHAPE ABUTMENT ;
    PORT
      LAYER M4 ;
      RECT 224.856 41.952 225.048 41.976 ;
    END
  END link_out[387]
  PIN link_out[388]
    DIRECTION OUTPUT ;
    USE SIGNAL ;
    SHAPE ABUTMENT ;
    PORT
      LAYER M4 ;
      RECT 224.856 42.048 225.048 42.072 ;
    END
  END link_out[388]
  PIN link_out[389]
    DIRECTION OUTPUT ;
    USE SIGNAL ;
    SHAPE ABUTMENT ;
    PORT
      LAYER M4 ;
      RECT 224.856 42.192 225.048 42.216 ;
    END
  END link_out[389]
  PIN link_out[390]
    DIRECTION OUTPUT ;
    USE SIGNAL ;
    SHAPE ABUTMENT ;
    PORT
      LAYER M4 ;
      RECT 224.856 42.288 225.048 42.312 ;
    END
  END link_out[390]
  PIN link_out[391]
    DIRECTION OUTPUT ;
    USE SIGNAL ;
    SHAPE ABUTMENT ;
    PORT
      LAYER M4 ;
      RECT 224.856 42.384 225.048 42.408 ;
    END
  END link_out[391]
  PIN link_out[392]
    DIRECTION OUTPUT ;
    USE SIGNAL ;
    SHAPE ABUTMENT ;
    PORT
      LAYER M4 ;
      RECT 224.856 42.480 225.048 42.504 ;
    END
  END link_out[392]
  PIN link_out[393]
    DIRECTION OUTPUT ;
    USE SIGNAL ;
    SHAPE ABUTMENT ;
    PORT
      LAYER M4 ;
      RECT 224.856 42.576 225.048 42.600 ;
    END
  END link_out[393]
  PIN link_out[394]
    DIRECTION OUTPUT ;
    USE SIGNAL ;
    SHAPE ABUTMENT ;
    PORT
      LAYER M4 ;
      RECT 224.856 42.720 225.048 42.744 ;
    END
  END link_out[394]
  PIN link_out[395]
    DIRECTION OUTPUT ;
    USE SIGNAL ;
    SHAPE ABUTMENT ;
    PORT
      LAYER M4 ;
      RECT 224.856 42.816 225.048 42.840 ;
    END
  END link_out[395]
  PIN link_out[396]
    DIRECTION OUTPUT ;
    USE SIGNAL ;
    SHAPE ABUTMENT ;
    PORT
      LAYER M4 ;
      RECT 224.856 42.912 225.048 42.936 ;
    END
  END link_out[396]
  PIN link_out[397]
    DIRECTION OUTPUT ;
    USE SIGNAL ;
    SHAPE ABUTMENT ;
    PORT
      LAYER M4 ;
      RECT 224.856 43.008 225.048 43.032 ;
    END
  END link_out[397]
  PIN link_out[398]
    DIRECTION OUTPUT ;
    USE SIGNAL ;
    SHAPE ABUTMENT ;
    PORT
      LAYER M4 ;
      RECT 224.856 43.152 225.048 43.176 ;
    END
  END link_out[398]
  PIN link_out[399]
    DIRECTION OUTPUT ;
    USE SIGNAL ;
    SHAPE ABUTMENT ;
    PORT
      LAYER M4 ;
      RECT 224.856 43.248 225.048 43.272 ;
    END
  END link_out[399]
  PIN link_out[400]
    DIRECTION OUTPUT ;
    USE SIGNAL ;
    SHAPE ABUTMENT ;
    PORT
      LAYER M4 ;
      RECT 224.856 43.344 225.048 43.368 ;
    END
  END link_out[400]
  PIN link_out[401]
    DIRECTION OUTPUT ;
    USE SIGNAL ;
    SHAPE ABUTMENT ;
    PORT
      LAYER M4 ;
      RECT 224.856 43.440 225.048 43.464 ;
    END
  END link_out[401]
  PIN link_out[402]
    DIRECTION OUTPUT ;
    USE SIGNAL ;
    SHAPE ABUTMENT ;
    PORT
      LAYER M4 ;
      RECT 224.856 43.584 225.048 43.608 ;
    END
  END link_out[402]
  PIN link_out[403]
    DIRECTION OUTPUT ;
    USE SIGNAL ;
    SHAPE ABUTMENT ;
    PORT
      LAYER M4 ;
      RECT 224.856 43.680 225.048 43.704 ;
    END
  END link_out[403]
  PIN link_out[404]
    DIRECTION OUTPUT ;
    USE SIGNAL ;
    SHAPE ABUTMENT ;
    PORT
      LAYER M4 ;
      RECT 224.856 43.776 225.048 43.800 ;
    END
  END link_out[404]
  PIN link_out[405]
    DIRECTION OUTPUT ;
    USE SIGNAL ;
    SHAPE ABUTMENT ;
    PORT
      LAYER M4 ;
      RECT 224.856 43.872 225.048 43.896 ;
    END
  END link_out[405]
  PIN link_out[406]
    DIRECTION OUTPUT ;
    USE SIGNAL ;
    SHAPE ABUTMENT ;
    PORT
      LAYER M4 ;
      RECT 224.856 43.968 225.048 43.992 ;
    END
  END link_out[406]
  PIN link_out[407]
    DIRECTION OUTPUT ;
    USE SIGNAL ;
    SHAPE ABUTMENT ;
    PORT
      LAYER M4 ;
      RECT 224.856 44.112 225.048 44.136 ;
    END
  END link_out[407]
  PIN link_out[408]
    DIRECTION OUTPUT ;
    USE SIGNAL ;
    SHAPE ABUTMENT ;
    PORT
      LAYER M4 ;
      RECT 224.856 44.208 225.048 44.232 ;
    END
  END link_out[408]
  PIN link_out[409]
    DIRECTION OUTPUT ;
    USE SIGNAL ;
    SHAPE ABUTMENT ;
    PORT
      LAYER M4 ;
      RECT 224.856 44.304 225.048 44.328 ;
    END
  END link_out[409]
  PIN link_out[410]
    DIRECTION OUTPUT ;
    USE SIGNAL ;
    SHAPE ABUTMENT ;
    PORT
      LAYER M4 ;
      RECT 224.856 44.400 225.048 44.424 ;
    END
  END link_out[410]
  PIN link_out[411]
    DIRECTION OUTPUT ;
    USE SIGNAL ;
    SHAPE ABUTMENT ;
    PORT
      LAYER M4 ;
      RECT 224.856 44.544 225.048 44.568 ;
    END
  END link_out[411]
  PIN link_out[412]
    DIRECTION OUTPUT ;
    USE SIGNAL ;
    SHAPE ABUTMENT ;
    PORT
      LAYER M4 ;
      RECT 224.856 44.640 225.048 44.664 ;
    END
  END link_out[412]
  PIN link_out[413]
    DIRECTION OUTPUT ;
    USE SIGNAL ;
    SHAPE ABUTMENT ;
    PORT
      LAYER M4 ;
      RECT 224.856 44.736 225.048 44.760 ;
    END
  END link_out[413]
  PIN link_out[414]
    DIRECTION OUTPUT ;
    USE SIGNAL ;
    SHAPE ABUTMENT ;
    PORT
      LAYER M4 ;
      RECT 224.856 44.832 225.048 44.856 ;
    END
  END link_out[414]
  PIN link_out[415]
    DIRECTION OUTPUT ;
    USE SIGNAL ;
    SHAPE ABUTMENT ;
    PORT
      LAYER M4 ;
      RECT 224.856 44.976 225.048 45.000 ;
    END
  END link_out[415]
  PIN link_out[416]
    DIRECTION OUTPUT ;
    USE SIGNAL ;
    SHAPE ABUTMENT ;
    PORT
      LAYER M4 ;
      RECT 224.856 45.072 225.048 45.096 ;
    END
  END link_out[416]
  PIN link_out[417]
    DIRECTION OUTPUT ;
    USE SIGNAL ;
    SHAPE ABUTMENT ;
    PORT
      LAYER M4 ;
      RECT 224.856 45.168 225.048 45.192 ;
    END
  END link_out[417]
  PIN link_out[418]
    DIRECTION OUTPUT ;
    USE SIGNAL ;
    SHAPE ABUTMENT ;
    PORT
      LAYER M4 ;
      RECT 224.856 45.264 225.048 45.288 ;
    END
  END link_out[418]
  PIN link_out[419]
    DIRECTION OUTPUT ;
    USE SIGNAL ;
    SHAPE ABUTMENT ;
    PORT
      LAYER M4 ;
      RECT 224.856 45.360 225.048 45.384 ;
    END
  END link_out[419]
  PIN link_out[420]
    DIRECTION OUTPUT ;
    USE SIGNAL ;
    SHAPE ABUTMENT ;
    PORT
      LAYER M4 ;
      RECT 224.856 45.504 225.048 45.528 ;
    END
  END link_out[420]
  PIN link_out[421]
    DIRECTION OUTPUT ;
    USE SIGNAL ;
    SHAPE ABUTMENT ;
    PORT
      LAYER M4 ;
      RECT 224.856 45.600 225.048 45.624 ;
    END
  END link_out[421]
  PIN link_out[422]
    DIRECTION OUTPUT ;
    USE SIGNAL ;
    SHAPE ABUTMENT ;
    PORT
      LAYER M4 ;
      RECT 224.856 45.696 225.048 45.720 ;
    END
  END link_out[422]
  PIN link_out[423]
    DIRECTION OUTPUT ;
    USE SIGNAL ;
    SHAPE ABUTMENT ;
    PORT
      LAYER M4 ;
      RECT 224.856 45.792 225.048 45.816 ;
    END
  END link_out[423]
  PIN link_out[424]
    DIRECTION OUTPUT ;
    USE SIGNAL ;
    SHAPE ABUTMENT ;
    PORT
      LAYER M4 ;
      RECT 224.856 45.936 225.048 45.960 ;
    END
  END link_out[424]
  PIN link_out[425]
    DIRECTION OUTPUT ;
    USE SIGNAL ;
    SHAPE ABUTMENT ;
    PORT
      LAYER M4 ;
      RECT 224.856 46.032 225.048 46.056 ;
    END
  END link_out[425]
  PIN link_out[426]
    DIRECTION OUTPUT ;
    USE SIGNAL ;
    SHAPE ABUTMENT ;
    PORT
      LAYER M4 ;
      RECT 224.856 46.128 225.048 46.152 ;
    END
  END link_out[426]
  PIN link_out[427]
    DIRECTION OUTPUT ;
    USE SIGNAL ;
    SHAPE ABUTMENT ;
    PORT
      LAYER M4 ;
      RECT 224.856 46.224 225.048 46.248 ;
    END
  END link_out[427]
  PIN link_out[428]
    DIRECTION OUTPUT ;
    USE SIGNAL ;
    SHAPE ABUTMENT ;
    PORT
      LAYER M4 ;
      RECT 224.856 46.368 225.048 46.392 ;
    END
  END link_out[428]
  PIN link_out[429]
    DIRECTION OUTPUT ;
    USE SIGNAL ;
    SHAPE ABUTMENT ;
    PORT
      LAYER M4 ;
      RECT 224.856 46.464 225.048 46.488 ;
    END
  END link_out[429]
  PIN link_out[430]
    DIRECTION OUTPUT ;
    USE SIGNAL ;
    SHAPE ABUTMENT ;
    PORT
      LAYER M4 ;
      RECT 224.856 46.560 225.048 46.584 ;
    END
  END link_out[430]
  PIN link_out[431]
    DIRECTION OUTPUT ;
    USE SIGNAL ;
    SHAPE ABUTMENT ;
    PORT
      LAYER M4 ;
      RECT 224.856 46.656 225.048 46.680 ;
    END
  END link_out[431]
  PIN link_out[432]
    DIRECTION OUTPUT ;
    USE SIGNAL ;
    SHAPE ABUTMENT ;
    PORT
      LAYER M4 ;
      RECT 224.856 46.752 225.048 46.776 ;
    END
  END link_out[432]
  PIN link_out[433]
    DIRECTION OUTPUT ;
    USE SIGNAL ;
    SHAPE ABUTMENT ;
    PORT
      LAYER M4 ;
      RECT 224.856 46.896 225.048 46.920 ;
    END
  END link_out[433]
  PIN link_out[434]
    DIRECTION OUTPUT ;
    USE SIGNAL ;
    SHAPE ABUTMENT ;
    PORT
      LAYER M4 ;
      RECT 224.856 46.992 225.048 47.016 ;
    END
  END link_out[434]
  PIN link_out[435]
    DIRECTION OUTPUT ;
    USE SIGNAL ;
    SHAPE ABUTMENT ;
    PORT
      LAYER M4 ;
      RECT 224.856 47.088 225.048 47.112 ;
    END
  END link_out[435]
  PIN link_out[436]
    DIRECTION OUTPUT ;
    USE SIGNAL ;
    SHAPE ABUTMENT ;
    PORT
      LAYER M4 ;
      RECT 224.856 47.184 225.048 47.208 ;
    END
  END link_out[436]
  PIN link_out[437]
    DIRECTION OUTPUT ;
    USE SIGNAL ;
    SHAPE ABUTMENT ;
    PORT
      LAYER M4 ;
      RECT 224.856 47.328 225.048 47.352 ;
    END
  END link_out[437]
  PIN link_out[438]
    DIRECTION OUTPUT ;
    USE SIGNAL ;
    SHAPE ABUTMENT ;
    PORT
      LAYER M4 ;
      RECT 224.856 47.424 225.048 47.448 ;
    END
  END link_out[438]
  PIN link_out[439]
    DIRECTION OUTPUT ;
    USE SIGNAL ;
    SHAPE ABUTMENT ;
    PORT
      LAYER M4 ;
      RECT 224.856 47.520 225.048 47.544 ;
    END
  END link_out[439]
  PIN link_out[440]
    DIRECTION OUTPUT ;
    USE SIGNAL ;
    SHAPE ABUTMENT ;
    PORT
      LAYER M4 ;
      RECT 224.856 47.616 225.048 47.640 ;
    END
  END link_out[440]
  PIN link_out[441]
    DIRECTION OUTPUT ;
    USE SIGNAL ;
    SHAPE ABUTMENT ;
    PORT
      LAYER M4 ;
      RECT 224.856 47.760 225.048 47.784 ;
    END
  END link_out[441]
  PIN link_out[442]
    DIRECTION OUTPUT ;
    USE SIGNAL ;
    SHAPE ABUTMENT ;
    PORT
      LAYER M4 ;
      RECT 224.856 47.856 225.048 47.880 ;
    END
  END link_out[442]
  PIN link_out[443]
    DIRECTION OUTPUT ;
    USE SIGNAL ;
    SHAPE ABUTMENT ;
    PORT
      LAYER M4 ;
      RECT 224.856 47.952 225.048 47.976 ;
    END
  END link_out[443]
  PIN link_out[444]
    DIRECTION OUTPUT ;
    USE SIGNAL ;
    SHAPE ABUTMENT ;
    PORT
      LAYER M4 ;
      RECT 224.856 48.048 225.048 48.072 ;
    END
  END link_out[444]
  PIN link_out[445]
    DIRECTION OUTPUT ;
    USE SIGNAL ;
    SHAPE ABUTMENT ;
    PORT
      LAYER M4 ;
      RECT 224.856 48.144 225.048 48.168 ;
    END
  END link_out[445]
  PIN link_out[446]
    DIRECTION OUTPUT ;
    USE SIGNAL ;
    SHAPE ABUTMENT ;
    PORT
      LAYER M4 ;
      RECT 224.856 48.288 225.048 48.312 ;
    END
  END link_out[446]
  PIN link_out[447]
    DIRECTION OUTPUT ;
    USE SIGNAL ;
    SHAPE ABUTMENT ;
    PORT
      LAYER M4 ;
      RECT 224.856 48.384 225.048 48.408 ;
    END
  END link_out[447]
  PIN link_out[448]
    DIRECTION OUTPUT ;
    USE SIGNAL ;
    SHAPE ABUTMENT ;
    PORT
      LAYER M4 ;
      RECT 224.856 48.480 225.048 48.504 ;
    END
  END link_out[448]
  PIN link_out[449]
    DIRECTION OUTPUT ;
    USE SIGNAL ;
    SHAPE ABUTMENT ;
    PORT
      LAYER M4 ;
      RECT 224.856 48.576 225.048 48.600 ;
    END
  END link_out[449]
  PIN link_out[450]
    DIRECTION OUTPUT ;
    USE SIGNAL ;
    SHAPE ABUTMENT ;
    PORT
      LAYER M4 ;
      RECT 224.856 48.720 225.048 48.744 ;
    END
  END link_out[450]
  PIN link_out[451]
    DIRECTION OUTPUT ;
    USE SIGNAL ;
    SHAPE ABUTMENT ;
    PORT
      LAYER M4 ;
      RECT 224.856 48.816 225.048 48.840 ;
    END
  END link_out[451]
  PIN link_out[452]
    DIRECTION OUTPUT ;
    USE SIGNAL ;
    SHAPE ABUTMENT ;
    PORT
      LAYER M4 ;
      RECT 224.856 48.912 225.048 48.936 ;
    END
  END link_out[452]
  PIN link_out[453]
    DIRECTION OUTPUT ;
    USE SIGNAL ;
    SHAPE ABUTMENT ;
    PORT
      LAYER M4 ;
      RECT 224.856 49.008 225.048 49.032 ;
    END
  END link_out[453]
  PIN link_out[454]
    DIRECTION OUTPUT ;
    USE SIGNAL ;
    SHAPE ABUTMENT ;
    PORT
      LAYER M4 ;
      RECT 224.856 49.152 225.048 49.176 ;
    END
  END link_out[454]
  PIN link_out[455]
    DIRECTION OUTPUT ;
    USE SIGNAL ;
    SHAPE ABUTMENT ;
    PORT
      LAYER M4 ;
      RECT 224.856 49.248 225.048 49.272 ;
    END
  END link_out[455]
  PIN link_out[456]
    DIRECTION OUTPUT ;
    USE SIGNAL ;
    SHAPE ABUTMENT ;
    PORT
      LAYER M4 ;
      RECT 224.856 49.344 225.048 49.368 ;
    END
  END link_out[456]
  PIN link_out[457]
    DIRECTION OUTPUT ;
    USE SIGNAL ;
    SHAPE ABUTMENT ;
    PORT
      LAYER M4 ;
      RECT 224.856 49.440 225.048 49.464 ;
    END
  END link_out[457]
  PIN link_out[458]
    DIRECTION OUTPUT ;
    USE SIGNAL ;
    SHAPE ABUTMENT ;
    PORT
      LAYER M4 ;
      RECT 224.856 49.584 225.048 49.608 ;
    END
  END link_out[458]
  PIN link_out[459]
    DIRECTION OUTPUT ;
    USE SIGNAL ;
    SHAPE ABUTMENT ;
    PORT
      LAYER M4 ;
      RECT 224.856 49.680 225.048 49.704 ;
    END
  END link_out[459]
  PIN link_out[460]
    DIRECTION OUTPUT ;
    USE SIGNAL ;
    SHAPE ABUTMENT ;
    PORT
      LAYER M4 ;
      RECT 224.856 49.776 225.048 49.800 ;
    END
  END link_out[460]
  PIN link_out[461]
    DIRECTION OUTPUT ;
    USE SIGNAL ;
    SHAPE ABUTMENT ;
    PORT
      LAYER M4 ;
      RECT 224.856 49.872 225.048 49.896 ;
    END
  END link_out[461]
  PIN link_out[462]
    DIRECTION OUTPUT ;
    USE SIGNAL ;
    SHAPE ABUTMENT ;
    PORT
      LAYER M4 ;
      RECT 224.856 49.968 225.048 49.992 ;
    END
  END link_out[462]
  PIN link_out[463]
    DIRECTION OUTPUT ;
    USE SIGNAL ;
    SHAPE ABUTMENT ;
    PORT
      LAYER M4 ;
      RECT 224.856 50.112 225.048 50.136 ;
    END
  END link_out[463]
  PIN link_out[464]
    DIRECTION OUTPUT ;
    USE SIGNAL ;
    SHAPE ABUTMENT ;
    PORT
      LAYER M4 ;
      RECT 224.856 50.208 225.048 50.232 ;
    END
  END link_out[464]
  PIN link_out[465]
    DIRECTION OUTPUT ;
    USE SIGNAL ;
    SHAPE ABUTMENT ;
    PORT
      LAYER M4 ;
      RECT 224.856 50.304 225.048 50.328 ;
    END
  END link_out[465]
  PIN link_out[466]
    DIRECTION OUTPUT ;
    USE SIGNAL ;
    SHAPE ABUTMENT ;
    PORT
      LAYER M4 ;
      RECT 224.856 50.400 225.048 50.424 ;
    END
  END link_out[466]
  PIN link_out[467]
    DIRECTION OUTPUT ;
    USE SIGNAL ;
    SHAPE ABUTMENT ;
    PORT
      LAYER M4 ;
      RECT 224.856 50.544 225.048 50.568 ;
    END
  END link_out[467]
  PIN link_out[468]
    DIRECTION OUTPUT ;
    USE SIGNAL ;
    SHAPE ABUTMENT ;
    PORT
      LAYER M4 ;
      RECT 224.856 50.640 225.048 50.664 ;
    END
  END link_out[468]
  PIN link_out[469]
    DIRECTION OUTPUT ;
    USE SIGNAL ;
    SHAPE ABUTMENT ;
    PORT
      LAYER M4 ;
      RECT 224.856 50.736 225.048 50.760 ;
    END
  END link_out[469]
  PIN link_out[470]
    DIRECTION OUTPUT ;
    USE SIGNAL ;
    SHAPE ABUTMENT ;
    PORT
      LAYER M4 ;
      RECT 224.856 50.832 225.048 50.856 ;
    END
  END link_out[470]
  PIN link_out[471]
    DIRECTION OUTPUT ;
    USE SIGNAL ;
    SHAPE ABUTMENT ;
    PORT
      LAYER M4 ;
      RECT 224.856 50.976 225.048 51.000 ;
    END
  END link_out[471]
  PIN link_out[472]
    DIRECTION OUTPUT ;
    USE SIGNAL ;
    SHAPE ABUTMENT ;
    PORT
      LAYER M4 ;
      RECT 224.856 51.072 225.048 51.096 ;
    END
  END link_out[472]
  PIN link_out[473]
    DIRECTION OUTPUT ;
    USE SIGNAL ;
    SHAPE ABUTMENT ;
    PORT
      LAYER M4 ;
      RECT 224.856 51.168 225.048 51.192 ;
    END
  END link_out[473]
  PIN link_out[474]
    DIRECTION OUTPUT ;
    USE SIGNAL ;
    SHAPE ABUTMENT ;
    PORT
      LAYER M4 ;
      RECT 224.856 51.264 225.048 51.288 ;
    END
  END link_out[474]
  PIN link_out[475]
    DIRECTION OUTPUT ;
    USE SIGNAL ;
    SHAPE ABUTMENT ;
    PORT
      LAYER M4 ;
      RECT 224.856 51.360 225.048 51.384 ;
    END
  END link_out[475]
  PIN link_out[476]
    DIRECTION OUTPUT ;
    USE SIGNAL ;
    SHAPE ABUTMENT ;
    PORT
      LAYER M4 ;
      RECT 224.856 51.504 225.048 51.528 ;
    END
  END link_out[476]
  PIN link_out[477]
    DIRECTION OUTPUT ;
    USE SIGNAL ;
    SHAPE ABUTMENT ;
    PORT
      LAYER M4 ;
      RECT 224.856 51.600 225.048 51.624 ;
    END
  END link_out[477]
  PIN link_out[478]
    DIRECTION OUTPUT ;
    USE SIGNAL ;
    SHAPE ABUTMENT ;
    PORT
      LAYER M4 ;
      RECT 224.856 51.696 225.048 51.720 ;
    END
  END link_out[478]
  PIN link_out[479]
    DIRECTION OUTPUT ;
    USE SIGNAL ;
    SHAPE ABUTMENT ;
    PORT
      LAYER M4 ;
      RECT 224.856 51.792 225.048 51.816 ;
    END
  END link_out[479]
  PIN link_out[480]
    DIRECTION OUTPUT ;
    USE SIGNAL ;
    SHAPE ABUTMENT ;
    PORT
      LAYER M4 ;
      RECT 224.856 51.936 225.048 51.960 ;
    END
  END link_out[480]
  PIN link_out[481]
    DIRECTION OUTPUT ;
    USE SIGNAL ;
    SHAPE ABUTMENT ;
    PORT
      LAYER M4 ;
      RECT 224.856 52.032 225.048 52.056 ;
    END
  END link_out[481]
  PIN link_out[482]
    DIRECTION OUTPUT ;
    USE SIGNAL ;
    SHAPE ABUTMENT ;
    PORT
      LAYER M4 ;
      RECT 224.856 52.128 225.048 52.152 ;
    END
  END link_out[482]
  PIN link_out[483]
    DIRECTION OUTPUT ;
    USE SIGNAL ;
    SHAPE ABUTMENT ;
    PORT
      LAYER M4 ;
      RECT 224.856 52.224 225.048 52.248 ;
    END
  END link_out[483]
  PIN link_out[484]
    DIRECTION OUTPUT ;
    USE SIGNAL ;
    SHAPE ABUTMENT ;
    PORT
      LAYER M4 ;
      RECT 224.856 52.368 225.048 52.392 ;
    END
  END link_out[484]
  PIN link_out[485]
    DIRECTION OUTPUT ;
    USE SIGNAL ;
    SHAPE ABUTMENT ;
    PORT
      LAYER M4 ;
      RECT 224.856 52.464 225.048 52.488 ;
    END
  END link_out[485]
  PIN link_out[486]
    DIRECTION OUTPUT ;
    USE SIGNAL ;
    SHAPE ABUTMENT ;
    PORT
      LAYER M4 ;
      RECT 224.856 52.560 225.048 52.584 ;
    END
  END link_out[486]
  PIN link_out[487]
    DIRECTION OUTPUT ;
    USE SIGNAL ;
    SHAPE ABUTMENT ;
    PORT
      LAYER M4 ;
      RECT 224.856 52.656 225.048 52.680 ;
    END
  END link_out[487]
  PIN link_out[488]
    DIRECTION OUTPUT ;
    USE SIGNAL ;
    SHAPE ABUTMENT ;
    PORT
      LAYER M4 ;
      RECT 224.856 52.752 225.048 52.776 ;
    END
  END link_out[488]
  PIN link_out[489]
    DIRECTION OUTPUT ;
    USE SIGNAL ;
    SHAPE ABUTMENT ;
    PORT
      LAYER M4 ;
      RECT 224.856 52.896 225.048 52.920 ;
    END
  END link_out[489]
  PIN link_out[490]
    DIRECTION OUTPUT ;
    USE SIGNAL ;
    SHAPE ABUTMENT ;
    PORT
      LAYER M4 ;
      RECT 224.856 52.992 225.048 53.016 ;
    END
  END link_out[490]
  PIN link_out[491]
    DIRECTION OUTPUT ;
    USE SIGNAL ;
    SHAPE ABUTMENT ;
    PORT
      LAYER M4 ;
      RECT 224.856 53.088 225.048 53.112 ;
    END
  END link_out[491]
  PIN link_out[492]
    DIRECTION OUTPUT ;
    USE SIGNAL ;
    SHAPE ABUTMENT ;
    PORT
      LAYER M4 ;
      RECT 224.856 53.184 225.048 53.208 ;
    END
  END link_out[492]
  PIN link_out[493]
    DIRECTION OUTPUT ;
    USE SIGNAL ;
    SHAPE ABUTMENT ;
    PORT
      LAYER M4 ;
      RECT 224.856 53.328 225.048 53.352 ;
    END
  END link_out[493]
  PIN link_out[494]
    DIRECTION OUTPUT ;
    USE SIGNAL ;
    SHAPE ABUTMENT ;
    PORT
      LAYER M4 ;
      RECT 224.856 53.424 225.048 53.448 ;
    END
  END link_out[494]
  PIN link_out[495]
    DIRECTION OUTPUT ;
    USE SIGNAL ;
    SHAPE ABUTMENT ;
    PORT
      LAYER M4 ;
      RECT 224.856 53.520 225.048 53.544 ;
    END
  END link_out[495]
  PIN link_out[496]
    DIRECTION OUTPUT ;
    USE SIGNAL ;
    SHAPE ABUTMENT ;
    PORT
      LAYER M4 ;
      RECT 224.856 53.616 225.048 53.640 ;
    END
  END link_out[496]
  PIN link_out[497]
    DIRECTION OUTPUT ;
    USE SIGNAL ;
    SHAPE ABUTMENT ;
    PORT
      LAYER M4 ;
      RECT 224.856 53.760 225.048 53.784 ;
    END
  END link_out[497]
  PIN link_out[498]
    DIRECTION OUTPUT ;
    USE SIGNAL ;
    SHAPE ABUTMENT ;
    PORT
      LAYER M4 ;
      RECT 224.856 53.856 225.048 53.880 ;
    END
  END link_out[498]
  PIN link_out[499]
    DIRECTION OUTPUT ;
    USE SIGNAL ;
    SHAPE ABUTMENT ;
    PORT
      LAYER M4 ;
      RECT 224.856 53.952 225.048 53.976 ;
    END
  END link_out[499]
  PIN link_out[500]
    DIRECTION OUTPUT ;
    USE SIGNAL ;
    SHAPE ABUTMENT ;
    PORT
      LAYER M4 ;
      RECT 224.856 54.048 225.048 54.072 ;
    END
  END link_out[500]
  PIN link_out[501]
    DIRECTION OUTPUT ;
    USE SIGNAL ;
    SHAPE ABUTMENT ;
    PORT
      LAYER M4 ;
      RECT 224.856 54.144 225.048 54.168 ;
    END
  END link_out[501]
  PIN link_out[502]
    DIRECTION OUTPUT ;
    USE SIGNAL ;
    SHAPE ABUTMENT ;
    PORT
      LAYER M4 ;
      RECT 224.856 54.288 225.048 54.312 ;
    END
  END link_out[502]
  PIN link_out[503]
    DIRECTION OUTPUT ;
    USE SIGNAL ;
    SHAPE ABUTMENT ;
    PORT
      LAYER M4 ;
      RECT 224.856 54.384 225.048 54.408 ;
    END
  END link_out[503]
  PIN link_out[504]
    DIRECTION OUTPUT ;
    USE SIGNAL ;
    SHAPE ABUTMENT ;
    PORT
      LAYER M4 ;
      RECT 224.856 54.480 225.048 54.504 ;
    END
  END link_out[504]
  PIN link_out[505]
    DIRECTION OUTPUT ;
    USE SIGNAL ;
    SHAPE ABUTMENT ;
    PORT
      LAYER M4 ;
      RECT 224.856 54.576 225.048 54.600 ;
    END
  END link_out[505]
  PIN link_out[506]
    DIRECTION OUTPUT ;
    USE SIGNAL ;
    SHAPE ABUTMENT ;
    PORT
      LAYER M4 ;
      RECT 224.856 54.720 225.048 54.744 ;
    END
  END link_out[506]
  PIN link_out[507]
    DIRECTION OUTPUT ;
    USE SIGNAL ;
    SHAPE ABUTMENT ;
    PORT
      LAYER M4 ;
      RECT 224.856 54.816 225.048 54.840 ;
    END
  END link_out[507]
  PIN link_out[508]
    DIRECTION OUTPUT ;
    USE SIGNAL ;
    SHAPE ABUTMENT ;
    PORT
      LAYER M4 ;
      RECT 224.856 54.912 225.048 54.936 ;
    END
  END link_out[508]
  PIN link_out[509]
    DIRECTION OUTPUT ;
    USE SIGNAL ;
    SHAPE ABUTMENT ;
    PORT
      LAYER M4 ;
      RECT 224.856 55.008 225.048 55.032 ;
    END
  END link_out[509]
  PIN link_out[510]
    DIRECTION OUTPUT ;
    USE SIGNAL ;
    SHAPE ABUTMENT ;
    PORT
      LAYER M4 ;
      RECT 224.856 55.152 225.048 55.176 ;
    END
  END link_out[510]
  PIN link_out[511]
    DIRECTION OUTPUT ;
    USE SIGNAL ;
    SHAPE ABUTMENT ;
    PORT
      LAYER M4 ;
      RECT 224.856 55.248 225.048 55.272 ;
    END
  END link_out[511]
  PIN link_in[0]
    DIRECTION INPUT ;
    USE SIGNAL ;
    SHAPE ABUTMENT ;
    PORT
      LAYER M4 ;
      RECT 224.856 55.344 225.048 55.368 ;
    END
  END link_in[0]
  PIN link_in[1]
    DIRECTION INPUT ;
    USE SIGNAL ;
    SHAPE ABUTMENT ;
    PORT
      LAYER M4 ;
      RECT 224.856 55.440 225.048 55.464 ;
    END
  END link_in[1]
  PIN link_in[2]
    DIRECTION INPUT ;
    USE SIGNAL ;
    SHAPE ABUTMENT ;
    PORT
      LAYER M4 ;
      RECT 224.856 55.536 225.048 55.560 ;
    END
  END link_in[2]
  PIN link_in[3]
    DIRECTION INPUT ;
    USE SIGNAL ;
    SHAPE ABUTMENT ;
    PORT
      LAYER M4 ;
      RECT 224.856 55.680 225.048 55.704 ;
    END
  END link_in[3]
  PIN link_in[4]
    DIRECTION INPUT ;
    USE SIGNAL ;
    SHAPE ABUTMENT ;
    PORT
      LAYER M4 ;
      RECT 224.856 55.776 225.048 55.800 ;
    END
  END link_in[4]
  PIN link_in[5]
    DIRECTION INPUT ;
    USE SIGNAL ;
    SHAPE ABUTMENT ;
    PORT
      LAYER M4 ;
      RECT 224.856 55.872 225.048 55.896 ;
    END
  END link_in[5]
  PIN link_in[6]
    DIRECTION INPUT ;
    USE SIGNAL ;
    SHAPE ABUTMENT ;
    PORT
      LAYER M4 ;
      RECT 224.856 55.968 225.048 55.992 ;
    END
  END link_in[6]
  PIN link_in[7]
    DIRECTION INPUT ;
    USE SIGNAL ;
    SHAPE ABUTMENT ;
    PORT
      LAYER M4 ;
      RECT 224.856 56.112 225.048 56.136 ;
    END
  END link_in[7]
  PIN link_in[8]
    DIRECTION INPUT ;
    USE SIGNAL ;
    SHAPE ABUTMENT ;
    PORT
      LAYER M4 ;
      RECT 224.856 56.208 225.048 56.232 ;
    END
  END link_in[8]
  PIN link_in[9]
    DIRECTION INPUT ;
    USE SIGNAL ;
    SHAPE ABUTMENT ;
    PORT
      LAYER M4 ;
      RECT 224.856 56.304 225.048 56.328 ;
    END
  END link_in[9]
  PIN link_in[10]
    DIRECTION INPUT ;
    USE SIGNAL ;
    SHAPE ABUTMENT ;
    PORT
      LAYER M4 ;
      RECT 224.856 56.400 225.048 56.424 ;
    END
  END link_in[10]
  PIN link_in[11]
    DIRECTION INPUT ;
    USE SIGNAL ;
    SHAPE ABUTMENT ;
    PORT
      LAYER M4 ;
      RECT 224.856 56.544 225.048 56.568 ;
    END
  END link_in[11]
  PIN link_in[12]
    DIRECTION INPUT ;
    USE SIGNAL ;
    SHAPE ABUTMENT ;
    PORT
      LAYER M4 ;
      RECT 224.856 56.640 225.048 56.664 ;
    END
  END link_in[12]
  PIN link_in[13]
    DIRECTION INPUT ;
    USE SIGNAL ;
    SHAPE ABUTMENT ;
    PORT
      LAYER M4 ;
      RECT 224.856 56.736 225.048 56.760 ;
    END
  END link_in[13]
  PIN link_in[14]
    DIRECTION INPUT ;
    USE SIGNAL ;
    SHAPE ABUTMENT ;
    PORT
      LAYER M4 ;
      RECT 224.856 56.832 225.048 56.856 ;
    END
  END link_in[14]
  PIN link_in[15]
    DIRECTION INPUT ;
    USE SIGNAL ;
    SHAPE ABUTMENT ;
    PORT
      LAYER M4 ;
      RECT 224.856 56.928 225.048 56.952 ;
    END
  END link_in[15]
  PIN link_in[16]
    DIRECTION INPUT ;
    USE SIGNAL ;
    SHAPE ABUTMENT ;
    PORT
      LAYER M4 ;
      RECT 224.856 57.072 225.048 57.096 ;
    END
  END link_in[16]
  PIN link_in[17]
    DIRECTION INPUT ;
    USE SIGNAL ;
    SHAPE ABUTMENT ;
    PORT
      LAYER M4 ;
      RECT 224.856 57.168 225.048 57.192 ;
    END
  END link_in[17]
  PIN link_in[18]
    DIRECTION INPUT ;
    USE SIGNAL ;
    SHAPE ABUTMENT ;
    PORT
      LAYER M4 ;
      RECT 224.856 57.264 225.048 57.288 ;
    END
  END link_in[18]
  PIN link_in[19]
    DIRECTION INPUT ;
    USE SIGNAL ;
    SHAPE ABUTMENT ;
    PORT
      LAYER M4 ;
      RECT 224.856 57.360 225.048 57.384 ;
    END
  END link_in[19]
  PIN link_in[20]
    DIRECTION INPUT ;
    USE SIGNAL ;
    SHAPE ABUTMENT ;
    PORT
      LAYER M4 ;
      RECT 224.856 57.504 225.048 57.528 ;
    END
  END link_in[20]
  PIN link_in[21]
    DIRECTION INPUT ;
    USE SIGNAL ;
    SHAPE ABUTMENT ;
    PORT
      LAYER M4 ;
      RECT 224.856 57.600 225.048 57.624 ;
    END
  END link_in[21]
  PIN link_in[22]
    DIRECTION INPUT ;
    USE SIGNAL ;
    SHAPE ABUTMENT ;
    PORT
      LAYER M4 ;
      RECT 224.856 57.696 225.048 57.720 ;
    END
  END link_in[22]
  PIN link_in[23]
    DIRECTION INPUT ;
    USE SIGNAL ;
    SHAPE ABUTMENT ;
    PORT
      LAYER M4 ;
      RECT 224.856 57.792 225.048 57.816 ;
    END
  END link_in[23]
  PIN link_in[24]
    DIRECTION INPUT ;
    USE SIGNAL ;
    SHAPE ABUTMENT ;
    PORT
      LAYER M4 ;
      RECT 224.856 57.936 225.048 57.960 ;
    END
  END link_in[24]
  PIN link_in[25]
    DIRECTION INPUT ;
    USE SIGNAL ;
    SHAPE ABUTMENT ;
    PORT
      LAYER M4 ;
      RECT 224.856 58.032 225.048 58.056 ;
    END
  END link_in[25]
  PIN link_in[26]
    DIRECTION INPUT ;
    USE SIGNAL ;
    SHAPE ABUTMENT ;
    PORT
      LAYER M4 ;
      RECT 224.856 58.128 225.048 58.152 ;
    END
  END link_in[26]
  PIN link_in[27]
    DIRECTION INPUT ;
    USE SIGNAL ;
    SHAPE ABUTMENT ;
    PORT
      LAYER M4 ;
      RECT 224.856 58.224 225.048 58.248 ;
    END
  END link_in[27]
  PIN link_in[28]
    DIRECTION INPUT ;
    USE SIGNAL ;
    SHAPE ABUTMENT ;
    PORT
      LAYER M4 ;
      RECT 224.856 58.320 225.048 58.344 ;
    END
  END link_in[28]
  PIN link_in[29]
    DIRECTION INPUT ;
    USE SIGNAL ;
    SHAPE ABUTMENT ;
    PORT
      LAYER M4 ;
      RECT 224.856 58.464 225.048 58.488 ;
    END
  END link_in[29]
  PIN link_in[30]
    DIRECTION INPUT ;
    USE SIGNAL ;
    SHAPE ABUTMENT ;
    PORT
      LAYER M4 ;
      RECT 224.856 58.560 225.048 58.584 ;
    END
  END link_in[30]
  PIN link_in[31]
    DIRECTION INPUT ;
    USE SIGNAL ;
    SHAPE ABUTMENT ;
    PORT
      LAYER M4 ;
      RECT 224.856 58.656 225.048 58.680 ;
    END
  END link_in[31]
  PIN link_in[32]
    DIRECTION INPUT ;
    USE SIGNAL ;
    SHAPE ABUTMENT ;
    PORT
      LAYER M4 ;
      RECT 224.856 58.752 225.048 58.776 ;
    END
  END link_in[32]
  PIN link_in[33]
    DIRECTION INPUT ;
    USE SIGNAL ;
    SHAPE ABUTMENT ;
    PORT
      LAYER M4 ;
      RECT 224.856 58.896 225.048 58.920 ;
    END
  END link_in[33]
  PIN link_in[34]
    DIRECTION INPUT ;
    USE SIGNAL ;
    SHAPE ABUTMENT ;
    PORT
      LAYER M4 ;
      RECT 224.856 58.992 225.048 59.016 ;
    END
  END link_in[34]
  PIN link_in[35]
    DIRECTION INPUT ;
    USE SIGNAL ;
    SHAPE ABUTMENT ;
    PORT
      LAYER M4 ;
      RECT 224.856 59.088 225.048 59.112 ;
    END
  END link_in[35]
  PIN link_in[36]
    DIRECTION INPUT ;
    USE SIGNAL ;
    SHAPE ABUTMENT ;
    PORT
      LAYER M4 ;
      RECT 224.856 59.184 225.048 59.208 ;
    END
  END link_in[36]
  PIN link_in[37]
    DIRECTION INPUT ;
    USE SIGNAL ;
    SHAPE ABUTMENT ;
    PORT
      LAYER M4 ;
      RECT 224.856 59.328 225.048 59.352 ;
    END
  END link_in[37]
  PIN link_in[38]
    DIRECTION INPUT ;
    USE SIGNAL ;
    SHAPE ABUTMENT ;
    PORT
      LAYER M4 ;
      RECT 224.856 59.424 225.048 59.448 ;
    END
  END link_in[38]
  PIN link_in[39]
    DIRECTION INPUT ;
    USE SIGNAL ;
    SHAPE ABUTMENT ;
    PORT
      LAYER M4 ;
      RECT 224.856 59.520 225.048 59.544 ;
    END
  END link_in[39]
  PIN link_in[40]
    DIRECTION INPUT ;
    USE SIGNAL ;
    SHAPE ABUTMENT ;
    PORT
      LAYER M4 ;
      RECT 224.856 59.616 225.048 59.640 ;
    END
  END link_in[40]
  PIN link_in[41]
    DIRECTION INPUT ;
    USE SIGNAL ;
    SHAPE ABUTMENT ;
    PORT
      LAYER M4 ;
      RECT 224.856 59.712 225.048 59.736 ;
    END
  END link_in[41]
  PIN link_in[42]
    DIRECTION INPUT ;
    USE SIGNAL ;
    SHAPE ABUTMENT ;
    PORT
      LAYER M4 ;
      RECT 224.856 59.856 225.048 59.880 ;
    END
  END link_in[42]
  PIN link_in[43]
    DIRECTION INPUT ;
    USE SIGNAL ;
    SHAPE ABUTMENT ;
    PORT
      LAYER M4 ;
      RECT 224.856 59.952 225.048 59.976 ;
    END
  END link_in[43]
  PIN link_in[44]
    DIRECTION INPUT ;
    USE SIGNAL ;
    SHAPE ABUTMENT ;
    PORT
      LAYER M4 ;
      RECT 224.856 60.048 225.048 60.072 ;
    END
  END link_in[44]
  PIN link_in[45]
    DIRECTION INPUT ;
    USE SIGNAL ;
    SHAPE ABUTMENT ;
    PORT
      LAYER M4 ;
      RECT 224.856 60.144 225.048 60.168 ;
    END
  END link_in[45]
  PIN link_in[46]
    DIRECTION INPUT ;
    USE SIGNAL ;
    SHAPE ABUTMENT ;
    PORT
      LAYER M4 ;
      RECT 224.856 60.288 225.048 60.312 ;
    END
  END link_in[46]
  PIN link_in[47]
    DIRECTION INPUT ;
    USE SIGNAL ;
    SHAPE ABUTMENT ;
    PORT
      LAYER M4 ;
      RECT 224.856 60.384 225.048 60.408 ;
    END
  END link_in[47]
  PIN link_in[48]
    DIRECTION INPUT ;
    USE SIGNAL ;
    SHAPE ABUTMENT ;
    PORT
      LAYER M4 ;
      RECT 224.856 60.480 225.048 60.504 ;
    END
  END link_in[48]
  PIN link_in[49]
    DIRECTION INPUT ;
    USE SIGNAL ;
    SHAPE ABUTMENT ;
    PORT
      LAYER M4 ;
      RECT 224.856 60.576 225.048 60.600 ;
    END
  END link_in[49]
  PIN link_in[50]
    DIRECTION INPUT ;
    USE SIGNAL ;
    SHAPE ABUTMENT ;
    PORT
      LAYER M4 ;
      RECT 224.856 60.720 225.048 60.744 ;
    END
  END link_in[50]
  PIN link_in[51]
    DIRECTION INPUT ;
    USE SIGNAL ;
    SHAPE ABUTMENT ;
    PORT
      LAYER M4 ;
      RECT 224.856 60.816 225.048 60.840 ;
    END
  END link_in[51]
  PIN link_in[52]
    DIRECTION INPUT ;
    USE SIGNAL ;
    SHAPE ABUTMENT ;
    PORT
      LAYER M4 ;
      RECT 224.856 60.912 225.048 60.936 ;
    END
  END link_in[52]
  PIN link_in[53]
    DIRECTION INPUT ;
    USE SIGNAL ;
    SHAPE ABUTMENT ;
    PORT
      LAYER M4 ;
      RECT 224.856 61.008 225.048 61.032 ;
    END
  END link_in[53]
  PIN link_in[54]
    DIRECTION INPUT ;
    USE SIGNAL ;
    SHAPE ABUTMENT ;
    PORT
      LAYER M4 ;
      RECT 224.856 61.104 225.048 61.128 ;
    END
  END link_in[54]
  PIN link_in[55]
    DIRECTION INPUT ;
    USE SIGNAL ;
    SHAPE ABUTMENT ;
    PORT
      LAYER M4 ;
      RECT 224.856 61.248 225.048 61.272 ;
    END
  END link_in[55]
  PIN link_in[56]
    DIRECTION INPUT ;
    USE SIGNAL ;
    SHAPE ABUTMENT ;
    PORT
      LAYER M4 ;
      RECT 224.856 61.344 225.048 61.368 ;
    END
  END link_in[56]
  PIN link_in[57]
    DIRECTION INPUT ;
    USE SIGNAL ;
    SHAPE ABUTMENT ;
    PORT
      LAYER M4 ;
      RECT 224.856 61.440 225.048 61.464 ;
    END
  END link_in[57]
  PIN link_in[58]
    DIRECTION INPUT ;
    USE SIGNAL ;
    SHAPE ABUTMENT ;
    PORT
      LAYER M4 ;
      RECT 224.856 61.536 225.048 61.560 ;
    END
  END link_in[58]
  PIN link_in[59]
    DIRECTION INPUT ;
    USE SIGNAL ;
    SHAPE ABUTMENT ;
    PORT
      LAYER M4 ;
      RECT 224.856 61.680 225.048 61.704 ;
    END
  END link_in[59]
  PIN link_in[60]
    DIRECTION INPUT ;
    USE SIGNAL ;
    SHAPE ABUTMENT ;
    PORT
      LAYER M4 ;
      RECT 224.856 61.776 225.048 61.800 ;
    END
  END link_in[60]
  PIN link_in[61]
    DIRECTION INPUT ;
    USE SIGNAL ;
    SHAPE ABUTMENT ;
    PORT
      LAYER M4 ;
      RECT 224.856 61.872 225.048 61.896 ;
    END
  END link_in[61]
  PIN link_in[62]
    DIRECTION INPUT ;
    USE SIGNAL ;
    SHAPE ABUTMENT ;
    PORT
      LAYER M4 ;
      RECT 224.856 61.968 225.048 61.992 ;
    END
  END link_in[62]
  PIN link_in[63]
    DIRECTION INPUT ;
    USE SIGNAL ;
    SHAPE ABUTMENT ;
    PORT
      LAYER M4 ;
      RECT 224.856 62.112 225.048 62.136 ;
    END
  END link_in[63]
  PIN link_in[64]
    DIRECTION INPUT ;
    USE SIGNAL ;
    SHAPE ABUTMENT ;
    PORT
      LAYER M4 ;
      RECT 224.856 62.208 225.048 62.232 ;
    END
  END link_in[64]
  PIN link_in[65]
    DIRECTION INPUT ;
    USE SIGNAL ;
    SHAPE ABUTMENT ;
    PORT
      LAYER M4 ;
      RECT 224.856 62.304 225.048 62.328 ;
    END
  END link_in[65]
  PIN link_in[66]
    DIRECTION INPUT ;
    USE SIGNAL ;
    SHAPE ABUTMENT ;
    PORT
      LAYER M4 ;
      RECT 224.856 62.400 225.048 62.424 ;
    END
  END link_in[66]
  PIN link_in[67]
    DIRECTION INPUT ;
    USE SIGNAL ;
    SHAPE ABUTMENT ;
    PORT
      LAYER M4 ;
      RECT 224.856 62.544 225.048 62.568 ;
    END
  END link_in[67]
  PIN link_in[68]
    DIRECTION INPUT ;
    USE SIGNAL ;
    SHAPE ABUTMENT ;
    PORT
      LAYER M4 ;
      RECT 224.856 62.640 225.048 62.664 ;
    END
  END link_in[68]
  PIN link_in[69]
    DIRECTION INPUT ;
    USE SIGNAL ;
    SHAPE ABUTMENT ;
    PORT
      LAYER M4 ;
      RECT 224.856 62.736 225.048 62.760 ;
    END
  END link_in[69]
  PIN link_in[70]
    DIRECTION INPUT ;
    USE SIGNAL ;
    SHAPE ABUTMENT ;
    PORT
      LAYER M4 ;
      RECT 224.856 62.832 225.048 62.856 ;
    END
  END link_in[70]
  PIN link_in[71]
    DIRECTION INPUT ;
    USE SIGNAL ;
    SHAPE ABUTMENT ;
    PORT
      LAYER M4 ;
      RECT 224.856 62.928 225.048 62.952 ;
    END
  END link_in[71]
  PIN link_in[72]
    DIRECTION INPUT ;
    USE SIGNAL ;
    SHAPE ABUTMENT ;
    PORT
      LAYER M4 ;
      RECT 224.856 63.072 225.048 63.096 ;
    END
  END link_in[72]
  PIN link_in[73]
    DIRECTION INPUT ;
    USE SIGNAL ;
    SHAPE ABUTMENT ;
    PORT
      LAYER M4 ;
      RECT 224.856 63.168 225.048 63.192 ;
    END
  END link_in[73]
  PIN link_in[74]
    DIRECTION INPUT ;
    USE SIGNAL ;
    SHAPE ABUTMENT ;
    PORT
      LAYER M4 ;
      RECT 224.856 63.264 225.048 63.288 ;
    END
  END link_in[74]
  PIN link_in[75]
    DIRECTION INPUT ;
    USE SIGNAL ;
    SHAPE ABUTMENT ;
    PORT
      LAYER M4 ;
      RECT 224.856 63.360 225.048 63.384 ;
    END
  END link_in[75]
  PIN link_in[76]
    DIRECTION INPUT ;
    USE SIGNAL ;
    SHAPE ABUTMENT ;
    PORT
      LAYER M4 ;
      RECT 224.856 63.504 225.048 63.528 ;
    END
  END link_in[76]
  PIN link_in[77]
    DIRECTION INPUT ;
    USE SIGNAL ;
    SHAPE ABUTMENT ;
    PORT
      LAYER M4 ;
      RECT 224.856 63.600 225.048 63.624 ;
    END
  END link_in[77]
  PIN link_in[78]
    DIRECTION INPUT ;
    USE SIGNAL ;
    SHAPE ABUTMENT ;
    PORT
      LAYER M4 ;
      RECT 224.856 63.696 225.048 63.720 ;
    END
  END link_in[78]
  PIN link_in[79]
    DIRECTION INPUT ;
    USE SIGNAL ;
    SHAPE ABUTMENT ;
    PORT
      LAYER M4 ;
      RECT 224.856 63.792 225.048 63.816 ;
    END
  END link_in[79]
  PIN link_in[80]
    DIRECTION INPUT ;
    USE SIGNAL ;
    SHAPE ABUTMENT ;
    PORT
      LAYER M4 ;
      RECT 224.856 63.936 225.048 63.960 ;
    END
  END link_in[80]
  PIN link_in[81]
    DIRECTION INPUT ;
    USE SIGNAL ;
    SHAPE ABUTMENT ;
    PORT
      LAYER M4 ;
      RECT 224.856 64.032 225.048 64.056 ;
    END
  END link_in[81]
  PIN link_in[82]
    DIRECTION INPUT ;
    USE SIGNAL ;
    SHAPE ABUTMENT ;
    PORT
      LAYER M4 ;
      RECT 224.856 64.128 225.048 64.152 ;
    END
  END link_in[82]
  PIN link_in[83]
    DIRECTION INPUT ;
    USE SIGNAL ;
    SHAPE ABUTMENT ;
    PORT
      LAYER M4 ;
      RECT 224.856 64.224 225.048 64.248 ;
    END
  END link_in[83]
  PIN link_in[84]
    DIRECTION INPUT ;
    USE SIGNAL ;
    SHAPE ABUTMENT ;
    PORT
      LAYER M4 ;
      RECT 224.856 64.320 225.048 64.344 ;
    END
  END link_in[84]
  PIN link_in[85]
    DIRECTION INPUT ;
    USE SIGNAL ;
    SHAPE ABUTMENT ;
    PORT
      LAYER M4 ;
      RECT 224.856 64.464 225.048 64.488 ;
    END
  END link_in[85]
  PIN link_in[86]
    DIRECTION INPUT ;
    USE SIGNAL ;
    SHAPE ABUTMENT ;
    PORT
      LAYER M4 ;
      RECT 224.856 64.560 225.048 64.584 ;
    END
  END link_in[86]
  PIN link_in[87]
    DIRECTION INPUT ;
    USE SIGNAL ;
    SHAPE ABUTMENT ;
    PORT
      LAYER M4 ;
      RECT 224.856 64.656 225.048 64.680 ;
    END
  END link_in[87]
  PIN link_in[88]
    DIRECTION INPUT ;
    USE SIGNAL ;
    SHAPE ABUTMENT ;
    PORT
      LAYER M4 ;
      RECT 224.856 64.752 225.048 64.776 ;
    END
  END link_in[88]
  PIN link_in[89]
    DIRECTION INPUT ;
    USE SIGNAL ;
    SHAPE ABUTMENT ;
    PORT
      LAYER M4 ;
      RECT 224.856 64.896 225.048 64.920 ;
    END
  END link_in[89]
  PIN link_in[90]
    DIRECTION INPUT ;
    USE SIGNAL ;
    SHAPE ABUTMENT ;
    PORT
      LAYER M4 ;
      RECT 224.856 64.992 225.048 65.016 ;
    END
  END link_in[90]
  PIN link_in[91]
    DIRECTION INPUT ;
    USE SIGNAL ;
    SHAPE ABUTMENT ;
    PORT
      LAYER M4 ;
      RECT 224.856 65.088 225.048 65.112 ;
    END
  END link_in[91]
  PIN link_in[92]
    DIRECTION INPUT ;
    USE SIGNAL ;
    SHAPE ABUTMENT ;
    PORT
      LAYER M4 ;
      RECT 224.856 65.184 225.048 65.208 ;
    END
  END link_in[92]
  PIN link_in[93]
    DIRECTION INPUT ;
    USE SIGNAL ;
    SHAPE ABUTMENT ;
    PORT
      LAYER M4 ;
      RECT 224.856 65.328 225.048 65.352 ;
    END
  END link_in[93]
  PIN link_in[94]
    DIRECTION INPUT ;
    USE SIGNAL ;
    SHAPE ABUTMENT ;
    PORT
      LAYER M4 ;
      RECT 224.856 65.424 225.048 65.448 ;
    END
  END link_in[94]
  PIN link_in[95]
    DIRECTION INPUT ;
    USE SIGNAL ;
    SHAPE ABUTMENT ;
    PORT
      LAYER M4 ;
      RECT 224.856 65.520 225.048 65.544 ;
    END
  END link_in[95]
  PIN link_in[96]
    DIRECTION INPUT ;
    USE SIGNAL ;
    SHAPE ABUTMENT ;
    PORT
      LAYER M4 ;
      RECT 224.856 65.616 225.048 65.640 ;
    END
  END link_in[96]
  PIN link_in[97]
    DIRECTION INPUT ;
    USE SIGNAL ;
    SHAPE ABUTMENT ;
    PORT
      LAYER M4 ;
      RECT 224.856 65.712 225.048 65.736 ;
    END
  END link_in[97]
  PIN link_in[98]
    DIRECTION INPUT ;
    USE SIGNAL ;
    SHAPE ABUTMENT ;
    PORT
      LAYER M4 ;
      RECT 224.856 65.856 225.048 65.880 ;
    END
  END link_in[98]
  PIN link_in[99]
    DIRECTION INPUT ;
    USE SIGNAL ;
    SHAPE ABUTMENT ;
    PORT
      LAYER M4 ;
      RECT 224.856 65.952 225.048 65.976 ;
    END
  END link_in[99]
  PIN link_in[100]
    DIRECTION INPUT ;
    USE SIGNAL ;
    SHAPE ABUTMENT ;
    PORT
      LAYER M4 ;
      RECT 224.856 66.048 225.048 66.072 ;
    END
  END link_in[100]
  PIN link_in[101]
    DIRECTION INPUT ;
    USE SIGNAL ;
    SHAPE ABUTMENT ;
    PORT
      LAYER M4 ;
      RECT 224.856 66.144 225.048 66.168 ;
    END
  END link_in[101]
  PIN link_in[102]
    DIRECTION INPUT ;
    USE SIGNAL ;
    SHAPE ABUTMENT ;
    PORT
      LAYER M4 ;
      RECT 224.856 66.288 225.048 66.312 ;
    END
  END link_in[102]
  PIN link_in[103]
    DIRECTION INPUT ;
    USE SIGNAL ;
    SHAPE ABUTMENT ;
    PORT
      LAYER M4 ;
      RECT 224.856 66.384 225.048 66.408 ;
    END
  END link_in[103]
  PIN link_in[104]
    DIRECTION INPUT ;
    USE SIGNAL ;
    SHAPE ABUTMENT ;
    PORT
      LAYER M4 ;
      RECT 224.856 66.480 225.048 66.504 ;
    END
  END link_in[104]
  PIN link_in[105]
    DIRECTION INPUT ;
    USE SIGNAL ;
    SHAPE ABUTMENT ;
    PORT
      LAYER M4 ;
      RECT 224.856 66.576 225.048 66.600 ;
    END
  END link_in[105]
  PIN link_in[106]
    DIRECTION INPUT ;
    USE SIGNAL ;
    SHAPE ABUTMENT ;
    PORT
      LAYER M4 ;
      RECT 224.856 66.720 225.048 66.744 ;
    END
  END link_in[106]
  PIN link_in[107]
    DIRECTION INPUT ;
    USE SIGNAL ;
    SHAPE ABUTMENT ;
    PORT
      LAYER M4 ;
      RECT 224.856 66.816 225.048 66.840 ;
    END
  END link_in[107]
  PIN link_in[108]
    DIRECTION INPUT ;
    USE SIGNAL ;
    SHAPE ABUTMENT ;
    PORT
      LAYER M4 ;
      RECT 224.856 66.912 225.048 66.936 ;
    END
  END link_in[108]
  PIN link_in[109]
    DIRECTION INPUT ;
    USE SIGNAL ;
    SHAPE ABUTMENT ;
    PORT
      LAYER M4 ;
      RECT 224.856 67.008 225.048 67.032 ;
    END
  END link_in[109]
  PIN link_in[110]
    DIRECTION INPUT ;
    USE SIGNAL ;
    SHAPE ABUTMENT ;
    PORT
      LAYER M4 ;
      RECT 224.856 67.104 225.048 67.128 ;
    END
  END link_in[110]
  PIN link_in[111]
    DIRECTION INPUT ;
    USE SIGNAL ;
    SHAPE ABUTMENT ;
    PORT
      LAYER M4 ;
      RECT 224.856 67.248 225.048 67.272 ;
    END
  END link_in[111]
  PIN link_in[112]
    DIRECTION INPUT ;
    USE SIGNAL ;
    SHAPE ABUTMENT ;
    PORT
      LAYER M4 ;
      RECT 224.856 67.344 225.048 67.368 ;
    END
  END link_in[112]
  PIN link_in[113]
    DIRECTION INPUT ;
    USE SIGNAL ;
    SHAPE ABUTMENT ;
    PORT
      LAYER M4 ;
      RECT 224.856 67.440 225.048 67.464 ;
    END
  END link_in[113]
  PIN link_in[114]
    DIRECTION INPUT ;
    USE SIGNAL ;
    SHAPE ABUTMENT ;
    PORT
      LAYER M4 ;
      RECT 224.856 67.536 225.048 67.560 ;
    END
  END link_in[114]
  PIN link_in[115]
    DIRECTION INPUT ;
    USE SIGNAL ;
    SHAPE ABUTMENT ;
    PORT
      LAYER M4 ;
      RECT 224.856 67.680 225.048 67.704 ;
    END
  END link_in[115]
  PIN link_in[116]
    DIRECTION INPUT ;
    USE SIGNAL ;
    SHAPE ABUTMENT ;
    PORT
      LAYER M4 ;
      RECT 224.856 67.776 225.048 67.800 ;
    END
  END link_in[116]
  PIN link_in[117]
    DIRECTION INPUT ;
    USE SIGNAL ;
    SHAPE ABUTMENT ;
    PORT
      LAYER M4 ;
      RECT 224.856 67.872 225.048 67.896 ;
    END
  END link_in[117]
  PIN link_in[118]
    DIRECTION INPUT ;
    USE SIGNAL ;
    SHAPE ABUTMENT ;
    PORT
      LAYER M4 ;
      RECT 224.856 67.968 225.048 67.992 ;
    END
  END link_in[118]
  PIN link_in[119]
    DIRECTION INPUT ;
    USE SIGNAL ;
    SHAPE ABUTMENT ;
    PORT
      LAYER M4 ;
      RECT 224.856 68.112 225.048 68.136 ;
    END
  END link_in[119]
  PIN link_in[120]
    DIRECTION INPUT ;
    USE SIGNAL ;
    SHAPE ABUTMENT ;
    PORT
      LAYER M4 ;
      RECT 224.856 68.208 225.048 68.232 ;
    END
  END link_in[120]
  PIN link_in[121]
    DIRECTION INPUT ;
    USE SIGNAL ;
    SHAPE ABUTMENT ;
    PORT
      LAYER M4 ;
      RECT 224.856 68.304 225.048 68.328 ;
    END
  END link_in[121]
  PIN link_in[122]
    DIRECTION INPUT ;
    USE SIGNAL ;
    SHAPE ABUTMENT ;
    PORT
      LAYER M4 ;
      RECT 224.856 68.400 225.048 68.424 ;
    END
  END link_in[122]
  PIN link_in[123]
    DIRECTION INPUT ;
    USE SIGNAL ;
    SHAPE ABUTMENT ;
    PORT
      LAYER M4 ;
      RECT 224.856 68.496 225.048 68.520 ;
    END
  END link_in[123]
  PIN link_in[124]
    DIRECTION INPUT ;
    USE SIGNAL ;
    SHAPE ABUTMENT ;
    PORT
      LAYER M4 ;
      RECT 224.856 68.640 225.048 68.664 ;
    END
  END link_in[124]
  PIN link_in[125]
    DIRECTION INPUT ;
    USE SIGNAL ;
    SHAPE ABUTMENT ;
    PORT
      LAYER M4 ;
      RECT 224.856 68.736 225.048 68.760 ;
    END
  END link_in[125]
  PIN link_in[126]
    DIRECTION INPUT ;
    USE SIGNAL ;
    SHAPE ABUTMENT ;
    PORT
      LAYER M4 ;
      RECT 224.856 68.832 225.048 68.856 ;
    END
  END link_in[126]
  PIN link_in[127]
    DIRECTION INPUT ;
    USE SIGNAL ;
    SHAPE ABUTMENT ;
    PORT
      LAYER M4 ;
      RECT 224.856 68.928 225.048 68.952 ;
    END
  END link_in[127]
  PIN link_in[128]
    DIRECTION INPUT ;
    USE SIGNAL ;
    SHAPE ABUTMENT ;
    PORT
      LAYER M4 ;
      RECT 224.856 69.072 225.048 69.096 ;
    END
  END link_in[128]
  PIN link_in[129]
    DIRECTION INPUT ;
    USE SIGNAL ;
    SHAPE ABUTMENT ;
    PORT
      LAYER M4 ;
      RECT 224.856 69.168 225.048 69.192 ;
    END
  END link_in[129]
  PIN link_in[130]
    DIRECTION INPUT ;
    USE SIGNAL ;
    SHAPE ABUTMENT ;
    PORT
      LAYER M4 ;
      RECT 224.856 69.264 225.048 69.288 ;
    END
  END link_in[130]
  PIN link_in[131]
    DIRECTION INPUT ;
    USE SIGNAL ;
    SHAPE ABUTMENT ;
    PORT
      LAYER M4 ;
      RECT 224.856 69.360 225.048 69.384 ;
    END
  END link_in[131]
  PIN link_in[132]
    DIRECTION INPUT ;
    USE SIGNAL ;
    SHAPE ABUTMENT ;
    PORT
      LAYER M4 ;
      RECT 224.856 69.504 225.048 69.528 ;
    END
  END link_in[132]
  PIN link_in[133]
    DIRECTION INPUT ;
    USE SIGNAL ;
    SHAPE ABUTMENT ;
    PORT
      LAYER M4 ;
      RECT 224.856 69.600 225.048 69.624 ;
    END
  END link_in[133]
  PIN link_in[134]
    DIRECTION INPUT ;
    USE SIGNAL ;
    SHAPE ABUTMENT ;
    PORT
      LAYER M4 ;
      RECT 224.856 69.696 225.048 69.720 ;
    END
  END link_in[134]
  PIN link_in[135]
    DIRECTION INPUT ;
    USE SIGNAL ;
    SHAPE ABUTMENT ;
    PORT
      LAYER M4 ;
      RECT 224.856 69.792 225.048 69.816 ;
    END
  END link_in[135]
  PIN link_in[136]
    DIRECTION INPUT ;
    USE SIGNAL ;
    SHAPE ABUTMENT ;
    PORT
      LAYER M4 ;
      RECT 224.856 69.888 225.048 69.912 ;
    END
  END link_in[136]
  PIN link_in[137]
    DIRECTION INPUT ;
    USE SIGNAL ;
    SHAPE ABUTMENT ;
    PORT
      LAYER M4 ;
      RECT 224.856 70.032 225.048 70.056 ;
    END
  END link_in[137]
  PIN link_in[138]
    DIRECTION INPUT ;
    USE SIGNAL ;
    SHAPE ABUTMENT ;
    PORT
      LAYER M4 ;
      RECT 224.856 70.128 225.048 70.152 ;
    END
  END link_in[138]
  PIN link_in[139]
    DIRECTION INPUT ;
    USE SIGNAL ;
    SHAPE ABUTMENT ;
    PORT
      LAYER M4 ;
      RECT 224.856 70.224 225.048 70.248 ;
    END
  END link_in[139]
  PIN link_in[140]
    DIRECTION INPUT ;
    USE SIGNAL ;
    SHAPE ABUTMENT ;
    PORT
      LAYER M4 ;
      RECT 224.856 70.320 225.048 70.344 ;
    END
  END link_in[140]
  PIN link_in[141]
    DIRECTION INPUT ;
    USE SIGNAL ;
    SHAPE ABUTMENT ;
    PORT
      LAYER M4 ;
      RECT 224.856 70.464 225.048 70.488 ;
    END
  END link_in[141]
  PIN link_in[142]
    DIRECTION INPUT ;
    USE SIGNAL ;
    SHAPE ABUTMENT ;
    PORT
      LAYER M4 ;
      RECT 224.856 70.560 225.048 70.584 ;
    END
  END link_in[142]
  PIN link_in[143]
    DIRECTION INPUT ;
    USE SIGNAL ;
    SHAPE ABUTMENT ;
    PORT
      LAYER M4 ;
      RECT 224.856 70.656 225.048 70.680 ;
    END
  END link_in[143]
  PIN link_in[144]
    DIRECTION INPUT ;
    USE SIGNAL ;
    SHAPE ABUTMENT ;
    PORT
      LAYER M4 ;
      RECT 224.856 70.752 225.048 70.776 ;
    END
  END link_in[144]
  PIN link_in[145]
    DIRECTION INPUT ;
    USE SIGNAL ;
    SHAPE ABUTMENT ;
    PORT
      LAYER M4 ;
      RECT 224.856 70.896 225.048 70.920 ;
    END
  END link_in[145]
  PIN link_in[146]
    DIRECTION INPUT ;
    USE SIGNAL ;
    SHAPE ABUTMENT ;
    PORT
      LAYER M4 ;
      RECT 224.856 70.992 225.048 71.016 ;
    END
  END link_in[146]
  PIN link_in[147]
    DIRECTION INPUT ;
    USE SIGNAL ;
    SHAPE ABUTMENT ;
    PORT
      LAYER M4 ;
      RECT 224.856 71.088 225.048 71.112 ;
    END
  END link_in[147]
  PIN link_in[148]
    DIRECTION INPUT ;
    USE SIGNAL ;
    SHAPE ABUTMENT ;
    PORT
      LAYER M4 ;
      RECT 224.856 71.184 225.048 71.208 ;
    END
  END link_in[148]
  PIN link_in[149]
    DIRECTION INPUT ;
    USE SIGNAL ;
    SHAPE ABUTMENT ;
    PORT
      LAYER M4 ;
      RECT 224.856 71.280 225.048 71.304 ;
    END
  END link_in[149]
  PIN link_in[150]
    DIRECTION INPUT ;
    USE SIGNAL ;
    SHAPE ABUTMENT ;
    PORT
      LAYER M4 ;
      RECT 224.856 71.424 225.048 71.448 ;
    END
  END link_in[150]
  PIN link_in[151]
    DIRECTION INPUT ;
    USE SIGNAL ;
    SHAPE ABUTMENT ;
    PORT
      LAYER M4 ;
      RECT 224.856 71.520 225.048 71.544 ;
    END
  END link_in[151]
  PIN link_in[152]
    DIRECTION INPUT ;
    USE SIGNAL ;
    SHAPE ABUTMENT ;
    PORT
      LAYER M4 ;
      RECT 224.856 71.616 225.048 71.640 ;
    END
  END link_in[152]
  PIN link_in[153]
    DIRECTION INPUT ;
    USE SIGNAL ;
    SHAPE ABUTMENT ;
    PORT
      LAYER M4 ;
      RECT 224.856 71.712 225.048 71.736 ;
    END
  END link_in[153]
  PIN link_in[154]
    DIRECTION INPUT ;
    USE SIGNAL ;
    SHAPE ABUTMENT ;
    PORT
      LAYER M4 ;
      RECT 224.856 71.856 225.048 71.880 ;
    END
  END link_in[154]
  PIN link_in[155]
    DIRECTION INPUT ;
    USE SIGNAL ;
    SHAPE ABUTMENT ;
    PORT
      LAYER M4 ;
      RECT 224.856 71.952 225.048 71.976 ;
    END
  END link_in[155]
  PIN link_in[156]
    DIRECTION INPUT ;
    USE SIGNAL ;
    SHAPE ABUTMENT ;
    PORT
      LAYER M4 ;
      RECT 224.856 72.048 225.048 72.072 ;
    END
  END link_in[156]
  PIN link_in[157]
    DIRECTION INPUT ;
    USE SIGNAL ;
    SHAPE ABUTMENT ;
    PORT
      LAYER M4 ;
      RECT 224.856 72.144 225.048 72.168 ;
    END
  END link_in[157]
  PIN link_in[158]
    DIRECTION INPUT ;
    USE SIGNAL ;
    SHAPE ABUTMENT ;
    PORT
      LAYER M4 ;
      RECT 224.856 72.288 225.048 72.312 ;
    END
  END link_in[158]
  PIN link_in[159]
    DIRECTION INPUT ;
    USE SIGNAL ;
    SHAPE ABUTMENT ;
    PORT
      LAYER M4 ;
      RECT 224.856 72.384 225.048 72.408 ;
    END
  END link_in[159]
  PIN link_in[160]
    DIRECTION INPUT ;
    USE SIGNAL ;
    SHAPE ABUTMENT ;
    PORT
      LAYER M4 ;
      RECT 224.856 72.480 225.048 72.504 ;
    END
  END link_in[160]
  PIN link_in[161]
    DIRECTION INPUT ;
    USE SIGNAL ;
    SHAPE ABUTMENT ;
    PORT
      LAYER M4 ;
      RECT 224.856 72.576 225.048 72.600 ;
    END
  END link_in[161]
  PIN link_in[162]
    DIRECTION INPUT ;
    USE SIGNAL ;
    SHAPE ABUTMENT ;
    PORT
      LAYER M4 ;
      RECT 224.856 72.672 225.048 72.696 ;
    END
  END link_in[162]
  PIN link_in[163]
    DIRECTION INPUT ;
    USE SIGNAL ;
    SHAPE ABUTMENT ;
    PORT
      LAYER M4 ;
      RECT 224.856 72.816 225.048 72.840 ;
    END
  END link_in[163]
  PIN link_in[164]
    DIRECTION INPUT ;
    USE SIGNAL ;
    SHAPE ABUTMENT ;
    PORT
      LAYER M4 ;
      RECT 224.856 72.912 225.048 72.936 ;
    END
  END link_in[164]
  PIN link_in[165]
    DIRECTION INPUT ;
    USE SIGNAL ;
    SHAPE ABUTMENT ;
    PORT
      LAYER M4 ;
      RECT 224.856 73.008 225.048 73.032 ;
    END
  END link_in[165]
  PIN link_in[166]
    DIRECTION INPUT ;
    USE SIGNAL ;
    SHAPE ABUTMENT ;
    PORT
      LAYER M4 ;
      RECT 224.856 73.104 225.048 73.128 ;
    END
  END link_in[166]
  PIN link_in[167]
    DIRECTION INPUT ;
    USE SIGNAL ;
    SHAPE ABUTMENT ;
    PORT
      LAYER M4 ;
      RECT 224.856 73.248 225.048 73.272 ;
    END
  END link_in[167]
  PIN link_in[168]
    DIRECTION INPUT ;
    USE SIGNAL ;
    SHAPE ABUTMENT ;
    PORT
      LAYER M4 ;
      RECT 224.856 73.344 225.048 73.368 ;
    END
  END link_in[168]
  PIN link_in[169]
    DIRECTION INPUT ;
    USE SIGNAL ;
    SHAPE ABUTMENT ;
    PORT
      LAYER M4 ;
      RECT 224.856 73.440 225.048 73.464 ;
    END
  END link_in[169]
  PIN link_in[170]
    DIRECTION INPUT ;
    USE SIGNAL ;
    SHAPE ABUTMENT ;
    PORT
      LAYER M4 ;
      RECT 224.856 73.536 225.048 73.560 ;
    END
  END link_in[170]
  PIN link_in[171]
    DIRECTION INPUT ;
    USE SIGNAL ;
    SHAPE ABUTMENT ;
    PORT
      LAYER M4 ;
      RECT 224.856 73.680 225.048 73.704 ;
    END
  END link_in[171]
  PIN link_in[172]
    DIRECTION INPUT ;
    USE SIGNAL ;
    SHAPE ABUTMENT ;
    PORT
      LAYER M4 ;
      RECT 224.856 73.776 225.048 73.800 ;
    END
  END link_in[172]
  PIN link_in[173]
    DIRECTION INPUT ;
    USE SIGNAL ;
    SHAPE ABUTMENT ;
    PORT
      LAYER M4 ;
      RECT 224.856 73.872 225.048 73.896 ;
    END
  END link_in[173]
  PIN link_in[174]
    DIRECTION INPUT ;
    USE SIGNAL ;
    SHAPE ABUTMENT ;
    PORT
      LAYER M4 ;
      RECT 224.856 73.968 225.048 73.992 ;
    END
  END link_in[174]
  PIN link_in[175]
    DIRECTION INPUT ;
    USE SIGNAL ;
    SHAPE ABUTMENT ;
    PORT
      LAYER M4 ;
      RECT 224.856 74.112 225.048 74.136 ;
    END
  END link_in[175]
  PIN link_in[176]
    DIRECTION INPUT ;
    USE SIGNAL ;
    SHAPE ABUTMENT ;
    PORT
      LAYER M4 ;
      RECT 224.856 74.208 225.048 74.232 ;
    END
  END link_in[176]
  PIN link_in[177]
    DIRECTION INPUT ;
    USE SIGNAL ;
    SHAPE ABUTMENT ;
    PORT
      LAYER M4 ;
      RECT 224.856 74.304 225.048 74.328 ;
    END
  END link_in[177]
  PIN link_in[178]
    DIRECTION INPUT ;
    USE SIGNAL ;
    SHAPE ABUTMENT ;
    PORT
      LAYER M4 ;
      RECT 224.856 74.400 225.048 74.424 ;
    END
  END link_in[178]
  PIN link_in[179]
    DIRECTION INPUT ;
    USE SIGNAL ;
    SHAPE ABUTMENT ;
    PORT
      LAYER M4 ;
      RECT 224.856 74.496 225.048 74.520 ;
    END
  END link_in[179]
  PIN link_in[180]
    DIRECTION INPUT ;
    USE SIGNAL ;
    SHAPE ABUTMENT ;
    PORT
      LAYER M4 ;
      RECT 224.856 74.640 225.048 74.664 ;
    END
  END link_in[180]
  PIN link_in[181]
    DIRECTION INPUT ;
    USE SIGNAL ;
    SHAPE ABUTMENT ;
    PORT
      LAYER M4 ;
      RECT 224.856 74.736 225.048 74.760 ;
    END
  END link_in[181]
  PIN link_in[182]
    DIRECTION INPUT ;
    USE SIGNAL ;
    SHAPE ABUTMENT ;
    PORT
      LAYER M4 ;
      RECT 224.856 74.832 225.048 74.856 ;
    END
  END link_in[182]
  PIN link_in[183]
    DIRECTION INPUT ;
    USE SIGNAL ;
    SHAPE ABUTMENT ;
    PORT
      LAYER M4 ;
      RECT 224.856 74.928 225.048 74.952 ;
    END
  END link_in[183]
  PIN link_in[184]
    DIRECTION INPUT ;
    USE SIGNAL ;
    SHAPE ABUTMENT ;
    PORT
      LAYER M4 ;
      RECT 224.856 75.072 225.048 75.096 ;
    END
  END link_in[184]
  PIN link_in[185]
    DIRECTION INPUT ;
    USE SIGNAL ;
    SHAPE ABUTMENT ;
    PORT
      LAYER M4 ;
      RECT 224.856 75.168 225.048 75.192 ;
    END
  END link_in[185]
  PIN link_in[186]
    DIRECTION INPUT ;
    USE SIGNAL ;
    SHAPE ABUTMENT ;
    PORT
      LAYER M4 ;
      RECT 224.856 75.264 225.048 75.288 ;
    END
  END link_in[186]
  PIN link_in[187]
    DIRECTION INPUT ;
    USE SIGNAL ;
    SHAPE ABUTMENT ;
    PORT
      LAYER M4 ;
      RECT 224.856 75.360 225.048 75.384 ;
    END
  END link_in[187]
  PIN link_in[188]
    DIRECTION INPUT ;
    USE SIGNAL ;
    SHAPE ABUTMENT ;
    PORT
      LAYER M4 ;
      RECT 224.856 75.504 225.048 75.528 ;
    END
  END link_in[188]
  PIN link_in[189]
    DIRECTION INPUT ;
    USE SIGNAL ;
    SHAPE ABUTMENT ;
    PORT
      LAYER M4 ;
      RECT 224.856 75.600 225.048 75.624 ;
    END
  END link_in[189]
  PIN link_in[190]
    DIRECTION INPUT ;
    USE SIGNAL ;
    SHAPE ABUTMENT ;
    PORT
      LAYER M4 ;
      RECT 224.856 75.696 225.048 75.720 ;
    END
  END link_in[190]
  PIN link_in[191]
    DIRECTION INPUT ;
    USE SIGNAL ;
    SHAPE ABUTMENT ;
    PORT
      LAYER M4 ;
      RECT 224.856 75.792 225.048 75.816 ;
    END
  END link_in[191]
  PIN link_in[192]
    DIRECTION INPUT ;
    USE SIGNAL ;
    SHAPE ABUTMENT ;
    PORT
      LAYER M4 ;
      RECT 224.856 75.888 225.048 75.912 ;
    END
  END link_in[192]
  PIN link_in[193]
    DIRECTION INPUT ;
    USE SIGNAL ;
    SHAPE ABUTMENT ;
    PORT
      LAYER M4 ;
      RECT 224.856 76.032 225.048 76.056 ;
    END
  END link_in[193]
  PIN link_in[194]
    DIRECTION INPUT ;
    USE SIGNAL ;
    SHAPE ABUTMENT ;
    PORT
      LAYER M4 ;
      RECT 224.856 76.128 225.048 76.152 ;
    END
  END link_in[194]
  PIN link_in[195]
    DIRECTION INPUT ;
    USE SIGNAL ;
    SHAPE ABUTMENT ;
    PORT
      LAYER M4 ;
      RECT 224.856 76.224 225.048 76.248 ;
    END
  END link_in[195]
  PIN link_in[196]
    DIRECTION INPUT ;
    USE SIGNAL ;
    SHAPE ABUTMENT ;
    PORT
      LAYER M4 ;
      RECT 224.856 76.320 225.048 76.344 ;
    END
  END link_in[196]
  PIN link_in[197]
    DIRECTION INPUT ;
    USE SIGNAL ;
    SHAPE ABUTMENT ;
    PORT
      LAYER M4 ;
      RECT 224.856 76.464 225.048 76.488 ;
    END
  END link_in[197]
  PIN link_in[198]
    DIRECTION INPUT ;
    USE SIGNAL ;
    SHAPE ABUTMENT ;
    PORT
      LAYER M4 ;
      RECT 224.856 76.560 225.048 76.584 ;
    END
  END link_in[198]
  PIN link_in[199]
    DIRECTION INPUT ;
    USE SIGNAL ;
    SHAPE ABUTMENT ;
    PORT
      LAYER M4 ;
      RECT 224.856 76.656 225.048 76.680 ;
    END
  END link_in[199]
  PIN link_in[200]
    DIRECTION INPUT ;
    USE SIGNAL ;
    SHAPE ABUTMENT ;
    PORT
      LAYER M4 ;
      RECT 224.856 76.752 225.048 76.776 ;
    END
  END link_in[200]
  PIN link_in[201]
    DIRECTION INPUT ;
    USE SIGNAL ;
    SHAPE ABUTMENT ;
    PORT
      LAYER M4 ;
      RECT 224.856 76.896 225.048 76.920 ;
    END
  END link_in[201]
  PIN link_in[202]
    DIRECTION INPUT ;
    USE SIGNAL ;
    SHAPE ABUTMENT ;
    PORT
      LAYER M4 ;
      RECT 224.856 76.992 225.048 77.016 ;
    END
  END link_in[202]
  PIN link_in[203]
    DIRECTION INPUT ;
    USE SIGNAL ;
    SHAPE ABUTMENT ;
    PORT
      LAYER M4 ;
      RECT 224.856 77.088 225.048 77.112 ;
    END
  END link_in[203]
  PIN link_in[204]
    DIRECTION INPUT ;
    USE SIGNAL ;
    SHAPE ABUTMENT ;
    PORT
      LAYER M4 ;
      RECT 224.856 77.184 225.048 77.208 ;
    END
  END link_in[204]
  PIN link_in[205]
    DIRECTION INPUT ;
    USE SIGNAL ;
    SHAPE ABUTMENT ;
    PORT
      LAYER M4 ;
      RECT 224.856 77.280 225.048 77.304 ;
    END
  END link_in[205]
  PIN link_in[206]
    DIRECTION INPUT ;
    USE SIGNAL ;
    SHAPE ABUTMENT ;
    PORT
      LAYER M4 ;
      RECT 224.856 77.424 225.048 77.448 ;
    END
  END link_in[206]
  PIN link_in[207]
    DIRECTION INPUT ;
    USE SIGNAL ;
    SHAPE ABUTMENT ;
    PORT
      LAYER M4 ;
      RECT 224.856 77.520 225.048 77.544 ;
    END
  END link_in[207]
  PIN link_in[208]
    DIRECTION INPUT ;
    USE SIGNAL ;
    SHAPE ABUTMENT ;
    PORT
      LAYER M4 ;
      RECT 224.856 77.616 225.048 77.640 ;
    END
  END link_in[208]
  PIN link_in[209]
    DIRECTION INPUT ;
    USE SIGNAL ;
    SHAPE ABUTMENT ;
    PORT
      LAYER M4 ;
      RECT 224.856 77.712 225.048 77.736 ;
    END
  END link_in[209]
  PIN link_in[210]
    DIRECTION INPUT ;
    USE SIGNAL ;
    SHAPE ABUTMENT ;
    PORT
      LAYER M4 ;
      RECT 224.856 77.856 225.048 77.880 ;
    END
  END link_in[210]
  PIN link_in[211]
    DIRECTION INPUT ;
    USE SIGNAL ;
    SHAPE ABUTMENT ;
    PORT
      LAYER M4 ;
      RECT 224.856 77.952 225.048 77.976 ;
    END
  END link_in[211]
  PIN link_in[212]
    DIRECTION INPUT ;
    USE SIGNAL ;
    SHAPE ABUTMENT ;
    PORT
      LAYER M4 ;
      RECT 224.856 78.048 225.048 78.072 ;
    END
  END link_in[212]
  PIN link_in[213]
    DIRECTION INPUT ;
    USE SIGNAL ;
    SHAPE ABUTMENT ;
    PORT
      LAYER M4 ;
      RECT 224.856 78.144 225.048 78.168 ;
    END
  END link_in[213]
  PIN link_in[214]
    DIRECTION INPUT ;
    USE SIGNAL ;
    SHAPE ABUTMENT ;
    PORT
      LAYER M4 ;
      RECT 224.856 78.288 225.048 78.312 ;
    END
  END link_in[214]
  PIN link_in[215]
    DIRECTION INPUT ;
    USE SIGNAL ;
    SHAPE ABUTMENT ;
    PORT
      LAYER M4 ;
      RECT 224.856 78.384 225.048 78.408 ;
    END
  END link_in[215]
  PIN link_in[216]
    DIRECTION INPUT ;
    USE SIGNAL ;
    SHAPE ABUTMENT ;
    PORT
      LAYER M4 ;
      RECT 224.856 78.480 225.048 78.504 ;
    END
  END link_in[216]
  PIN link_in[217]
    DIRECTION INPUT ;
    USE SIGNAL ;
    SHAPE ABUTMENT ;
    PORT
      LAYER M4 ;
      RECT 224.856 78.576 225.048 78.600 ;
    END
  END link_in[217]
  PIN link_in[218]
    DIRECTION INPUT ;
    USE SIGNAL ;
    SHAPE ABUTMENT ;
    PORT
      LAYER M4 ;
      RECT 224.856 78.672 225.048 78.696 ;
    END
  END link_in[218]
  PIN link_in[219]
    DIRECTION INPUT ;
    USE SIGNAL ;
    SHAPE ABUTMENT ;
    PORT
      LAYER M4 ;
      RECT 224.856 78.816 225.048 78.840 ;
    END
  END link_in[219]
  PIN link_in[220]
    DIRECTION INPUT ;
    USE SIGNAL ;
    SHAPE ABUTMENT ;
    PORT
      LAYER M4 ;
      RECT 224.856 78.912 225.048 78.936 ;
    END
  END link_in[220]
  PIN link_in[221]
    DIRECTION INPUT ;
    USE SIGNAL ;
    SHAPE ABUTMENT ;
    PORT
      LAYER M4 ;
      RECT 224.856 79.008 225.048 79.032 ;
    END
  END link_in[221]
  PIN link_in[222]
    DIRECTION INPUT ;
    USE SIGNAL ;
    SHAPE ABUTMENT ;
    PORT
      LAYER M4 ;
      RECT 224.856 79.104 225.048 79.128 ;
    END
  END link_in[222]
  PIN link_in[223]
    DIRECTION INPUT ;
    USE SIGNAL ;
    SHAPE ABUTMENT ;
    PORT
      LAYER M4 ;
      RECT 224.856 79.248 225.048 79.272 ;
    END
  END link_in[223]
  PIN link_in[224]
    DIRECTION INPUT ;
    USE SIGNAL ;
    SHAPE ABUTMENT ;
    PORT
      LAYER M4 ;
      RECT 224.856 79.344 225.048 79.368 ;
    END
  END link_in[224]
  PIN link_in[225]
    DIRECTION INPUT ;
    USE SIGNAL ;
    SHAPE ABUTMENT ;
    PORT
      LAYER M4 ;
      RECT 224.856 79.440 225.048 79.464 ;
    END
  END link_in[225]
  PIN link_in[226]
    DIRECTION INPUT ;
    USE SIGNAL ;
    SHAPE ABUTMENT ;
    PORT
      LAYER M4 ;
      RECT 224.856 79.536 225.048 79.560 ;
    END
  END link_in[226]
  PIN link_in[227]
    DIRECTION INPUT ;
    USE SIGNAL ;
    SHAPE ABUTMENT ;
    PORT
      LAYER M4 ;
      RECT 224.856 79.680 225.048 79.704 ;
    END
  END link_in[227]
  PIN link_in[228]
    DIRECTION INPUT ;
    USE SIGNAL ;
    SHAPE ABUTMENT ;
    PORT
      LAYER M4 ;
      RECT 224.856 79.776 225.048 79.800 ;
    END
  END link_in[228]
  PIN link_in[229]
    DIRECTION INPUT ;
    USE SIGNAL ;
    SHAPE ABUTMENT ;
    PORT
      LAYER M4 ;
      RECT 224.856 79.872 225.048 79.896 ;
    END
  END link_in[229]
  PIN link_in[230]
    DIRECTION INPUT ;
    USE SIGNAL ;
    SHAPE ABUTMENT ;
    PORT
      LAYER M4 ;
      RECT 224.856 79.968 225.048 79.992 ;
    END
  END link_in[230]
  PIN link_in[231]
    DIRECTION INPUT ;
    USE SIGNAL ;
    SHAPE ABUTMENT ;
    PORT
      LAYER M4 ;
      RECT 224.856 80.064 225.048 80.088 ;
    END
  END link_in[231]
  PIN link_in[232]
    DIRECTION INPUT ;
    USE SIGNAL ;
    SHAPE ABUTMENT ;
    PORT
      LAYER M4 ;
      RECT 224.856 80.208 225.048 80.232 ;
    END
  END link_in[232]
  PIN link_in[233]
    DIRECTION INPUT ;
    USE SIGNAL ;
    SHAPE ABUTMENT ;
    PORT
      LAYER M4 ;
      RECT 224.856 80.304 225.048 80.328 ;
    END
  END link_in[233]
  PIN link_in[234]
    DIRECTION INPUT ;
    USE SIGNAL ;
    SHAPE ABUTMENT ;
    PORT
      LAYER M4 ;
      RECT 224.856 80.400 225.048 80.424 ;
    END
  END link_in[234]
  PIN link_in[235]
    DIRECTION INPUT ;
    USE SIGNAL ;
    SHAPE ABUTMENT ;
    PORT
      LAYER M4 ;
      RECT 224.856 80.496 225.048 80.520 ;
    END
  END link_in[235]
  PIN link_in[236]
    DIRECTION INPUT ;
    USE SIGNAL ;
    SHAPE ABUTMENT ;
    PORT
      LAYER M4 ;
      RECT 224.856 80.640 225.048 80.664 ;
    END
  END link_in[236]
  PIN link_in[237]
    DIRECTION INPUT ;
    USE SIGNAL ;
    SHAPE ABUTMENT ;
    PORT
      LAYER M4 ;
      RECT 224.856 80.736 225.048 80.760 ;
    END
  END link_in[237]
  PIN link_in[238]
    DIRECTION INPUT ;
    USE SIGNAL ;
    SHAPE ABUTMENT ;
    PORT
      LAYER M4 ;
      RECT 224.856 80.832 225.048 80.856 ;
    END
  END link_in[238]
  PIN link_in[239]
    DIRECTION INPUT ;
    USE SIGNAL ;
    SHAPE ABUTMENT ;
    PORT
      LAYER M4 ;
      RECT 224.856 80.928 225.048 80.952 ;
    END
  END link_in[239]
  PIN link_in[240]
    DIRECTION INPUT ;
    USE SIGNAL ;
    SHAPE ABUTMENT ;
    PORT
      LAYER M4 ;
      RECT 224.856 81.072 225.048 81.096 ;
    END
  END link_in[240]
  PIN link_in[241]
    DIRECTION INPUT ;
    USE SIGNAL ;
    SHAPE ABUTMENT ;
    PORT
      LAYER M4 ;
      RECT 224.856 81.168 225.048 81.192 ;
    END
  END link_in[241]
  PIN link_in[242]
    DIRECTION INPUT ;
    USE SIGNAL ;
    SHAPE ABUTMENT ;
    PORT
      LAYER M4 ;
      RECT 224.856 81.264 225.048 81.288 ;
    END
  END link_in[242]
  PIN link_in[243]
    DIRECTION INPUT ;
    USE SIGNAL ;
    SHAPE ABUTMENT ;
    PORT
      LAYER M4 ;
      RECT 224.856 81.360 225.048 81.384 ;
    END
  END link_in[243]
  PIN link_in[244]
    DIRECTION INPUT ;
    USE SIGNAL ;
    SHAPE ABUTMENT ;
    PORT
      LAYER M4 ;
      RECT 224.856 81.456 225.048 81.480 ;
    END
  END link_in[244]
  PIN link_in[245]
    DIRECTION INPUT ;
    USE SIGNAL ;
    SHAPE ABUTMENT ;
    PORT
      LAYER M4 ;
      RECT 224.856 81.600 225.048 81.624 ;
    END
  END link_in[245]
  PIN link_in[246]
    DIRECTION INPUT ;
    USE SIGNAL ;
    SHAPE ABUTMENT ;
    PORT
      LAYER M4 ;
      RECT 224.856 81.696 225.048 81.720 ;
    END
  END link_in[246]
  PIN link_in[247]
    DIRECTION INPUT ;
    USE SIGNAL ;
    SHAPE ABUTMENT ;
    PORT
      LAYER M4 ;
      RECT 224.856 81.792 225.048 81.816 ;
    END
  END link_in[247]
  PIN link_in[248]
    DIRECTION INPUT ;
    USE SIGNAL ;
    SHAPE ABUTMENT ;
    PORT
      LAYER M4 ;
      RECT 224.856 81.888 225.048 81.912 ;
    END
  END link_in[248]
  PIN link_in[249]
    DIRECTION INPUT ;
    USE SIGNAL ;
    SHAPE ABUTMENT ;
    PORT
      LAYER M4 ;
      RECT 224.856 82.032 225.048 82.056 ;
    END
  END link_in[249]
  PIN link_in[250]
    DIRECTION INPUT ;
    USE SIGNAL ;
    SHAPE ABUTMENT ;
    PORT
      LAYER M4 ;
      RECT 224.856 82.128 225.048 82.152 ;
    END
  END link_in[250]
  PIN link_in[251]
    DIRECTION INPUT ;
    USE SIGNAL ;
    SHAPE ABUTMENT ;
    PORT
      LAYER M4 ;
      RECT 224.856 82.224 225.048 82.248 ;
    END
  END link_in[251]
  PIN link_in[252]
    DIRECTION INPUT ;
    USE SIGNAL ;
    SHAPE ABUTMENT ;
    PORT
      LAYER M4 ;
      RECT 224.856 82.320 225.048 82.344 ;
    END
  END link_in[252]
  PIN link_in[253]
    DIRECTION INPUT ;
    USE SIGNAL ;
    SHAPE ABUTMENT ;
    PORT
      LAYER M4 ;
      RECT 224.856 82.464 225.048 82.488 ;
    END
  END link_in[253]
  PIN link_in[254]
    DIRECTION INPUT ;
    USE SIGNAL ;
    SHAPE ABUTMENT ;
    PORT
      LAYER M4 ;
      RECT 224.856 82.560 225.048 82.584 ;
    END
  END link_in[254]
  PIN link_in[255]
    DIRECTION INPUT ;
    USE SIGNAL ;
    SHAPE ABUTMENT ;
    PORT
      LAYER M4 ;
      RECT 224.856 82.656 225.048 82.680 ;
    END
  END link_in[255]
  PIN link_in[256]
    DIRECTION INPUT ;
    USE SIGNAL ;
    SHAPE ABUTMENT ;
    PORT
      LAYER M4 ;
      RECT 224.856 82.752 225.048 82.776 ;
    END
  END link_in[256]
  PIN link_in[257]
    DIRECTION INPUT ;
    USE SIGNAL ;
    SHAPE ABUTMENT ;
    PORT
      LAYER M4 ;
      RECT 224.856 82.848 225.048 82.872 ;
    END
  END link_in[257]
  PIN link_in[258]
    DIRECTION INPUT ;
    USE SIGNAL ;
    SHAPE ABUTMENT ;
    PORT
      LAYER M4 ;
      RECT 224.856 82.992 225.048 83.016 ;
    END
  END link_in[258]
  PIN link_in[259]
    DIRECTION INPUT ;
    USE SIGNAL ;
    SHAPE ABUTMENT ;
    PORT
      LAYER M4 ;
      RECT 224.856 83.088 225.048 83.112 ;
    END
  END link_in[259]
  PIN link_in[260]
    DIRECTION INPUT ;
    USE SIGNAL ;
    SHAPE ABUTMENT ;
    PORT
      LAYER M4 ;
      RECT 224.856 83.184 225.048 83.208 ;
    END
  END link_in[260]
  PIN link_in[261]
    DIRECTION INPUT ;
    USE SIGNAL ;
    SHAPE ABUTMENT ;
    PORT
      LAYER M4 ;
      RECT 224.856 83.280 225.048 83.304 ;
    END
  END link_in[261]
  PIN link_in[262]
    DIRECTION INPUT ;
    USE SIGNAL ;
    SHAPE ABUTMENT ;
    PORT
      LAYER M4 ;
      RECT 224.856 83.424 225.048 83.448 ;
    END
  END link_in[262]
  PIN link_in[263]
    DIRECTION INPUT ;
    USE SIGNAL ;
    SHAPE ABUTMENT ;
    PORT
      LAYER M4 ;
      RECT 224.856 83.520 225.048 83.544 ;
    END
  END link_in[263]
  PIN link_in[264]
    DIRECTION INPUT ;
    USE SIGNAL ;
    SHAPE ABUTMENT ;
    PORT
      LAYER M4 ;
      RECT 224.856 83.616 225.048 83.640 ;
    END
  END link_in[264]
  PIN link_in[265]
    DIRECTION INPUT ;
    USE SIGNAL ;
    SHAPE ABUTMENT ;
    PORT
      LAYER M4 ;
      RECT 224.856 83.712 225.048 83.736 ;
    END
  END link_in[265]
  PIN link_in[266]
    DIRECTION INPUT ;
    USE SIGNAL ;
    SHAPE ABUTMENT ;
    PORT
      LAYER M4 ;
      RECT 224.856 83.856 225.048 83.880 ;
    END
  END link_in[266]
  PIN link_in[267]
    DIRECTION INPUT ;
    USE SIGNAL ;
    SHAPE ABUTMENT ;
    PORT
      LAYER M4 ;
      RECT 224.856 83.952 225.048 83.976 ;
    END
  END link_in[267]
  PIN link_in[268]
    DIRECTION INPUT ;
    USE SIGNAL ;
    SHAPE ABUTMENT ;
    PORT
      LAYER M4 ;
      RECT 224.856 84.048 225.048 84.072 ;
    END
  END link_in[268]
  PIN link_in[269]
    DIRECTION INPUT ;
    USE SIGNAL ;
    SHAPE ABUTMENT ;
    PORT
      LAYER M4 ;
      RECT 224.856 84.144 225.048 84.168 ;
    END
  END link_in[269]
  PIN link_in[270]
    DIRECTION INPUT ;
    USE SIGNAL ;
    SHAPE ABUTMENT ;
    PORT
      LAYER M4 ;
      RECT 224.856 84.240 225.048 84.264 ;
    END
  END link_in[270]
  PIN link_in[271]
    DIRECTION INPUT ;
    USE SIGNAL ;
    SHAPE ABUTMENT ;
    PORT
      LAYER M4 ;
      RECT 224.856 84.384 225.048 84.408 ;
    END
  END link_in[271]
  PIN link_in[272]
    DIRECTION INPUT ;
    USE SIGNAL ;
    SHAPE ABUTMENT ;
    PORT
      LAYER M4 ;
      RECT 224.856 84.480 225.048 84.504 ;
    END
  END link_in[272]
  PIN link_in[273]
    DIRECTION INPUT ;
    USE SIGNAL ;
    SHAPE ABUTMENT ;
    PORT
      LAYER M4 ;
      RECT 224.856 84.576 225.048 84.600 ;
    END
  END link_in[273]
  PIN link_in[274]
    DIRECTION INPUT ;
    USE SIGNAL ;
    SHAPE ABUTMENT ;
    PORT
      LAYER M4 ;
      RECT 224.856 84.672 225.048 84.696 ;
    END
  END link_in[274]
  PIN link_in[275]
    DIRECTION INPUT ;
    USE SIGNAL ;
    SHAPE ABUTMENT ;
    PORT
      LAYER M4 ;
      RECT 224.856 84.816 225.048 84.840 ;
    END
  END link_in[275]
  PIN link_in[276]
    DIRECTION INPUT ;
    USE SIGNAL ;
    SHAPE ABUTMENT ;
    PORT
      LAYER M4 ;
      RECT 224.856 84.912 225.048 84.936 ;
    END
  END link_in[276]
  PIN link_in[277]
    DIRECTION INPUT ;
    USE SIGNAL ;
    SHAPE ABUTMENT ;
    PORT
      LAYER M4 ;
      RECT 224.856 85.008 225.048 85.032 ;
    END
  END link_in[277]
  PIN link_in[278]
    DIRECTION INPUT ;
    USE SIGNAL ;
    SHAPE ABUTMENT ;
    PORT
      LAYER M4 ;
      RECT 224.856 85.104 225.048 85.128 ;
    END
  END link_in[278]
  PIN link_in[279]
    DIRECTION INPUT ;
    USE SIGNAL ;
    SHAPE ABUTMENT ;
    PORT
      LAYER M4 ;
      RECT 224.856 85.248 225.048 85.272 ;
    END
  END link_in[279]
  PIN link_in[280]
    DIRECTION INPUT ;
    USE SIGNAL ;
    SHAPE ABUTMENT ;
    PORT
      LAYER M4 ;
      RECT 224.856 85.344 225.048 85.368 ;
    END
  END link_in[280]
  PIN link_in[281]
    DIRECTION INPUT ;
    USE SIGNAL ;
    SHAPE ABUTMENT ;
    PORT
      LAYER M4 ;
      RECT 224.856 85.440 225.048 85.464 ;
    END
  END link_in[281]
  PIN link_in[282]
    DIRECTION INPUT ;
    USE SIGNAL ;
    SHAPE ABUTMENT ;
    PORT
      LAYER M4 ;
      RECT 224.856 85.536 225.048 85.560 ;
    END
  END link_in[282]
  PIN link_in[283]
    DIRECTION INPUT ;
    USE SIGNAL ;
    SHAPE ABUTMENT ;
    PORT
      LAYER M4 ;
      RECT 224.856 85.632 225.048 85.656 ;
    END
  END link_in[283]
  PIN link_in[284]
    DIRECTION INPUT ;
    USE SIGNAL ;
    SHAPE ABUTMENT ;
    PORT
      LAYER M4 ;
      RECT 224.856 85.776 225.048 85.800 ;
    END
  END link_in[284]
  PIN link_in[285]
    DIRECTION INPUT ;
    USE SIGNAL ;
    SHAPE ABUTMENT ;
    PORT
      LAYER M4 ;
      RECT 224.856 85.872 225.048 85.896 ;
    END
  END link_in[285]
  PIN link_in[286]
    DIRECTION INPUT ;
    USE SIGNAL ;
    SHAPE ABUTMENT ;
    PORT
      LAYER M4 ;
      RECT 224.856 85.968 225.048 85.992 ;
    END
  END link_in[286]
  PIN link_in[287]
    DIRECTION INPUT ;
    USE SIGNAL ;
    SHAPE ABUTMENT ;
    PORT
      LAYER M4 ;
      RECT 224.856 86.064 225.048 86.088 ;
    END
  END link_in[287]
  PIN link_in[288]
    DIRECTION INPUT ;
    USE SIGNAL ;
    SHAPE ABUTMENT ;
    PORT
      LAYER M4 ;
      RECT 224.856 86.208 225.048 86.232 ;
    END
  END link_in[288]
  PIN link_in[289]
    DIRECTION INPUT ;
    USE SIGNAL ;
    SHAPE ABUTMENT ;
    PORT
      LAYER M4 ;
      RECT 224.856 86.304 225.048 86.328 ;
    END
  END link_in[289]
  PIN link_in[290]
    DIRECTION INPUT ;
    USE SIGNAL ;
    SHAPE ABUTMENT ;
    PORT
      LAYER M4 ;
      RECT 224.856 86.400 225.048 86.424 ;
    END
  END link_in[290]
  PIN link_in[291]
    DIRECTION INPUT ;
    USE SIGNAL ;
    SHAPE ABUTMENT ;
    PORT
      LAYER M4 ;
      RECT 224.856 86.496 225.048 86.520 ;
    END
  END link_in[291]
  PIN link_in[292]
    DIRECTION INPUT ;
    USE SIGNAL ;
    SHAPE ABUTMENT ;
    PORT
      LAYER M4 ;
      RECT 224.856 86.640 225.048 86.664 ;
    END
  END link_in[292]
  PIN link_in[293]
    DIRECTION INPUT ;
    USE SIGNAL ;
    SHAPE ABUTMENT ;
    PORT
      LAYER M4 ;
      RECT 224.856 86.736 225.048 86.760 ;
    END
  END link_in[293]
  PIN link_in[294]
    DIRECTION INPUT ;
    USE SIGNAL ;
    SHAPE ABUTMENT ;
    PORT
      LAYER M4 ;
      RECT 224.856 86.832 225.048 86.856 ;
    END
  END link_in[294]
  PIN link_in[295]
    DIRECTION INPUT ;
    USE SIGNAL ;
    SHAPE ABUTMENT ;
    PORT
      LAYER M4 ;
      RECT 224.856 86.928 225.048 86.952 ;
    END
  END link_in[295]
  PIN link_in[296]
    DIRECTION INPUT ;
    USE SIGNAL ;
    SHAPE ABUTMENT ;
    PORT
      LAYER M4 ;
      RECT 224.856 87.072 225.048 87.096 ;
    END
  END link_in[296]
  PIN link_in[297]
    DIRECTION INPUT ;
    USE SIGNAL ;
    SHAPE ABUTMENT ;
    PORT
      LAYER M4 ;
      RECT 224.856 87.168 225.048 87.192 ;
    END
  END link_in[297]
  PIN link_in[298]
    DIRECTION INPUT ;
    USE SIGNAL ;
    SHAPE ABUTMENT ;
    PORT
      LAYER M4 ;
      RECT 224.856 87.264 225.048 87.288 ;
    END
  END link_in[298]
  PIN link_in[299]
    DIRECTION INPUT ;
    USE SIGNAL ;
    SHAPE ABUTMENT ;
    PORT
      LAYER M4 ;
      RECT 224.856 87.360 225.048 87.384 ;
    END
  END link_in[299]
  PIN link_in[300]
    DIRECTION INPUT ;
    USE SIGNAL ;
    SHAPE ABUTMENT ;
    PORT
      LAYER M4 ;
      RECT 224.856 87.456 225.048 87.480 ;
    END
  END link_in[300]
  PIN link_in[301]
    DIRECTION INPUT ;
    USE SIGNAL ;
    SHAPE ABUTMENT ;
    PORT
      LAYER M4 ;
      RECT 224.856 87.600 225.048 87.624 ;
    END
  END link_in[301]
  PIN link_in[302]
    DIRECTION INPUT ;
    USE SIGNAL ;
    SHAPE ABUTMENT ;
    PORT
      LAYER M4 ;
      RECT 224.856 87.696 225.048 87.720 ;
    END
  END link_in[302]
  PIN link_in[303]
    DIRECTION INPUT ;
    USE SIGNAL ;
    SHAPE ABUTMENT ;
    PORT
      LAYER M4 ;
      RECT 224.856 87.792 225.048 87.816 ;
    END
  END link_in[303]
  PIN link_in[304]
    DIRECTION INPUT ;
    USE SIGNAL ;
    SHAPE ABUTMENT ;
    PORT
      LAYER M4 ;
      RECT 224.856 87.888 225.048 87.912 ;
    END
  END link_in[304]
  PIN link_in[305]
    DIRECTION INPUT ;
    USE SIGNAL ;
    SHAPE ABUTMENT ;
    PORT
      LAYER M4 ;
      RECT 224.856 88.032 225.048 88.056 ;
    END
  END link_in[305]
  PIN link_in[306]
    DIRECTION INPUT ;
    USE SIGNAL ;
    SHAPE ABUTMENT ;
    PORT
      LAYER M4 ;
      RECT 224.856 88.128 225.048 88.152 ;
    END
  END link_in[306]
  PIN link_in[307]
    DIRECTION INPUT ;
    USE SIGNAL ;
    SHAPE ABUTMENT ;
    PORT
      LAYER M4 ;
      RECT 224.856 88.224 225.048 88.248 ;
    END
  END link_in[307]
  PIN link_in[308]
    DIRECTION INPUT ;
    USE SIGNAL ;
    SHAPE ABUTMENT ;
    PORT
      LAYER M4 ;
      RECT 224.856 88.320 225.048 88.344 ;
    END
  END link_in[308]
  PIN link_in[309]
    DIRECTION INPUT ;
    USE SIGNAL ;
    SHAPE ABUTMENT ;
    PORT
      LAYER M4 ;
      RECT 224.856 88.464 225.048 88.488 ;
    END
  END link_in[309]
  PIN link_in[310]
    DIRECTION INPUT ;
    USE SIGNAL ;
    SHAPE ABUTMENT ;
    PORT
      LAYER M4 ;
      RECT 224.856 88.560 225.048 88.584 ;
    END
  END link_in[310]
  PIN link_in[311]
    DIRECTION INPUT ;
    USE SIGNAL ;
    SHAPE ABUTMENT ;
    PORT
      LAYER M4 ;
      RECT 224.856 88.656 225.048 88.680 ;
    END
  END link_in[311]
  PIN link_in[312]
    DIRECTION INPUT ;
    USE SIGNAL ;
    SHAPE ABUTMENT ;
    PORT
      LAYER M4 ;
      RECT 224.856 88.752 225.048 88.776 ;
    END
  END link_in[312]
  PIN link_in[313]
    DIRECTION INPUT ;
    USE SIGNAL ;
    SHAPE ABUTMENT ;
    PORT
      LAYER M4 ;
      RECT 224.856 88.848 225.048 88.872 ;
    END
  END link_in[313]
  PIN link_in[314]
    DIRECTION INPUT ;
    USE SIGNAL ;
    SHAPE ABUTMENT ;
    PORT
      LAYER M4 ;
      RECT 224.856 88.992 225.048 89.016 ;
    END
  END link_in[314]
  PIN link_in[315]
    DIRECTION INPUT ;
    USE SIGNAL ;
    SHAPE ABUTMENT ;
    PORT
      LAYER M4 ;
      RECT 224.856 89.088 225.048 89.112 ;
    END
  END link_in[315]
  PIN link_in[316]
    DIRECTION INPUT ;
    USE SIGNAL ;
    SHAPE ABUTMENT ;
    PORT
      LAYER M4 ;
      RECT 224.856 89.184 225.048 89.208 ;
    END
  END link_in[316]
  PIN link_in[317]
    DIRECTION INPUT ;
    USE SIGNAL ;
    SHAPE ABUTMENT ;
    PORT
      LAYER M4 ;
      RECT 224.856 89.280 225.048 89.304 ;
    END
  END link_in[317]
  PIN link_in[318]
    DIRECTION INPUT ;
    USE SIGNAL ;
    SHAPE ABUTMENT ;
    PORT
      LAYER M4 ;
      RECT 224.856 89.424 225.048 89.448 ;
    END
  END link_in[318]
  PIN link_in[319]
    DIRECTION INPUT ;
    USE SIGNAL ;
    SHAPE ABUTMENT ;
    PORT
      LAYER M4 ;
      RECT 224.856 89.520 225.048 89.544 ;
    END
  END link_in[319]
  PIN link_in[320]
    DIRECTION INPUT ;
    USE SIGNAL ;
    SHAPE ABUTMENT ;
    PORT
      LAYER M4 ;
      RECT 224.856 89.616 225.048 89.640 ;
    END
  END link_in[320]
  PIN link_in[321]
    DIRECTION INPUT ;
    USE SIGNAL ;
    SHAPE ABUTMENT ;
    PORT
      LAYER M4 ;
      RECT 224.856 89.712 225.048 89.736 ;
    END
  END link_in[321]
  PIN link_in[322]
    DIRECTION INPUT ;
    USE SIGNAL ;
    SHAPE ABUTMENT ;
    PORT
      LAYER M4 ;
      RECT 224.856 89.856 225.048 89.880 ;
    END
  END link_in[322]
  PIN link_in[323]
    DIRECTION INPUT ;
    USE SIGNAL ;
    SHAPE ABUTMENT ;
    PORT
      LAYER M4 ;
      RECT 224.856 89.952 225.048 89.976 ;
    END
  END link_in[323]
  PIN link_in[324]
    DIRECTION INPUT ;
    USE SIGNAL ;
    SHAPE ABUTMENT ;
    PORT
      LAYER M4 ;
      RECT 224.856 90.048 225.048 90.072 ;
    END
  END link_in[324]
  PIN link_in[325]
    DIRECTION INPUT ;
    USE SIGNAL ;
    SHAPE ABUTMENT ;
    PORT
      LAYER M4 ;
      RECT 224.856 90.144 225.048 90.168 ;
    END
  END link_in[325]
  PIN link_in[326]
    DIRECTION INPUT ;
    USE SIGNAL ;
    SHAPE ABUTMENT ;
    PORT
      LAYER M4 ;
      RECT 224.856 90.240 225.048 90.264 ;
    END
  END link_in[326]
  PIN link_in[327]
    DIRECTION INPUT ;
    USE SIGNAL ;
    SHAPE ABUTMENT ;
    PORT
      LAYER M4 ;
      RECT 224.856 90.384 225.048 90.408 ;
    END
  END link_in[327]
  PIN link_in[328]
    DIRECTION INPUT ;
    USE SIGNAL ;
    SHAPE ABUTMENT ;
    PORT
      LAYER M4 ;
      RECT 224.856 90.480 225.048 90.504 ;
    END
  END link_in[328]
  PIN link_in[329]
    DIRECTION INPUT ;
    USE SIGNAL ;
    SHAPE ABUTMENT ;
    PORT
      LAYER M4 ;
      RECT 224.856 90.576 225.048 90.600 ;
    END
  END link_in[329]
  PIN link_in[330]
    DIRECTION INPUT ;
    USE SIGNAL ;
    SHAPE ABUTMENT ;
    PORT
      LAYER M4 ;
      RECT 224.856 90.672 225.048 90.696 ;
    END
  END link_in[330]
  PIN link_in[331]
    DIRECTION INPUT ;
    USE SIGNAL ;
    SHAPE ABUTMENT ;
    PORT
      LAYER M4 ;
      RECT 224.856 90.816 225.048 90.840 ;
    END
  END link_in[331]
  PIN link_in[332]
    DIRECTION INPUT ;
    USE SIGNAL ;
    SHAPE ABUTMENT ;
    PORT
      LAYER M4 ;
      RECT 224.856 90.912 225.048 90.936 ;
    END
  END link_in[332]
  PIN link_in[333]
    DIRECTION INPUT ;
    USE SIGNAL ;
    SHAPE ABUTMENT ;
    PORT
      LAYER M4 ;
      RECT 224.856 91.008 225.048 91.032 ;
    END
  END link_in[333]
  PIN link_in[334]
    DIRECTION INPUT ;
    USE SIGNAL ;
    SHAPE ABUTMENT ;
    PORT
      LAYER M4 ;
      RECT 224.856 91.104 225.048 91.128 ;
    END
  END link_in[334]
  PIN link_in[335]
    DIRECTION INPUT ;
    USE SIGNAL ;
    SHAPE ABUTMENT ;
    PORT
      LAYER M4 ;
      RECT 224.856 91.248 225.048 91.272 ;
    END
  END link_in[335]
  PIN link_in[336]
    DIRECTION INPUT ;
    USE SIGNAL ;
    SHAPE ABUTMENT ;
    PORT
      LAYER M4 ;
      RECT 224.856 91.344 225.048 91.368 ;
    END
  END link_in[336]
  PIN link_in[337]
    DIRECTION INPUT ;
    USE SIGNAL ;
    SHAPE ABUTMENT ;
    PORT
      LAYER M4 ;
      RECT 224.856 91.440 225.048 91.464 ;
    END
  END link_in[337]
  PIN link_in[338]
    DIRECTION INPUT ;
    USE SIGNAL ;
    SHAPE ABUTMENT ;
    PORT
      LAYER M4 ;
      RECT 224.856 91.536 225.048 91.560 ;
    END
  END link_in[338]
  PIN link_in[339]
    DIRECTION INPUT ;
    USE SIGNAL ;
    SHAPE ABUTMENT ;
    PORT
      LAYER M4 ;
      RECT 224.856 91.632 225.048 91.656 ;
    END
  END link_in[339]
  PIN link_in[340]
    DIRECTION INPUT ;
    USE SIGNAL ;
    SHAPE ABUTMENT ;
    PORT
      LAYER M4 ;
      RECT 224.856 91.776 225.048 91.800 ;
    END
  END link_in[340]
  PIN link_in[341]
    DIRECTION INPUT ;
    USE SIGNAL ;
    SHAPE ABUTMENT ;
    PORT
      LAYER M4 ;
      RECT 224.856 91.872 225.048 91.896 ;
    END
  END link_in[341]
  PIN link_in[342]
    DIRECTION INPUT ;
    USE SIGNAL ;
    SHAPE ABUTMENT ;
    PORT
      LAYER M4 ;
      RECT 224.856 91.968 225.048 91.992 ;
    END
  END link_in[342]
  PIN link_in[343]
    DIRECTION INPUT ;
    USE SIGNAL ;
    SHAPE ABUTMENT ;
    PORT
      LAYER M4 ;
      RECT 224.856 92.064 225.048 92.088 ;
    END
  END link_in[343]
  PIN link_in[344]
    DIRECTION INPUT ;
    USE SIGNAL ;
    SHAPE ABUTMENT ;
    PORT
      LAYER M4 ;
      RECT 224.856 92.208 225.048 92.232 ;
    END
  END link_in[344]
  PIN link_in[345]
    DIRECTION INPUT ;
    USE SIGNAL ;
    SHAPE ABUTMENT ;
    PORT
      LAYER M4 ;
      RECT 224.856 92.304 225.048 92.328 ;
    END
  END link_in[345]
  PIN link_in[346]
    DIRECTION INPUT ;
    USE SIGNAL ;
    SHAPE ABUTMENT ;
    PORT
      LAYER M4 ;
      RECT 224.856 92.400 225.048 92.424 ;
    END
  END link_in[346]
  PIN link_in[347]
    DIRECTION INPUT ;
    USE SIGNAL ;
    SHAPE ABUTMENT ;
    PORT
      LAYER M4 ;
      RECT 224.856 92.496 225.048 92.520 ;
    END
  END link_in[347]
  PIN link_in[348]
    DIRECTION INPUT ;
    USE SIGNAL ;
    SHAPE ABUTMENT ;
    PORT
      LAYER M4 ;
      RECT 224.856 92.640 225.048 92.664 ;
    END
  END link_in[348]
  PIN link_in[349]
    DIRECTION INPUT ;
    USE SIGNAL ;
    SHAPE ABUTMENT ;
    PORT
      LAYER M4 ;
      RECT 224.856 92.736 225.048 92.760 ;
    END
  END link_in[349]
  PIN link_in[350]
    DIRECTION INPUT ;
    USE SIGNAL ;
    SHAPE ABUTMENT ;
    PORT
      LAYER M4 ;
      RECT 224.856 92.832 225.048 92.856 ;
    END
  END link_in[350]
  PIN link_in[351]
    DIRECTION INPUT ;
    USE SIGNAL ;
    SHAPE ABUTMENT ;
    PORT
      LAYER M4 ;
      RECT 224.856 92.928 225.048 92.952 ;
    END
  END link_in[351]
  PIN link_in[352]
    DIRECTION INPUT ;
    USE SIGNAL ;
    SHAPE ABUTMENT ;
    PORT
      LAYER M4 ;
      RECT 224.856 93.024 225.048 93.048 ;
    END
  END link_in[352]
  PIN link_in[353]
    DIRECTION INPUT ;
    USE SIGNAL ;
    SHAPE ABUTMENT ;
    PORT
      LAYER M4 ;
      RECT 224.856 93.168 225.048 93.192 ;
    END
  END link_in[353]
  PIN link_in[354]
    DIRECTION INPUT ;
    USE SIGNAL ;
    SHAPE ABUTMENT ;
    PORT
      LAYER M4 ;
      RECT 224.856 93.264 225.048 93.288 ;
    END
  END link_in[354]
  PIN link_in[355]
    DIRECTION INPUT ;
    USE SIGNAL ;
    SHAPE ABUTMENT ;
    PORT
      LAYER M4 ;
      RECT 224.856 93.360 225.048 93.384 ;
    END
  END link_in[355]
  PIN link_in[356]
    DIRECTION INPUT ;
    USE SIGNAL ;
    SHAPE ABUTMENT ;
    PORT
      LAYER M4 ;
      RECT 224.856 93.456 225.048 93.480 ;
    END
  END link_in[356]
  PIN link_in[357]
    DIRECTION INPUT ;
    USE SIGNAL ;
    SHAPE ABUTMENT ;
    PORT
      LAYER M4 ;
      RECT 224.856 93.600 225.048 93.624 ;
    END
  END link_in[357]
  PIN link_in[358]
    DIRECTION INPUT ;
    USE SIGNAL ;
    SHAPE ABUTMENT ;
    PORT
      LAYER M4 ;
      RECT 224.856 93.696 225.048 93.720 ;
    END
  END link_in[358]
  PIN link_in[359]
    DIRECTION INPUT ;
    USE SIGNAL ;
    SHAPE ABUTMENT ;
    PORT
      LAYER M4 ;
      RECT 224.856 93.792 225.048 93.816 ;
    END
  END link_in[359]
  PIN link_in[360]
    DIRECTION INPUT ;
    USE SIGNAL ;
    SHAPE ABUTMENT ;
    PORT
      LAYER M4 ;
      RECT 224.856 93.888 225.048 93.912 ;
    END
  END link_in[360]
  PIN link_in[361]
    DIRECTION INPUT ;
    USE SIGNAL ;
    SHAPE ABUTMENT ;
    PORT
      LAYER M4 ;
      RECT 224.856 94.032 225.048 94.056 ;
    END
  END link_in[361]
  PIN link_in[362]
    DIRECTION INPUT ;
    USE SIGNAL ;
    SHAPE ABUTMENT ;
    PORT
      LAYER M4 ;
      RECT 224.856 94.128 225.048 94.152 ;
    END
  END link_in[362]
  PIN link_in[363]
    DIRECTION INPUT ;
    USE SIGNAL ;
    SHAPE ABUTMENT ;
    PORT
      LAYER M4 ;
      RECT 224.856 94.224 225.048 94.248 ;
    END
  END link_in[363]
  PIN link_in[364]
    DIRECTION INPUT ;
    USE SIGNAL ;
    SHAPE ABUTMENT ;
    PORT
      LAYER M4 ;
      RECT 224.856 94.320 225.048 94.344 ;
    END
  END link_in[364]
  PIN link_in[365]
    DIRECTION INPUT ;
    USE SIGNAL ;
    SHAPE ABUTMENT ;
    PORT
      LAYER M4 ;
      RECT 224.856 94.416 225.048 94.440 ;
    END
  END link_in[365]
  PIN link_in[366]
    DIRECTION INPUT ;
    USE SIGNAL ;
    SHAPE ABUTMENT ;
    PORT
      LAYER M4 ;
      RECT 224.856 94.560 225.048 94.584 ;
    END
  END link_in[366]
  PIN link_in[367]
    DIRECTION INPUT ;
    USE SIGNAL ;
    SHAPE ABUTMENT ;
    PORT
      LAYER M4 ;
      RECT 224.856 94.656 225.048 94.680 ;
    END
  END link_in[367]
  PIN link_in[368]
    DIRECTION INPUT ;
    USE SIGNAL ;
    SHAPE ABUTMENT ;
    PORT
      LAYER M4 ;
      RECT 224.856 94.752 225.048 94.776 ;
    END
  END link_in[368]
  PIN link_in[369]
    DIRECTION INPUT ;
    USE SIGNAL ;
    SHAPE ABUTMENT ;
    PORT
      LAYER M4 ;
      RECT 224.856 94.848 225.048 94.872 ;
    END
  END link_in[369]
  PIN link_in[370]
    DIRECTION INPUT ;
    USE SIGNAL ;
    SHAPE ABUTMENT ;
    PORT
      LAYER M4 ;
      RECT 224.856 94.992 225.048 95.016 ;
    END
  END link_in[370]
  PIN link_in[371]
    DIRECTION INPUT ;
    USE SIGNAL ;
    SHAPE ABUTMENT ;
    PORT
      LAYER M4 ;
      RECT 224.856 95.088 225.048 95.112 ;
    END
  END link_in[371]
  PIN link_in[372]
    DIRECTION INPUT ;
    USE SIGNAL ;
    SHAPE ABUTMENT ;
    PORT
      LAYER M4 ;
      RECT 224.856 95.184 225.048 95.208 ;
    END
  END link_in[372]
  PIN link_in[373]
    DIRECTION INPUT ;
    USE SIGNAL ;
    SHAPE ABUTMENT ;
    PORT
      LAYER M4 ;
      RECT 224.856 95.280 225.048 95.304 ;
    END
  END link_in[373]
  PIN link_in[374]
    DIRECTION INPUT ;
    USE SIGNAL ;
    SHAPE ABUTMENT ;
    PORT
      LAYER M4 ;
      RECT 224.856 95.424 225.048 95.448 ;
    END
  END link_in[374]
  PIN link_in[375]
    DIRECTION INPUT ;
    USE SIGNAL ;
    SHAPE ABUTMENT ;
    PORT
      LAYER M4 ;
      RECT 224.856 95.520 225.048 95.544 ;
    END
  END link_in[375]
  PIN link_in[376]
    DIRECTION INPUT ;
    USE SIGNAL ;
    SHAPE ABUTMENT ;
    PORT
      LAYER M4 ;
      RECT 224.856 95.616 225.048 95.640 ;
    END
  END link_in[376]
  PIN link_in[377]
    DIRECTION INPUT ;
    USE SIGNAL ;
    SHAPE ABUTMENT ;
    PORT
      LAYER M4 ;
      RECT 224.856 95.712 225.048 95.736 ;
    END
  END link_in[377]
  PIN link_in[378]
    DIRECTION INPUT ;
    USE SIGNAL ;
    SHAPE ABUTMENT ;
    PORT
      LAYER M4 ;
      RECT 224.856 95.808 225.048 95.832 ;
    END
  END link_in[378]
  PIN link_in[379]
    DIRECTION INPUT ;
    USE SIGNAL ;
    SHAPE ABUTMENT ;
    PORT
      LAYER M4 ;
      RECT 224.856 95.952 225.048 95.976 ;
    END
  END link_in[379]
  PIN link_in[380]
    DIRECTION INPUT ;
    USE SIGNAL ;
    SHAPE ABUTMENT ;
    PORT
      LAYER M4 ;
      RECT 224.856 96.048 225.048 96.072 ;
    END
  END link_in[380]
  PIN link_in[381]
    DIRECTION INPUT ;
    USE SIGNAL ;
    SHAPE ABUTMENT ;
    PORT
      LAYER M4 ;
      RECT 224.856 96.144 225.048 96.168 ;
    END
  END link_in[381]
  PIN link_in[382]
    DIRECTION INPUT ;
    USE SIGNAL ;
    SHAPE ABUTMENT ;
    PORT
      LAYER M4 ;
      RECT 224.856 96.240 225.048 96.264 ;
    END
  END link_in[382]
  PIN link_in[383]
    DIRECTION INPUT ;
    USE SIGNAL ;
    SHAPE ABUTMENT ;
    PORT
      LAYER M4 ;
      RECT 224.856 96.384 225.048 96.408 ;
    END
  END link_in[383]
  PIN link_in[384]
    DIRECTION INPUT ;
    USE SIGNAL ;
    SHAPE ABUTMENT ;
    PORT
      LAYER M4 ;
      RECT 224.856 96.480 225.048 96.504 ;
    END
  END link_in[384]
  PIN link_in[385]
    DIRECTION INPUT ;
    USE SIGNAL ;
    SHAPE ABUTMENT ;
    PORT
      LAYER M4 ;
      RECT 224.856 96.576 225.048 96.600 ;
    END
  END link_in[385]
  PIN link_in[386]
    DIRECTION INPUT ;
    USE SIGNAL ;
    SHAPE ABUTMENT ;
    PORT
      LAYER M4 ;
      RECT 224.856 96.672 225.048 96.696 ;
    END
  END link_in[386]
  PIN link_in[387]
    DIRECTION INPUT ;
    USE SIGNAL ;
    SHAPE ABUTMENT ;
    PORT
      LAYER M4 ;
      RECT 224.856 96.816 225.048 96.840 ;
    END
  END link_in[387]
  PIN link_in[388]
    DIRECTION INPUT ;
    USE SIGNAL ;
    SHAPE ABUTMENT ;
    PORT
      LAYER M4 ;
      RECT 224.856 96.912 225.048 96.936 ;
    END
  END link_in[388]
  PIN link_in[389]
    DIRECTION INPUT ;
    USE SIGNAL ;
    SHAPE ABUTMENT ;
    PORT
      LAYER M4 ;
      RECT 224.856 97.008 225.048 97.032 ;
    END
  END link_in[389]
  PIN link_in[390]
    DIRECTION INPUT ;
    USE SIGNAL ;
    SHAPE ABUTMENT ;
    PORT
      LAYER M4 ;
      RECT 224.856 97.104 225.048 97.128 ;
    END
  END link_in[390]
  PIN link_in[391]
    DIRECTION INPUT ;
    USE SIGNAL ;
    SHAPE ABUTMENT ;
    PORT
      LAYER M4 ;
      RECT 224.856 97.200 225.048 97.224 ;
    END
  END link_in[391]
  PIN link_in[392]
    DIRECTION INPUT ;
    USE SIGNAL ;
    SHAPE ABUTMENT ;
    PORT
      LAYER M4 ;
      RECT 224.856 97.344 225.048 97.368 ;
    END
  END link_in[392]
  PIN link_in[393]
    DIRECTION INPUT ;
    USE SIGNAL ;
    SHAPE ABUTMENT ;
    PORT
      LAYER M4 ;
      RECT 224.856 97.440 225.048 97.464 ;
    END
  END link_in[393]
  PIN link_in[394]
    DIRECTION INPUT ;
    USE SIGNAL ;
    SHAPE ABUTMENT ;
    PORT
      LAYER M4 ;
      RECT 224.856 97.536 225.048 97.560 ;
    END
  END link_in[394]
  PIN link_in[395]
    DIRECTION INPUT ;
    USE SIGNAL ;
    SHAPE ABUTMENT ;
    PORT
      LAYER M4 ;
      RECT 224.856 97.632 225.048 97.656 ;
    END
  END link_in[395]
  PIN link_in[396]
    DIRECTION INPUT ;
    USE SIGNAL ;
    SHAPE ABUTMENT ;
    PORT
      LAYER M4 ;
      RECT 224.856 97.776 225.048 97.800 ;
    END
  END link_in[396]
  PIN link_in[397]
    DIRECTION INPUT ;
    USE SIGNAL ;
    SHAPE ABUTMENT ;
    PORT
      LAYER M4 ;
      RECT 224.856 97.872 225.048 97.896 ;
    END
  END link_in[397]
  PIN link_in[398]
    DIRECTION INPUT ;
    USE SIGNAL ;
    SHAPE ABUTMENT ;
    PORT
      LAYER M4 ;
      RECT 224.856 97.968 225.048 97.992 ;
    END
  END link_in[398]
  PIN link_in[399]
    DIRECTION INPUT ;
    USE SIGNAL ;
    SHAPE ABUTMENT ;
    PORT
      LAYER M4 ;
      RECT 224.856 98.064 225.048 98.088 ;
    END
  END link_in[399]
  PIN link_in[400]
    DIRECTION INPUT ;
    USE SIGNAL ;
    SHAPE ABUTMENT ;
    PORT
      LAYER M4 ;
      RECT 224.856 98.208 225.048 98.232 ;
    END
  END link_in[400]
  PIN link_in[401]
    DIRECTION INPUT ;
    USE SIGNAL ;
    SHAPE ABUTMENT ;
    PORT
      LAYER M4 ;
      RECT 224.856 98.304 225.048 98.328 ;
    END
  END link_in[401]
  PIN link_in[402]
    DIRECTION INPUT ;
    USE SIGNAL ;
    SHAPE ABUTMENT ;
    PORT
      LAYER M4 ;
      RECT 224.856 98.400 225.048 98.424 ;
    END
  END link_in[402]
  PIN link_in[403]
    DIRECTION INPUT ;
    USE SIGNAL ;
    SHAPE ABUTMENT ;
    PORT
      LAYER M4 ;
      RECT 224.856 98.496 225.048 98.520 ;
    END
  END link_in[403]
  PIN link_in[404]
    DIRECTION INPUT ;
    USE SIGNAL ;
    SHAPE ABUTMENT ;
    PORT
      LAYER M4 ;
      RECT 224.856 98.640 225.048 98.664 ;
    END
  END link_in[404]
  PIN link_in[405]
    DIRECTION INPUT ;
    USE SIGNAL ;
    SHAPE ABUTMENT ;
    PORT
      LAYER M4 ;
      RECT 224.856 98.736 225.048 98.760 ;
    END
  END link_in[405]
  PIN link_in[406]
    DIRECTION INPUT ;
    USE SIGNAL ;
    SHAPE ABUTMENT ;
    PORT
      LAYER M4 ;
      RECT 224.856 98.832 225.048 98.856 ;
    END
  END link_in[406]
  PIN link_in[407]
    DIRECTION INPUT ;
    USE SIGNAL ;
    SHAPE ABUTMENT ;
    PORT
      LAYER M4 ;
      RECT 224.856 98.928 225.048 98.952 ;
    END
  END link_in[407]
  PIN link_in[408]
    DIRECTION INPUT ;
    USE SIGNAL ;
    SHAPE ABUTMENT ;
    PORT
      LAYER M4 ;
      RECT 224.856 99.024 225.048 99.048 ;
    END
  END link_in[408]
  PIN link_in[409]
    DIRECTION INPUT ;
    USE SIGNAL ;
    SHAPE ABUTMENT ;
    PORT
      LAYER M4 ;
      RECT 224.856 99.168 225.048 99.192 ;
    END
  END link_in[409]
  PIN link_in[410]
    DIRECTION INPUT ;
    USE SIGNAL ;
    SHAPE ABUTMENT ;
    PORT
      LAYER M4 ;
      RECT 224.856 99.264 225.048 99.288 ;
    END
  END link_in[410]
  PIN link_in[411]
    DIRECTION INPUT ;
    USE SIGNAL ;
    SHAPE ABUTMENT ;
    PORT
      LAYER M4 ;
      RECT 224.856 99.360 225.048 99.384 ;
    END
  END link_in[411]
  PIN link_in[412]
    DIRECTION INPUT ;
    USE SIGNAL ;
    SHAPE ABUTMENT ;
    PORT
      LAYER M4 ;
      RECT 224.856 99.456 225.048 99.480 ;
    END
  END link_in[412]
  PIN link_in[413]
    DIRECTION INPUT ;
    USE SIGNAL ;
    SHAPE ABUTMENT ;
    PORT
      LAYER M4 ;
      RECT 224.856 99.600 225.048 99.624 ;
    END
  END link_in[413]
  PIN link_in[414]
    DIRECTION INPUT ;
    USE SIGNAL ;
    SHAPE ABUTMENT ;
    PORT
      LAYER M4 ;
      RECT 224.856 99.696 225.048 99.720 ;
    END
  END link_in[414]
  PIN link_in[415]
    DIRECTION INPUT ;
    USE SIGNAL ;
    SHAPE ABUTMENT ;
    PORT
      LAYER M4 ;
      RECT 224.856 99.792 225.048 99.816 ;
    END
  END link_in[415]
  PIN link_in[416]
    DIRECTION INPUT ;
    USE SIGNAL ;
    SHAPE ABUTMENT ;
    PORT
      LAYER M4 ;
      RECT 224.856 99.888 225.048 99.912 ;
    END
  END link_in[416]
  PIN link_in[417]
    DIRECTION INPUT ;
    USE SIGNAL ;
    SHAPE ABUTMENT ;
    PORT
      LAYER M4 ;
      RECT 224.856 100.032 225.048 100.056 ;
    END
  END link_in[417]
  PIN link_in[418]
    DIRECTION INPUT ;
    USE SIGNAL ;
    SHAPE ABUTMENT ;
    PORT
      LAYER M4 ;
      RECT 224.856 100.128 225.048 100.152 ;
    END
  END link_in[418]
  PIN link_in[419]
    DIRECTION INPUT ;
    USE SIGNAL ;
    SHAPE ABUTMENT ;
    PORT
      LAYER M4 ;
      RECT 224.856 100.224 225.048 100.248 ;
    END
  END link_in[419]
  PIN link_in[420]
    DIRECTION INPUT ;
    USE SIGNAL ;
    SHAPE ABUTMENT ;
    PORT
      LAYER M4 ;
      RECT 224.856 100.320 225.048 100.344 ;
    END
  END link_in[420]
  PIN link_in[421]
    DIRECTION INPUT ;
    USE SIGNAL ;
    SHAPE ABUTMENT ;
    PORT
      LAYER M4 ;
      RECT 224.856 100.416 225.048 100.440 ;
    END
  END link_in[421]
  PIN link_in[422]
    DIRECTION INPUT ;
    USE SIGNAL ;
    SHAPE ABUTMENT ;
    PORT
      LAYER M4 ;
      RECT 224.856 100.560 225.048 100.584 ;
    END
  END link_in[422]
  PIN link_in[423]
    DIRECTION INPUT ;
    USE SIGNAL ;
    SHAPE ABUTMENT ;
    PORT
      LAYER M4 ;
      RECT 224.856 100.656 225.048 100.680 ;
    END
  END link_in[423]
  PIN link_in[424]
    DIRECTION INPUT ;
    USE SIGNAL ;
    SHAPE ABUTMENT ;
    PORT
      LAYER M4 ;
      RECT 224.856 100.752 225.048 100.776 ;
    END
  END link_in[424]
  PIN link_in[425]
    DIRECTION INPUT ;
    USE SIGNAL ;
    SHAPE ABUTMENT ;
    PORT
      LAYER M4 ;
      RECT 224.856 100.848 225.048 100.872 ;
    END
  END link_in[425]
  PIN link_in[426]
    DIRECTION INPUT ;
    USE SIGNAL ;
    SHAPE ABUTMENT ;
    PORT
      LAYER M4 ;
      RECT 224.856 100.992 225.048 101.016 ;
    END
  END link_in[426]
  PIN link_in[427]
    DIRECTION INPUT ;
    USE SIGNAL ;
    SHAPE ABUTMENT ;
    PORT
      LAYER M4 ;
      RECT 224.856 101.088 225.048 101.112 ;
    END
  END link_in[427]
  PIN link_in[428]
    DIRECTION INPUT ;
    USE SIGNAL ;
    SHAPE ABUTMENT ;
    PORT
      LAYER M4 ;
      RECT 224.856 101.184 225.048 101.208 ;
    END
  END link_in[428]
  PIN link_in[429]
    DIRECTION INPUT ;
    USE SIGNAL ;
    SHAPE ABUTMENT ;
    PORT
      LAYER M4 ;
      RECT 224.856 101.280 225.048 101.304 ;
    END
  END link_in[429]
  PIN link_in[430]
    DIRECTION INPUT ;
    USE SIGNAL ;
    SHAPE ABUTMENT ;
    PORT
      LAYER M4 ;
      RECT 224.856 101.424 225.048 101.448 ;
    END
  END link_in[430]
  PIN link_in[431]
    DIRECTION INPUT ;
    USE SIGNAL ;
    SHAPE ABUTMENT ;
    PORT
      LAYER M4 ;
      RECT 224.856 101.520 225.048 101.544 ;
    END
  END link_in[431]
  PIN link_in[432]
    DIRECTION INPUT ;
    USE SIGNAL ;
    SHAPE ABUTMENT ;
    PORT
      LAYER M4 ;
      RECT 224.856 101.616 225.048 101.640 ;
    END
  END link_in[432]
  PIN link_in[433]
    DIRECTION INPUT ;
    USE SIGNAL ;
    SHAPE ABUTMENT ;
    PORT
      LAYER M4 ;
      RECT 224.856 101.712 225.048 101.736 ;
    END
  END link_in[433]
  PIN link_in[434]
    DIRECTION INPUT ;
    USE SIGNAL ;
    SHAPE ABUTMENT ;
    PORT
      LAYER M4 ;
      RECT 224.856 101.808 225.048 101.832 ;
    END
  END link_in[434]
  PIN link_in[435]
    DIRECTION INPUT ;
    USE SIGNAL ;
    SHAPE ABUTMENT ;
    PORT
      LAYER M4 ;
      RECT 224.856 101.952 225.048 101.976 ;
    END
  END link_in[435]
  PIN link_in[436]
    DIRECTION INPUT ;
    USE SIGNAL ;
    SHAPE ABUTMENT ;
    PORT
      LAYER M4 ;
      RECT 224.856 102.048 225.048 102.072 ;
    END
  END link_in[436]
  PIN link_in[437]
    DIRECTION INPUT ;
    USE SIGNAL ;
    SHAPE ABUTMENT ;
    PORT
      LAYER M4 ;
      RECT 224.856 102.144 225.048 102.168 ;
    END
  END link_in[437]
  PIN link_in[438]
    DIRECTION INPUT ;
    USE SIGNAL ;
    SHAPE ABUTMENT ;
    PORT
      LAYER M4 ;
      RECT 224.856 102.240 225.048 102.264 ;
    END
  END link_in[438]
  PIN link_in[439]
    DIRECTION INPUT ;
    USE SIGNAL ;
    SHAPE ABUTMENT ;
    PORT
      LAYER M4 ;
      RECT 224.856 102.384 225.048 102.408 ;
    END
  END link_in[439]
  PIN link_in[440]
    DIRECTION INPUT ;
    USE SIGNAL ;
    SHAPE ABUTMENT ;
    PORT
      LAYER M4 ;
      RECT 224.856 102.480 225.048 102.504 ;
    END
  END link_in[440]
  PIN link_in[441]
    DIRECTION INPUT ;
    USE SIGNAL ;
    SHAPE ABUTMENT ;
    PORT
      LAYER M4 ;
      RECT 224.856 102.576 225.048 102.600 ;
    END
  END link_in[441]
  PIN link_in[442]
    DIRECTION INPUT ;
    USE SIGNAL ;
    SHAPE ABUTMENT ;
    PORT
      LAYER M4 ;
      RECT 224.856 102.672 225.048 102.696 ;
    END
  END link_in[442]
  PIN link_in[443]
    DIRECTION INPUT ;
    USE SIGNAL ;
    SHAPE ABUTMENT ;
    PORT
      LAYER M4 ;
      RECT 224.856 102.816 225.048 102.840 ;
    END
  END link_in[443]
  PIN link_in[444]
    DIRECTION INPUT ;
    USE SIGNAL ;
    SHAPE ABUTMENT ;
    PORT
      LAYER M4 ;
      RECT 224.856 102.912 225.048 102.936 ;
    END
  END link_in[444]
  PIN link_in[445]
    DIRECTION INPUT ;
    USE SIGNAL ;
    SHAPE ABUTMENT ;
    PORT
      LAYER M4 ;
      RECT 224.856 103.008 225.048 103.032 ;
    END
  END link_in[445]
  PIN link_in[446]
    DIRECTION INPUT ;
    USE SIGNAL ;
    SHAPE ABUTMENT ;
    PORT
      LAYER M4 ;
      RECT 224.856 103.104 225.048 103.128 ;
    END
  END link_in[446]
  PIN link_in[447]
    DIRECTION INPUT ;
    USE SIGNAL ;
    SHAPE ABUTMENT ;
    PORT
      LAYER M4 ;
      RECT 224.856 103.200 225.048 103.224 ;
    END
  END link_in[447]
  PIN link_in[448]
    DIRECTION INPUT ;
    USE SIGNAL ;
    SHAPE ABUTMENT ;
    PORT
      LAYER M4 ;
      RECT 224.856 103.344 225.048 103.368 ;
    END
  END link_in[448]
  PIN link_in[449]
    DIRECTION INPUT ;
    USE SIGNAL ;
    SHAPE ABUTMENT ;
    PORT
      LAYER M4 ;
      RECT 224.856 103.440 225.048 103.464 ;
    END
  END link_in[449]
  PIN link_in[450]
    DIRECTION INPUT ;
    USE SIGNAL ;
    SHAPE ABUTMENT ;
    PORT
      LAYER M4 ;
      RECT 224.856 103.536 225.048 103.560 ;
    END
  END link_in[450]
  PIN link_in[451]
    DIRECTION INPUT ;
    USE SIGNAL ;
    SHAPE ABUTMENT ;
    PORT
      LAYER M4 ;
      RECT 224.856 103.632 225.048 103.656 ;
    END
  END link_in[451]
  PIN link_in[452]
    DIRECTION INPUT ;
    USE SIGNAL ;
    SHAPE ABUTMENT ;
    PORT
      LAYER M4 ;
      RECT 224.856 103.776 225.048 103.800 ;
    END
  END link_in[452]
  PIN link_in[453]
    DIRECTION INPUT ;
    USE SIGNAL ;
    SHAPE ABUTMENT ;
    PORT
      LAYER M4 ;
      RECT 224.856 103.872 225.048 103.896 ;
    END
  END link_in[453]
  PIN link_in[454]
    DIRECTION INPUT ;
    USE SIGNAL ;
    SHAPE ABUTMENT ;
    PORT
      LAYER M4 ;
      RECT 224.856 103.968 225.048 103.992 ;
    END
  END link_in[454]
  PIN link_in[455]
    DIRECTION INPUT ;
    USE SIGNAL ;
    SHAPE ABUTMENT ;
    PORT
      LAYER M4 ;
      RECT 224.856 104.064 225.048 104.088 ;
    END
  END link_in[455]
  PIN link_in[456]
    DIRECTION INPUT ;
    USE SIGNAL ;
    SHAPE ABUTMENT ;
    PORT
      LAYER M4 ;
      RECT 224.856 104.208 225.048 104.232 ;
    END
  END link_in[456]
  PIN link_in[457]
    DIRECTION INPUT ;
    USE SIGNAL ;
    SHAPE ABUTMENT ;
    PORT
      LAYER M4 ;
      RECT 224.856 104.304 225.048 104.328 ;
    END
  END link_in[457]
  PIN link_in[458]
    DIRECTION INPUT ;
    USE SIGNAL ;
    SHAPE ABUTMENT ;
    PORT
      LAYER M4 ;
      RECT 224.856 104.400 225.048 104.424 ;
    END
  END link_in[458]
  PIN link_in[459]
    DIRECTION INPUT ;
    USE SIGNAL ;
    SHAPE ABUTMENT ;
    PORT
      LAYER M4 ;
      RECT 224.856 104.496 225.048 104.520 ;
    END
  END link_in[459]
  PIN link_in[460]
    DIRECTION INPUT ;
    USE SIGNAL ;
    SHAPE ABUTMENT ;
    PORT
      LAYER M4 ;
      RECT 224.856 104.592 225.048 104.616 ;
    END
  END link_in[460]
  PIN link_in[461]
    DIRECTION INPUT ;
    USE SIGNAL ;
    SHAPE ABUTMENT ;
    PORT
      LAYER M4 ;
      RECT 224.856 104.736 225.048 104.760 ;
    END
  END link_in[461]
  PIN link_in[462]
    DIRECTION INPUT ;
    USE SIGNAL ;
    SHAPE ABUTMENT ;
    PORT
      LAYER M4 ;
      RECT 224.856 104.832 225.048 104.856 ;
    END
  END link_in[462]
  PIN link_in[463]
    DIRECTION INPUT ;
    USE SIGNAL ;
    SHAPE ABUTMENT ;
    PORT
      LAYER M4 ;
      RECT 224.856 104.928 225.048 104.952 ;
    END
  END link_in[463]
  PIN link_in[464]
    DIRECTION INPUT ;
    USE SIGNAL ;
    SHAPE ABUTMENT ;
    PORT
      LAYER M4 ;
      RECT 224.856 105.024 225.048 105.048 ;
    END
  END link_in[464]
  PIN link_in[465]
    DIRECTION INPUT ;
    USE SIGNAL ;
    SHAPE ABUTMENT ;
    PORT
      LAYER M4 ;
      RECT 224.856 105.168 225.048 105.192 ;
    END
  END link_in[465]
  PIN link_in[466]
    DIRECTION INPUT ;
    USE SIGNAL ;
    SHAPE ABUTMENT ;
    PORT
      LAYER M4 ;
      RECT 224.856 105.264 225.048 105.288 ;
    END
  END link_in[466]
  PIN link_in[467]
    DIRECTION INPUT ;
    USE SIGNAL ;
    SHAPE ABUTMENT ;
    PORT
      LAYER M4 ;
      RECT 224.856 105.360 225.048 105.384 ;
    END
  END link_in[467]
  PIN link_in[468]
    DIRECTION INPUT ;
    USE SIGNAL ;
    SHAPE ABUTMENT ;
    PORT
      LAYER M4 ;
      RECT 224.856 105.456 225.048 105.480 ;
    END
  END link_in[468]
  PIN link_in[469]
    DIRECTION INPUT ;
    USE SIGNAL ;
    SHAPE ABUTMENT ;
    PORT
      LAYER M4 ;
      RECT 224.856 105.600 225.048 105.624 ;
    END
  END link_in[469]
  PIN link_in[470]
    DIRECTION INPUT ;
    USE SIGNAL ;
    SHAPE ABUTMENT ;
    PORT
      LAYER M4 ;
      RECT 224.856 105.696 225.048 105.720 ;
    END
  END link_in[470]
  PIN link_in[471]
    DIRECTION INPUT ;
    USE SIGNAL ;
    SHAPE ABUTMENT ;
    PORT
      LAYER M4 ;
      RECT 224.856 105.792 225.048 105.816 ;
    END
  END link_in[471]
  PIN link_in[472]
    DIRECTION INPUT ;
    USE SIGNAL ;
    SHAPE ABUTMENT ;
    PORT
      LAYER M4 ;
      RECT 224.856 105.888 225.048 105.912 ;
    END
  END link_in[472]
  PIN link_in[473]
    DIRECTION INPUT ;
    USE SIGNAL ;
    SHAPE ABUTMENT ;
    PORT
      LAYER M4 ;
      RECT 224.856 105.984 225.048 106.008 ;
    END
  END link_in[473]
  PIN link_in[474]
    DIRECTION INPUT ;
    USE SIGNAL ;
    SHAPE ABUTMENT ;
    PORT
      LAYER M4 ;
      RECT 224.856 106.128 225.048 106.152 ;
    END
  END link_in[474]
  PIN link_in[475]
    DIRECTION INPUT ;
    USE SIGNAL ;
    SHAPE ABUTMENT ;
    PORT
      LAYER M4 ;
      RECT 224.856 106.224 225.048 106.248 ;
    END
  END link_in[475]
  PIN link_in[476]
    DIRECTION INPUT ;
    USE SIGNAL ;
    SHAPE ABUTMENT ;
    PORT
      LAYER M4 ;
      RECT 224.856 106.320 225.048 106.344 ;
    END
  END link_in[476]
  PIN link_in[477]
    DIRECTION INPUT ;
    USE SIGNAL ;
    SHAPE ABUTMENT ;
    PORT
      LAYER M4 ;
      RECT 224.856 106.416 225.048 106.440 ;
    END
  END link_in[477]
  PIN link_in[478]
    DIRECTION INPUT ;
    USE SIGNAL ;
    SHAPE ABUTMENT ;
    PORT
      LAYER M4 ;
      RECT 224.856 106.560 225.048 106.584 ;
    END
  END link_in[478]
  PIN link_in[479]
    DIRECTION INPUT ;
    USE SIGNAL ;
    SHAPE ABUTMENT ;
    PORT
      LAYER M4 ;
      RECT 224.856 106.656 225.048 106.680 ;
    END
  END link_in[479]
  PIN link_in[480]
    DIRECTION INPUT ;
    USE SIGNAL ;
    SHAPE ABUTMENT ;
    PORT
      LAYER M4 ;
      RECT 224.856 106.752 225.048 106.776 ;
    END
  END link_in[480]
  PIN link_in[481]
    DIRECTION INPUT ;
    USE SIGNAL ;
    SHAPE ABUTMENT ;
    PORT
      LAYER M4 ;
      RECT 224.856 106.848 225.048 106.872 ;
    END
  END link_in[481]
  PIN link_in[482]
    DIRECTION INPUT ;
    USE SIGNAL ;
    SHAPE ABUTMENT ;
    PORT
      LAYER M4 ;
      RECT 224.856 106.992 225.048 107.016 ;
    END
  END link_in[482]
  PIN link_in[483]
    DIRECTION INPUT ;
    USE SIGNAL ;
    SHAPE ABUTMENT ;
    PORT
      LAYER M4 ;
      RECT 224.856 107.088 225.048 107.112 ;
    END
  END link_in[483]
  PIN link_in[484]
    DIRECTION INPUT ;
    USE SIGNAL ;
    SHAPE ABUTMENT ;
    PORT
      LAYER M4 ;
      RECT 224.856 107.184 225.048 107.208 ;
    END
  END link_in[484]
  PIN link_in[485]
    DIRECTION INPUT ;
    USE SIGNAL ;
    SHAPE ABUTMENT ;
    PORT
      LAYER M4 ;
      RECT 224.856 107.280 225.048 107.304 ;
    END
  END link_in[485]
  PIN link_in[486]
    DIRECTION INPUT ;
    USE SIGNAL ;
    SHAPE ABUTMENT ;
    PORT
      LAYER M4 ;
      RECT 224.856 107.376 225.048 107.400 ;
    END
  END link_in[486]
  PIN link_in[487]
    DIRECTION INPUT ;
    USE SIGNAL ;
    SHAPE ABUTMENT ;
    PORT
      LAYER M4 ;
      RECT 224.856 107.520 225.048 107.544 ;
    END
  END link_in[487]
  PIN link_in[488]
    DIRECTION INPUT ;
    USE SIGNAL ;
    SHAPE ABUTMENT ;
    PORT
      LAYER M4 ;
      RECT 224.856 107.616 225.048 107.640 ;
    END
  END link_in[488]
  PIN link_in[489]
    DIRECTION INPUT ;
    USE SIGNAL ;
    SHAPE ABUTMENT ;
    PORT
      LAYER M4 ;
      RECT 224.856 107.712 225.048 107.736 ;
    END
  END link_in[489]
  PIN link_in[490]
    DIRECTION INPUT ;
    USE SIGNAL ;
    SHAPE ABUTMENT ;
    PORT
      LAYER M4 ;
      RECT 224.856 107.808 225.048 107.832 ;
    END
  END link_in[490]
  PIN link_in[491]
    DIRECTION INPUT ;
    USE SIGNAL ;
    SHAPE ABUTMENT ;
    PORT
      LAYER M4 ;
      RECT 224.856 107.952 225.048 107.976 ;
    END
  END link_in[491]
  PIN link_in[492]
    DIRECTION INPUT ;
    USE SIGNAL ;
    SHAPE ABUTMENT ;
    PORT
      LAYER M4 ;
      RECT 224.856 108.048 225.048 108.072 ;
    END
  END link_in[492]
  PIN link_in[493]
    DIRECTION INPUT ;
    USE SIGNAL ;
    SHAPE ABUTMENT ;
    PORT
      LAYER M4 ;
      RECT 224.856 108.144 225.048 108.168 ;
    END
  END link_in[493]
  PIN link_in[494]
    DIRECTION INPUT ;
    USE SIGNAL ;
    SHAPE ABUTMENT ;
    PORT
      LAYER M4 ;
      RECT 224.856 108.240 225.048 108.264 ;
    END
  END link_in[494]
  PIN link_in[495]
    DIRECTION INPUT ;
    USE SIGNAL ;
    SHAPE ABUTMENT ;
    PORT
      LAYER M4 ;
      RECT 224.856 108.384 225.048 108.408 ;
    END
  END link_in[495]
  PIN link_in[496]
    DIRECTION INPUT ;
    USE SIGNAL ;
    SHAPE ABUTMENT ;
    PORT
      LAYER M4 ;
      RECT 224.856 108.480 225.048 108.504 ;
    END
  END link_in[496]
  PIN link_in[497]
    DIRECTION INPUT ;
    USE SIGNAL ;
    SHAPE ABUTMENT ;
    PORT
      LAYER M4 ;
      RECT 224.856 108.576 225.048 108.600 ;
    END
  END link_in[497]
  PIN link_in[498]
    DIRECTION INPUT ;
    USE SIGNAL ;
    SHAPE ABUTMENT ;
    PORT
      LAYER M4 ;
      RECT 224.856 108.672 225.048 108.696 ;
    END
  END link_in[498]
  PIN link_in[499]
    DIRECTION INPUT ;
    USE SIGNAL ;
    SHAPE ABUTMENT ;
    PORT
      LAYER M4 ;
      RECT 224.856 108.768 225.048 108.792 ;
    END
  END link_in[499]
  PIN link_in[500]
    DIRECTION INPUT ;
    USE SIGNAL ;
    SHAPE ABUTMENT ;
    PORT
      LAYER M4 ;
      RECT 224.856 108.912 225.048 108.936 ;
    END
  END link_in[500]
  PIN link_in[501]
    DIRECTION INPUT ;
    USE SIGNAL ;
    SHAPE ABUTMENT ;
    PORT
      LAYER M4 ;
      RECT 224.856 109.008 225.048 109.032 ;
    END
  END link_in[501]
  PIN link_in[502]
    DIRECTION INPUT ;
    USE SIGNAL ;
    SHAPE ABUTMENT ;
    PORT
      LAYER M4 ;
      RECT 224.856 109.104 225.048 109.128 ;
    END
  END link_in[502]
  PIN link_in[503]
    DIRECTION INPUT ;
    USE SIGNAL ;
    SHAPE ABUTMENT ;
    PORT
      LAYER M4 ;
      RECT 224.856 109.200 225.048 109.224 ;
    END
  END link_in[503]
  PIN link_in[504]
    DIRECTION INPUT ;
    USE SIGNAL ;
    SHAPE ABUTMENT ;
    PORT
      LAYER M4 ;
      RECT 224.856 109.344 225.048 109.368 ;
    END
  END link_in[504]
  PIN link_in[505]
    DIRECTION INPUT ;
    USE SIGNAL ;
    SHAPE ABUTMENT ;
    PORT
      LAYER M4 ;
      RECT 224.856 109.440 225.048 109.464 ;
    END
  END link_in[505]
  PIN link_in[506]
    DIRECTION INPUT ;
    USE SIGNAL ;
    SHAPE ABUTMENT ;
    PORT
      LAYER M4 ;
      RECT 224.856 109.536 225.048 109.560 ;
    END
  END link_in[506]
  PIN link_in[507]
    DIRECTION INPUT ;
    USE SIGNAL ;
    SHAPE ABUTMENT ;
    PORT
      LAYER M4 ;
      RECT 224.856 109.632 225.048 109.656 ;
    END
  END link_in[507]
  PIN link_in[508]
    DIRECTION INPUT ;
    USE SIGNAL ;
    SHAPE ABUTMENT ;
    PORT
      LAYER M4 ;
      RECT 224.856 109.776 225.048 109.800 ;
    END
  END link_in[508]
  PIN link_in[509]
    DIRECTION INPUT ;
    USE SIGNAL ;
    SHAPE ABUTMENT ;
    PORT
      LAYER M4 ;
      RECT 224.856 109.872 225.048 109.896 ;
    END
  END link_in[509]
  PIN link_in[510]
    DIRECTION INPUT ;
    USE SIGNAL ;
    SHAPE ABUTMENT ;
    PORT
      LAYER M4 ;
      RECT 224.856 109.968 225.048 109.992 ;
    END
  END link_in[510]
  PIN link_in[511]
    DIRECTION INPUT ;
    USE SIGNAL ;
    SHAPE ABUTMENT ;
    PORT
      LAYER M4 ;
      RECT 224.856 110.064 225.048 110.088 ;
    END
  END link_in[511]
  PIN VSS
    DIRECTION INOUT ;
    USE GROUND ;
    PORT
      LAYER M4 ;
      RECT 0.492 1.200 224.556 1.296 ;
      RECT 0.492 3.600 224.556 3.696 ;
      RECT 0.492 6.000 224.556 6.096 ;
      RECT 0.492 8.400 224.556 8.496 ;
      RECT 0.492 10.800 224.556 10.896 ;
      RECT 0.492 13.200 224.556 13.296 ;
      RECT 0.492 15.600 224.556 15.696 ;
      RECT 0.492 18.000 224.556 18.096 ;
      RECT 0.492 20.400 224.556 20.496 ;
      RECT 0.492 22.800 224.556 22.896 ;
      RECT 0.492 25.200 224.556 25.296 ;
      RECT 0.492 27.600 224.556 27.696 ;
      RECT 0.492 30.000 224.556 30.096 ;
      RECT 0.492 32.400 224.556 32.496 ;
      RECT 0.492 34.800 224.556 34.896 ;
      RECT 0.492 37.200 224.556 37.296 ;
      RECT 0.492 39.600 224.556 39.696 ;
      RECT 0.492 42.000 224.556 42.096 ;
      RECT 0.492 44.400 224.556 44.496 ;
      RECT 0.492 46.800 224.556 46.896 ;
      RECT 0.492 49.200 224.556 49.296 ;
      RECT 0.492 51.600 224.556 51.696 ;
      RECT 0.492 54.000 224.556 54.096 ;
      RECT 0.492 56.400 224.556 56.496 ;
      RECT 0.492 58.800 224.556 58.896 ;
      RECT 0.492 61.200 224.556 61.296 ;
      RECT 0.492 63.600 224.556 63.696 ;
      RECT 0.492 66.000 224.556 66.096 ;
      RECT 0.492 68.400 224.556 68.496 ;
      RECT 0.492 70.800 224.556 70.896 ;
      RECT 0.492 73.200 224.556 73.296 ;
      RECT 0.492 75.600 224.556 75.696 ;
      RECT 0.492 78.000 224.556 78.096 ;
      RECT 0.492 80.400 224.556 80.496 ;
      RECT 0.492 82.800 224.556 82.896 ;
      RECT 0.492 85.200 224.556 85.296 ;
      RECT 0.492 87.600 224.556 87.696 ;
      RECT 0.492 90.000 224.556 90.096 ;
      RECT 0.492 92.400 224.556 92.496 ;
      RECT 0.492 94.800 224.556 94.896 ;
      RECT 0.492 97.200 224.556 97.296 ;
      RECT 0.492 99.600 224.556 99.696 ;
      RECT 0.492 102.000 224.556 102.096 ;
      RECT 0.492 104.400 224.556 104.496 ;
      RECT 0.492 106.800 224.556 106.896 ;
      RECT 0.492 109.200 224.556 109.296 ;
    END
  END VSS
  PIN VDD
    DIRECTION INOUT ;
    USE POWER ;
    PORT
      LAYER M4 ;
      RECT 0.492 2.400 224.556 2.496 ;
      RECT 0.492 4.800 224.556 4.896 ;
      RECT 0.492 7.200 224.556 7.296 ;
      RECT 0.492 9.600 224.556 9.696 ;
      RECT 0.492 12.000 224.556 12.096 ;
      RECT 0.492 14.400 224.556 14.496 ;
      RECT 0.492 16.800 224.556 16.896 ;
      RECT 0.492 19.200 224.556 19.296 ;
      RECT 0.492 21.600 224.556 21.696 ;
      RECT 0.492 24.000 224.556 24.096 ;
      RECT 0.492 26.400 224.556 26.496 ;
      RECT 0.492 28.800 224.556 28.896 ;
      RECT 0.492 31.200 224.556 31.296 ;
      RECT 0.492 33.600 224.556 33.696 ;
      RECT 0.492 36.000 224.556 36.096 ;
      RECT 0.492 38.400 224.556 38.496 ;
      RECT 0.492 40.800 224.556 40.896 ;
      RECT 0.492 43.200 224.556 43.296 ;
      RECT 0.492 45.600 224.556 45.696 ;
      RECT 0.492 48.000 224.556 48.096 ;
      RECT 0.492 50.400 224.556 50.496 ;
      RECT 0.492 52.800 224.556 52.896 ;
      RECT 0.492 55.200 224.556 55.296 ;
      RECT 0.492 57.600 224.556 57.696 ;
      RECT 0.492 60.000 224.556 60.096 ;
      RECT 0.492 62.400 224.556 62.496 ;
      RECT 0.492 64.800 224.556 64.896 ;
      RECT 0.492 67.200 224.556 67.296 ;
      RECT 0.492 69.600 224.556 69.696 ;
      RECT 0.492 72.000 224.556 72.096 ;
      RECT 0.492 74.400 224.556 74.496 ;
      RECT 0.492 76.800 224.556 76.896 ;
      RECT 0.492 79.200 224.556 79.296 ;
      RECT 0.492 81.600 224.556 81.696 ;
      RECT 0.492 84.000 224.556 84.096 ;
      RECT 0.492 86.400 224.556 86.496 ;
      RECT 0.492 88.800 224.556 88.896 ;
      RECT 0.492 91.200 224.556 91.296 ;
      RECT 0.492 93.600 224.556 93.696 ;
      RECT 0.492 96.000 224.556 96.096 ;
      RECT 0.492 98.400 224.556 98.496 ;
      RECT 0.492 100.800 224.556 100.896 ;
      RECT 0.492 103.200 224.556 103.296 ;
      RECT 0.492 105.600 224.556 105.696 ;
      RECT 0.492 108.000 224.556 108.096 ;
    END
  END VDD
  OBS
    LAYER M1 ;
    RECT 0 0 225.048 110.712 ;
    LAYER M2 ;
    RECT 0 0 225.048 110.712 ;
    LAYER M3 ;
    RECT 0 0 225.048 110.712 ;
    LAYER M4 ;
    RECT 0 0 225.048 110.712 ;
    LAYER M5 ;
    RECT 0 0 225.048 110.712 ;
    LAYER M6 ;
    RECT 0 0 225.048 110.712 ;
  END
END ot_pdie_coll

END LIBRARY
